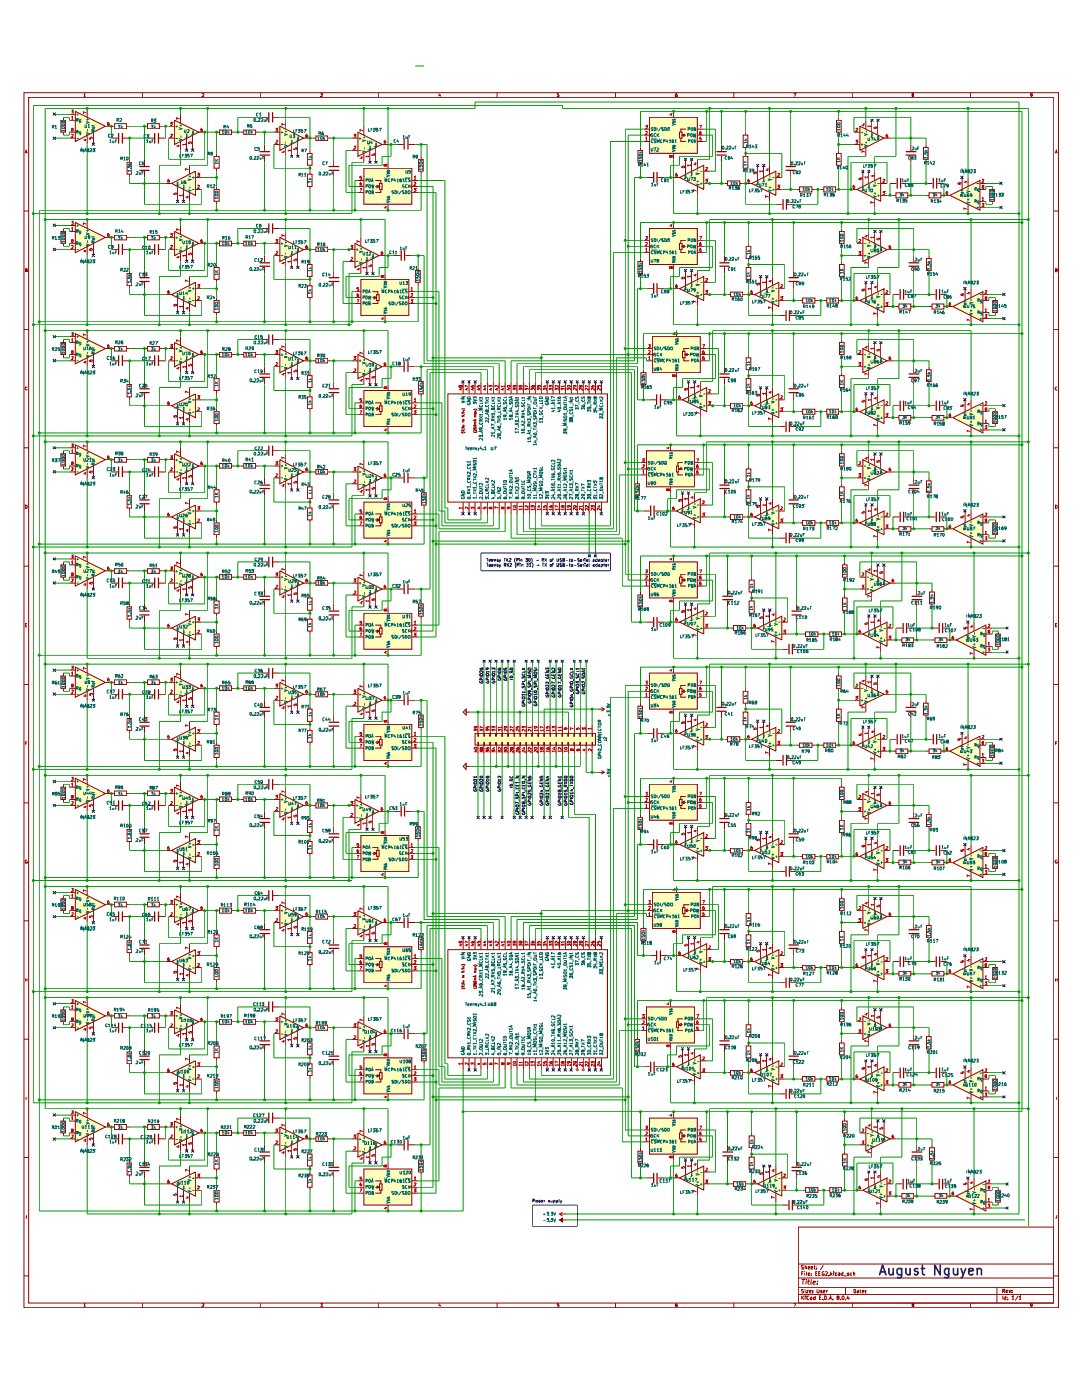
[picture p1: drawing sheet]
<svg xmlns="http://www.w3.org/2000/svg" width="216mm" height="279mm" viewBox="0 0 216 279" stroke-linecap="round" stroke-linejoin="round" font-family="sans-serif">
<g fill="none" stroke="#910000" stroke-width=".2">
<path d="M4.8 18.5h206.4v242.5h-206.4zM5.7 19.4h204.6v240.7h-204.6zM16.7 18.8l.2-.1v.6M16.7 19.3h.4M28.4 18.5v.9M40.3 18.8h.4l-.4 .5h.4M52 18.5v.9M64 18.7h.3l-.2 .2h.2v.3h-.3M75.6 18.5v.9M87.7 18.7l-.1 .4h.3M87.8 18.8v.5M99.2 18.5v.9"/>
<path d="M111.5 18.7h-.3v.2h.3v.3h-.3M122.8 18.5v.9M135.1 18.7h-.2l-.2 .2 .1 .4h.3v-.4l-.4 .1M146.4 18.5v.9M158.4 18.7h.4l-.3 .6M170.1 18.5v.9M182.2 18.9l-.2-.1 .3-.1v.2l-.3 .1 .1 .3h.2l-.1-.4M193.7 18.5v.9M206 18.9l-.4 .1v-.2l.4-.1v.4l-.3 .2M5 30.6l.2-.6 .3 .6M5.1 30.4h.3M210.5 30.6l.3-.6 .1 .6"/>
<path d="M210.6 30.4h.3M4.8 42.1h.9M5 53.9h.4v-.3h-.4v.6h.4l.1-.2-.2-.1M210.3 42.1h.9M210.6 53.9h.3v-.2l-.3-.1v.6h.3v-.2l-.1-.1M4.8 65.7h.9M5.5 77.3h-.5l.1 .5h.4M210.3 65.7h.9M210.9 77.3h-.2a.33 .33 0 0 0-.1 .3 .33 .33 0 0 0 .3 .3v-.1M4.8 89.4h.9M210.3 89.4h.9M4.8 113h.9"/>
<path d="M5 100.8a.35 .35 0 0 1 .5 .3 .35 .35 0 0 1-.5 .4zM210.3 113h.9M210.6 100.8l.3 .2v.3l-.2 .2zM4.8 136.6h.9M5.1 124.8h.2M5.4 124.4h-.3v.7h.3M210.3 136.6h.9M210.6 124.8h.3M210.9 124.4h-.3v.7h.3M5.1 148.4h.2M5.4 148h-.3v.6M210.6 148.4h.3"/>
<path d="M210.9 148h-.3v.6M4.8 160.2h.9M5.4 171.7h-.3l-.1 .5 .5 .1v-.3h-.2M210.3 160.2h.9M210.9 171.7h-.2l-.2 .2 .2 .4h.2v-.3M4.8 183.8h.9M5 195.3v.6M5 195.5h.4M5.4 195.3v.6M210.3 183.8h.9M210.6 195.5h.3M210.6 195.3v.6"/>
<path d="M210.9 195.3v.6M4.8 207.4h.9M5.2 218.9v.6M210.3 207.4h.9M210.8 218.9v.6M4.8 231h.9M210.3 231h.9M4.8 254.6h.9M5.3 242.5v.5l-.2 .1M159.3 244.9h51v15.2h-51zM159.3 258.4h51M159.3 256.9h51"/>
<path d="M159.3 255.1h51M159.3 252.3h51M160 258.6v.8M160 254.1h.2M160 255.4h.6M160.1 259l.3 .4M160.3 255.4l-.1 .9M160.3 257.3l-.4 .1 .4 .4v.1l-.4 .1M160.3 253.8h-.3v.8M160.3 252.6l-.2-.1-.2 .2 .4 .3v.2h-.4M160.4 258.6l-.4 .4M160.6 253.8v.1"/>
<path d="M160.6 254v.6M160.7 258.6v.1M160.7 257.3h.1M160.7 252.9h.2v.4M160.7 252.5v.8M160.7 257.5v.5M160.7 258.9v.5M160.9 255.4h.1M160.9 255.7l-.1 .6M160.9 257.5h.3l-.3 .5h.3M160.9 253.8l.1 .8M161.1 255.7h.4"/>
<path d="M161.2 254.3l.4-.1-.1-.2-.3 .1v.4h.4M161.2 253l.4-.1-.1-.1-.3 .1v.3h.4M161.4 255.4l-.2 .7 .3 .2M161.4 258.7l-.2-.1-.2 .2v.4l.2 .2 .2-.1M161.5 257.8l.3-.1v-.2h-.2l-.1 .4 .3 .1M161.8 259h.2v.4M161.8 253l.4-.1-.1-.1-.3 .1v.3h.4M161.9 255.4v.9M161.9 254.5v.1M161.9 254.1h.1M162 259h-.2l-.1 .2 .1 .2 .2-.1M162.2 257.9v.1"/>
<path d="M162.2 257.6v.1M162.2 255.9h.5l-.1-.2h-.3l-.1 .4v.2h.4M162.4 252.8h.3M162.5 252.5v.7l.2 .1M162.7 259h-.4l.1 .4 .3-.1M162.7 258.6v.8M162.8 254.1h.2M162.9 253.2v.1M162.9 252.9h.1M163 257.3l.1 .7h.3v-.7M163.1 256.2v.1M163.1 253.8h-.3v.8h.3"/>
<path d="M163.2 255.7v.1M163.4 254.1h.2M163.5 259h.3M163.7 253.8h-.3v.8h.3M163.9 258.6h-.4v.8h.4M164 257.6l-.1-.1-.2 .2 .3 .2v.1h-.3M164.2 259.3v.1M164.3 257.8l.3-.1-.1-.2h-.1l-.1 .4 .3 .1M164.3 252.5l-.6 .9M164.4 253.9l-.2-.1-.2 .2v.5h.5v-.3h-.2M164.5 258.6l.4 .2v.4l-.2 .2h-.2zM164.7 253.9l.3-.1 .1 .2-.4 .6h.4"/>
<path d="M165 257.5v.5M165.1 257.5l-.1 .2M165.2 259.3v.1M165.4 254.5v.1M165.5 259.4l.2-.8 .2 .8M165.6 259.1h.3M165.7 253.8v.8M165.8 254.3l.3 .3M166.1 254l-.4 .3M166.2 259.3v.1M166.3 253.8v.1M166.3 254v.6"/>
<path d="M167 254.1h-.3v.4h.3M167.2 259l-.2-.3 .3-.1 .1 .2-.1 .2h-.3v.3l.2 .1 .2-.2-.1-.2M167.3 254.1h.3v.5M167.6 254.2l-.3 .1v.3l.3-.1M167.7 259.3v.1M168.2 258.6a.41 .41 0 0 1 .2 .4 .41 .41 0 0 1-.2 .4l-.2-.2v-.4zM168.2 254.1l-.2-.1-.1 .2 .1 .4 .2-.1M168.2 253.8v.8M168.4 254.6h.6M168.7 259.3v.1M168.7 256.9v1.5M169.2 258.6l-.2 .5h.5"/>
<path d="M169.4 254.1h-.4l.1 .2h.3l-.1 .3-.3-.1M169.4 258.9v.5M170 254.1l-.2-.1-.2 .2 .2 .4 .2-.1M170.3 254.1h.3v.5M170.3 253.8v.8M170.4 257.3l.3 .1-.1 .6h-.2zM171.1 257.6h.2v.4h-.2l-.1-.1 .3-.2M171.6 257.5h.2M171.7 257.3v.6l.1 .1M172.1 257.8l.3-.1-.1-.2-.2 .1v.4h.2M172.7 257.9v.1M172.7 257.6v.1"/>
<path d="M198.9 256.9v3.2M200.1 257.6h.3l.1-.3h-.4v.7M200.1 258.6v.8M200.2 257.6l.3 .4M200.7 259l-.2-.1-.1 .1 .1 .4 .2-.1M200.7 258.6v.8M200.7 257.7l.4-.1-.1-.1-.3 .1v.3l.4 .1M201 259.3v.1M201 259h.1M201.3 257.5l.2 .5 .2-.5M201.9 258.9l.2-.3v.8M201.9 259.4h.4"/>
<path d="M201.9 257.9v.1M201.9 257.6h.1M203.2 258.6l-.6 .9M203.3 258.9l.3-.3v.8M203.3 259.4h.5M210.3 254.6h.9M210.9 242.5v.5l-.3 .1M16.7 260.3l.2-.2v.6M16.7 260.7h.4M28.4 260.1v.9M40.3 260.2h.4l-.4 .5h.4M52 260.1v.9"/>
<path d="M64 260.1h.3l-.2 .3 .2 .1v.2h-.3M75.6 260.1v.9M87.7 260.1l-.1 .5h.3M87.8 260.4v.3M99.2 260.1v.9M111.5 260.1h-.3v.4l.3-.1v.2l-.3 .1M122.8 260.1v.9M135.1 260.1l-.4 .3v.2l.4 .1v-.3l-.4 .1M146.4 260.1v.9M158.4 260.1h.4l-.3 .6M170.1 260.1v.9M182.2 260.4l-.2-.1 .2-.2 .1 .3-.3 .2 .1 .1h.2l-.1-.3"/>
<path d="M193.7 260.1v.9M206 260.4l-.3 .2-.1-.4h.4v.4l-.3 .1"/>
</g>
<g fill="#ffb">
<path d="M71.4 26.4l4.8 2.4-4.8 2.4z"/>
<path d="M72.6 122.4h9.6v7.2h-9.6z"/>
<path d="M71.4 115.2l4.8 2.4-4.8 2.3z"/>
<path d="M72.6 100.2h9.6v7.2h-9.6z"/>
<path d="M71.4 93l4.8 2.4-4.8 2.3z"/>
<path d="M72.6 77.9h9.6v7.2h-9.6z"/>
<path d="M72 55.8h9.6v7.1h-9.6z"/>
<path d="M70.8 48.6l4.8 2.4-4.8 2.4z"/>
<path d="M71.4 70.7l4.8 2.5-4.8 2.4z"/>
<path d="M72.6 33.6h9.6v7.2h-9.6z"/>
<path d="M15 111l6 2.9-6 3.1z"/>
<path d="M34.8 112.7l4.9 2.5-4.9 2.4z"/>
<path d="M15 88.8l6 2.9-6 3.1z"/>
<path d="M34.8 90.6l4.9 2.4-4.9 2.4z"/>
<path d="M34.2 103.2l4.8-2.4v4.7z"/>
<path d="M34.2 125.3l4.8-2.3v4.7z"/>
<path d="M55.8 113.9l4.8 2.5-4.8 2.3z"/>
<path d="M55.8 91.7l4.8 2.5-4.8 2.4z"/>
<path d="M15 66.6l6 3-6 3z"/>
<path d="M34.8 68.4l4.9 2.3-4.9 2.5z"/>
<path d="M34.2 81l4.8-2.4v4.8z"/>
<path d="M55.8 69.6l4.8 2.4-4.8 2.4z"/>
<path d="M15 44.4l6 3-6 3z"/>
<path d="M34.8 46.2l4.9 2.4-4.9 2.4z"/>
<path d="M34.2 58.8l4.8-2.5v4.9z"/>
<path d="M55.8 47.4l4.8 2.4-4.8 2.4z"/>
<path d="M15 22.2l6 3-6 3z"/>
<path d="M34.8 24l4.9 2.4-4.9 2.4z"/>
<path d="M34.2 36.6l4.8-2.4v4.8z"/>
<path d="M55.8 25.2l4.8 2.4-4.8 2.4z"/>
<path d="M150.6 103.2l4.8-2.4v4.7z"/>
<path d="M172.2 91.7l4.8 2.5-4.8 2.4z"/>
<path d="M171.6 104.4l4.8-2.4v4.7z"/>
<path d="M190.1 105.5l6-2.9v6z"/>
<path d="M172.2 69.6l4.8 2.4-4.8 2.4z"/>
<path d="M171.6 82.2l4.8-2.4v4.7z"/>
<path d="M190.1 83.4l6-3v6z"/>
<path d="M150 36.6l4.8-2.4v4.8z"/>
<path d="M171.6 25.2l4.8 2.4-4.8 2.4z"/>
<path d="M171 37.8l4.7-2.4v4.8z"/>
<path d="M189.5 39l6-3v6z"/>
<path d="M150.6 81l4.8-2.4v4.8z"/>
<path d="M150.6 58.8l4.8-2.5v4.9z"/>
<path d="M172.2 47.4l4.8 2.4-4.8 2.4z"/>
<path d="M171.6 60l4.8-2.4v4.8z"/>
<path d="M190.1 61.2l6-3v6z"/>
<path d="M151.2 125.3l4.8-2.3v4.7z"/>
<path d="M172.8 113.9l4.8 2.5-4.8 2.3z"/>
<path d="M172.2 126.5l4.8-2.3v4.8z"/>
<path d="M190.8 127.7l5.9-2.9v6z"/>
<path d="M130.2 67.2h9.5v7.2h-9.5z"/>
<path d="M135.6 35.4l4.8-2.4v4.8z"/>
<path d="M129.6 23.4h9.5v7.2h-9.5z"/>
<path d="M129.6 45.6h9.5v7.2h-9.5z"/>
<path d="M135.6 57.6l4.8-2.4v4.8z"/>
<path d="M136.2 79.8l4.8-2.5v4.9z"/>
<path d="M135 102l4.7-2.5v4.9z"/>
<path d="M129 90h9.6v7.2h-9.6z"/>
<path d="M135.6 124.2l4.8-2.4v4.7z"/>
<path d="M129.6 112.1h9.5v7.2h-9.5z"/>
<path d="M34.8 134.9l4.9 2.5-4.9 2.3z"/>
<path d="M55.8 136.2l4.8 2.4-4.8 2.3z"/>
<path d="M15 133.1l6 3.1-6 2.9z"/>
<path d="M15 155.3l6 3.1-6 2.9z"/>
<path d="M71.4 137.4l4.8 2.3-4.8 2.4z"/>
<path d="M34.2 147.5l4.8-2.3v4.7z"/>
<path d="M34.8 179.4l4.9 2.3-4.9 2.4z"/>
<path d="M34.2 169.7l4.8-2.4v4.9z"/>
<path d="M34.8 157.1l4.9 2.5-4.9 2.3z"/>
<path d="M34.2 191.9l4.8-2.4v4.9z"/>
<path d="M15 221.9l6 3-6 3z"/>
<path d="M34.8 223.7l4.9 2.4-4.9 2.4z"/>
<path d="M34.2 214.1l4.8-2.4v4.8z"/>
<path d="M34.8 201.5l4.9 2.4-4.9 2.4z"/>
<path d="M15 177.5l6 3.1-6 2.9z"/>
<path d="M34.2 236.3l4.8-2.4v4.8z"/>
<path d="M15 199.7l6 3-6 3z"/>
<path d="M72.6 211.1h9.6v7.2h-9.6z"/>
<path d="M55.8 224.9l4.8 2.4-4.8 2.4z"/>
<path d="M55.8 202.7l4.8 2.4-4.8 2.4z"/>
<path d="M71.4 203.9l4.8 2.4-4.8 2.4z"/>
<path d="M72.6 233.3h9.6v7.2h-9.6z"/>
<path d="M71.4 226.1l4.8 2.4-4.8 2.4z"/>
<path d="M72.6 188.9h9.6v7.2h-9.6z"/>
<path d="M72 166.8h9.6v7.1h-9.6z"/>
<path d="M55.8 180.6l4.8 2.3-4.8 2.4z"/>
<path d="M71.4 181.7l4.8 2.4-4.8 2.5z"/>
<path d="M72.6 144.6h9.6v7.2h-9.6z"/>
<path d="M70.8 159.6l4.8 2.3-4.8 2.4z"/>
<path d="M55.8 158.4l4.8 2.3-4.8 2.4z"/>
<path d="M171.6 215.3l4.8-2.4v4.8z"/>
<path d="M172.2 202.7l4.8 2.4-4.8 2.4z"/>
<path d="M190.1 194.4l6-3.1v6z"/>
<path d="M171.6 193.1l4.8-2.4v4.8z"/>
<path d="M190.8 238.7l5.9-3v6z"/>
<path d="M172.8 224.9l4.8 2.4-4.8 2.4z"/>
<path d="M172.2 237.5l4.8-2.4v4.8z"/>
<path d="M190.1 216.5l6-3v6z"/>
<path d="M171.6 170.9l4.8-2.4v4.9z"/>
<path d="M172.2 180.6l4.8 2.3-4.8 2.4z"/>
<path d="M172.2 158.4l4.8 2.3-4.8 2.4z"/>
<path d="M171 148.7l4.7-2.4v4.9z"/>
<path d="M150 147.5l4.8-2.3v4.7z"/>
<path d="M150.6 169.7l4.8-2.4v4.9z"/>
<path d="M171.6 136.2l4.8 2.4-4.8 2.3z"/>
<path d="M150.6 191.9l4.8-2.4v4.9z"/>
<path d="M150.6 214.1l4.8-2.4v4.8z"/>
<path d="M135.6 235.1l4.8-2.4v4.8z"/>
<path d="M151.2 236.3l4.8-2.4v4.8z"/>
<path d="M136.2 190.7l4.8-2.4v4.8z"/>
<path d="M129.6 223.1h9.5v7.2h-9.5z"/>
<path d="M129 201h9.6v7.2h-9.6z"/>
<path d="M135 212.9l4.7-2.4v4.8z"/>
<path d="M130.2 178.1h9.5v7.2h-9.5z"/>
<path d="M135.6 146.3l4.8-2.3v4.7z"/>
<path d="M129.6 134.3h9.5v7.2h-9.5z"/>
<path d="M129.6 156.5h9.5v7.2h-9.5z"/>
<path d="M135.6 168.5l4.8-2.3v4.7z"/>
<path d="M190.1 172.2l6-3.1v6z"/>
<path d="M189.5 149.9l6-3v6.1z"/>
<path d="M94.8 146.3h24v2.4h-24z"/>
</g>
<g fill="none" stroke="#910000" stroke-width=".2">
<path d="M12.1 24h1v2.4h-1zM12.7 23.4v.6M12.7 26.4v.6M13.8 27.6h1.2M13.8 24h1.2M13.8 22.8h1.2M13.8 26.4h1.2M15 22.2l6 3-6 3zM17.4 21.6v1.8M17.4 27v1.8M18.7 26.4v2.4M21 25.2h1.8"/>
<path d="M22.2 27.6h1.4M22.8 24.7h2.5v1h-2.5zM24.5 27.6h1.4M25.3 25.2h.6M25.4 32.4h.9v2.4h-.9zM25.9 31.8v.6M25.9 34.8v.6M28.8 31.8v1.3M28.8 34.1v1.3M28.8 25.2h.6M29.4 24.7h2.4v1h-2.4zM29.4 27.6h1.4"/>
<path d="M31.7 27.6h1.4M31.8 25.2h.7M33.1 36.6h1.1M33.7 27.6h1.1M33.7 25.2h1.1M34.2 36.6l4.8-2.4v4.8zM34.8 24l4.9 2.4-4.9 2.4zM35.4 37.2v3M36 22.8v1.8M36 28.2v1.8M36.6 37.8v2.4M37.2 27.6v2.4"/>
<path d="M37.8 33v1.8M37.8 38.4v1.8M38.4 27v3M39 37.8h1.3M39 35.4h1.3M39.7 26.4h1.2M42.7 37.8h1v2.4h-1zM42.7 31.2h1v2.4h-1zM43.2 30.6v.6M43.2 33.6v.6M43.2 37.2v.6M43.2 26.4h.6"/>
<path d="M43.8 26h2.4v.9h-2.4zM46.2 26.4h.7M48 26.4h.6M48.6 26h2.4v.9h-2.4zM51 26.4h.6M52.2 23.4h1.4M52.8 28.8v1.3M52.8 31.1v1.3M54.5 23.4h1.3M54.7 28.8h1.1M54.7 26.4h1.1M55.8 25.2l4.8 2.4-4.8 2.4z"/>
<path d="M57 24v1.8M57 29.4v1.8M58.2 28.8v2.4M59.4 28.2v3M60.6 27.6h1.2M61.3 34.8h1v2.4h-1zM61.3 30.6h1v2.4h-1zM61.8 30v.6M61.8 33v.6M61.8 34.2v.6M61.8 37.2v.6M62.4 27.6h.6"/>
<path d="M63 27.1h2.4v1h-2.4zM65.4 27.6h.6M66.6 31.8v1.3M66.6 34.1v1.3M70.2 30h1.2M70.2 27.6h1.2M71.4 26.4l4.8 2.4-4.8 2.4zM71.4 37.2h1.2M71.4 36h1.2M71.4 38.4h1.2M72.6 33.6h9.6v7.2h-9.6zM72.6 25.2v1.8"/>
<path d="M72.6 30.6v1.8M73.8 30v2.4M74.9 36h1.1v.6M74.9 37.2h.3M75 29.4v3M75.2 37l.5 .2-.5 .3zM75.7 36.6h.5v1.2h-.5zM76 37.8v.6h-1.1M76.2 28.8h1.2M77.4 32.4v1.2M79.2 28.8h1.4M81.5 28.8h1.3"/>
<path d="M82.2 37.2h1.2M82.2 36h1.2M82.2 36.9l-.3 .3 .3 .3M82.2 38.4h1.2M83.5 31.8h1v2.4h-1zM84 31.2v.6M84 34.2v.6M127.3 30h.9v2.4h-.9zM127.8 29.4v.6M127.8 32.4v.6M128.4 27h1.2M128.4 28.2h1.2"/>
<path d="M128.4 25.8h1.2M129 35.4h1.3M129.6 23.4h9.5v7.2h-9.5zM129.6 26.7l.3 .3-.3 .3M131.3 35.4h1.2M134.4 35.4h1.2M134.4 22.2v1.2M134.4 30.6v1.2M135.6 26.4h.5v1.2h-.5zM135.6 35.4l4.8-2.4v4.8zM135.8 27.6v.6h1.1M136.1 27l.4-.2v.4z"/>
<path d="M136.5 27h.4M136.8 31.8v3M136.9 25.8h-1.1v.6M138 31.8v2.4M139.1 31.8v1.8M139.1 37.2v1.8M139.1 27h1.3M139.1 28.2h1.3M139.1 25.8h1.3M140.4 36.6h1.2M140.4 34.2h1.2M144 28.8v1.3"/>
<path d="M144 31.1v1.3M144.6 36.6h.6M145.2 36.1h2.4v.9h-2.4zM147.6 36.6h.6M148.3 31.2h.9v2.4h-.9zM148.3 27h.9v2.4h-.9zM148.8 36.6h1.2M148.8 26.4v.6M148.8 29.4v.6M148.8 30.6v.6M148.8 33.6v.6M150 36.6l4.8-2.4v4.8z"/>
<path d="M151.2 33v3M152.4 33v2.4M153.5 33v1.8M153.5 38.4v1.8M154.8 37.8h1.2M154.8 35.4h1.2M157.8 31.8v1.3M157.8 34.1v1.3M159 37.8h.6M159.6 37.3h2.4v1h-2.4zM162 37.8h.6M163.8 37.8h.6"/>
<path d="M164.4 37.3h2.4v1h-2.4zM166.8 37.8h.5M166.9 30.6h1v2.4h-1zM166.9 24h1v2.4h-1zM167.3 23.4v.6M167.3 26.4v.6M167.3 30v.6M167.3 33v.6M169.8 37.8h1.2M170.4 28.8h1.2M170.4 26.4h1.2M171 37.8l4.7-2.4v4.8z"/>
<path d="M171.6 25.2l4.8 2.4-4.8 2.4zM172.2 34.2v3M172.8 24v1.8M172.8 29.4v1.8M173.4 34.2v2.4M173.9 24v2.4M174.5 34.2v1.8M174.5 39.6v1.8M175.1 24v3M175.7 36.6h1.3M175.7 39h1.3M176.4 27.6h1.2"/>
<path d="M177.6 36.6h1.3M178.2 39h.6M178.8 38.5h2.3v1h-2.3zM179.9 36.6h1.2M181.1 39h.6M181.7 28.8v1.3M181.7 31.1v1.3M184.3 29.4h.9v2.4h-.9zM184.8 36.6h1.3M184.8 39h.6M184.8 28.8v.6M184.8 31.8v.6"/>
<path d="M185.4 38.5h2.3v1h-2.3zM187.1 36.6h1.2M187.7 39h1.8M189.5 39l6-3v6zM192 35.4v2.4M193.2 35.4v1.8M195.5 37.8h1.2M195.5 36.6h1.2M197.5 37.8h.9v2.4h-.9zM198 37.2v.6M12.1 46.2h1v2.4h-1zM12.7 45.6v.6"/>
<path d="M12.7 48.6v.5M13.8 49.8h1.2M13.8 46.2h1.2M13.8 45h1.2M13.8 48.6h1.2M15 44.4l6 3-6 3zM17.4 43.8v1.8M17.4 49.1v1.9M18.7 48.6v2.4M21 47.4h1.8M22.2 49.8h1.4M22.8 46.9h2.5v1h-2.5z"/>
<path d="M24.5 49.8h1.4M25.3 47.4h.6M25.4 54.6h.9v2.4h-.9zM25.9 54v.6M25.9 57v.6M28.8 54v1.3M28.8 56.3v1.3M28.8 47.4h.6M29.4 46.9h2.4v1h-2.4zM29.4 49.8h1.4M31.7 49.8h1.4M31.8 47.4h.7"/>
<path d="M33.1 58.8h1.1M33.7 49.8h1.1M33.7 47.4h1.1M34.2 58.8l4.8-2.5v4.9zM34.8 46.2l4.9 2.4-4.9 2.4zM35.4 59.4v3M36 45v1.8M36 50.4v1.8M36.6 60v2.4M37.2 49.8v2.4M37.8 55.2v1.8M38.4 49.1v3.1"/>
<path d="M39 60h1.3M39 57.6h1.3M39.7 48.6h1.2M42.7 60h1v2.4h-1zM42.7 53.4h1v2.4h-1zM43.2 40.2v.6M43.2 52.8v.6M43.2 55.8v.5M43.2 59.4v.6M43.2 48.6h.6M43.8 48.1h2.4v1h-2.4zM46.2 48.6h.7"/>
<path d="M48 48.6h.6M48.6 48.1h2.4v1h-2.4zM51 48.6h.6M52.2 45.6h1.4M52.8 51v1.3M52.8 53.3v1.3M54.5 45.6h1.3M54.7 51h1.1M54.7 48.6h1.1M55.8 47.4l4.8 2.4-4.8 2.4zM57 46.2v1.8M57 51.6v1.8"/>
<path d="M58.2 51v2.4M59.4 50.4v3M60.6 49.8h1.2M61.3 57h1v2.4h-1zM61.3 52.8h1v2.4h-1zM61.8 52.2v.6M61.8 55.2v.6M61.8 56.3v.7M61.8 59.4v.6M62.4 49.8h.6M63 49.3h2.4v.9h-2.4zM65.4 49.8h.6"/>
<path d="M66.6 54v1.3M66.6 56.3v1.3M69.6 52.2h1.2M69.6 49.8h1.2M70.8 48.6l4.8 2.4-4.8 2.4zM70.8 59.4h1.2M70.8 58.2h1.2M72 55.8h9.6v7.1h-9.6zM72 47.4v1.7M72 52.8v1.8M73.2 52.2v2.4M74.3 58.2h1.1v.6"/>
<path d="M74.3 59.4h.3M74.4 51.6v3M74.6 59.1l.5 .3-.5 .2zM75.1 58.8h.5v1.2h-.5zM75.4 60v.6h-1.1M75.6 51h1.2M76.8 54.6v1.2M77.4 40.8v1.2M78.6 51h1.4M80.9 51h1.3M81.6 59.4h1.2M81.6 58.2h1.2"/>
<path d="M81.6 59.1l-.3 .3 .3 .2M82.9 54h1v2.3h-1zM83.4 53.4v.6M83.4 56.3v.7M127.3 52.2h.9v2.4h-.9zM127.8 51.6v.6M127.8 54.6v.6M128.4 49.1h1.2M128.4 50.4h1.2M128.4 48h1.2M129 57.6h1.3M129.6 45.6h9.5v7.2h-9.5z"/>
<path d="M129.6 48.9l.3 .2-.3 .4M131.3 57.6h1.2M134.4 57.6h1.2M134.4 44.4v1.2M134.4 52.8v1.2M135.6 48.6h.5v1.2h-.5zM135.6 57.6l4.8-2.4v4.8zM135.8 49.8v.6h1.1M136.1 49.1l.4-.1v.4zM136.5 49.1h.4M136.8 54v3M136.9 48h-1.1v.6"/>
<path d="M138 54v2.3M139.1 54v1.8M139.1 59.4v1.8M139.1 49.1h1.3M139.1 50.4h1.3M139.1 48h1.3M140.4 58.8h1.2M140.4 56.3h1.2M144.6 51v1.3M144.6 53.3v1.3M145.2 58.8h.6M145.8 58.3h2.4v.9h-2.4z"/>
<path d="M148.2 58.8h.6M148.9 53.4h.9v2.4h-.9zM148.9 49.1h.9v2.5h-.9zM149.4 58.8h1.2M149.4 48.6v.5M149.4 51.6v.6M149.4 52.8v.6M149.4 55.8v.5M150.6 58.8l4.8-2.5v4.9zM151.8 55.2v3M153 55.2v2.4M154.1 55.2v1.8"/>
<path d="M154.8 40.8h1.3M155.4 60h1.2M155.4 57.6h1.2M157 40.8h1.4M158.4 54v1.3M158.4 56.3v1.3M159.6 60h.5M160.1 59.5h2.5v1h-2.5zM162.6 60h.6M164.4 60h.6M165 59.5h2.3v1h-2.3zM167.3 60h.6"/>
<path d="M167.5 52.8h.9v2.4h-.9zM167.5 46.2h.9v2.4h-.9zM167.9 45.6v.6M167.9 48.6v.5M167.9 52.2v.6M167.9 55.2v.6M170.4 60h1.2M171 51h1.2M171 48.6h1.2M171.6 60l4.8-2.4v4.8zM172.2 47.4l4.8 2.4-4.8 2.4zM172.8 56.3v3.1"/>
<path d="M173.4 46.2v1.8M173.4 51.6v1.8M173.9 56.3v2.5M174.5 46.2v2.4M175.1 56.3v1.9M175.7 46.2v2.9M176.4 58.8h1.2M177 49.8h1.2M178.2 58.8h1.3M180.5 58.8h1.2M182.3 51v1.3M182.3 53.3v1.3"/>
<path d="M184.9 51.6h.9v2.4h-.9zM185.4 58.8h1.2M185.4 51v.6M185.4 54v.6M187.7 58.8h1.2M192.6 57.6v2.4M193.2 40.8v1.8M193.8 57.6v1.8M195.5 40.2h1.2M195.5 41.4h1.2M196.1 60h1.2M196.1 58.8h1.2"/>
<path d="M198 40.2v.6M198.1 60h.9v2.4h-.9zM198.6 59.4v.6M12.1 68.4h1v2.3h-1zM12.7 67.8v.6M12.7 70.7v.7M13.8 72h1.2M13.8 68.4h1.2M13.8 67.2h1.2M13.8 70.7h1.2M15 66.6l6 3-6 3zM17.4 66v1.8"/>
<path d="M17.4 71.4v1.8M18.7 70.7v2.5M21 69.6h1.8M22.2 72h1.4M22.8 69.1h2.5v1h-2.5zM24.5 72h1.4M25.3 69.6h.6M25.4 76.8h.9v2.4h-.9zM25.9 76.2v.6M25.9 79.2v.6M28.8 76.2v1.3M28.8 78.4v1.4"/>
<path d="M28.8 69.6h.6M29.4 69.1h2.4v1h-2.4zM29.4 72h1.4M31.7 72h1.4M31.8 69.6h.7M33.7 72h1.1M33.7 69.6h1.1M34.8 68.4l4.9 2.3-4.9 2.5zM36 67.2v1.8M36 72.6v1.8M37.2 72v2.4M37.8 60.6v1.8"/>
<path d="M37.8 77.3v1.9M38.4 71.4v3M39 79.8h1.3M39.7 70.7h1.2M42.7 75.6h1v2.3h-1zM43.2 62.4v.5M43.2 75v.6M43.2 77.9v.7M43.2 70.7h.6M43.8 70.3h2.4v.9h-2.4zM46.2 70.7h.7M48 70.7h.6"/>
<path d="M48.6 70.3h2.4v.9h-2.4zM51 70.7h.6M52.2 67.8h1.4M52.8 73.2v1.3M52.8 75.5v1.3M54.5 67.8h1.3M54.7 73.2h1.1M54.7 70.7h1.1M55.8 69.6l4.8 2.4-4.8 2.4zM57 68.4v1.7M57 73.8v1.8M58.2 73.2v2.4"/>
<path d="M59.4 72.6v3M60.6 72h1.2M61.3 79.2h1v2.4h-1zM61.3 75h1v2.3h-1zM61.8 74.4v.6M61.8 77.3v.6M61.8 78.6v.6M62.4 72h.6M63 71.5h2.4v.9h-2.4zM65.4 72h.6M66.6 76.2v1.3M66.6 78.4v1.4"/>
<path d="M70.2 74.4h1.2M70.2 72h1.2M70.8 60.6h1.2M71.4 70.7l4.8 2.5-4.8 2.4zM72.6 77.9h9.6v7.2h-9.6zM72.6 69.6v1.8M72.6 75v1.8M73.8 74.4v2.4M75 73.8v3M76.2 73.2h1.2M76.8 62.9v1.3M77.4 76.8v1.1"/>
<path d="M79.2 73.2h1.4M81.5 73.2h1.3M81.6 60.6h1.2M83.5 76.2h1v2.4h-1zM84 75.6v.6M84 78.6v.6M89.4 78.6h31.8v21.6h-31.8zM92.4 76.2v2.4M93.6 76.2v2.4M94.8 76.2v2.4M96 76.2v2.4M97.2 76.2v2.4"/>
<path d="M98.4 76.2v2.4M99.6 76.2v2.4M100.8 76.2v2.4M102 76.2v2.4M103.2 76.2v2.4M104.4 76.2v2.4M105.6 76.2v2.4M106.8 76.2v2.4M108 76.2v2.4M109.2 76.2v2.4M110.4 76.2v2.4M111.6 76.2v2.4"/>
<path d="M112.8 76.2v2.4M114 76.2v2.4M115.2 76.2v2.4M116.4 76.2v2.4M117.6 76.2v2.4M118.8 76.2v2.4M120 76.2v2.4M121.2 78.6v21.6M127.9 74.4h1v2.4h-1zM128.4 73.8v.6M128.4 76.8v.5M129 72h1.2"/>
<path d="M129 69.6h1.2M129 70.7h1.2M129.6 79.8h1.3M130.2 67.2h9.5v7.2h-9.5zM130.2 70.5l.3 .2-.3 .4M131.9 79.8h1.3M135 79.8h1.2M135 66v1.2M135 74.4v1.2M136.2 70.1h.5v1.3h-.5zM136.2 79.8l4.8-2.5v4.9zM136.4 71.4v.6h1.1"/>
<path d="M136.7 70.7l.4-.1v.4zM137.1 70.7h.4M137.4 76.2v3M137.5 69.6h-1.1v.5M138.6 76.2v2.4M139.7 72h1.3M139.7 69.6h1.3M139.7 70.7h1.3M139.7 76.2v1.7M141 78.6h1.2M144.6 73.2v1.3M144.6 75.5v1.3"/>
<path d="M148.9 75.6h.9v2.3h-.9zM148.9 71.4h.9v2.4h-.9zM149.4 70.7v.7M149.4 73.8v.6M149.4 75v.6M149.4 77.9v.7M151.8 77.3v3.1M153 77.3v2.5M154.1 60.6v1.8M154.1 77.3v1.9M155.4 79.8h1.2M155.4 62.9h1.3"/>
<path d="M157.7 62.9h1.3M158.4 76.2v1.3M158.4 78.4v1.4M167.5 75h.9v2.3h-.9zM167.5 68.4h.9v2.3h-.9zM167.9 67.8v.6M167.9 70.7v.7M167.9 74.4v.6M167.9 77.3v.6M171 73.2h1.2M171 70.7h1.2M172.2 69.6l4.8 2.4-4.8 2.4z"/>
<path d="M172.8 78.6v3M173.4 68.4v1.7M173.4 73.8v1.8M173.9 78.6v2.4M174.5 68.4v2.3M175.1 61.8v1.7M175.1 78.6v1.8M175.7 68.4v3M176.4 61.2h1.2M177 72h1.2M178.8 61.2h.6M179.4 60.7h2.3v1h-2.3z"/>
<path d="M181.7 61.2h.6M182.3 73.2v1.3M182.3 75.5v1.3M184.9 73.8h.9v2.4h-.9zM185.4 73.2v.6M185.4 76.2v.6M185.4 61.2h.6M186 60.7h2.3v1h-2.3zM188.3 61.2h1.8M190.1 61.2l6-3v6zM192.6 79.8v2.4M193.8 62.9v1.9"/>
<path d="M193.8 79.8v1.8M196.1 62.4h1.2M196.1 63.5h1.2M198.6 62.4v.5M12.1 90.6h1v2.4h-1zM12.7 90v.6M12.7 93v.6M13.8 94.2h1.2M13.8 90.6h1.2M13.8 89.4h1.2M13.8 93h1.2M15 88.8l6 2.9-6 3.1z"/>
<path d="M17.4 88.2v1.8M17.4 93.6v1.8M18.7 93v2.4M21 91.7h1.8M22.2 94.2h1.4M22.8 91.3h2.5v.9h-2.5zM24.5 94.2h1.4M25.3 91.7h.6M25.4 98.9h.9v2.5h-.9zM25.9 98.3v.6M28.8 91.7h.6M28.8 98.3v1.4"/>
<path d="M29.4 91.3h2.4v.9h-2.4zM29.4 94.2h1.4M31.7 94.2h1.4M31.8 91.7h.7M33.1 81h1.1M33.7 94.2h1.1M33.7 91.7h1.1M34.2 81l4.8-2.4v4.8zM34.8 90.6l4.9 2.4-4.9 2.4zM35.4 81.6v2.9M36 89.4v1.7M36 94.8v1.8"/>
<path d="M36.6 82.2v2.3M37.2 94.2v2.4M37.8 82.8v1.7M37.8 99.5v1.9M38.4 93.6v3M39 82.2h1.3M39.7 93h1.2M42.7 97.7h1v2.5h-1zM42.7 82.2h1v2.3h-1zM43.2 81.6v.6M43.2 84.5v.6M43.2 97.2v.5"/>
<path d="M43.2 93h.6M43.8 92.5h2.4v.9h-2.4zM46.2 93h.7M48 93h.6M48.6 92.5h2.4v.9h-2.4zM51 93h.6M52.2 90h1.4M52.8 95.4v1.2M52.8 97.7v1.2M54.5 90h1.3M54.7 95.4h1.1M54.7 93h1.1"/>
<path d="M55.8 91.7l4.8 2.5-4.8 2.4zM57 90.6v1.7M57 96v1.7M58.2 95.4v2.3M59.4 94.8v2.9M60.6 94.2h1.2M61.3 97.2h1v2.3h-1zM61.8 81.6v.6M61.8 96.6v.6M61.8 99.5v.7M62.4 94.2h.6M63 93.7h2.4v.9h-2.4z"/>
<path d="M65.4 94.2h.6M66.6 98.3v1.4M70.2 96.6h1.2M70.2 94.2h1.2M71.4 93l4.8 2.4-4.8 2.3zM71.4 81.6h1.2M71.4 80.4h1.2M71.4 82.8h1.2M72.6 91.7v1.9M72.6 97.2v1.7M73.8 96.6v2.3M74.9 80.4h1.1v.6"/>
<path d="M74.9 81.6h.3M75 96v2.9M75.2 81.3l.5 .3-.5 .2zM75.7 81h.5v1.2h-.5zM76 82.2v.6h-1.1M76.2 95.4h1.2M77.4 85.1v1.3M77.4 98.9v1.3M79.2 95.4h1.4M81.5 95.4h1.3M82.2 81.6h1.2M82.2 80.4h1.2"/>
<path d="M82.2 81.2l-.3 .4 .3 .2M82.2 82.8h1.2M84.1 98.3h.9v2.5h-.9zM84.6 97.7v.6M92.1 86.2l.1 .2 .6-.2M92.1 81.7h.7M92.2 86.1v-.3l.1 .2 .2-.2 .1 .3M92.2 85.2v.2h.4v-.3h-.3l.1 .3M92.2 82.9l.1 .3v-.3l.2-.1 .1 .4M92.2 82.3l.1 .2v-.2l.2-.1 .1 .3M92.3 84.8l.3 .1-.3 .1M92.3 83.7h.3v.2h-.3z"/>
<path d="M92.3 81.8l.3 .1-.3 .1M92.3 84.1v.2M92.6 85.6h.1M92.6 84.1l-.4 .1M92.6 82.7h.1M94.4 86.1a.48 .48 0 0 0 .8 0M94.4 81.7h.8M94.5 85.3v.3h.3v-.3l.2 .1v.2M94.5 84.9l.4-.1 .1 .2h-.5zM94.7 84.6h.3M94.7 83.2h.3M94.7 81.9l.3 .3"/>
<path d="M94.8 82.3l.1 .3 .1-.1v-.2M94.9 83.8v.2M95 85.7v.4l-.2-.4-.3 .1 .1 .2M95 84.4h-.2v.2M95 84.2h-.3l.1 .2M95 83.7l-.5 .2 .5 .1M95 83h-.3l.1 .2M95 82.8h-.3l.1 .2M95 82.3h-.3v.3M95 81.9l-.3 .3M126.7 96.6h.9v2.3h-.9zM127.2 96v.6"/>
<path d="M127.2 98.9v.6M127.8 93.6h1.2M127.8 94.8h1.2M127.8 92.3h1.2M129 90h9.6v7.2h-9.6zM129 93.3l.2 .3-.2 .3M133.8 88.8v1.2M133.8 97.2v1.1M135 93h.4v1.2h-.4zM135.3 94.2v.6h1M135.4 93.6l.5-.3v.5zM135.9 93.6h.4"/>
<path d="M136.2 98.3v3.1M136.3 92.3h-1v.7M137.4 98.3v2.5M138.6 98.3v1.9M138.6 93.6h1.1M138.6 94.8h1.1M138.6 92.3h1.1M139.7 81.6v1.8M141 81h1.2M144.6 95.4v1.2M144.6 97.7v1.2M145.2 81h.6"/>
<path d="M145.8 80.5h2.4v1h-2.4zM148.2 81h.6M148.9 97.7h.9v2.5h-.9zM148.9 93.6h.9v2.4h-.9zM149.4 81h1.2M149.4 93v.6M149.4 96v.6M149.4 97.2v.5M150.6 81l4.8-2.4v4.8zM151.8 99.5v3.1M153 99.5v2.5M154.1 82.8v1.7"/>
<path d="M154.1 99.5v1.9M155.4 82.2h1.2M155.4 85.1h1.3M157.7 85.1h1.3M158.4 98.3v1.4M159.6 82.2h.5M160.1 81.7h2.5v1h-2.5zM162.6 82.2h.6M164.4 82.2h.6M165 81.7h2.3v1h-2.3zM167.3 82.2h.6M167.5 97.2h.9v2.3h-.9z"/>
<path d="M167.5 90.6h.9v2.4h-.9zM167.9 90v.6M167.9 93v.6M167.9 96.6v.6M167.9 99.5v.7M170.4 82.2h1.2M171 95.4h1.2M171 93h1.2M171.6 82.2l4.8-2.4v4.7zM172.2 91.7l4.8 2.5-4.8 2.4zM173.4 90.6v1.7M173.4 96v1.7"/>
<path d="M174.5 90.6v2.4M175.1 83.9v1.9M175.7 90.6v3M176.4 81h1.2M176.4 83.4h1.2M177 94.2h1.2M178.2 81h1.3M178.8 83.4h.6M179.4 82.9h2.3v1h-2.3zM180.5 81h1.2M181.7 83.4h.6M182.3 95.4v1.2"/>
<path d="M182.3 97.7v1.2M184.9 96h.9v2.3h-.9zM185.4 81h1.2M185.4 95.4v.6M185.4 98.3v.6M185.4 83.4h.6M186 82.9h2.3v1h-2.3zM187.7 81h1.2M188.3 83.4h1.8M190.1 83.4l6-3v6zM193.8 85.1v1.9M196.1 82.2h1.2"/>
<path d="M196.1 81h1.2M196.1 84.5h1.2M196.1 85.8h1.2M198.1 82.2h.9v2.3h-.9zM198.6 81.6v.6M198.6 84.5v.6M12.1 112.7h1v2.5h-1zM12.7 112.1v.6M12.7 115.2v.6M13.8 116.4h1.2M13.8 112.7h1.2M13.8 111.5h1.2"/>
<path d="M13.8 115.2h1.2M15 111l6 2.9-6 3.1zM17.4 110.4v1.7M17.4 115.8v1.8M18.7 115.2v2.4M21 113.9h1.8M22.2 116.4h1.4M22.8 113.5h2.5v.9h-2.5zM24.5 116.4h1.4M25.3 113.9h.6M25.9 101.4v.6M28.8 113.9h.6"/>
<path d="M28.8 100.6v1.4M29.4 113.5h2.4v.9h-2.4zM29.4 116.4h1.4M31.7 116.4h1.4M31.8 113.9h.7M33.1 103.2h1.1M33.7 116.4h1.1M33.7 113.9h1.1M34.2 103.2l4.8-2.4v4.7zM34.8 112.7l4.9 2.5-4.9 2.4zM35.4 103.8v2.9M36 111.5v1.8"/>
<path d="M36 117v1.7M36.6 104.4v2.3M37.2 116.4v2.3M37.8 104.9v1.8M38.4 115.8v2.9M39 104.4h1.3M39 102h1.3M39.7 115.2h1.2M42.7 119.9h1v2.5h-1zM42.7 104.4h1v2.3h-1zM43.2 100.2v.6M43.2 103.8v.6"/>
<path d="M43.2 106.7v.7M43.2 119.3v.6M43.2 115.2h.6M43.8 114.7h2.4v.9h-2.4zM46.2 115.2h.7M48 115.2h.6M48.6 114.7h2.4v.9h-2.4zM51 115.2h.6M52.2 112.1h1.4M52.8 117.6v1.3M52.8 119.8v1.3M54.5 112.1h1.3"/>
<path d="M54.7 117.6h1.1M54.7 115.2h1.1M55.8 113.9l4.8 2.5-4.8 2.3zM57 112.7v1.9M57 118.2v1.7M58.2 117.6v2.3M59.4 117v2.9M60.6 116.4h1.2M61.3 119.3h1v2.5h-1zM61.3 101.4h1v2.4h-1zM61.8 100.8v.6M61.8 103.8v.6"/>
<path d="M61.8 118.7v.6M62.4 116.4h.6M63 115.9h2.4v.9h-2.4zM65.4 116.4h.6M66.6 100.6v1.4M70.2 118.7h1.2M70.2 116.4h1.2M71.4 115.2l4.8 2.4-4.8 2.3zM71.4 103.8h1.2M71.4 102.6h1.2M71.4 104.9h1.2M72.6 100.2h9.6v7.2h-9.6z"/>
<path d="M72.6 113.9v1.9M72.6 119.3v1.8M73.8 118.7v2.4M74.9 102.6h1.1v.6M74.9 103.8h.3M75 118.2v2.9M75.2 103.5l.5 .3-.5 .2zM75.7 103.2h.5v1.2h-.5zM76 104.4v.5h-1.1M76.2 117.6h1.2M77.4 107.4v1.2M79.2 117.6h1.4"/>
<path d="M81.5 117.6h1.3M82.2 103.8h1.2M82.2 102.6h1.2M82.2 103.4l-.3 .4 .3 .3M82.2 104.9h1.2M84 119.9v.6M84.6 100.8v.6M92.4 100.2v2.4M93.6 100.2v2.4M94.8 100.2v2.4M96 100.2v2.4M97.2 100.2v2.4"/>
<path d="M98.4 100.2v2.4M99.6 100.2v2.4M100.8 100.2v2.4M102 100.2v2.4M103.2 100.2v2.4M104.4 100.2v2.4M105.6 100.2v2.4M106.8 100.2v2.4M108 100.2v2.4M109.2 100.2v2.4M110.4 100.2v2.4M111.6 100.2v2.4"/>
<path d="M112.8 100.2v2.4M114 100.2v2.4M115.2 100.2v2.4M116.4 100.2v2.4M117.6 100.2v2.4M118.8 100.2v2.4M120 100.2v2.4M127.3 118.7h.9v2.4h-.9zM127.8 118.2v.5M128.4 102h1.3M128.4 115.8h1.2M128.4 117h1.2"/>
<path d="M128.4 114.6h1.2M129.6 112.1h9.5v7.2h-9.5zM129.6 115.4l.3 .4-.3 .2M130.7 102h1.3M133.8 102h1.2M134.4 111v1.1M134.4 119.3v1.2M135 102l4.7-2.5v4.9zM135.6 115.2h.5v1.2h-.5zM135.8 116.4v.6h1.1M136.1 115.8l.4-.3v.5zM136.5 115.8h.4"/>
<path d="M136.9 114.6h-1.1v.6M138.6 103.8v1.7M139.1 115.8h1.3M139.1 117h1.3M139.1 114.6h1.3M139.7 103.2h1.3M139.7 100.8h1.3M145.2 103.2h.6M145.2 117.6v1.3M145.2 119.8v1.3M145.8 102.7h2.4v1h-2.4zM148.2 103.2h.6"/>
<path d="M149.4 103.2h1.2M149.4 100.2v.6M149.5 119.9h1v2.5h-1zM149.5 115.8h1v2.4h-1zM150 115.2v.6M150 118.2v.5M150 119.3v.6M150.6 103.2l4.8-2.4v4.7zM154.1 104.9v1.8M155.4 104.4h1.2M155.4 102h1.2M155.4 107.4h1.3"/>
<path d="M157.7 107.4h1.3M158.4 100.6v1.4M159.6 104.4h.5M160.1 103.8h2.5v1.1h-2.5zM162.6 104.4h.6M164.4 104.4h.6M165 103.8h2.3v1.1h-2.3zM167.3 104.4h.6M168.1 119.3h.9v2.5h-.9zM168.1 112.7h.9v2.5h-.9zM168.5 112.1v.6M168.5 115.2v.6"/>
<path d="M168.5 118.7v.6M170.4 104.4h1.2M171.6 104.4l4.8-2.4v4.7zM171.6 117.6h1.2M171.6 115.2h1.2M172.8 113.9l4.8 2.5-4.8 2.3zM172.8 100.8v3M173.9 100.8v2.4M173.9 112.7v1.9M173.9 118.2v1.7M175.1 100.8v1.8M175.1 106.1v1.9"/>
<path d="M175.1 112.7v2.5M176.4 103.2h1.2M176.4 105.5h1.2M176.4 112.7v3.1M177.6 116.4h1.2M178.2 103.2h1.3M178.8 105.5h.6M179.4 105.1h2.3v.9h-2.3zM180.5 103.2h1.2M181.7 105.5h.6M182.9 117.6v1.3M182.9 119.8v1.3"/>
<path d="M185.4 103.2h1.2M185.4 105.5h.6M185.5 118.2h1v2.3h-1zM186 105.1h2.3v.9h-2.3zM186 117.6v.6M187.7 103.2h1.2M188.3 105.5h1.8M190.1 105.5l6-2.9v6zM192.6 102v2.4M193.8 102v1.8M193.8 107.4v1.8M196.1 104.4h1.2"/>
<path d="M196.1 103.2h1.2M196.1 106.7h1.2M196.1 108h1.2M198.1 104.4h.9v2.3h-.9zM198.6 103.8v.6M198.6 106.7v.7M12.1 134.9h1v2.5h-1zM12.7 134.3v.6M12.7 137.4v.6M13.8 138.6h1.2M13.8 137.4h1.2M13.8 134.9h1.2"/>
<path d="M13.8 133.7h1.2M15 133.1l6 3.1-6 2.9zM17.4 132.5v1.8M17.4 138v1.7M18.7 137.4v2.3M21 136.2h1.8M22.2 138.6h1.4M22.8 135.7h2.5v.9h-2.5zM24.5 138.6h1.4M25.3 136.2h.6M25.4 121.1h.9v2.5h-.9zM25.9 120.5v.6"/>
<path d="M25.9 123.6v.6M28.8 120.5v1.4M28.8 122.8v1.4M28.8 136.2h.6M29.4 135.7h2.4v.9h-2.4zM29.4 138.6h1.4M31.7 138.6h1.4M31.8 136.2h.7M33.1 125.3h1.1M33.7 138.6h1.1M33.7 136.2h1.1M34.2 125.3l4.8-2.3v4.7z"/>
<path d="M34.8 134.9l4.9 2.5-4.9 2.3zM35.4 125.9v3.1M36 133.7v1.8M36 139.1v1.8M36.6 126.5v2.5M37.2 138.6v2.3M37.8 121.8v1.8M37.8 127.1v1.9M38.4 138v2.9M39 126.5h1.3M39 124.2h1.3M39.7 137.4h1.2"/>
<path d="M42.7 126.5h1v2.5h-1zM43.2 122.4v.6M43.2 125.9v.6M43.2 129v.6M43.2 137.4h.6M43.8 136.9h2.4v.9h-2.4zM46.2 137.4h.7M48 137.4h.6M48.6 136.9h2.4v.9h-2.4zM51 137.4h.6M52.2 134.3h1.4M52.8 139.7v1.4"/>
<path d="M54.5 134.3h1.3M54.7 137.4h1.1M54.7 139.7h1.1M55.8 136.2l4.8 2.4-4.8 2.3zM57 134.9v1.9M58.2 139.7v2.4M59.4 139.1v3M60.6 138.6h1.2M61.3 123.6h1v2.3h-1zM61.8 121.8v.6M61.8 123v.6M61.8 125.9v.6"/>
<path d="M62.4 138.6h.6M63 138h2.4v1.1h-2.4zM65.4 138.6h.6M66.6 120.5v1.4M66.6 122.8v1.4M70.2 138.6h1.2M71.4 137.4l4.8 2.3-4.8 2.4zM71.4 125.9h1.2M71.4 124.8h1.2M71.4 127.1h1.2M72.6 122.4h9.6v7.2h-9.6zM72.6 136.2v1.8"/>
<path d="M74.9 124.8h1.1v.5M74.9 125.9h.3M75.2 125.7l.5 .2-.5 .3zM75.7 125.3h.5v1.2h-.5zM76 126.5v.6h-1.1M76.2 139.7h1.2M77.4 121.1v1.3M77.4 129.6v1.2M79.2 139.7h1.4M81.5 139.7h1.3M82.2 125.9h1.2M82.2 124.8h1.2"/>
<path d="M82.2 125.7l-.3 .2 .3 .4M82.2 127.1h1.2M83.5 120.5h1v2.5h-1zM84 123v.6M127.8 121.1v.7M128.4 138h1.2M128.4 139.1h1.2M128.4 136.8h1.2M129 124.2h1.3M129.6 134.3h9.5v7.2h-9.5zM129.6 137.6l.3 .4-.3 .2M131.3 124.2h1.2"/>
<path d="M134.4 124.2h1.2M134.4 133.1v1.2M135.6 137.4h.5v1.2h-.5zM135.6 124.2l4.8-2.4v4.7zM135.8 138.6v.5h1.1M136.1 138l.4-.3v.5zM136.5 138h.4M136.8 120.5v3.1M136.9 136.8h-1.1v.6M138 120.5v2.5M139.1 120.5v1.9M139.1 125.9v1.8"/>
<path d="M139.1 138h1.3M139.1 139.1h1.3M139.1 136.8h1.3M140.4 125.3h1.2M140.4 123h1.2M144 139.7v1.4M145.8 125.3h.5M146.3 124.8h2.5v1.1h-2.5zM148.3 138h.9v2.3h-.9zM148.8 125.3h.6M148.8 137.4v.6M150 125.3h1.2"/>
<path d="M150 122.4v.6M151.2 125.3l4.8-2.3v4.7zM152.4 121.8v3M153.5 121.8v2.4M154.8 121.8v1.8M154.8 127.1v1.9M156 126.5h1.2M156 124.2h1.2M156 129.6h1.3M158.3 129.6h1.3M159 120.5v1.4M159 122.8v1.4"/>
<path d="M160.1 126.5h.6M160.7 126.1h2.5v.9h-2.5zM163.2 126.5h.6M165 126.5h.6M165.6 126.1h2.3v.9h-2.3zM166.9 134.9h1v2.5h-1zM167.3 134.3v.6M167.3 137.4v.6M167.9 126.5h.6M168.5 121.8v.6M170.4 137.4h1.2M170.4 139.7h1.2"/>
<path d="M171 126.5h1.2M171.6 136.2l4.8 2.4-4.8 2.3zM172.2 126.5l4.8-2.3v4.8zM172.8 134.9v1.9M173.4 123v2.9M173.9 134.9v2.5M174.5 123v2.3M175.1 134.9v3.1M175.7 123v1.8M175.7 128.3v1.9M176.4 138.6h1.2M177 125.3h1.2"/>
<path d="M177 127.7h1.2M178.8 125.3h1.2M179.4 127.7h.6M180 127.3h2.3v.9h-2.3zM181.1 125.3h1.2M181.7 139.7v1.4M182.3 127.7h.6M184.8 139.7v.6M186 125.3h1.2M186 127.7h.6M186 120.5v.6M186.6 127.3h2.3v.9h-2.3z"/>
<path d="M188.3 125.3h1.2M188.9 127.7h1.9M190.8 127.7l5.9-2.9v6zM193.2 124.2v2.3M194.4 124.2v1.7M194.4 129.6v1.8M196.7 126.5h1.3M196.7 125.3h1.3M196.7 129h1.3M196.7 130.2h1.3M198.7 126.5h.9v2.5h-.9zM199.2 125.9v.6"/>
<path d="M199.2 129v.6M12.1 157.1h1v2.5h-1zM12.7 156.5v.6M12.7 159.6v.5M13.8 157.1h1.2M13.8 155.9h1.2M13.8 159.6h1.2M15 155.3l6 3.1-6 2.9zM17.4 154.7v1.8M18.7 159.6v2.3M21 158.4h1.8M22.8 157.9h2.5v.9h-2.5z"/>
<path d="M25.3 158.4h.6M25.4 143.4h.9v2.4h-.9zM25.9 142.7v.7M25.9 145.8v.5M28.8 142.7v1.4M28.8 145v1.3M28.8 158.4h.6M29.4 157.9h2.4v.9h-2.4zM31.8 158.4h.7M33.1 147.5h1.1M33.7 158.4h1.1M34.2 147.5l4.8-2.3v4.7z"/>
<path d="M34.8 157.1l4.9 2.5-4.9 2.3zM35.4 148.1v3.1M36 155.9v1.9M36.6 148.7v2.5M37.8 144v1.8M37.8 149.3v1.9M39 148.7h1.3M39 146.3h1.3M39.7 159.6h1.2M42.7 142.1h1v2.5h-1zM42.7 148.7h1v2.5h-1zM43.2 141.5v.6"/>
<path d="M43.2 144.6v.6M43.2 148.1v.6M43.2 151.2v.6M43.2 159.6h.6M43.8 159h2.4v1h-2.4zM46.2 159.6h.7M48 159.6h.6M48.6 159h2.4v1h-2.4zM51 159.6h.6M52.2 156.5h1.4M52.8 142v1.4M54.5 156.5h1.3"/>
<path d="M54.7 159.6h1.1M55.8 158.4l4.8 2.3-4.8 2.4zM57 140.3v1.8M57 157.1v1.9M61.3 141.5h1v2.5h-1zM61.3 145.8h1v2.3h-1zM61.8 140.9v.6M61.8 144v.6M61.8 145.2v.6M61.8 148.1v.6M66.6 142.7v1.4M66.6 145v1.3"/>
<path d="M70.2 140.9h1.2M70.8 159.6l4.8 2.3-4.8 2.4zM71.4 148.1h1.2M71.4 146.9h1.2M71.4 149.3h1.2M72 158.4v1.7M72.6 144.6h9.6v7.2h-9.6zM72.6 141.5v1.9M73.8 140.9v2.5M74.9 146.9h1.1v.6M74.9 148.1h.3M75 140.3v3.1"/>
<path d="M75.2 147.9l.5 .2-.5 .3zM75.7 147.5h.5v1.2h-.5zM76 148.7v.6h-1.1M77.4 143.4v1.2M77.4 151.8v1.2M82.2 148.1h1.2M82.2 146.9h1.2M82.2 147.9l-.3 .2 .3 .4M82.2 149.3h1.2M83.5 142.7h1v2.5h-1zM84 142.1v.6M84 145.2v.6"/>
<path d="M93 153v-.6l-.6 .6 .6 .5v-.5h.6M93 142.1v-.6l-.6 .6 .6 .6v-.6h.6M93.6 153h.1M93.6 142.1h.1M94.8 146.3h24v2.4h-24zM95.4 146.3l.1 .6zM95.4 148.1l.1 .6zM95.4 144.6v1.7M95.4 148.7v1.9M96.6 146.3v.6zM96.6 148.1v.6zM96.6 144.6v1.7"/>
<path d="M96.6 148.7v1.9M97.7 146.3l.1 .6zM97.7 148.1l.1 .6zM97.8 144.6v1.7M97.8 148.7v1.9M98.9 146.3l.1 .6zM98.9 148.1l.1 .6zM99 144.6v1.7M99 148.7v1.9M100.1 146.3h.2v.6h-.2zM100.1 148.1h.2v.6h-.2zM100.2 144.6v1.7"/>
<path d="M100.2 148.7v1.9M101.3 146.3h.2v.6h-.2zM101.3 148.1h.2v.6h-.2zM101.4 144.6v1.7M101.4 148.7v1.9M102.6 146.3l.1 .6zM102.6 148.1l.1 .6zM102.6 144.6v1.7M102.6 148.7v1.9M103.8 146.3v.6zM103.8 148.1v.6zM103.8 144.6v1.7"/>
<path d="M103.8 148.7v1.9M104.9 146.3l.1 .6zM104.9 148.1l.1 .6zM105 144.6v1.7M105 148.7v1.9M106.1 146.3l.1 .6zM106.1 148.1l.1 .6zM106.2 144.6v1.7M106.2 148.7v1.9M107.3 146.3h.2v.6h-.2zM107.3 148.1h.2v.6h-.2zM107.4 144.6v1.7"/>
<path d="M107.4 148.7v1.9M108.5 146.3h.2v.6h-.2zM108.5 148.1h.2v.6h-.2zM108.6 144.6v1.7M108.6 148.7v1.9M109.8 146.3l.1 .6zM109.8 148.1l.1 .6zM109.8 144.6v1.7M109.8 148.7v1.9M111 146.3v.6zM111 148.1v.6zM111 144.6v1.7"/>
<path d="M111 148.7v1.9M112.1 146.3l.1 .6zM112.1 148.1l.1 .6zM112.2 144.6v1.7M112.2 148.7v1.9M113.3 146.3l.1 .6zM113.3 148.1l.1 .6zM113.4 144.6v1.7M113.4 148.7v1.9M114.5 146.3h.2v.6h-.2zM114.5 148.1h.2v.6h-.2zM114.6 144.6v1.7"/>
<path d="M114.6 148.7v1.9M115.7 146.3h.2v.6h-.2zM115.7 148.1h.2v.6h-.2zM115.8 144.6v1.7M115.8 148.7v1.9M117 146.3l.1 .6zM117 148.1l.1 .6zM117 144.6v1.7M117 148.7v1.9M118.2 146.3v.6zM118.2 148.1v.6zM118.2 144.6v1.7"/>
<path d="M118.2 148.7v1.9M119.4 154.1h.1M119.4 141.5h.1M119.4 154.1h1.2M119.4 141.5h1.2M120 153.8l.6 .3M120 141.2l.6 .3M120.6 154.1l-.6 .4M120.6 141.5l-.6 .4M127.3 140.9h.9v2.5h-.9zM127.8 140.3v.6M127.8 143.4v.6"/>
<path d="M128.4 159h1.2M129 146.3h1.3M129.6 156.5h9.5v7.2h-9.5zM129.6 159.8l.3 .3-.3 .3M131.3 146.3h1.2M134.4 141.5v1.2M134.4 155.3v1.2M134.4 146.3h1.2M135.6 159.6h.5v1.1h-.5zM135.6 146.3l4.8-2.3v4.7zM136.8 142.7v3.1M136.9 159h-1.1v.6"/>
<path d="M138 142.7v2.5M139.1 142.7v1.9M139.1 148.1v1.8M139.1 159h1.3M140.4 147.5h1.2M140.4 145.2h1.2M144 142v1.4M144.6 147.5h.6M145.2 147h2.4v1h-2.4zM147.6 147.5h.6M148.3 142.1h.9v2.5h-.9zM148.8 140.3v.6"/>
<path d="M148.8 141.5v.6M148.8 144.6v.6M148.8 147.5h1.2M149.4 159.6v.5M150 147.5l4.8-2.3v4.7zM151.2 144v2.9M152.4 144v2.3M153.5 144v1.8M153.5 149.3v1.9M154.8 148.7h1.2M154.8 146.3h1.2M154.8 151.8h1.3"/>
<path d="M157 151.8h1.4M157.8 142.7v1.4M157.8 145v1.3M159 148.7h.6M159.6 148.3h2.4v.9h-2.4zM162 148.7h.6M163.8 148.7h.6M164.4 148.3h2.4v.9h-2.4zM166.8 148.7h.5M166.9 141.5h1v2.5h-1zM167.3 140.9v.6M167.3 144v.6"/>
<path d="M167.5 157.1h.9v2.5h-.9zM167.9 156.5v.6M167.9 159.6v.5M169.8 148.7h1.2M171 148.7l4.7-2.4v4.9zM171 159.6h1.2M172.2 158.4l4.8 2.3-4.8 2.4zM172.2 145.2v2.9M172.8 140.3v1.8M173.4 145.2v2.3M173.4 157.1v1.9M174.5 145.2v1.7"/>
<path d="M174.5 150.6v1.8M174.5 157.1v2.5M175.7 157.1v3M175.7 147.5h1.3M175.7 149.9h1.3M177.6 147.5h1.3M178.2 149.9h.6M178.8 149.5h2.3v.9h-2.3zM179.9 147.5h1.2M181.1 149.9h.6M181.7 142v1.4M184.3 140.3h.9v2.4h-.9z"/>
<path d="M184.8 142.7v.7M184.8 147.5h1.3M184.8 149.9h.6M185.4 149.5h2.3v.9h-2.3zM187.1 147.5h1.2M187.7 149.9h1.8M189.5 149.9l6-3v6.1zM192 146.3v2.4M193.2 146.3v1.8M193.2 151.8v1.7M195.5 148.7h1.2M195.5 147.5h1.2"/>
<path d="M195.5 151.2h1.2M195.5 152.4h1.2M197.5 148.7h.9v2.5h-.9zM198 148.1v.6M198 151.2v.6M12.1 179.4h1v2.3h-1zM12.7 178.7v.7M13.8 160.7h1.2M13.8 179.4h1.2M13.8 178.1h1.2M15 177.5l6 3.1-6 2.9zM17.4 160.1v1.8"/>
<path d="M17.4 176.9v1.8M22.2 160.7h1.4M24.5 160.7h1.4M25.4 165.6h.9v2.3h-.9zM25.9 165v.6M25.9 167.9v.6M28.8 165v1.2M28.8 167.2v1.3M29.4 160.7h1.4M31.7 160.7h1.4M33.1 169.7h1.1M33.7 160.7h1.1"/>
<path d="M34.2 169.7l4.8-2.4v4.9zM34.8 179.4l4.9 2.3-4.9 2.4zM35.4 170.3v3.1M36 161.3v1.8M36 178.1v1.9M36.6 170.9v2.5M37.2 160.7v2.4M37.8 166.2v1.7M37.8 171.5v1.9M38.4 160.1v3M39 170.9h1.3M39 168.5h1.3"/>
<path d="M42.7 170.9h1v2.5h-1zM42.7 164.3h1v2.5h-1zM43.2 163.7v.6M43.2 166.8v.5M43.2 170.3v.6M43.2 173.4v.5M52.2 178.7h1.4M52.8 161.9v1.4M52.8 164.2v1.4M54.5 178.7h1.3M54.7 161.9h1.1M57 162.5v1.8"/>
<path d="M57 179.4v1.7M58.2 161.9v2.4M59.4 161.3v3M60.6 160.7h1.2M61.3 167.9h1v2.4h-1zM61.3 163.7h1v2.5h-1zM61.8 163.1v.6M61.8 166.2v.6M61.8 167.3v.6M61.8 170.3v.6M62.4 160.7h.6M63 160.2h2.4v1h-2.4z"/>
<path d="M65.4 160.7h.6M66.6 165v1.2M66.6 167.2v1.3M69.6 160.7h1.2M69.6 163.1h1.2M70.8 170.3h1.2M70.8 169.1h1.2M70.8 171.5h1.2M72 166.8h9.6v7.1h-9.6zM72 163.7v1.9M73.2 163.1v2.5M74.3 169.1h1.1v.6"/>
<path d="M74.3 170.3h.3M74.4 162.5v3.1M74.6 170.1l.5 .2-.5 .3zM75.1 169.7h.5v1.2h-.5zM75.4 170.9v.6h-1.1M75.6 161.9h1.2M76.8 165.6v1.2M76.8 173.9v1.2M78.6 161.9h1.4M80.9 161.9h1.3M81.6 170.3h1.2M81.6 169.1h1.2"/>
<path d="M81.6 170.1l-.3 .2 .3 .3M81.6 171.5h1.2M82.9 165h1v2.3h-1zM83.4 164.3v.7M83.4 167.3v.6M127.3 163.1h.9v2.5h-.9zM127.8 162.5v.6M127.8 165.6v.6M128.4 160.1h1.2M128.4 161.3h1.2M129 168.5h1.3M130.2 178.1h9.5v7.2h-9.5z"/>
<path d="M131.3 168.5h1.2M134.4 163.7v1.3M134.4 168.5h1.2M135 176.9v1.2M135.6 168.5l4.8-2.3v4.7zM135.8 160.7v.6h1.1M136.1 160.1l.4-.2v.5zM136.5 160.1h.4M136.8 165v2.9M138 165v2.3M139.1 165v1.8M139.1 170.3v1.9"/>
<path d="M139.1 160.1h1.3M139.1 161.3h1.3M140.4 169.7h1.2M140.4 167.3h1.2M144.6 161.9v1.4M144.6 164.2v1.4M145.2 169.7h.6M145.8 169.3h2.4v.9h-2.4zM148.2 169.7h.6M148.9 160.1h.9v2.4h-.9zM148.9 164.3h.9v2.5h-.9zM149.4 162.5v.6"/>
<path d="M149.4 163.7v.6M149.4 166.8v.5M149.4 169.7h1.2M150.6 169.7l4.8-2.4v4.9zM151.8 166.2v2.9M153 166.2v2.3M154.1 166.2v1.7M154.1 171.5v1.9M155.4 170.9h1.2M155.4 168.5h1.2M155.4 173.9h1.3M157.7 173.9h1.3"/>
<path d="M158.4 165v1.2M158.4 167.2v1.3M159.6 170.9h.5M160.1 170.5h2.5v.9h-2.5zM162.6 170.9h.6M164.4 170.9h.6M165 170.5h2.3v.9h-2.3zM167.3 170.9h.6M167.5 179.4h.9v2.3h-.9zM167.5 163.7h.9v2.5h-.9zM167.9 163.1v.6M167.9 166.2v.6"/>
<path d="M167.9 178.7v.7M170.4 170.9h1.2M171 161.9h1.2M171.6 170.9l4.8-2.4v4.9zM172.8 167.3v3M173.4 162.5v1.8M173.4 179.4v1.7M173.9 167.3v2.4M174.5 179.4v2.3M175.1 167.3v1.8M175.1 172.8v1.7M175.7 179.4v2.9"/>
<path d="M176.4 169.7h1.2M176.4 172.2h1.2M177 160.7h1.2M178.2 169.7h1.3M178.8 172.2h.6M179.4 171.7h2.3v.9h-2.3zM180.5 169.7h1.2M181.7 172.2h.6M182.3 161.9v1.4M182.3 164.2v1.4M184.9 162.5h.9v2.5h-.9zM185.4 161.9v.6"/>
<path d="M185.4 165v.6M185.4 169.7h1.2M185.4 172.2h.6M186 171.7h2.3v.9h-2.3zM187.7 169.7h1.2M188.3 172.2h1.8M190.1 172.2l6-3.1v6zM192.6 168.5v2.4M193.8 168.5v1.8M193.8 173.9v1.8M196.1 170.9h1.2M196.1 169.7h1.2"/>
<path d="M196.1 173.4h1.2M196.1 174.5h1.2M198.1 170.9h.9v2.5h-.9zM198.6 170.3v.6M198.6 173.4v.5M12.7 181.7v.6M13.8 181.7h1.2M13.8 182.9h1.2M15 199.7l6 3-6 3zM17.4 182.3v1.8M17.4 199.1v1.9M18.7 181.7v2.4"/>
<path d="M21 180.6h1.8M22.2 182.9h1.4M22.8 180h2.5v1h-2.5zM24.5 182.9h1.4M25.3 180.6h.6M25.4 187.7h.9v2.4h-.9zM25.9 187.2v.5M25.9 190.1v.6M28.8 187.2v1.2M28.8 189.4v1.3M28.8 180.6h.6M29.4 180h2.4v1h-2.4z"/>
<path d="M29.4 182.9h1.4M31.7 182.9h1.4M31.8 180.6h.7M33.1 191.9h1.1M33.7 182.9h1.1M33.7 180.6h1.1M34.2 191.9l4.8-2.4v4.9zM35.4 192.5v3M36 183.5v1.8M36.6 193.1v2.4M37.2 182.9v2.4M37.8 188.3v1.8"/>
<path d="M37.8 193.8v1.7M38.4 182.3v3M39 193.1h1.3M39 190.7h1.3M39.7 181.7h1.2M42.7 193.1h1v2.4h-1zM42.7 186.6h1v2.3h-1zM43.2 185.9v.7M43.2 188.9v.6M43.2 192.5v.6M43.2 195.5v.6M43.2 181.7h.6"/>
<path d="M43.8 181.2h2.4v1h-2.4zM46.2 181.7h.7M48 181.7h.6M48.6 181.2h2.4v1h-2.4zM51 181.7h.6M52.8 184.1v1.4M52.8 186.4v1.3M54.7 181.7h1.1M54.7 184.1h1.1M55.8 180.6l4.8 2.3-4.8 2.4zM57 184.7v1.9M58.2 184.1v2.5"/>
<path d="M59.4 183.5v3.1M60.6 182.9h1.2M61.3 185.9h1v2.4h-1zM61.3 190.1h1v2.4h-1zM61.8 185.3v.6M61.8 188.3v.6M61.8 189.5v.6M61.8 192.5v.6M62.4 182.9h.6M63 182.4h2.4v1h-2.4zM65.4 182.9h.6M66.6 187.2v1.2"/>
<path d="M66.6 189.4v1.3M70.2 182.9h1.2M70.2 185.3h1.2M71.4 181.7l4.8 2.4-4.8 2.5zM71.4 192.5h1.2M71.4 191.3h1.2M71.4 193.8h1.2M72.6 188.9h9.6v7.2h-9.6zM72.6 180.6v1.7M72.6 185.9v1.8M73.8 185.3v2.4M74.9 191.3h1.1v.6"/>
<path d="M74.9 192.5h.3M75 184.7v3M75.2 192.3l.5 .2-.5 .2zM75.7 191.9h.5v1.2h-.5zM76 193.1v.7h-1.1M76.2 184.1h1.2M77.4 187.7v1.2M77.4 196.1v1.2M79.2 184.1h1.4M81.5 184.1h1.3M82.2 192.5h1.2M82.2 191.3h1.2"/>
<path d="M82.2 192.2l-.3 .3 .3 .3M82.2 193.8h1.2M83.5 187.2h1v2.3h-1zM84 186.6v.6M84 189.5v.6M89.4 189.5h31.8v21.6h-31.8zM92.1 197.2h.7M92.1 192.7l.1-.2h.5l.1 .2M92.2 197.1v-.3l.1 .2v-.2h.3v.3M92.2 196.1v.3h.4v-.3h-.3l.1 .3M92.2 193.8v.3h.1v-.3h.3v.3M92.2 193.2v.2h.1v-.2h.3v.2"/>
<path d="M92.3 195.7l.3 .1-.3 .2M92.3 194.7h.3l-.1 .2zM92.3 192.7l.3 .2-.3 .1M92.3 195v.2M92.4 187.2v2.3M92.6 196.6h.1M92.6 195l-.4 .1M92.6 193.6h.1M93.6 187.2v2.3M94.4 197.1h.8M94.4 192.7l.3-.1 .5 .1M94.5 196.2v.3h.3v-.3l.2 .1v.2"/>
<path d="M94.5 195.8h.5v.2h-.4zM94.7 195.5h.3M94.7 194.1h.3M94.7 192.8l.3 .3M94.8 193.3l.1 .2 .1-.1v-.1M94.8 187.2v2.3M94.9 194.7v.2M95 196.6v.4l-.4-.4v.4M95 195.4h-.3l.1 .1M95 195.1l-.3 .1 .1 .2M95 194.7l-.5 .2h.5M95 193.9h-.3l.1 .2"/>
<path d="M95 193.8h-.3l.1 .1M95 193.3h-.3v.2M95 192.8l-.3 .3M96 187.2v2.3M97.2 187.2v2.3M98.4 187.2v2.3M99.6 187.2v2.3M100.8 187.2v2.3M102 187.2v2.3M103.2 187.2v2.3M104.4 187.2v2.3M105.6 187.2v2.3"/>
<path d="M106.8 187.2v2.3M108 187.2v2.3M109.2 187.2v2.3M110.4 187.2v2.3M111.6 187.2v2.3M112.8 187.2v2.3M114 187.2v2.3M115.2 187.2v2.3M116.4 187.2v2.3M117.6 187.2v2.3M118.8 187.2v2.3M120 187.2v2.3"/>
<path d="M121.2 189.5v21.6M127.9 185.3h1v2.4h-1zM128.4 184.7v.6M128.4 187.7v.6M129 181.7h1.2M129 182.9h1.2M129 180.6h1.2M129.6 190.7h1.3M130.2 181.4l.3 .3-.3 .3M131.9 190.7h1.3M133.8 199.7v1.3M135 185.3v1.3"/>
<path d="M135 190.7h1.2M136.2 181.1h.5v1.2h-.5zM136.2 190.7l4.8-2.4v4.8zM136.4 182.3v.6h1.1M136.7 181.7l.4-.2v.5zM137.1 181.7h.4M137.4 187.2v2.9M137.5 180.6h-1.1v.5M138.6 187.2v2.3M139.7 187.2v1.7M139.7 192.5v1.9M139.7 181.7h1.3"/>
<path d="M139.7 182.9h1.3M139.7 180.6h1.3M141 191.9h1.2M141 189.5h1.2M144.6 184.1v1.4M144.6 186.4v1.3M145.2 191.9h.6M145.8 191.5h2.4v.9h-2.4zM148.2 191.9h.6M148.9 182.3h.9v2.4h-.9zM148.9 186.6h.9v2.3h-.9zM149.4 181.7v.6"/>
<path d="M149.4 184.7v.6M149.4 185.9v.7M149.4 188.9v.6M149.4 191.9h1.2M150.6 191.9l4.8-2.4v4.9zM151.8 188.3v3M153 188.3v2.4M154.1 188.3v1.8M154.1 193.8v1.7M155.4 193.1h1.2M155.4 190.7h1.2M155.4 196.1h1.3"/>
<path d="M157.7 196.1h1.3M158.4 187.2v1.2M158.4 189.4v1.3M159.6 193.1h.5M160.1 192.7h2.5v.9h-2.5zM162.6 193.1h.6M164.4 193.1h.6M165 192.7h2.3v.9h-2.3zM167.3 193.1h.6M167.5 185.9h.9v2.4h-.9zM167.9 181.7v.6M167.9 185.3v.6"/>
<path d="M167.9 188.3v.6M170.4 193.1h1.2M171 181.7h1.2M171 184.1h1.2M171.6 193.1l4.8-2.4v4.8zM172.2 180.6l4.8 2.3-4.8 2.4zM172.8 189.5v3M173.4 184.7v1.9M173.9 189.5v2.4M175.1 189.5v1.8M175.1 194.9v1.8M176.4 191.9h1.2"/>
<path d="M176.4 194.4h1.2M177 182.9h1.2M178.2 191.9h1.3M178.8 194.4h.6M179.4 193.8h2.3v1h-2.3zM180.5 191.9h1.2M181.7 194.4h.6M182.3 184.1v1.4M182.3 186.4v1.3M184.9 184.7h.9v2.5h-.9zM185.4 184.1v.6M185.4 187.2v.5"/>
<path d="M185.4 191.9h1.2M185.4 194.4h.6M186 193.8h2.3v1h-2.3zM187.7 191.9h1.2M188.3 194.4h1.8M190.1 194.4l6-3.1v6zM192.6 190.7v2.4M193.8 190.7v1.8M193.8 196.1v1.8M196.1 195.5h1.2M196.1 193.1h1.2M196.1 191.9h1.2"/>
<path d="M196.1 196.7h1.2M198.1 193.1h.9v2.4h-.9zM198.6 192.5v.6M198.6 195.5v.6M12.1 201.5h1v2.4h-1zM12.7 201v.5M12.7 203.9v.6M13.8 205.1h1.2M13.8 203.9h1.2M13.8 201.5h1.2M13.8 200.3h1.2M17.4 204.5v1.8"/>
<path d="M18.7 203.9v2.4M21 202.7h1.8M22.2 205.1h1.4M22.8 202.2h2.5v1h-2.5zM24.5 205.1h1.4M25.3 202.7h.6M25.4 209.9h.9v2.4h-.9zM25.9 209.3v.6M25.9 212.3v.6M28.8 209.3v1.3M28.8 211.6v1.3M28.8 202.7h.6"/>
<path d="M29.4 202.2h2.4v1h-2.4zM29.4 205.1h1.4M31.7 205.1h1.4M31.8 202.7h.7M33.1 214.1h1.1M33.7 205.1h1.1M33.7 202.7h1.1M34.2 214.1l4.8-2.4v4.8zM34.8 201.5l4.9 2.4-4.9 2.4zM35.4 214.7v3M36 200.3v1.8M36 205.7v1.8"/>
<path d="M36.6 215.3v2.4M37.2 205.1v2.4M37.8 210.5v1.8M37.8 215.9v1.8M38.4 204.5v3M39 215.3h1.3M39 212.9h1.3M39.7 203.9h1.2M42.7 215.3h1v2.4h-1zM42.7 208.7h1v2.4h-1zM43.2 208.2v.5M43.2 211.1v.6"/>
<path d="M43.2 214.7v.6M43.2 217.7v.6M43.2 203.9h.6M43.8 203.4h2.4v1h-2.4zM46.2 203.9h.7M48 203.9h.6M48.6 203.4h2.4v1h-2.4zM51 203.9h.6M52.2 201h1.4M52.8 206.3v1.3M52.8 208.6v1.3M54.5 201h1.3"/>
<path d="M54.7 203.9h1.1M54.7 206.3h1.1M55.8 202.7l4.8 2.4-4.8 2.4zM57 201.5v1.8M57 206.9v1.8M58.2 206.3v2.4M59.4 205.7v3M60.6 205.1h1.2M61.3 208.2h1v2.3h-1zM61.3 212.3h1v2.4h-1zM61.8 207.5v.7M61.8 210.5v.6"/>
<path d="M61.8 211.7v.6M61.8 214.7v.6M62.4 205.1h.6M63 204.6h2.4v1h-2.4zM65.4 205.1h.6M66.6 209.3v1.3M66.6 211.6v1.3M70.2 205.1h1.2M70.2 207.5h1.2M71.4 203.9l4.8 2.4-4.8 2.4zM71.4 214.7h1.2M71.4 213.5h1.2"/>
<path d="M71.4 215.9h1.2M72.6 211.1h9.6v7.2h-9.6zM72.6 202.7v1.8M72.6 208.2v1.7M73.8 207.5v2.4M74.9 213.5h1.1v.6M74.9 214.7h.3M75 206.9v3M75.2 214.5l.5 .2-.5 .2zM75.7 214.1h.5v1.2h-.5zM76 215.3v.6h-1.1M76.2 206.3h1.2"/>
<path d="M77.4 209.9v1.2M77.4 218.3v1.2M79.2 206.3h1.4M81.5 206.3h1.3M82.2 214.7h1.2M82.2 213.5h1.2M82.2 214.4l-.3 .3 .3 .3M82.2 215.9h1.2M84.1 209.3h.9v2.4h-.9zM84.6 208.7v.6M84.6 211.7v.6M92.4 211.1v2.4"/>
<path d="M93.6 211.1v2.4M94.8 211.1v2.4M96 211.1v2.4M97.2 211.1v2.4M98.4 211.1v2.4M99.6 211.1v2.4M100.8 211.1v2.4M102 211.1v2.4M103.2 211.1v2.4M104.4 211.1v2.4M105.6 211.1v2.4M106.8 211.1v2.4"/>
<path d="M108 211.1v2.4M109.2 211.1v2.4M110.4 211.1v2.4M111.6 211.1v2.4M112.8 211.1v2.4M114 211.1v2.4M115.2 211.1v2.4M116.4 211.1v2.4M117.6 211.1v2.4M118.8 211.1v2.4M120 211.1v2.4M126.7 207.5h.9v2.4h-.9z"/>
<path d="M127.2 206.9v.6M127.2 209.9v.6M127.8 204.5h1.2M127.8 205.7h1.2M127.8 203.3h1.2M128.4 212.9h1.3M129 201h9.6v7.2h-9.6zM129 204.2l.2 .3-.2 .4M130.7 212.9h1.3M133.8 208.2v1.1M133.8 212.9h1.2M135 203.9h.4v1.2h-.4z"/>
<path d="M135 212.9l4.7-2.4v4.8zM135.3 205.1v.6h1M135.4 204.5l.5-.2v.5zM135.9 204.5h.4M136.2 209.3v3M136.3 203.3h-1v.6M137.4 209.3v2.4M138.6 209.3v1.8M138.6 214.7v1.8M138.6 204.5h1.1M138.6 205.7h1.1M138.6 203.3h1.1"/>
<path d="M139.7 214.1h1.3M139.7 211.7h1.3M144.6 206.3v1.3M144.6 208.6v1.3M145.2 214.1h.6M145.8 213.7h2.4v.9h-2.4zM148.2 214.1h.6M148.9 208.7h.9v2.4h-.9zM148.9 204.5h.9v2.4h-.9zM149.4 203.9v.6M149.4 206.9v.6M149.4 208.2v.5"/>
<path d="M149.4 211.1v.6M149.4 214.1h1.2M150.6 214.1l4.8-2.4v4.8zM151.8 210.5v3M153 210.5v2.4M154.1 210.5v1.8M154.1 215.9v1.8M155.4 215.3h1.2M155.4 212.9h1.2M155.4 218.3h1.3M157.7 218.3h1.3M158.4 209.3v1.3"/>
<path d="M158.4 211.6v1.3M159.6 215.3h.5M160.1 214.8h2.5v1h-2.5zM162.6 215.3h.6M164.4 215.3h.6M165 214.8h2.3v1h-2.3zM167.3 215.3h.6M167.5 208.2h.9v2.3h-.9zM167.5 201.5h.9v2.4h-.9zM167.9 201v.5M167.9 203.9v.6M167.9 207.5v.7"/>
<path d="M167.9 210.5v.6M170.4 215.3h1.2M171 203.9h1.2M171 206.3h1.2M171.6 215.3l4.8-2.4v4.8zM172.2 202.7l4.8 2.4-4.8 2.4zM172.8 211.7v3M173.4 201.5v1.8M173.4 206.9v1.8M173.9 211.7v2.4M174.5 201.5v2.4M175.1 211.7v1.8"/>
<path d="M175.1 217.1v1.8M175.7 201.5v3M176.4 214.1h1.2M176.4 216.5h1.2M177 205.1h1.2M178.2 214.1h1.3M178.8 216.5h.6M179.4 216h2.3v1h-2.3zM180.5 214.1h1.2M181.7 216.5h.6M182.3 206.3v1.3M182.3 208.6v1.3"/>
<path d="M184.9 206.9h.9v2.4h-.9zM185.4 206.3v.6M185.4 209.3v.6M185.4 214.1h1.2M185.4 216.5h.6M186 216h2.3v1h-2.3zM187.7 214.1h1.2M188.3 216.5h1.8M190.1 216.5l6-3v6zM192.6 212.9v2.4M193.8 212.9v1.8M193.8 218.3v1.8"/>
<path d="M196.1 215.3h1.2M196.1 214.1h1.2M196.1 217.7h1.2M196.1 218.9h1.2M198.1 215.3h.9v2.4h-.9zM198.6 214.7v.6M198.6 217.7v.6M12.1 223.7h1v2.4h-1zM12.7 223.1v.6M12.7 226.1v.6M13.8 223.7h1.2M13.8 227.3h1.2"/>
<path d="M13.8 222.5h1.2M13.8 226.1h1.2M15 221.9l6 3-6 3zM17.4 221.3v1.8M17.4 226.7v1.8M18.7 226.1v2.4M21 224.9h1.8M22.2 227.3h1.4M22.8 224.4h2.5v1h-2.5zM24.5 227.3h1.4M25.3 224.9h.6M25.4 232.1h.9v2.4h-.9z"/>
<path d="M25.9 231.5v.6M25.9 234.5v.6M28.8 231.5v1.3M28.8 233.8v1.3M28.8 224.9h.6M29.4 224.4h2.4v1h-2.4zM29.4 227.3h1.4M31.7 227.3h1.4M31.8 224.9h.7M33.1 236.3h1.1M33.7 227.3h1.1M33.7 224.9h1.1"/>
<path d="M34.2 236.3l4.8-2.4v4.8zM34.8 223.7l4.9 2.4-4.9 2.4zM35.4 236.9v3M36 222.5v1.8M36 227.9v1.8M36.6 237.5v2.4M37.2 227.3v2.4M37.8 232.7v1.8M37.8 238.1v1.8M38.4 226.7v3M39 237.5h1.3M39 235.1h1.3"/>
<path d="M39.7 226.1h1.2M42.7 230.9h1v2.4h-1zM42.7 237.5h1v2.4h-1zM43.2 230.3v.6M43.2 233.3v.6M43.2 236.9v.6M43.2 239.9v.6M43.2 226.1h.6M43.8 225.6h2.4v1h-2.4zM46.2 226.1h.7M48 226.1h.6M48.6 225.6h2.4v1h-2.4z"/>
<path d="M51 226.1h.6M52.2 223.1h1.4M52.8 228.5v1.3M52.8 230.8v1.3M54.5 223.1h1.3M54.7 226.1h1.1M54.7 228.5h1.1M55.8 224.9l4.8 2.4-4.8 2.4zM57 223.7v1.8M57 229.1v1.8M58.2 228.5v2.4M59.4 227.9v3"/>
<path d="M60.6 227.3h1.2M61.3 230.3h1v2.4h-1zM61.3 234.5h1v2.4h-1zM61.8 229.7v.6M61.8 232.7v.6M61.8 233.9v.6M61.8 236.9v.6M62.4 227.3h.6M63 226.9h2.4v.9h-2.4zM65.4 227.3h.6M66.6 231.5v1.3M66.6 233.8v1.3"/>
<path d="M70.2 227.3h1.2M70.2 229.7h1.2M71.4 226.1l4.8 2.4-4.8 2.4zM71.4 236.9h1.2M71.4 235.7h1.2M71.4 238.1h1.2M72.6 233.3h9.6v7.2h-9.6zM72.6 224.9v1.8M72.6 230.3v1.8M73.8 229.7v2.4M74.9 235.7h1.1v.6M74.9 236.9h.3"/>
<path d="M75 229.1v3M75.2 236.7l.5 .2-.5 .2zM75.7 236.3h.5v1.2h-.5zM76 237.5v.6h-1.1M76.2 228.5h1.2M77.4 232.1v1.2M79.2 228.5h1.4M81.5 228.5h1.3M82.2 236.9h1.2M82.2 235.7h1.2M82.2 236.6l-.3 .3 .3 .3M82.2 238.1h1.2"/>
<path d="M83.5 231.5h1v2.4h-1zM84 230.9v.6M84 233.9v.6M127.3 229.7h.9v2.4h-.9zM127.8 229.1v.6M127.8 232.1v.6M128.4 226.7h1.2M128.4 227.9h1.2M128.4 225.5h1.2M129 235.1h1.3M129.6 223.1h9.5v7.2h-9.5zM129.6 226.4l.3 .3-.3 .3"/>
<path d="M131.3 235.1h1.2M134.4 221.9v1.2M134.4 230.3v1.2M134.4 235.1h1.2M135.6 226.1h.5v1.2h-.5zM135.6 235.1l4.8-2.4v4.8zM135.8 227.3v.6h1.1M136.1 226.7l.4-.3v.5zM136.5 226.7h.4M136.8 231.5v3M136.9 225.5h-1.1v.6M138 231.5v2.4"/>
<path d="M139.1 231.5v1.8M139.1 236.9v1.8M139.1 226.7h1.3M139.1 227.9h1.3M139.1 225.5h1.3M140.4 236.3h1.2M140.4 233.9h1.2M145.2 228.5v1.3M145.2 230.8v1.3M145.8 236.3h.5M146.3 235.8h2.5v1h-2.5zM148.8 236.3h.6"/>
<path d="M149.5 230.9h1v2.4h-1zM149.5 226.7h1v2.4h-1zM150 226.1v.6M150 229.1v.6M150 230.3v.6M150 233.3v.6M150 236.3h1.2M151.2 236.3l4.8-2.4v4.8zM152.4 232.7v3M153.5 232.7v2.4M154.8 232.7v1.8M154.8 238.1v1.8"/>
<path d="M156 237.5h1.2M156 235.1h1.2M159 231.5v1.3M159 233.8v1.3M160.1 237.5h.6M160.7 237h2.5v1h-2.5zM163.2 237.5h.6M165 237.5h.6M165.6 237h2.3v1h-2.3zM167.9 237.5h.6M168.1 230.3h.9v2.4h-.9zM168.1 223.7h.9v2.4h-.9z"/>
<path d="M168.5 223.1v.6M168.5 226.1v.6M168.5 229.7v.6M168.5 232.7v.6M171 237.5h1.2M171.6 226.1h1.2M171.6 228.5h1.2M172.2 237.5l4.8-2.4v4.8zM172.8 224.9l4.8 2.4-4.8 2.4zM173.4 233.9v3M173.9 223.7v1.8M173.9 229.1v1.8"/>
<path d="M174.5 233.9v2.4M175.1 223.7v2.4M175.7 233.9v1.8M175.7 239.3v1.8M176.4 223.7v3M177 236.3h1.2M177 238.7h1.2M177.6 227.3h1.2M178.8 236.3h1.2M179.4 238.7h.6M180 238.2h2.3v.9h-2.3zM181.1 236.3h1.2"/>
<path d="M182.3 238.7h.6M182.9 228.5v1.3M182.9 230.8v1.3M185.5 229.1h1v2.4h-1zM186 228.5v.6M186 231.5v.6M186 236.3h1.2M186 238.7h.6M186.6 238.2h2.3v.9h-2.3zM188.3 236.3h1.2M188.9 238.7h1.9M190.8 238.7l5.9-3v6z"/>
<path d="M193.2 235.1v2.4M194.4 235.1v1.8M196.7 237.5h1.3M196.7 236.3h1.3M196.7 239.9h1.3M198.7 237.5h.9v2.4h-.9zM199.2 236.9v.6M199.2 239.9v.6M77.4 240.5v1.2M111.6 242.3l.6 .4M111.6 242.3h1.2M112.2 243.5v.4l-.6-.4 .6-.4v.4h.6"/>
<path d="M112.2 241.9l-.6 .4M112.8 242.3h.1M156 240.5h1.3M158.3 240.5h1.3M194.4 240.5v1.8M196.7 241.1h1.3"/>
</g>
<g fill="none" stroke="#006665" stroke-width=".2">
<path d="M15.3 24l.3-.2-.1-.1h-.2v.6M15.3 26.4h.2l.1-.2-.3-.2v.6M15.3 27.6h.4M15.3 22.8h.4M15.4 24l.2 .3M15.4 26.4l.2 .2M15.5 22.6v.5M16.1 23.8v.5l-.1 .2-.1-.1M16.1 23.9l-.1-.1-.2 .2 .1 .3h.2M16.1 26.6l-.3-.1 .1-.2h.2v.4l-.2 .2M17.1 26.5l.6 .1-.6 .3M17.1 24.3l.6 .1-.6 .3"/>
<path d="M17.2 23.8h.5M17.5 23.6v.5M17.5 25.8v.5M18.3 24.9l.1 .2h.5M18.5 24.9v.3M18.6 26.2v-.3h-.3v.3h.6M18.8 25.4v.2h-.3v-.2h.2v.2M18.9 25.9l-.3 .1M35 27.6h.5M35 25.3h.5M35.3 37h.2M35.3 36.7h.2l-.2 .1"/>
<path d="M35.3 25v.4M35.5 36.4l-.2 .1M35.5 36.3l-.2 .1M35.7 27.6l.6 .3-.6 .2M35.7 25.4l.6 .3-.6 .2M35.9 25h.4M36.1 24.8v.5M36.1 27.1v.4M36.5 37.5l.2 .1M36.5 37.3h.2l-.2 .1M36.7 37l-.2 .1M36.7 36.9l-.2 .1"/>
<path d="M37.1 27.3h.2l-.2 .2h.2M37.1 27.1h.2v.1h-.2M37.3 26.9l-.2 .1M37.3 26.6v.2h-.2M37.5 37.9l.6 .2-.6 .1M37.5 35.7l.6 .2-.6 .1M37.6 35.3h.5M37.9 35v.4M37.9 37.2v.4M38.3 26.7h.3l-.3 .2h.3M38.3 26.5h.3l-.3 .1M38.3 37.8h.5"/>
<path d="M38.3 35.4h.5M38.6 26.3l-.3 .1M38.6 26v.2h-.3M38.6 35.2v.5M56 28.8h.5M56 26.5h.5M56.3 26.2v.4M56.7 28.8l.6 .3-.6 .2M56.7 26.6l.6 .3-.6 .2M56.9 26.2h.4M57 26v.5M57 28.2v.5"/>
<path d="M58.1 28.6l.2 .1M58.1 28.3h.2l-.2 .1M58.3 28.1l-.2 .1M58.3 27.9l-.2 .1M59.3 27.9h.3l-.3 .2h.3M59.3 27.6l.3 .1-.3 .1M59.6 27.5l-.3 .1M59.6 27.2v.2h-.3M71.6 30h.5M71.6 27.6h.5M71.8 27.4v.5M72.3 30.1l.6 .2-.6 .1"/>
<path d="M72.3 27.9l.6 .2-.6 .1M72.4 27.5h.5M72.7 27.2v.4M72.7 29.4v.4M73 35.9h.3l.1-.1-.4-.1v.6M73 37.2h.2l.2-.2-.4-.1v.6M73 38.4h.2l.2-.3h-.4v.6M73.6 35.7a.3 .3 0 0 1 .4 .2 .3 .3 0 0 1-.3 .4l-.2-.3zM73.6 36.9h.3v.6h-.3zM73.6 38.1h.3v.6h-.3zM73.7 29.8h.3M73.7 29.5h.3l-.3 .1"/>
<path d="M74 29.3h-.3M74 29.1l-.3 .1M74.1 36.3l.2-.6 .2 .6M74.1 36.9l.2 .6 .1-.5 .1 .5 .1-.6M74.1 36.1h.4M74.2 38.3h.3v-.2h-.3v.6h.3v-.2l-.1-.2M74.9 29.2l.2 .1M74.9 28.9h.2l-.2 .1M75.1 28.7h-.2M75.1 28.5l-.2 .1M77.1 34.8l.6 .3-.6 .2M77.3 39.7v.2h.2v-.2l.3 .1-.1 .1"/>
<path d="M77.3 39.2v.3l.4-.3v.3M77.3 34.5l.3-.1 .2 .3h-.5zM77.3 34h.4l.1 .2h-.5zM78.5 38.1h-.3v.2l.3 .1-.1 .3h-.2M78.8 38.1h.2l.1 .1-.1 .5h-.2zM79.4 38.1v.6M80.1 38.1l-.6 .7M80.6 36.9l-.3 .1v.1l.3 .1v.2l-.3 .1M80.6 38.1h-.3v.2l.3 .2v.2h-.3M80.8 35.5h1.1M80.9 38.1a.3 .3 0 0 1 .3 .3 .3 .3 0 0 1-.3 .3zM81.2 35.7l-.3 .1v.3l.2 .2 .1-.1"/>
<path d="M81.2 37h-.3v.4h.3M81.5 38.1h.3l-.1 .6h-.2l-.1-.2zM81.5 36.9v.6M81.6 37.1l.2 .4M81.8 35.7h-.3l.1 .2 .2 .1-.1 .3-.2-.1M81.8 36.9l-.3 .3M129.9 27.7h1M130.3 26.7l-.2-.1-.2 .2 .4 .3v.1h-.4M130.3 25.5l-.2-.1-.2 .2 .4 .2v.2h-.4M130.3 27.9h-.2l-.2 .3 .1 .2h.3M130.5 25.4l.4 .1-.1 .5h-.3zM130.9 27.9l-.4 .1 .4 .2v.2h-.4"/>
<path d="M130.9 26.7l-.2-.1-.2 .2v.3l.2 .2 .2-.1M131.1 25.4v.6M131.1 26.6v.7M131.2 27l.3 .3M131.5 26.6l-.4 .5M131.9 25.4l-.5 .8M132.4 25.5h-.4l.1 .3 .3 .1v.1h-.4M132.6 25.4l.4 .2-.1 .4h-.3zM133.3 25.4l.3 .1-.1 .5h-.3zM134.1 24.6l.6 .2-.6 .2M134.1 29.8l.6 .3-.6 .2M134.2 24.2l.1 .3 .4-.3v.3"/>
<path d="M134.2 23.7v.3l.3-.1v-.2l.2 .1v.2M134.2 29.5l.4-.1 .1 .3h-.5zM134.2 29.1l.5-.1v.3h-.5zM136.6 35.5h.3l-.3 .2h.3M136.6 35.3h.3v.1h-.3M136.9 35.1l-.3 .1M136.9 34.8v.2h-.3M137.2 27h.3v-.4h-.3v.7M137.3 25.8h.3v-.3l-.3-.1v.6M137.4 28.2h.3v-.3h-.3v.6M137.9 34.9h.1l-.1 .2h.1M137.9 34.7h.1v.1h-.1"/>
<path d="M138 28h.3v.3l-.2 .2-.1-.2zM138 26.6l.1 .2v.3l-.1 .2-.2-.2v-.3zM138 34.5l-.1 .1M138 34.2v.2h-.1M138 25.4l.2 .2-.1 .4h-.2v-.4zM138.3 26.6l.2 .7 .1-.4 .1 .4 .1-.7M138.5 28.5l.1-.6 .3 .6M138.5 25.8l.3-.2-.2-.2h-.1v.6h.3v-.2h-.2M138.6 28.3h.2M138.8 34.5l.7 .2-.7 .1M138.8 36.7l.7 .2-.7 .1M139 36.2h.5"/>
<path d="M139.2 33.8v.4M139.2 36v.4M139.7 36.6h.5M139.7 34.2h.5M139.9 36.4v.5M151 36.8l.3 .1M151 36.5h.3l-.3 .1M151.3 36.3l-.3 .1M151.3 36.1l-.3 .1M152.3 36.2l.1 .1M152.3 35.9h.1l-.1 .1M152.4 35.7l-.1 .1"/>
<path d="M152.4 35.5l-.1 .1M153.2 35.7l.7 .2-.7 .1M153.2 37.9l.7 .2-.7 .1M153.4 37.5h.5M153.6 35v.4M153.6 37.2v.4M154.1 37.8h.5M154.1 35.4h.5M154.3 37.6v.5M171.7 28.8h.6M171.7 26.5h.6M172 38l.3 .1"/>
<path d="M172 37.7h.3l-.3 .1M172 28.6v.5M172.3 37.5h-.3M172.3 37.3l-.3 .1M172.4 26.6l.6 .3-.6 .2M172.4 28.8l.6 .3-.6 .2M172.6 28.4h.4M172.8 26v.5M172.8 28.2v.5M173.3 37.4l.1 .1M173.3 37.1h.1l-.1 .1M173.4 36.9l-.1 .1"/>
<path d="M173.4 36.7l-.1 .1M173.9 27.1h.1l-.1 .2h.1M173.9 26.9h.1v.2h-.1M174 26.7l-.1 .1M174 26.5v.1h-.1M174.2 36.9l.6 .1-.6 .3M174.2 39.1l.6 .1-.6 .3M174.4 38.7h.4M174.6 36.2v.5M174.6 38.4v.4M175 27.7h.3l-.3 .2h.3M175 27.5l.3 .1h-.3"/>
<path d="M175 36.6h.6M175 39.1h.6M175.3 27.3l-.3 .1M175.3 27.1v.1h-.3M175.3 38.8v.4M191.6 37.9v.2h.6M191.8 37.9v.2M192 39.2l-.1-.4h-.3v.4h.6M192.2 38.3v.3h-.3l-.1-.2 .2-.1 .1 .3M192.2 38.8l-.2 .3M192.8 38.1l.6 .1-.6 .3M193 39.8h.4"/>
<path d="M193.2 37.4v.5M193.2 39.6v.5M194.5 37.8l.4-.2-.1-.1h-.3v.6M194.6 37.8l.3 .3M194.9 36.6h.5M195.4 37.6v.5l-.3 .1M195.4 37.7l-.2-.1-.2 .2 .1 .3h.3M15.3 46.2h.2l.1-.3-.3-.1v.6M15.3 48.6h.2l.1-.2-.3-.2v.7M15.3 49.8h.4M15.3 45h.4M15.4 46.2l.2 .2"/>
<path d="M15.4 48.6l.2 .3M15.5 44.8v.5M16.1 46.4h-.3l.1-.3h.2v.4l-.1 .2-.1-.1M16.1 48.8l-.1 .1-.2-.2 .1-.2h.2v.5l-.2 .1M17.1 48.6l.6 .3-.6 .2M17.1 46.4l.6 .3-.6 .2M17.2 46h.5M17.5 45.8v.5M17.5 48v.5M18.3 47.1l.1 .2h.5M18.5 47.1v.3M18.6 48.4v-.4h-.3v.4h.6"/>
<path d="M18.8 47.5v.3h-.3v-.3h.2v.3M18.9 48l-.3 .2M35 49.8h.5M35 47.5h.5M35.3 59.1l.2 .1M35.3 58.9h.2l-.2 .1M35.3 47.2v.4M35.5 58.6l-.2 .1M35.5 58.5h-.2M35.7 49.8l.6 .3-.6 .1M35.7 47.6l.6 .3-.6 .1M35.9 47.2h.4"/>
<path d="M36.1 47v.5M36.1 49.2v.5M36.5 59.7l.2 .1M36.5 59.5h.2l-.2 .1M36.7 59.2v.2h-.2M36.7 59.1h-.2M37.1 49.5h.2l-.2 .2h.2M37.1 49.2h.2v.2h-.2M37.3 49.1h-.2M37.3 48.8v.2h-.2M37.5 57.9l.6 .1-.6 .3M37.6 57.4h.5"/>
<path d="M37.9 57.2v.4M37.9 59.4v.4M38.3 48.9h.3l-.3 .2h.3M38.3 48.6l.3 .1-.3 .1M38.3 60h.5M38.3 57.6h.5M38.6 48.5l-.3 .1M38.6 48.2v.2h-.3M38.6 57.4v.5M56 51h.5M56 48.6h.5M56.3 48.4v.5"/>
<path d="M56.7 51.1l.6 .2-.6 .1M56.7 48.9l.6 .2-.6 .1M56.9 48.4h.4M57 48.2v.4M57 50.4v.4M58.1 50.8h.2M58.1 50.5h.2l-.2 .1M58.3 50.2l-.2 .1M58.3 50.1l-.2 .1M59.3 50.2h.3M59.3 49.9h.3l-.3 .1M59.6 49.7h-.3"/>
<path d="M59.6 49.5l-.3 .1M71 52.2h.5M71 49.8h.5M71.2 49.6v.5M71.7 52.3l.6 .2-.6 .1M71.7 50.1l.6 .1-.6 .2M71.8 49.7h.5M72.1 49.4v.4M72.1 51.6v.4M72.4 58.2h.2l.2-.2-.4-.1v.6M72.4 59.4h.2l.2-.3h-.4v.5M73 57.9h.3l-.1 .6h-.2l-.1-.3z"/>
<path d="M73 59.1h.3l-.1 .5h-.2l-.1-.2zM73.1 51.9l.2 .1M73.1 51.7h.2l-.2 .1M73.3 51.4l-.2 .1M73.3 51.3l-.2 .1M73.4 58.5l.3-.6 .2 .6M73.5 59.1l.1 .5 .2-.4 .1 .4 .1-.5M73.5 58.3h.4M74.3 51.4h.2M74.3 51.1h.2l-.2 .1M74.5 50.8l-.2 .1M74.5 50.7l-.2 .1"/>
<path d="M76.5 57l.6 .3-.6 .1M76.7 56.7l.3-.1 .2 .3h-.5zM76.7 56.2h.4l.1 .2h-.5zM77.1 40.1l.6 .2-.6 .2M80.1 59.1h-.4v.2l.4 .1-.1 .2h-.3M80.2 57.7h1.1M80.6 57.9h-.2l-.1 .1 .1 .5 .2-.1M80.6 59.1h-.3v.5h.3M80.9 59.1v.5M81 59.3l.2 .3M81.2 57.9h-.3v.2l.3 .1v.3h-.3M81.2 59.1l-.3 .3"/>
<path d="M129.9 49.9h1M130.3 48.9l-.4 .1 .4 .2v.2h-.4M130.3 47.7l-.2-.1-.2 .2 .4 .2v.2h-.4M130.3 50.1h-.2l-.2 .2 .1 .3h.3M130.5 47.6l.4 .1-.1 .5h-.3zM130.9 50.1l-.4 .1 .4 .2v.2h-.4M130.9 48.9l-.4 .1v.3l.2 .2 .2-.1M131.1 47.6v.6M131.1 48.9v.6M131.2 49.1l.3 .4M131.5 48.9l-.4 .3M131.9 47.6l-.5 .8"/>
<path d="M132.4 47.7h-.4l.1 .3h.3v.2h-.4M132.6 47.6l.4 .2-.1 .4h-.3zM133.3 47.6l.3 .1-.1 .5-.3-.1zM134.1 46.8l.6 .2-.6 .2M134.1 52.1l.6 .2-.6 .2M134.2 46.4l.1 .3 .4-.3v.3M134.2 45.9v.3h.2l.2-.3 .1 .1v.2M134.2 51.7l.3-.1 .2 .2v.1h-.5zM134.2 51.3l.5-.1v.2h-.5zM136.6 57.8l.3 .1M136.6 57.5h.3l-.3 .1M136.9 57.3l-.3 .1"/>
<path d="M136.9 57.1l-.3 .1M137.2 49.1h.3v-.2h-.3v.6M137.3 48h.3v-.3l-.3-.1v.6M137.4 50.3h.3v-.2h-.3v.6M137.8 49h.3v.3l-.1 .2-.2-.2zM137.9 57.1h.1l-.1 .2h.1M137.9 56.9h.1v.1h-.1M138 50.1l.3 .1v.3l-.2 .2-.1-.2zM138 47.6l.2 .2-.1 .4-.2-.1v-.3zM138 56.7l-.1 .1M138 56.4v.2h-.1M138.3 48.9l.2 .6 .1-.4 .1 .4 .1-.6"/>
<path d="M138.5 50.7l.1-.6 .3 .6M138.5 48l.3-.2-.2-.2h-.1v.6h.3v-.2h-.2M138.6 50.5h.2M138.8 56.7l.7 .2-.7 .1M138.8 58.9l.7 .2-.7 .1M139 58.5h.5M139.2 56v.4M139.2 58.2v.4M139.7 58.8h.5M139.7 56.4h.5M139.9 58.6v.5M151.7 59l.1 .1"/>
<path d="M151.7 58.7h.1l-.1 .1M151.8 58.5h-.1M151.8 58.3l-.1 .1M152.9 58.4l.2 .1M152.9 58.1h.2l-.2 .1M153.1 57.9l-.2 .1M153.1 57.7l-.2 .1M153.9 57.9l.6 .1-.6 .3M154 59.6h.5M154.2 57.2v.4M154.2 59.4v.4M154.7 60h.5"/>
<path d="M154.7 57.6h.5M154.9 59.8v.4M172.3 51h.5M172.3 48.6h.5M172.6 59.9h.2v.2h-.2M172.6 50.8v.5M172.8 59.6v.2h-.2M172.8 59.5l-.2 .1M173 48.9l.6 .2-.6 .1M173 51.1l.6 .2-.6 .1M173.2 50.6h.4M173.4 48.2v.4"/>
<path d="M173.4 50.4v.4M173.9 59.6h.1M173.9 59.3h.1l-.1 .1M174 59.1h-.1M174 58.9l-.1 .1M174.5 49.3h.2l-.2 .2h.2M174.5 49.1h.2l-.2 .1M174.7 48.9l-.2 .1M174.7 48.6v.2h-.2M174.8 59.1l.7 .1-.7 .3M175.2 58.4v.5M175.6 49.9h.3l-.3 .2h.3"/>
<path d="M175.6 49.7h.3l-.3 .1M175.7 58.8h.4M175.9 49.5l-.3 .1M175.9 49.2v.2h-.3M192.8 40.3l.6 .1-.6 .3M193.8 59.6v.5M194.5 40.2l.4-.1-.2-.3h-.2v.6M194.6 40.2l.3 .2M194.9 41.4h.5M195.1 60h.2l.2-.3-.4-.1v.6M195.1 41.2v.5M195.2 60l.3 .2"/>
<path d="M195.4 40.4l-.4-.1 .1-.2h.3v.4l-.2 .2-.1-.1M195.5 58.8h.5M196 59.8v.5l-.2 .2-.1-.1M196 59.9l-.2-.1-.2 .2 .1 .2h.3M15.3 68.4h.2l.1-.2-.3-.2v.6M15.3 70.7h.2l.1-.1-.3-.1v.6M15.3 72h.4M15.3 67.2h.4M15.4 68.4l.2 .2M15.4 70.7l.2 .4M15.5 67v.4M16.1 68.6l-.3-.1 .1-.2h.2v.4l-.1 .2-.1-.1"/>
<path d="M16.1 71l-.1 .1-.2-.2 .1-.2h.2v.5h-.2M17.1 70.8l.6 .3-.6 .1M17.1 68.6l.6 .3-.6 .1M17.2 68.2h.5M17.5 68v.5M17.5 70.2v.5M18.3 69.3l.1 .2h.5M18.5 69.3v.3M18.6 70.6v-.4h-.3v.4h.6M18.8 69.7v.3h-.3v-.3h.2v.3M18.9 70.2l-.3 .2M35 72h.5"/>
<path d="M35 69.6h.5M35.3 69.4v.4M35.7 72l.6 .3-.6 .1M35.7 69.8l.6 .3-.6 .1M35.9 69.4h.4M36.1 69.2v.4M36.1 71.4v.4M37.1 71.8h.2M37.1 71.5h.2l-.2 .1M37.3 71.2l-.2 .1M37.3 71.1l-.2 .1M37.5 60.1l.6 .1-.6 .2"/>
<path d="M37.6 79.6h.5M37.9 79.4v.5M38.3 71.1h.3l-.3 .1h.3M38.3 70.8l.3 .1-.3 .1M38.3 79.8h.5M38.6 70.7h-.3M38.6 70.4v.2h-.3M38.6 79.6v.5M56 73.2h.5M56 70.8h.5M56.3 70.6v.5M56.7 73.3l.6 .1-.6 .2"/>
<path d="M56.7 71.1l.6 .1-.6 .2M56.9 70.7h.4M57 70.4v.4M57 72.6v.4M58.1 72.9l.2 .1M58.1 72.7h.2l-.2 .1M58.3 72.4l-.2 .1M58.3 72.3h-.2M59.3 72.3l.3 .1M59.3 72.1h.3l-.3 .1M59.6 71.8l-.3 .1M59.6 71.7l-.3 .1"/>
<path d="M71.6 74.4h.5M71.6 72h.5M71.8 71.8v.5M72.3 74.5l.6 .1-.6 .2M72.3 72.3l.6 .1-.6 .3M72.4 60.6l.4-.1-.1-.3h-.3v.6M72.4 71.8h.5M72.7 71.6v.4M72.7 73.8v.4M73 60.2l.3 .1v.5h-.3l-.1-.1zM73.5 60.6l.4-.1v-.3h-.4v.6l.5-.1-.2-.1M73.7 74.1l.3 .1"/>
<path d="M73.7 73.9h.3l-.3 .1M74 73.6v.2h-.3M74 73.4l-.3 .1M74.9 73.5l.2 .1M74.9 73.3h.2l-.2 .1M75.1 73l-.2 .1M75.1 72.9h-.2M76.5 62.3l.6 .1-.6 .3M76.7 61.8v.3h.1l.2-.3 .2 .1-.1 .2M76.7 61.4l.1 .3 .1-.3h.2v.3M77.1 79.2l.6 .3-.6 .1M77.3 78.9l.3-.1 .2 .2h-.5z"/>
<path d="M77.3 78.4l.2-.1 .3 .1v.2h-.5zM77.9 60.2l-.3 .1 .3 .5h-.3M78.2 60.2h.2l.1 .2-.1 .4h-.2zM78.8 60.2v.6M79.5 60.2l-.5 .8M80.1 60.2l-.5 .1 .5 .4-.5 .1M80.3 60.2h.2l.1 .3-.1 .3h-.2zM80.8 79.9h1.1M80.9 60.2l.3 .1v.5h-.3l-.1-.1zM92.1 79.2h.6l-.6 .3h.6M92.1 79.8h.6M93.3 79.8h.6l-.6 .3h.6"/>
<path d="M93.3 79.3l.5-.1 .1 .3h-.6zM94.4 79.7l.6 .2-.6 .2M94.4 79.5v-.3l.3 .2v-.2h.3v.3M95.6 79.7l.5 .4M96.3 79.4h-.7l.3 .1M96.3 79.2v.3M96.3 79.7l-.3 .3M96.9 79.7l.6 .4M97.5 79.4h-.6l.2 .1M97.5 79.2v.3M97.5 79.7l-.6 .4M98.1 79.7l.3 .4"/>
<path d="M98.7 79.4h-.6l.2 .1M98.7 79.2v.3M98.7 79.7l-.4 .3M99.3 79.7l.3 .4M99.9 79.4h-.6l.1 .1M99.9 79.7l-.4 .3M99.9 79.2v.3M100.5 79.6v.3l.2 .2 .3-.2v-.3M101 79.1v.3h-.5M101.7 79.7h.5v.4h-.6zM102.1 79.2v.3M102.2 79.1l-.6 .2 .6 .2"/>
<path d="M103.3 79.7v.4M103.5 79.7l-.7 .2 .7 .2M103.5 79.4h-.7l.3 .1M103.5 79.2v.3M104.7 79.7v.3h-.6M104.7 79.4h-.6l.2 .1M104.7 79.2v.3M105.3 79.2h.6l-.6 .3h.6M105.3 79.8h.6M106 80v.4M106.5 79.6l.6 .1v.3h-.6M106.5 79.1v.4"/>
<path d="M106.5 79.3h.6M107.7 79.8v.3h.5v-.3M107.7 79.3l.5-.1v.3h-.5zM108 79.9v.2M108.8 79.8h.6l-.6 .3h.6M108.9 79.2h.4l.1 .3h-.6zM110.7 79.9h-.7l.3 .2M110.7 79.4l-.7-.3v.4M110.7 79.7v.4M111.3 79.2v.3h.2h.2l.2-.2-.4-.1v.2l.1 .1M111.9 79.9h-.6l.2 .2M111.9 79.7v.4"/>
<path d="M112.9 79.2v.3M113.1 79.9h-.6l.1 .2M113.1 79.1l-.6 .2 .6 .2M113.1 79.7v.4M113.7 79.8h.6l-.6 .3h.6M114.3 79.4h-.6l.1 .1M114.3 79.2v.3M114.9 79.2v.3l.3-.1v-.2h.2v.3M114.9 79.7v.3l.2 .1 .3-.1v-.3M116.1 79.7l-.1 .2 .3 .2 .3-.1v-.3M116.1 79.2l-.1 .2 .2 .1 .2-.3h.2v.3M117.2 79.7l.7 .4"/>
<path d="M117.6 79.3l.2-.1 .1 .2-.3 .1-.1-.3-.3 .1 .2 .2 .2-.1M117.9 79.7l-.7 .4M118.5 79.7l.6 .4M118.7 79.3h.4l-.3 .2-.1-.3h-.2l.1 .3 .1-.1M119.1 79.7l-.6 .4M119.7 79.7l.3 .4M120.3 79.2v.3l-.4-.3h-.2v.3M120.3 79.7l-.4 .3M130.5 71.5h1M130.9 70.5l-.4 .1 .4 .2v.2h-.4M130.9 69.3l-.2-.1-.2 .2 .4 .2v.2h-.4M130.9 71.7h-.2l-.2 .2 .1 .3h.3"/>
<path d="M131.1 69.2a.33 .33 0 0 1 .4 .2 .33 .33 0 0 1-.1 .4h-.3zM131.5 71.7l-.4 .1 .4 .3-.1 .2-.3-.1M131.5 70.5l-.4 .1 .1 .4h.3M131.8 69.2v.6M131.8 70.5v.6M131.9 70.7l.2 .4M132.1 70.5l-.3 .3M132.5 69.2l-.5 .8M133 69.3h-.4v.2l.4 .1v.2h-.4M133.2 69.2l.4 .2-.1 .4h-.3zM133.8 69.3h.4v.5l-.4-.1zM134.7 68.4l.6 .2-.6 .2"/>
<path d="M134.7 73.7l.6 .2-.6 .1M134.8 67.9l.1 .4 .4-.4v.4M134.8 67.5v.3h.3l.1-.3 .1 .1v.2M134.8 73.3h.5v.2h-.5zM134.8 72.9l.5-.1v.2h-.5zM137.3 80l.2 .1M137.3 79.7h.2l-.2 .1M137.5 79.5h-.2M137.5 79.3l-.2 .1M137.8 70.7h.3v-.2h-.3v.6M137.9 69.6h.3l-.1-.4h-.2v.6M138 71.9h.3v-.2h-.3v.6"/>
<path d="M138.4 70.6h.3v.3l-.1 .2-.2-.2zM138.5 79.4l.2 .1M138.5 79.1h.2l-.2 .1M138.6 71.7l.3 .1v.3l-.2 .2-.1-.2zM138.6 69.2l.2 .2-.1 .4-.2-.1v-.3zM138.7 78.9l-.2 .1M138.7 78.7l-.2 .1M138.9 70.5l.2 .6v-.4l.2 .4 .1-.6M139.1 72.3l.1-.6 .3 .6M139.1 69.6l.3-.2-.2-.2h-.1v.6h.3v-.2h-.2M139.1 72.1h.3M139.5 78.9l.6 .1-.6 .2"/>
<path d="M139.8 78.2v.4M140.3 78.6h.5M153.1 79.9l-.2 .1M153.9 60.1l.6 .1-.6 .2M154.2 79.4v.5M154.7 79.8h.5M172.3 73.2h.5M172.3 70.8h.5M172.6 60.2h.2M172.6 73v.4M173 71.1l.6 .1-.6 .2M173 73.3l.6 .1-.6 .2"/>
<path d="M173.2 72.9h.4M173.4 70.4v.4M173.4 72.6v.4M174.5 71.5h.2l-.2 .2h.2M174.5 71.2l.2 .1-.2 .1M174.7 71.1l-.2 .1M174.7 70.8v.2h-.2M174.8 61.3l.7 .1-.7 .3M175 60.8h.5M175.2 60.6v.5M175.6 72.2l.3 .1M175.6 71.9h.3l-.3 .1"/>
<path d="M175.7 61.3h.4M175.9 71.7l-.3 .1M175.9 71.5l-.3 .1M175.9 61v.4M192.2 60.1v.1h.6M192.4 60.1v.2M192.6 61.3v-.1l-.3-.2-.1 .3h.6M192.8 60.5l-.1 .3h-.2l-.1-.2 .2-.1 .1 .3M192.8 61l-.2 .3M193.4 60.2l.6 .2-.6 .3M193.4 62.4l.6 .2-.6 .3M193.6 62h.4"/>
<path d="M193.8 61.8v.5M195.1 62.4l.4-.1-.2-.3h-.2v.6M195.2 62.4l.3 .2M195.5 63.6h.5M195.7 63.4v.5M196 62.6l-.4-.1 .1-.2h.3v.4l-.3 .2M15.3 90.6l.3-.1-.1-.3h-.2v.6M15.3 92.9h.2l.1-.1-.3-.1v.6M15.3 94.2h.4M15.3 89.5h.4M15.4 90.6l.2 .2M15.4 92.9l.2 .4"/>
<path d="M15.5 89.2v.4M16.1 90.8l-.3-.1 .1-.2h.2v.4l-.1 .2-.1-.1M16.1 93.2l-.1 .1-.2-.2 .1-.3h.2v.5l-.2 .1M17.1 93l.6 .3-.6 .1M17.1 90.8l.6 .3-.6 .1M17.2 90.4h.5M17.5 90.2v.4M17.5 92.4v.4M18.3 91.5l.1 .2h.5M18.5 91.5v.2M18.6 92.8v-.4h-.3v.4h.6M18.8 91.9v.3h-.3v-.3h.2v.3"/>
<path d="M18.9 92.4l-.3 .2M35 94.2h.5M35 91.8h.5M35.3 81.3l.2 .1M35.3 81.1h.2l-.2 .1M35.3 91.6v.5M35.5 80.8v.2h-.2M35.5 80.6l-.2 .1M35.7 94.3l.6 .1-.6 .2M35.7 92.1l.6 .1-.6 .2M35.9 91.6h.4M36.1 91.4v.4"/>
<path d="M36.1 93.6v.4M36.5 81.9h.2l-.2 .2h.2M36.5 81.7h.2v.1h-.2M36.7 81.4v.2h-.2M36.7 81.2l-.2 .1M37.1 93.9l.2 .1M37.1 93.7h.2l-.2 .1M37.3 93.4l-.2 .1M37.3 93.3h-.2M37.5 82.3l.6 .1-.6 .3M37.5 80.1l.6 .1-.6 .3M37.9 81.6v.4"/>
<path d="M38.3 93.3l.3 .1M38.3 93.1h.3l-.3 .1M38.3 82.3h.5M38.6 92.8l-.3 .1M38.6 92.7l-.3 .1M56 95.4h.5M56 93h.5M56.3 92.8v.5M56.7 95.5l.6 .1-.6 .2M56.7 93.3l.6 .1-.6 .2M56.9 92.8h.4M57 92.6v.4"/>
<path d="M57 94.8v.4M58.1 95.1l.2 .1M58.1 94.9h.2l-.2 .1M58.3 94.6l-.2 .1M58.3 94.4l-.2 .1M59.3 94.5l.3 .1M59.3 94.3h.3l-.3 .1M59.6 94l-.3 .1M59.6 93.9h-.3M71.6 96.6h.5M71.6 94.2h.5M71.8 94v.4"/>
<path d="M72.3 96.6l.6 .2-.6 .3M72.3 94.4l.6 .2-.6 .3M72.4 94h.5M72.7 93.8v.5M72.7 96v.4M73 80.4l.4-.2-.1-.1h-.3v.5M73 81.6h.2l.2-.3-.4-.1v.6M73 82.8h.3l.1-.2-.4-.2v.6M73.6 80.1h.3v.5h-.3zM73.6 81.2h.3v.6h-.3zM73.7 96.3h.3l-.3 .2h.3M73.7 96.1h.3l-.3 .1"/>
<path d="M73.7 82.4l.3 .3-.1 .3h-.3l-.1-.2zM74 95.8v.2h-.3M74 95.6l-.3 .1M74.1 80.6l.2-.5 .2 .5M74.1 81.2l.2 .6 .1-.4 .1 .4 .1-.6M74.1 80.5h.4M74.2 82.8l.3-.1-.1-.3h-.2v.6l.3-.1-.1-.1M74.9 95.7l.2 .1M74.9 95.5h.2h-.2M75.1 95.2v.2h-.2M75.1 95l-.2 .1M77.1 84.5l.6 .1-.6 .3"/>
<path d="M77.3 84v.3h.2l.1-.3 .2 .1-.1 .2M77.3 83.6v.3l.2-.3h.2v.3M78.5 82.5h-.3v.2l.3 .1v.2h-.3M78.8 82.4l.3 .2-.1 .4h-.2zM79.4 82.4v.6M80.1 82.4l-.6 .8M80.6 81.2l-.3 .1v.2l.3 .1v.1l-.3 .1M80.6 82.5h-.3v.2l.3 .1v.2h-.3M80.9 82.4a.3 .3 0 0 1 .3 .3 .3 .3 0 0 1-.3 .3zM81.2 80.1h-.2l-.1 .1 .1 .4h.2M81.2 81.3h-.3v.4h.3M81.5 81.2v.6"/>
<path d="M81.6 82.4l.2 .1-.1 .5h-.2l-.1-.2zM81.6 81.5l.2 .3M81.8 80.1h-.3v.2l.3 .1v.2h-.3M81.8 81.2l-.3 .4M92.1 80.1l.6 .1-.6 .2M92.1 99.2l.1 .3 .5-.1v-.2l-.3 .1M92.1 98.6h.6l-.6 .3h.6M92.1 98.1l.3-.2 .3 .2v.2h-.6zM93.3 80.4v.2l.2 .2 .4-.2v-.2h-.3v.2M93.3 99.3l.4-.1 .2 .1v.2h-.6zM93.3 92.6v.3l.6-.3v.3M93.3 97.6l.6 .3"/>
<path d="M93.3 94.8l.6 .3M93.3 96v.3h.5l.1-.3M93.3 93.2v.3h.5l.1-.3M93.6 98.5v-.3h-.3v.3h.6M93.6 95.7v-.3h-.3v.3h.6M93.9 97.2h-.6l.1 .1M93.9 94.2v.4l-.5-.4-.1 .1v.2M93.9 92.2h-.6l.1 .1M93.9 98.2l-.3 .1M93.9 97.6l-.6 .3M93.9 92v.3M93.9 97v.3"/>
<path d="M93.9 95.4l-.3 .1M93.9 94.8l-.6 .3M93.9 93.7v.4M93.9 96.5v.4M93.9 98.7v.4M94.4 80.6v-.4l.3 .3v-.2l.3-.1v.4M94.4 92l.6-.1v.3h-.5zM94.4 98.4h.6M94.4 95.7h.6M94.4 95.5v.5M94.4 98.3v.3M94.4 97.7l.6 .4"/>
<path d="M94.4 95l.6 .5M94.4 93.1h.6M94.5 96.1l-.1 .2 .2 .2h.4v-.4M94.5 92.5v.3h.2l.2-.3h.1v.3M95 99.4h-.6l.2 .1M95 97.3h-.6l.2 .2M95 94.5v.4l-.3-.4-.3 .1 .1 .3M95 93.3h-.6l.5 .3-.5 .2h.6M95 91.5h-.6l.2 .2M95 91.3v.4M95 97.2v.3M95 99.2v.3"/>
<path d="M95 97.7l-.6 .4M95 95l-.6 .5M95.1 93.9v.5M95.1 96.6v.5M95.1 98.7v.4M95.6 87.2v-.3l.3 .2 .1-.2h.2v.3M95.6 97.5h.5l.2 .2-.1 .1h-.6M95.6 97.2h.7M95.6 80.1h.7M95.6 83.1l.7 .4M95.6 97v.3M95.7 84.3v.3l.3 .1 .2-.1v-.3"/>
<path d="M95.7 80.8v.4h.3h.2v-.4M95.7 98.2l.4-.1 .2 .2v.1l-.6 .1zM96 85.4l.1 .2-.4 .1v-.3h.4l.2 .2M96 84v-.2l-.2-.1-.2 .3h.7M96.1 86v.2M96.3 87.5v.3l-.3-.3-.4 .1 .1 .2M96.3 85.9l-.7 .2 .7 .2v.5M96.3 82.8h-.7l.3 .1M96.3 81.5h-.7l.5 .2-.5 .1h.7M96.3 80.3v.3h-.7M96.3 99.2v.4l-.4-.4-.3 .2 .1 .1M96.3 96.5v.3l-.3-.3-.4 .1 .1 .2"/>
<path d="M96.3 82v.4M96.3 82.6v.3M96.3 84.8v.4M96.3 98.7v.4M96.3 83.7l-.3 .2M96.3 83.1l-.7 .4M96.9 80.8l.1 .4h.3l.2-.2-.1-.2M96.9 99.6v-.4l.2 .2 .2-.2 .2 .2-.1 .2M96.9 97.1l.1 .3h.4v-.3M96.9 80.4h.6M96.9 80.2v.4M96.9 96.3h.6"/>
<path d="M96.9 96l.3 .3M97.2 81.9h.3l-.1 .3h-.2v-.3l-.3-.1v.4l.3-.1M97.2 98v-.3h-.3v.3h.6M97.3 82.4v.3M97.5 83.9v.4l-.3-.4h-.3v.4M97.5 83.4v.4l-.4-.4h-.2v.3M97.5 82.3l-.6 .2 .6 .3v.5M97.5 98.2v.3h-.6M97.5 96.6v.2h-.6M97.5 95.4v.4l-.4-.4-.2 .1v.2M97.5 81.2v.5M97.5 98.7v.4"/>
<path d="M97.5 97.7l-.3 .1M97.5 96l-.3 .2M98.1 82.5v.3h.2v-.3h.4l-.1 .3M98.1 80.8v.3a.28 .28 0 0 0 .4 .1 .28 .28 0 0 0 .1-.4M98.1 97.6v.2l.2 .1 .4-.1-.1-.2M98.1 80.1h.6M98.1 83l.6 .4M98.1 96.8h.6M98.1 96.5l.3 .3M98.3 99.3h.4M98.3 81.6l.2-.2 .2 .1v.2h-.6v-.2h.2v.2M98.3 98.3l.1-.1h.3v.3h-.6v-.3h.2v.3"/>
<path d="M98.4 83.9l-.1-.3-.2 .1v.2h.6M98.5 99.2v.3l-.5-.1M98.5 85.2v.4M98.7 86.8v.4l-.4-.4h-.2v.4M98.7 86.4h-.6l.2 .2M98.7 85.2l-.6 .2 .6 .2M98.7 84.9l-.6-.3v.4M98.7 80.3v.3h-.6M98.7 97v.3h-.6M98.7 95.9v.4l-.4-.4-.2 .1v.2M98.7 86.2v.4M98.7 83.6l-.3 .3"/>
<path d="M98.7 83l-.6 .4M98.7 96.5l-.4 .2M98.8 81.9v.4M98.8 84.1v.4M98.8 85.6v.5M98.8 98.7v.4M99.3 86.7l.5-.1 .1 .2-.5 .1zM99.3 85l.1 .4h.4l.1-.4h-.4l.1 .4M99.3 83v.3l.2 .1v-.4h.4l-.1 .4M99.3 99.3v.2h.2v-.2l.3-.1v.3M99.3 97.8h.6l-.6 .4h.6M99.3 80.1h.6"/>
<path d="M99.3 84.2h.6M99.3 84v.4M99.3 83.5l.6 .4M99.3 98.5h.6M99.4 80.8a.28 .28 0 0 0 .1 .4 .28 .28 0 0 0 .4-.1l-.1-.3M99.6 81.7v-.1l-.2-.2-.1 .3h.6M99.7 85.6v.3M99.9 87.2v.3l-.4-.3h-.2l.1 .3M99.9 85.6l-.6 .1 .6 .3M99.9 82v.3h-.6M99.9 80.3v.3h-.6M99.9 97.2v.5l-.5-.5-.1 .1 .1 .3"/>
<path d="M99.9 83.5l-.6 .4M99.9 81.4l-.3 .3M99.9 82.4v.4M99.9 84.5v.4M99.9 86v.5M99.9 98.7v.4M100.5 81.3v.3l.3 .1-.1-.4h.3v.4M100.5 80.2v.4l.5-.4v.4M100.5 99.3l.1 .2h.4v-.3l-.3 .1 .1 .2M100.5 98.2l.4-.1 .1 .1v.2l-.5 .1zM100.5 97.5l.5 .1v.2h-.5M100.5 96l.5-.1v.3h-.5z"/>
<path d="M100.5 97.2h.5M100.5 97v.3M100.7 82.8l.2 .3-.4 .1v-.4h.5v.3M100.9 81.8v.4M101 83.6h-.5l.1 .2M101 81.8l-.5 .2 .5 .2M101 96.6h-.5l.1 .2M101 83.4v.4M101 96.5v.3M101.1 80.7v.5M101.1 82.3v.4M101.1 98.7v.4"/>
<path d="M101.6 96.1l.6-.1v.2l-.5 .1zM101.6 95.3l.6 .1v.2h-.6M101.6 97.6l.6 .3M101.6 94.8v.3M101.6 95h.6M101.7 80.3v.3h.3v-.3h.2v.3M101.9 83l.1-.2h.2v.4h-.2l-.1-.4h-.2l-.1 .3h.3M101.9 81.4h.3M102 98.5v-.3h-.3l-.1 .3h.6M102.1 81.3v.4l-.5-.2M102.1 81.9v.3M102.1 93.8v.2"/>
<path d="M102.2 83.6h-.6l.2 .2M102.2 81.8l-.6 .2 .6 .3M102.2 99.4l-.6-.2v.4M102.2 97v.4l-.4-.4-.2 .2 .1 .1M102.2 94.4h-.6l.2 .2M102.2 93.7l-.6 .2 .6 .2M102.2 83.4v.4M102.2 94.3v.3M102.2 98.2l-.2 .1M102.2 97.6l-.6 .3M102.3 80.7v.5M102.3 82.3v.5"/>
<path d="M102.3 96.5v.4M102.3 98.7v.4M102.8 95.8h.7l-.7 .3h.7M102.8 84.3v-.4l.3 .2 .1-.2h.2v.4M102.8 83v.4M102.8 98.3v.3M102.8 98.4h.7M102.8 97.7l.7 .4M102.8 96.5h.7M102.8 83.2h.7M102.8 82.4l.7 .4M102.9 80.9l-.1 .2 .2 .1 .3-.3h.1v.3"/>
<path d="M102.9 80.3a.38 .38 0 0 1 .4 0 .38 .38 0 0 1 .2 .3h-.7zM103.1 81.9h.4M103.2 99.4l.1-.2 .2 .2-.1 .1h-.2l-.2-.3-.2 .2 .1 .1 .3-.1M103.3 81.8v.5l-.5-.2M103.3 84.5v.3M103.5 97.2v.3l-.3-.3h-.4l.1 .3M103.5 95.4h-.7l.3 .1M103.5 86.2h-.7l.3 .2M103.5 85.7l-.7-.2v.4M103.5 84.5l-.7 .1 .7 .3v.5M103.5 81.3v.4M103.5 83.4v.5"/>
<path d="M103.5 86.1v.3M103.5 95.2v.3M103.5 96.6v.5M103.5 98.7v.4M103.5 97.7l-.7 .4M103.5 82.4l-.7 .4M104.1 98.2l.3-.1 .3 .2v.1l-.5 .1zM104.1 97.5h.4l.2 .2-.1 .1h-.5M104.1 95.9l.1 .3h.4v-.3M104.1 85.6v.3l.3 .1 .3-.2-.1-.2-.3 .1 .1 .3M104.1 80.8v.4h.3l.1-.4 .2 .2-.1 .2M104.1 80.2v.3a.33 .33 0 0 0 .4 .1 .33 .33 0 0 0 .2-.3l-.1-.1"/>
<path d="M104.1 97v.3M104.1 97.2h.6M104.1 82.4l.6 .4M104.3 81.9h.4M104.4 99.2v.3h-.3l.1-.3 .4 .1 .1 .2M104.4 83.4v-.4h-.3v.4h.6M104.4 81.8v.4l-.4-.1M104.5 84.6v.3M104.7 96.6h-.6l.2 .2M104.7 86.3h-.6l.2 .2M104.7 84.5l-.6 .3 .6 .2M104.7 84v.5l-.4-.5-.2 .1v.3"/>
<path d="M104.7 81.3v.4M104.7 83.5v.4M104.7 85v.5M104.7 86.1v.4M104.7 96.5v.3M104.7 98.7v.4M104.7 83l-.3 .2M104.7 82.4l-.6 .4M105.3 98.7h.5l.1 .2h-.6zM105.3 97.6l.1 .3h.4v-.3M105.3 97v.3h.2l.2-.3 .2 .1v.2M105.3 95.3l.4-.1 .2 .1v.2l-.5 .1z"/>
<path d="M105.3 94.7l.1 .3 .2-.3h.3v.3M105.3 87.3v.3l.2 .1v-.4h.4l-.1 .4M105.3 83.9v-.3l.2 .2v-.2h.4l-.1 .3M105.3 82.5v.3h.2l.2-.3 .2 .1v.2M105.3 81.5a.31 .31 0 0 1 .3-.2 .31 .31 0 0 1 .3 .4h-.6zM105.3 80.6v.2h.6M105.3 84.1l.6 .4M105.3 81.1h.6M105.5 80.6v.2M105.6 94.4v-.2l-.3-.1v.3h.6M105.6 85v-.2l-.3-.1v.3h.6M105.6 82.3v-.2l-.2-.2-.1 .4h.6"/>
<path d="M105.7 86.3v.4M105.9 99.4h-.6l.2 .1M105.9 95.9h-.6l.4 .2-.4 .2h.6M105.9 88.1h-.6l.2 .2M105.9 86.3l-.6 .2 .6 .2M105.9 86h-.6l.2 .1M105.9 85.8v.3M105.9 87.9v.4M105.9 99.2v.3M105.9 94.1l-.3 .2M105.9 84.7l-.3 .2M105.9 84.1l-.6 .4"/>
<path d="M106 95.2l-.3 .3M106 83v.4M106 85.2v.4M106 86.7v.5M106 96.5v.4M106 98.1v.4M106.5 97l.5-.1 .1 .3h-.5zM106.5 96.3l.1 .3h.1l.1-.3 .3 .1v.2M106.5 86.5l.3-.1 .3 .1v.2h-.5zM106.5 84.7v-.3l.2 .1v-.1h.3v.3M106.5 83.4l.1 .3h.1l.1-.3h.3v.3M106.5 82.3l.5-.1 .1 .3h-.6z"/>
<path d="M106.5 81.3v.3h.6M106.5 80.3l.4-.1 .2 .1v.3h-.5zM106.5 96.1h.6M106.5 85.5v.3M106.5 94.4v.4M106.5 94.6h.6M106.5 93.9l.6 .4M106.5 81.9h.6M106.5 85.6h.6M106.5 84.9l.6 .4M106.6 95v.3h.4v-.3M106.6 88h.5"/>
<path d="M106.7 81.4v.2M106.8 83.1v-.3h-.3v.3h.6M106.9 87.9v.4l-.4-.1M106.9 87v.2M107.1 99.4h-.6l.1 .1M107.1 98.8h-.6l.1 .2M107.1 97.5h-.6l.4 .2-.4 .2h.6M107.1 93.5h-.6l.1 .2M107.1 88.7h-.6l.1 .2M107.1 86.9l-.6 .3 .6 .1M107.1 88.5v.4M107.1 93.3v.4"/>
<path d="M107.1 98.7v.3M107.1 99.2v.3M107.1 93.9l-.6 .4M107.1 84.9l-.6 .4M107.1 80.8v.4M107.1 83.8v.5M107.1 85.9v.4M107.1 87.4v.4M107.1 95.5v.4M107.1 98.1v.4M107.7 96.6v.4l.5-.4v.4M107.7 96.1h.5v.2l-.5 .1z"/>
<path d="M107.7 94.4l.5-.1v.2l-.5 .1zM107.7 93.7v.3l.5-.3v.3M107.7 83.9v-.4l.2 .2v-.2h.3v.4M107.7 82.4v.4h.2l.2-.4 .1 .1v.3M107.7 97.2h.5M107.7 81.6h.5M107.7 81.2l.3 .4M107.7 81.8v.3l.2 .2 .3-.2v-.3M108.2 99.4h-.5l.1 .1M108.2 98.7v.3l-.3-.3h-.2v.3M108.2 97.5h-.5l.4 .2-.4 .2h.5M108.2 94.9h-.5l.4 .2-.4 .2h.5"/>
<path d="M108.2 93.1v.3h-.5M108.2 84.2h-.5l.1 .2M108.2 80.2v.4h-.5M108.2 84v.4M108.2 99.2v.3M108.2 81.2l-.3 .3M108.3 94.2l-.1 .3M108.3 80.7v.5M108.3 82.9v.5M108.3 95.5v.4M108.3 98.1v.4M108.8 99.6v-.4l.3 .2v-.1l.2-.1 .1 .4"/>
<path d="M108.8 98.7l.6 .1-.6 .2M108.8 98.5v-.4l.3 .2v-.1l.2-.1 .1 .4M108.9 80.4l-.1 .1a.33 .33 0 0 0 .3 .3 .33 .33 0 0 0 .3-.2v-.2h-.2v.2M110 96.6h.7a.35 .35 0 0 1-.3 .3 .35 .35 0 0 1-.4-.3zM110 94.5l.2 .3h.4l.1-.2-.2-.2-.2 .2 .1 .2M110 95.5v.4M110 95.7h.7M110 95l.7 .4M110.1 93.4v.4h.3l.1-.4 .2 .2-.1 .2M110.1 92.8v.4h.5v-.4M110.3 98.7h.4M110.3 81.9h.4"/>
<path d="M110.4 98.6v.4l-.4-.2M110.4 81.8v.4l-.4-.1M110.5 80.3v.3M110.5 97.7v.2M110.7 99.2v.4l-.4-.4-.3 .2 .1 .1M110.7 97.6l-.7 .2 .7 .2M110.7 97.2h-.7l.3 .2M110.7 92.3v.3h-.7M110.7 91.8v.4l-.3-.4-.4 .1 .1 .3M110.7 81.5h-.7l.3 .2M110.7 80.2l-.7 .3 .7 .1M110.7 80.7v.5"/>
<path d="M110.7 81.3v.4M110.7 93.9v.5M110.7 96v.4M110.7 97.1v.3M110.7 98.1v.4M110.7 95l-.7 .4M111.3 98.7v.2l.2 .1v-.2l.3-.1v.3M111.3 94.4v.2l.2 .1h.2l.2-.3h-.4v.1l.1 .2M111.3 93.3l.1 .4 .3-.4 .2 .1-.1 .3M111.3 92.8a.33 .33 0 0 1 .3-.1 .33 .33 0 0 1 .3 .3h-.6zM111.3 81.3l.6 .1a.3 .3 0 0 1-.4 .3 .3 .3 0 0 1-.2-.4zM111.3 94.9l.6 .4"/>
<path d="M111.5 81.9h.4M111.5 95.8v-.3h-.2v.3h.6M111.6 81.8v.4l-.4-.1M111.7 80.3v.3M111.7 92.2v.3M111.7 97.7v.2M111.9 99.2v.4l-.4-.4-.2 .1v.2M111.9 97.6l-.6 .2 .6 .2M111.9 97.2h-.6l.2 .2M111.9 96.7h-.6l.2 .2M111.9 92.2l-.6 .1 .6 .2M111.9 91.7v.3l-.4-.3h-.2v.3"/>
<path d="M111.9 80.2l-.6 .3 .6 .1M111.9 80.7v.5M111.9 93.8v.4M111.9 96v.4M111.9 96.6v.3M111.9 97.1v.3M111.9 98.1v.4M111.9 95.5l-.4 .1M111.9 94.9l-.6 .4M112.5 98.7v.2l.2 .1h.3l.1-.3h-.4l.1 .3M112.5 94.9l.5-.1 .1 .2-.5 .1zM112.5 94.2v.3h.2l.1-.3 .3 .1v.2"/>
<path d="M112.5 86.6v-.4l.2 .2v-.2h.4l-.1 .4M112.5 83.6v.3h.2l.2-.3 .2 .1v.2M112.5 83.1l.5-.1 .1 .4h-.5h-.1zM112.5 81.4l.4-.1 .2 .1v.3h-.5zM112.5 80.7l.6 .1v.3h-.6M112.5 93.9h.6M112.5 80.4h.6M112.5 84.2h.6M112.5 80.2v.4M112.7 85.6l.1 .4h-.3v-.4h.4l.2 .3M112.9 97.7v.2M113.1 99.2v.4l-.5-.4-.1 .1v.2"/>
<path d="M113.1 97.6l-.6 .2 .6 .2M113.1 97.2h-.6l.1 .2M113.1 96.6v.3l-.4-.3h-.2v.3M113.1 95.4h-.6l.4 .2-.4 .2h.6M113.1 93.5h-.6l.1 .2M113.1 84.5h-.6l.4 .2-.4 .2h.6M113.1 82.6h-.6l.1 .2M113.1 82.4v.4M113.1 93.3v.4M113.1 97.1v.3M113.2 81.8v.5M113.2 85v.6"/>
<path d="M113.2 96v.4M113.2 98.1v.4M113.7 96.9v-.3l.2 .1v-.1h.4l-.1 .3M113.7 95.5v.3a.3 .3 0 0 0 .3 0 .3 .3 0 0 0 .1-.3h.2v.4M113.7 84.3v-.4l.2 .2v-.2h.3v.4M113.7 81.7v.3h.2l.2-.3h.2v.3M113.7 94.6h.6M113.7 94.3l.3 .3M113.7 80.4h.6M113.7 94.9a.28 .28 0 0 0 .2 .3 .28 .28 0 0 0 .4-.1l-.1-.2M113.7 82.3v.3h.5v-.3M113.9 83.4h.4l-.1 .3-.3-.1v-.2h-.2v.3l.2-.2"/>
<path d="M114.1 97.7v.2M114.3 99.2v.4l-.5-.4-.1 .1v.2M114.3 98.8l-.6-.2v.4M114.3 97.6l-.6 .2 .6 .2M114.3 97.2h-.6l.1 .2M114.3 93.9h-.6l.1 .2M114.3 81.3h-.6l.1 .2M114.3 81.2v.3M114.3 93.8v.3M114.3 97.1v.3M114.3 94.3l-.4 .2M114.3 80.6v.4"/>
<path d="M114.3 82.8v.4M114.3 96v.4M114.3 98.1v.4M114.9 81.7v-.3l.2 .2v-.2h.3v.3M114.9 97l.5 .4M115.1 98.8l.3-.1v.3l-.3-.2v-.1h-.2v.3l.2-.2M115.2 97.9v-.2l-.3-.1v.3h.5M115.4 99.2v.4l-.4-.4-.1 .1v.2M115.4 96.6l-.5-.2v.4M115.4 81.1l-.5-.3v.4M115.4 97.6l-.2 .1M115.4 97l-.5 .4"/>
<path d="M115.5 80.2v.5M115.5 98.1v.4M116 81.7v-.3l.3 .2v-.2h.3v.3M116 80.9l.2 .3h.4v-.4l-.3 .1 .1 .3M116 97.7v.3M116 97.8h.6M116 97.2l.6 .3M116.3 98.7l.2 .1-.3 .2-.2-.2 .1-.1h.4l.1 .2M116.6 99.2v.4l-.4-.4-.2 .2 .1 .1M116.6 96.8l-.6-.2v.4M116.6 97.2l-.6 .3M116.7 80.2v.5"/>
<path d="M116.7 98.1v.4M117.2 99.6v-.4l.3 .2 .2-.2 .2 .2-.1 .2M117.2 98.8h.7a.35 .35 0 0 1-.3 .2 .35 .35 0 0 1-.4-.2zM117.2 96.2v-.3l.3 .2 .1-.2h.2v.3M117.2 82.2v-.4l.3 .2 .1-.2h.2v.4M117.2 81.2v.4h.4v-.4l.3 .1-.1 .3M117.2 96.4l.7 .4M117.2 80.2v.4M117.2 80.4h.7M117.3 97.6v.3h.5v-.3M117.6 97.3v-.3l-.4 .1v.2h.7M117.9 80.6v.6"/>
<path d="M117.9 98.1v.4M117.9 97l-.3 .2M117.9 96.4l-.7 .4M118.5 99.6v-.4l.2 .2 .2-.2 .2 .2-.1 .2M118.5 97.6l.1 .3h.4v-.3M118.5 96.4v-.4l.2 .2 .2-.2 .2 .1-.1 .3M118.5 82.3v-.4l.2 .3 .2-.3 .2 .2-.1 .2M118.5 97.2h.6M118.5 97.1v.3M118.5 96.6l.6 .3M118.7 81.4h.4M118.7 80.6v-.3h-.2v.3h.6"/>
<path d="M118.8 81.3v.4l-.4-.1M119.1 98.8h-.6l.2 .2M119.1 80.8v.4M119.1 98.1v.4M119.1 98.7v.3M119.1 96.6l-.6 .3M119.1 80.3l-.4 .3M119.7 99.6v-.4l.2 .2v-.1l.3-.1v.4M119.7 97.7l.5-.1 .1 .2-.5 .1zM119.7 97h.6l-.1 .3h-.5M119.7 83.5v-.3l.2 .2v-.2h.4l-.1 .3M119.7 82.9v-.3l.2 .2v-.2h.4l-.1 .3"/>
<path d="M119.7 80.8v.3a.28 .28 0 0 0 .4 .1 .28 .28 0 0 0 .1-.4M119.7 96.4v.3M119.7 96.6h.6M119.7 80.1h.6M119.9 95.5l.1-.2 .3 .1v.2h-.6l.1-.3 .1 .1v.2M120.3 98.7v.3l-.4-.3h-.2v.3M120.3 96.1h-.6l.1 .1M120.3 81.5h-.6l.4 .2-.4 .1h.6M120.3 80.3v.3h-.6M120.3 95.9v.3M120.4 82v.4M120.4 98.1v.4"/>
<path d="M129.3 94.3h1M129.7 93.3h-.4l.4 .3v.2h-.4M129.7 92.1l-.4 .1 .4 .2v.2h-.4M129.8 94.5a.28 .28 0 0 0-.4 .2 .28 .28 0 0 0 .1 .3h.3M129.9 92.1l.4 .1v.4l-.2 .1h-.2zM130.3 94.4l-.4 .1 .4 .3v.2h-.4M130.3 93.3h-.4v.4l.2 .2 .2-.1M130.5 92.1v.6M130.5 93.3v.6M130.6 93.5l.3 .4M130.9 93.3l-.4 .3M131.3 92l-.5 .8"/>
<path d="M131.8 92.1h-.4l.1 .2 .3 .1-.1 .3-.3-.1M132 92.1l.4 .1v.3l-.2 .2h-.2zM132.7 92.1l.3 .1-.1 .5-.3-.1zM133.5 91.2l.6 .2-.6 .2M133.5 96.5l.6 .1-.6 .2M133.6 90.8l.1 .3 .2-.3h.2v.3M133.6 90.3v.3h.2l.1-.3 .3 .1-.1 .2M133.6 96.1l.3-.1 .3 .1v.2h-.6zM133.6 95.6l.5-.1 .1 .3h-.6zM136.6 93.5h.3v-.2h-.3v.6M136.7 92.3h.3v-.2h-.3v.6M136.8 94.8h.2l.1-.3-.3-.1v.6"/>
<path d="M137.2 93.3h.3v.4l-.1 .2-.2-.1zM137.3 92.1l.3 .1v.3l-.1 .2-.2-.1zM137.4 94.5h.3l-.1 .5h-.2zM137.7 93.3l.2 .6 .1-.5 .1 .5 .1-.6M137.9 95l.1-.6 .3 .6M137.9 92.3h.2l.1-.1-.3-.1v.6h.2l.1-.3-.2-.1M138 94.9h.2M139.5 81.1l.6 .1-.6 .2M139.6 80.6h.5M139.8 80.4v.4M140.3 81h.5M140.5 80.8v.4"/>
<path d="M151.7 81.2h.1M151.7 80.9h.1l-.1 .1M151.8 80.6l-.1 .1M151.8 80.5l-.1 .1M152.9 80.6h.2M152.9 80.3h.2l-.2 .1M153.1 80.1h-.2M153.9 80.1l.6 .1-.6 .3M153.9 82.3l.6 .1-.6 .3M154 81.8h.5M154.2 81.6v.4M154.7 82.3h.5"/>
<path d="M154.9 82v.4M172.3 95.4h.5M172.3 93h.5M172.6 82.3h.2l-.2 .2h.2M172.6 82.1h.2v.2h-.2M172.6 95.2v.4M172.8 81.8v.2h-.2M172.8 81.7h-.2M173 93.3l.6 .1-.6 .2M173 95.5l.6 .1-.6 .2M173.2 95h.4M173.4 92.6v.4"/>
<path d="M173.4 94.8v.4M173.9 81.7l.1 .1M173.9 81.5h.1v.2h-.1M174 81.2v.2h-.1M174 81.1l-.1 .1M174.5 93.8l.2 .1M174.5 93.5h.2l-.2 .1M174.7 93.3h-.2M174.7 93.1l-.2 .1M174.8 81.2l.7 .2-.7 .3M174.8 83.4l.7 .2-.7 .3M175 83h.5"/>
<path d="M175.2 80.6v.5M175.2 82.8v.5M175.6 94.4h.3M175.6 94.1h.3l-.3 .1M175.7 81h.4M175.7 83.4h.4M175.9 93.9h-.3M175.9 93.7l-.3 .1M175.9 83.2v.4M192.2 82.3l.6 .1M192.4 82.3v.2M192.6 83.5v-.1l-.3-.2-.1 .3h.6"/>
<path d="M192.8 82.8l-.1 .2h-.2l-.1-.2 .2-.1 .1 .3M192.8 83.2l-.2 .2M193.4 82.4l.6 .3-.6 .1M193.4 84.6l.6 .3-.6 .1M193.6 84.2h.4M193.8 81.7v.6M193.8 83.9v.6M195.1 84.5h.3l.1-.1-.4-.2v.7M195.1 82.2h.3l.1-.3-.4-.1v.6M195.2 84.5l.3 .4M195.2 82.2l.3 .2M195.5 81h.5"/>
<path d="M195.5 85.8h.5M195.7 85.6v.5M196 84.8l-.2 .1-.2-.2 .1-.2h.3v.5h-.3M196 82.4l-.4-.1 .1-.2h.3v.4l-.2 .2-.1-.1M15.3 112.7h.2l.1-.1-.3-.2v.6M15.3 115.1h.2l.1-.2h-.3v.5M15.3 116.4h.4M15.3 111.6h.4M15.4 112.7l.2 .3M15.4 115.1l.2 .3M15.5 111.4v.4M16.1 113l-.3-.1 .1-.3h.2v.5l-.2 .1"/>
<path d="M16.1 115.4h-.1l-.2-.1 .1-.3h.2v.5l-.2 .1M17.1 115.2l.6 .2-.6 .2M17.1 113l.6 .2-.6 .2M17.2 112.6h.5M17.5 112.4v.4M17.5 114.6v.4M18.3 113.7v.1h.6M18.5 113.7v.2M18.6 114.9v-.3h-.3v.3h.6M18.8 114.1v.2h-.3v-.2h.2v.2M18.9 114.6l-.3 .2M35 116.4h.5"/>
<path d="M35 114h.5M35.3 103.5h.2l-.2 .2h.2M35.3 103.3h.2v.1h-.2M35.3 113.7v.6M35.5 103v.2h-.2M35.5 102.8l-.2 .1M35.7 116.5l.6 .1-.6 .2M35.7 114.3l.6 .1-.6 .2M35.9 113.8h.4M36.1 113.6v.4M36.1 115.8v.4M36.5 104.1h.2l-.2 .2h.2"/>
<path d="M36.5 103.8h.2v.2h-.2M36.7 103.6v.2h-.2M36.7 103.4l-.2 .1M37.1 116.1l.2 .1M37.1 115.9h.2l-.2 .1M37.3 115.6l-.2 .1M37.3 115.4l-.2 .1M37.5 104.4l.6 .2-.6 .3M37.5 102.2l.6 .2-.6 .3M37.6 101.8h.5M37.9 101.6v.5M37.9 103.8v.5"/>
<path d="M38.3 115.5l.3 .1M38.3 115.3h.3l-.3 .1M38.3 104.4h.5M38.3 102h.5M38.6 115l-.3 .1M38.6 114.9h-.3M38.6 101.8v.4M56 117.6h.5M56 115.2h.5M56.3 114.9v.5M56.7 117.6l.6 .2-.6 .2M56.7 115.4l.6 .2-.6 .3"/>
<path d="M56.9 115h.4M57 114.8v.4M57 117v.4M58.1 117.3l.2 .1M58.1 117.1h.2h-.2M58.3 116.8v.2h-.2M58.3 116.6l-.2 .1M59.3 116.7l.3 .1M59.3 116.5h.3h-.3M59.6 116.2l-.3 .1M59.6 116l-.3 .1M71.6 118.8h.5"/>
<path d="M71.6 116.4h.5M71.8 116.2v.4M72.3 118.8l.6 .2-.6 .3M72.3 116.6l.6 .2-.6 .3M72.4 116.2h.5M72.7 116v.5M72.7 118.2v.5M73 102.6h.2l.2-.3-.4-.1v.6M73 103.8h.3l.1-.3-.4-.1v.6M73 104.9h.3l.1-.1-.4-.2v.6M73.6 102.2h.3v.6h-.3zM73.6 103.4h.3v.6h-.3l-.1-.2z"/>
<path d="M73.7 118.5h.3l-.3 .2h.3M73.7 118.2l.3 .1-.3 .1M73.7 104.6l.3 .3-.1 .3h-.3l-.1-.2zM74 118v.2h-.3M74 117.8l-.3 .1M74.1 102.8l.2-.6 .2 .6M74.1 103.4l.2 .6 .1-.4 .1 .4 .1-.6M74.1 102.7h.4M74.2 104.9h.3l-.1-.3h-.2v.6l.3-.1-.1-.2M74.9 117.9h.2l-.2 .2h.2M74.9 117.6h.2l-.2 .2M75.1 117.4v.2h-.2"/>
<path d="M75.1 117.2l-.2 .1M77.1 106.6l.6 .2-.6 .3M77.1 101.4l.6 .2-.6 .2M77.3 106.2v.3h.2l.1-.3 .2 .1-.1 .2M77.3 105.8v.2l.2-.2h.2v.2M77.3 101h.3l.2 .2h-.5zM77.3 100.6l.4-.1 .1 .3h-.5zM78.5 104.7h-.3v.2l.3 .1v.2h-.3M78.8 104.6l.3 .2-.1 .4h-.2zM79.4 104.6v.6M80.1 104.6l-.6 .8M80.6 103.4l-.3 .1 .3 .5h-.3"/>
<path d="M80.6 104.7h-.3v.2l.3 .1v.2h-.3M80.8 102.1h1.1M80.9 104.6a.3 .3 0 0 1 .3 .3 .3 .3 0 0 1-.3 .3zM81.2 102.3l-.2-.1-.1 .2 .1 .4 .2-.1M81.2 103.5h-.3v.4l.3 .1M81.5 103.4v.6M81.6 104.6l.2 .1-.1 .5h-.2l-.1-.2zM81.6 103.7l.2 .3M81.8 102.2l-.3 .1v.2l.3 .1-.1 .2h-.2M81.8 103.4l-.3 .4M129.9 116.5h1M130.3 115.4l-.4 .1 .4 .3v.2h-.4"/>
<path d="M130.3 114.3h-.4l.4 .3v.2h-.4M130.3 116.7a.28 .28 0 0 0-.3 .1 .28 .28 0 0 0 .1 .4l.2-.1M130.5 114.3h.4v.5l-.2 .1h-.2zM130.9 116.6l-.4 .1 .4 .3v.2h-.4M130.9 115.4h-.3l-.1 .2 .1 .4h.3M131.1 114.3v.6M131.1 115.4v.6M131.2 115.7l.3 .3M131.5 115.4l-.4 .4M131.9 114.2l-.5 .7M132.4 114.3h-.4l.1 .2 .3 .1-.1 .3-.3-.1M132.6 114.3h.4v.4l-.2 .2h-.2z"/>
<path d="M133.2 114.3h.4l-.1 .6-.3-.1zM134.1 113.4l.6 .2-.6 .1M134.1 118.7l.6 .1-.6 .3M134.2 113l.1 .2 .2-.2h.2v.2M134.2 112.5v.2h.2l.2-.2 .1 .1v.1M134.2 118.3l.5-.1v.3h-.5zM134.2 117.8l.5-.1v.3h-.5zM136 102.2h.3M136 101.9h.3l-.3 .1M136.3 101.6l-.3 .1M136.3 101.5l-.3 .1M137.2 115.8h.3v-.4h-.3v.6"/>
<path d="M137.3 101.6h.2M137.3 101.3h.2l-.2 .1M137.3 114.5h.3v-.2h-.3v.6M137.4 117h.2l.1-.4h-.3v.6M137.5 101l-.2 .1M137.5 100.9l-.2 .1M137.9 115.4l.2 .1-.1 .5h-.2zM137.9 114.3h.3v.4l-.2 .2-.1-.2zM138 116.7h.3l-.1 .5-.2-.1zM138.2 101l.6 .2-.6 .3M138.2 103.3l.6 .1-.6 .2M138.3 115.4l.2 .6 .1-.4 .1 .4 .1-.6"/>
<path d="M138.4 102.8h.4M138.5 117.2l.1-.6 .3 .6M138.5 114.5h.2l.1-.2h-.3v.6h.2l.1-.3-.2-.1M138.6 117.1h.2M138.6 100.4v.4M138.6 102.6v.4M139.1 103.2h.5M139.1 100.8h.5M139.3 103v.4M151.7 103.3l.1 .1M151.7 103.1h.1v.2h-.1M151.8 102.8v.2h-.1"/>
<path d="M151.8 102.7h-.1M152.9 102.7l.2 .1M152.9 102.5h.2l-.2 .1M153.1 102.2l-.2 .1M153.1 102.1l-.2 .1M153.9 102.2l.6 .2-.6 .3M153.9 104.4l.6 .2-.6 .3M154 104h.5M154.2 101.6v.5M154.2 103.8v.5M154.7 104.4h.5M154.7 102h.5"/>
<path d="M154.9 104.2v.4M172.6 104.5h.2l-.2 .2h.2M172.6 104.3h.2v.1h-.2M172.8 104v.2h-.2M172.8 103.8l-.2 .1M173 117.6h.4M173 115.2h.4M173.2 117.4v.4M173.6 115.4l.6 .2-.6 .3M173.6 117.6l.6 .2-.6 .2M173.8 117.2h.4M173.9 103.9h.1l-.1 .2h.1"/>
<path d="M173.9 103.7h.1v.1h-.1M174 103.4v.2h-.1M174 103.3h-.1M174 114.8v.4M174 117v.4M174.8 103.4l.7 .2-.7 .2M174.8 105.6l.7 .2-.7 .2M175 105.2h.5M175 116h.3M175 115.7h.3l-.3 .1M175.2 102.7v.6M175.2 104.9v.6"/>
<path d="M175.3 115.4l-.3 .1M175.3 115.3l-.3 .1M175.7 103.2h.4M175.7 105.6h.4M175.9 105.4v.4M176.2 116.5l.3 .1M176.2 116.3h.3l-.3 .1M176.5 116l-.3 .1M176.5 115.9l-.3 .1M192.2 104.5l.6 .1M192.4 104.5v.2M192.6 105.7v-.2l-.3-.1-.1 .3h.6"/>
<path d="M192.8 104.9l-.1 .3h-.2l-.1-.3h.2l.1 .3M192.8 105.4l-.2 .2M193.4 104.6l.6 .3-.6 .1M193.4 106.8l.6 .3-.6 .1M193.6 106.4h.4M193.8 104v.4M193.8 106.2v.4M195.1 106.7h.3l.1-.1-.4-.1v.6M195.1 104.4h.3l.1-.2-.4-.2v.6M195.2 106.7l.3 .4M195.2 104.4l.3 .2M195.5 103.2h.5"/>
<path d="M195.5 108h.5M195.7 107.7v.5M196 107l-.2 .1-.2-.2 .1-.3h.3v.5l-.3 .1M196 104.6l-.4-.1 .1-.2h.3v.4l-.2 .2-.1-.1M15.3 134.9h.2l.1-.2-.3-.1v.7M15.3 137.4l.3-.2-.1-.2h-.2v.6M15.3 138.6h.4M15.3 133.8h.4M15.4 134.9l.2 .4M15.4 137.4l.2 .2M15.5 133.6v.4M16.1 135.2l-.1 .1-.2-.2 .1-.3h.2v.5l-.2 .1"/>
<path d="M16.1 137.2v.5l-.2 .1M16.1 137.3l-.1-.1-.2 .2 .1 .2h.2M17.1 137.5l.6 .1-.6 .2M17.1 135.3l.6 .1-.6 .2M17.2 134.7h.5M17.5 134.6v.4M17.5 136.8v.4M18.3 135.8v.2h.6M18.5 135.8v.3M18.6 137.1v-.3h-.3v.3h.6M18.8 136.3v.2h-.3v-.2h.2v.2M18.9 136.8l-.3 .1"/>
<path d="M35 138.6h.5M35 136.2h.5M35.3 125.7h.2l-.2 .2h.2M35.3 125.4h.2v.2h-.2M35.3 135.9v.5M35.5 125.2v.1h-.2M35.5 125l-.2 .1M35.7 138.6l.6 .2-.6 .2M35.7 136.4l.6 .2-.6 .2M35.9 136h.4M36.1 135.8v.4M36.1 138v.4"/>
<path d="M36.5 126.3h.2l-.2 .1h.2M36.5 126h.2v.2h-.2M36.7 125.8v.1h-.2M36.7 125.6l-.2 .1M37.1 138.3l.2 .1M37.1 138h.2l-.2 .1M37.3 137.8l-.2 .1M37.3 137.6l-.2 .1M37.5 126.6l.6 .2-.6 .2M37.5 124.4l.6 .2-.6 .2M37.6 124h.5M37.9 123.7v.5"/>
<path d="M37.9 125.9v.5M38.3 137.7l.3 .1M38.3 137.5h.3h-.3M38.3 126.6h.5M38.3 124.2h.5M38.6 137.2l-.3 .1M38.6 137l-.3 .1M38.6 124v.4M56 139.8h.5M56 137.4h.5M56.3 137.2v.4M56.7 139.8l.6 .2-.6 .3"/>
<path d="M56.7 137.6l.6 .2-.6 .2M56.9 137.2h.4M57 136.9v.6M57 139.1v.5M58.1 139.5h.2l-.2 .2h.2M58.1 139.2h.2v.2h-.2M58.3 139v.1h-.2M58.3 138.8l-.2 .1M59.3 138.9l.3 .1M59.3 138.6h.3l-.3 .1M59.6 138.4v.2h-.3M59.6 138.2l-.3 .1"/>
<path d="M71.6 138.6h.5M71.8 138.4v.4M72.3 138.8l.6 .2-.6 .2M72.4 138.4h.5M72.7 138.1v.5M73 124.8h.2l.2-.3-.4-.1v.6M73 125.9h.3l.1-.1-.4-.2v.6M73 127.1h.3l.1-.1-.4-.2v.6M73.6 124.4h.3v.6h-.3zM73.7 125.6l.3 .3-.1 .3h-.3l-.1-.2zM73.7 126.8l.3 .2-.1 .4h-.3l-.1-.2zM74 140l-.3 .1"/>
<path d="M74.1 125l.2-.6 .2 .6M74.1 125.6l.2 .6 .1-.4 .1 .4 .1-.6M74.1 124.8h.4M74.2 127.1l.3-.1-.1-.2h-.2v.6l.3-.1-.1-.2M74.9 139.8h.2l-.2 .2M75.1 139.6v.1h-.2M75.1 139.4l-.2 .1M77.1 128.8l.6 .3-.6 .1M77.1 123.7l.6 .1-.6 .2M77.3 128.4v.3h.2l.1-.3 .2 .1-.1 .2M77.3 128v.2h.2v-.2l.3 .1-.1 .1M77.3 123.2l.2-.1 .3 .2v.2h-.5z"/>
<path d="M77.3 122.8l.4-.1 .1 .3h-.5zM78.5 126.9h-.3v.1l.3 .2v.2h-.3M78.8 126.8l.3 .2-.1 .4h-.2zM79.4 126.8v.6M80.1 126.8l-.6 .8M80.6 125.7h-.3v.2l.3 .1v.2h-.3M80.6 126.9h-.3v.1l.3 .2v.2h-.3M80.8 124.2h1.1M80.9 126.8a.3 .3 0 0 1 .3 .3 .3 .3 0 0 1-.3 .3zM81.2 124.5l-.2-.1-.1 .2 .1 .4 .2-.1M81.2 125.7h-.3v.4l.3 .1M81.5 125.6v.6"/>
<path d="M81.6 126.8l.2 .1-.1 .5h-.2l-.1-.2zM81.6 125.9l.2 .3M81.8 124.4l-.3 .1v.2l.3 .1-.1 .2h-.2M81.8 125.6l-.3 .3M129.9 138.6h1M130.3 137.6l-.4 .1 .4 .3v.2h-.4M130.3 136.4l-.4 .1 .4 .3v.1h-.4M130.3 138.9a.28 .28 0 0 0-.3 .1 .28 .28 0 0 0 .1 .4l.2-.1M130.5 136.4l.4 .1v.4l-.2 .1h-.2zM130.9 138.8l-.4 .1 .4 .2v.3h-.4M130.9 137.7l-.3-.1-.1 .2 .1 .4 .3-.1M131.1 136.4v.6"/>
<path d="M131.1 137.6v.6M131.2 137.9l.3 .3M131.5 137.6l-.4 .4M131.9 136.4l-.5 .8M132.4 136.4h-.4l.1 .3 .3 .1-.1 .2-.3-.1M132.6 136.4l.4 .1v.4l-.2 .1h-.2zM133.3 136.4l.3 .1-.1 .5-.3-.1zM134.1 135.6l.6 .2-.6 .1M134.2 135.2l.1 .2 .2-.2h.2v.2M134.2 134.7l.1 .3 .4-.3v.3M134.2 140l.5-.1v.3h-.5zM136.6 124.3l.3 .1"/>
<path d="M136.6 124.1h.3l-.3 .1M136.9 123.8l-.3 .1M136.9 123.7h-.3M137.2 138h.3v-.4h-.3v.6M137.3 136.7h.3v-.3h-.3v.6M137.4 139.1h.2l.1-.3h-.3v.6M137.8 137.7h.3l-.1 .5-.2-.1zM137.9 123.7l.1 .1M137.9 123.5h.1l-.1 .1M137.9 136.5h.3v.4l-.2 .1-.1-.1zM138 138.9h.3l-.1 .5-.2-.1zM138 123.2l-.1 .1"/>
<path d="M138 123.1h-.1M138.3 137.6l.2 .6 .1-.4 .1 .4 .1-.6M138.5 139.4l.1-.6 .3 .6M138.5 136.7h.2l.1-.2-.3-.1v.6h.2l.1-.2-.2-.1M138.6 139.2h.2M138.8 123.2l.7 .2-.7 .3M138.8 125.4l.7 .2-.7 .3M139 125h.5M139.2 122.6v.5M139.2 124.8v.4M139.7 125.4h.5M139.7 123h.5"/>
<path d="M139.9 125.2v.4M152.3 125.5h.1l-.1 .2h.1M152.3 125.3h.1v.1h-.1M152.4 125v.2h-.1M152.4 124.8l-.1 .1M153.5 124.9l.2 .1M153.5 124.7h.2l-.2 .1M153.7 124.4v.2h-.2M153.7 124.2l-.2 .1M154.5 124.4l.6 .2-.6 .2M154.5 126.6l.6 .2-.6 .2M154.6 126.2h.5"/>
<path d="M154.8 123.7v.5M154.8 125.9v.5M155.3 126.6h.4M155.3 124.2h.4M155.5 126.4v.4M171.7 139.8h.6M171.7 137.4h.6M172 139.6v.4M172.4 137.6l.6 .2-.6 .2M172.4 139.8l.6 .2-.6 .3M172.6 139.4h.4M172.8 136.9v.6"/>
<path d="M172.8 139.1v.5M173.3 126.7h.1l-.1 .2h.1M173.3 126.4h.1v.2h-.1M173.4 126.2v.2h-.1M173.4 126l-.1 .1M173.9 138.1l.1 .1M173.9 137.9h.1l-.1 .1M174 137.6l-.1 .1M174 137.5h-.1M174.5 126.1h.2l-.2 .2h.2M174.5 125.9h.2l-.2 .1M174.7 125.6v.2h-.2"/>
<path d="M174.7 125.4l-.2 .1M175 138.7l.3 .1M175 138.5h.3l-.3 .1M175.3 138.2l-.3 .1M175.3 138l-.3 .1M175.5 125.6l.6 .3-.6 .1M175.5 127.8l.6 .3-.6 .1M175.6 127.4h.5M175.8 124.9v.5M175.8 127.1v.5M176.3 125.4h.4M176.3 127.8h.4"/>
<path d="M176.5 127.6v.5M192.8 126.7l.6 .1M193 126.7v.2M193.2 128v-.3l-.3-.1-.1 .4h.6M193.4 127.1l-.1 .3h-.2l-.1-.3 .2-.1 .1 .4M193.4 127.6l-.2 .2M194 126.8l.6 .2-.6 .2M194 129l.6 .2-.6 .2M194.2 128.6h.4M194.4 126.2v.4M194.4 128.4v.4M195.7 128.9h.3v-.2h-.3v.5"/>
<path d="M195.7 126.5l.3-.1-.1-.2h-.2v.6M195.8 128.9l.2 .3M195.8 126.5l.2 .3M196 125.4h.6M196 130.2h.6M196.3 130v.4M196.6 129.2h-.2l-.2-.1 .1-.3h.3v.5l-.3 .1M196.6 126.8l-.4-.1 .1-.3h.3v.5l-.2 .1h-.1M15.3 157.1h.2l.1-.2-.3-.1v.6M15.3 159.6h.2l.1-.3-.3-.1v.6M15.3 156h.4M15.4 157.1l.2 .3"/>
<path d="M15.4 159.6l.2 .2M15.5 155.7v.5M16.1 157.4h-.1l-.2-.1 .1-.3h.2v.5l-.2 .1M16.1 159.4v.5l-.2 .1M16.1 159.5l-.1-.1-.2 .2 .1 .2h.2M17.1 159.6l.6 .2-.6 .2M17.1 157.4l.6 .2-.6 .2M17.2 157h.5M17.5 156.8v.4M17.5 159v.4M18.3 158v.2h.6M18.5 158v.3"/>
<path d="M18.6 159.3v-.3h-.2l-.1 .3h.6M18.8 158.5v.2h-.3v-.2h.2v.2M18.9 159l-.3 .2M35 158.4h.5M35.3 147.9h.2l-.2 .1h.2M35.3 147.6h.2v.2h-.2M35.3 158.1v.5M35.5 147.4v.1h-.2M35.5 147.2l-.2 .1M35.7 158.6l.6 .2-.6 .2M35.9 158.2h.4M36.1 157.9v.5"/>
<path d="M36.5 148.5h.2l-.2 .1h.2M36.5 148.2h.2v.2h-.2M36.7 148l-.2 .1M36.7 147.8v.2h-.2M37.3 160v.1h-.2M37.3 159.8l-.2 .1M37.5 148.8l.6 .2-.6 .2M37.5 146.6l.6 .2-.6 .2M37.6 146.2h.5M37.9 145.9v.5M37.9 148.1v.5M38.3 159.9l.3 .1"/>
<path d="M38.3 159.6h.3l-.3 .1M38.3 148.8h.5M38.3 146.3h.5M38.6 159.4l-.3 .1M38.6 159.2l-.3 .1M38.6 146.2v.4M56 159.6h.5M56.3 159.4v.4M56.7 159.8l.6 .2-.6 .2M56.9 159.4h.4M57 159.1v.5M71.6 141h.5"/>
<path d="M72.3 141l.6 .2-.6 .2M72.7 140.3v.5M73 146.9h.4l-.1-.3h-.3v.6M73 148.1h.3l.1-.1-.4-.2v.6M73 149.3h.3l.1-.2-.4-.1v.6M73.6 146.6h.3v.6h-.3l-.1-.2zM73.6 147.9l.2-.1 .2 .2-.1 .4h-.3zM73.7 140.7h.3l-.3 .1h.3M73.7 140.4l.3 .1-.3 .1M73.7 149a.3 .3 0 0 1 .3 .3 .3 .3 0 0 1-.4 .3l-.1-.4zM74 140.2v.1h-.3M74.1 147.2l.2-.6 .2 .6"/>
<path d="M74.1 147.8l.2 .6 .1-.4 .1 .4 .1-.6M74.1 147h.4M74.2 149.3h.3l-.1-.3h-.2v.6l.3-.1-.1-.2M74.9 140.1h.2l-.2 .2h.2M77.1 151l.6 .3-.6 .1M77.1 145.8l.6 .2-.6 .2M77.3 150.6v.3l.4-.3v.3M77.3 150.2v.2h.2v-.2h.3l-.1 .2M77.3 145.4l.2-.1 .3 .2v.2h-.5zM77.3 145l.4-.1 .1 .3h-.5zM78.5 149.1h-.3v.1l.3 .2-.1 .2h-.2M78.8 149l.3 .1v.4l-.1 .1h-.2z"/>
<path d="M79.4 149v.6M80.1 149l-.6 .7M80.6 147.9h-.3l.1 .2 .2 .1v.2h-.3M80.6 149.1h-.3v.2l.3 .2-.1 .1h-.2M80.8 146.4h1.1M80.9 149a.34 .34 0 0 1 .3 .3 .34 .34 0 0 1-.3 .3zM81.2 146.7l-.2-.1-.1 .2v.3l.3 .1M81.2 147.9h-.3v.4l.3 .1M81.5 147.8v.6M81.6 149l.2 .1v.5h-.1l-.3-.2zM81.6 148l.2 .4M81.8 146.6l-.3 .1 .3 .5h-.3"/>
<path d="M81.8 147.8l-.3 .3M130.3 159.8l-.4 .1 .4 .2v.3h-.4M130.3 158.6l-.4 .1 .4 .3v.2h-.4M130.5 158.6l.4 .1-.1 .5h-.3zM130.9 159.9l-.3-.1-.1 .2 .1 .4 .3-.1M131.1 158.6v.6M131.1 159.8v.6M131.5 159.8l-.4 .3M131.9 158.5l-.5 .9M132.4 158.6h-.4v.3l.4 .1-.1 .2h-.3M132.6 158.6h.3l.1 .2-.1 .4h-.3zM133.2 158.7h.4l-.1 .5-.3-.1z"/>
<path d="M134.1 140.8l.6 .2-.6 .3M134.1 157.8l.6 .1-.6 .2M134.2 140.5l.5-.1v.3h-.5zM134.2 157.4l.1 .2 .2-.2h.2v.2M134.2 156.8l.1 .4 .4-.4v.4M136.6 146.5l.3 .1M136.6 146.3h.3v.1h-.3M136.9 146v.2h-.3M136.9 145.8l-.3 .1M137.3 159l.3-.1v-.3h-.3v.6M137.9 145.9l.1 .1M137.9 145.7h.1l-.1 .1"/>
<path d="M137.9 159.8l.2 .1-.1 .5-.2-.1zM137.9 158.7h.3l-.1 .5-.2-.1zM138 145.4l-.1 .1M138 145.2l-.1 .1M138.3 159.8l.2 .6 .1-.4 .1 .4 .1-.6M138.5 158.9h.2l.1-.2-.3-.1v.6h.2l.1-.2-.2-.1M138.8 145.4l.7 .2-.7 .2M138.8 147.6l.7 .2-.7 .2M139 147.2h.5M139.2 144.7v.5M139.2 146.9v.5M139.7 147.6h.5"/>
<path d="M139.7 145.2h.5M139.9 147.4v.4M151 147.7h.3l-.3 .2h.3M151 147.4h.3v.2h-.3M151.3 147.2v.2h-.3M151.3 147l-.3 .1M152.3 147.1h.1l-.1 .2h.1M152.3 146.9h.1v.1h-.1M152.4 146.6v.2h-.1M152.4 146.4l-.1 .1M153.2 146.6l.7 .2-.7 .2M153.2 148.8l.7 .2-.7 .2"/>
<path d="M153.4 148.4h.5M153.6 145.9v.5M153.6 148.1v.5M154.1 148.8h.5M154.1 146.3h.5M154.3 148.5v.5M172 148.9h.3l-.3 .2h.3M172 148.6h.3v.2h-.3M172.3 148.5h-.3M172.3 148.2v.2h-.3M172.3 159.6h.5M173 159.8l.6 .2-.6 .2"/>
<path d="M173.3 148.3h.1l-.1 .2h.1M173.3 148h.1v.2h-.1M173.4 147.8v.2h-.1M173.4 147.6l-.1 .1M173.4 159.1v.5M174.2 147.8l.6 .2-.6 .2M174.2 150l.6 .2-.6 .2M174.4 149.6h.4M174.6 147.2v.4M174.6 149.4v.4M174.7 159.8l-.2 .1M174.7 159.6l-.2 .1"/>
<path d="M175 147.6h.6M175 150h.6M175.3 149.7v.5M191.6 148.9l.6 .1M191.8 148.9v.2M192 150.2v-.3l-.4-.1v.4h.6M192.2 149.3v.3h-.3v-.4l.2 .4M192.2 149.8l-.2 .2M192.8 149l.6 .2-.6 .2M192.8 151.2l.6 .2-.6 .2M193 150.7h.4M193.2 148.4v.4"/>
<path d="M193.2 150.6v.4M194.5 151.1h.3l.1-.2-.4-.1v.6M194.5 148.7l.4-.1-.2-.2h-.2v.6M194.6 151.1l.3 .3M194.6 148.7l.3 .3M194.9 147.6h.5M194.9 152.4h.5M195.1 152.2v.4M195.4 151.3l-.2 .1-.2-.1 .1-.3h.3v.5l-.3 .1M195.4 149l-.4-.1 .1-.3h.3v.5l-.3 .1M15.3 179.3h.2l.1-.2-.3-.1v.6M15.3 160.7h.4"/>
<path d="M15.3 178.2h.4M15.4 179.3l.2 .3M15.5 177.9v.5M16.1 179.5l-.1 .1-.2-.1 .1-.3h.2v.5l-.2 .1M17.1 179.6l.6 .2-.6 .2M17.2 179.2h.5M17.5 178.9v.5M35 160.7h.5M35.3 170.1h.2l-.2 .1h.2M35.3 169.8h.2v.2h-.2M35.5 169.6l-.2 .1M35.5 169.4v.1h-.2"/>
<path d="M35.7 160.8l.6 .2-.6 .2M36.1 160.1v.5M36.5 170.6h.2l-.2 .2h.2M36.5 170.4h.2v.2h-.2M36.7 170.2l-.2 .1M36.7 170v.1h-.2M37.1 160.5l.2 .1M37.1 160.2h.2l-.2 .1M37.5 171l.6 .2-.6 .2M37.5 168.8l.6 .2-.6 .2M37.6 168.4h.5M37.9 168.1v.5"/>
<path d="M37.9 170.3v.5M38.3 171h.5M38.3 168.6h.5M38.6 168.4v.4M56 162h.5M56.7 162l.6 .2-.6 .2M57 161.3v.5M58.1 161.7h.2l-.2 .1h.2M58.1 161.4h.2v.2h-.2M58.3 161.2v.1h-.2M58.3 161l-.2 .1M59.3 161.1h.3l-.3 .1h.3"/>
<path d="M59.3 160.8h.3l-.3 .2M59.6 160.6v.1h-.3M59.6 160.4l-.3 .1M71 160.7h.5M71 163.2h.5M71.2 160.6v.4M71.7 163.2l.6 .2-.6 .2M71.7 161l.6 .2-.6 .2M71.8 160.6h.5M72.1 160.3v.5M72.1 162.5v.5M72.4 169.1h.3l.1-.1-.4-.2v.6"/>
<path d="M72.4 170.3h.3l.1-.2-.4-.1v.6M72.4 171.5h.3l.1-.2-.4-.1v.6M73 168.9h.3v.5h-.3l-.1-.2zM73 171.2h.3l-.1 .6-.3-.2zM73.1 170l.2 .1v.5h-.3l-.1-.2zM73.1 162.9h.2l-.2 .1h.2M73.1 162.6h.2v.2h-.2M73.3 162.4l-.2 .1M73.3 162.2v.1h-.2M73.4 169.4l.3-.6 .2 .6M73.5 170l.1 .6 .2-.5 .1 .5 .1-.6M73.5 171.5h.4v-.3h-.4v.6l.5-.1-.2-.2"/>
<path d="M73.5 169.2h.4M74.3 162.3h.2l-.2 .1h.2M74.3 162l.2 .1-.2 .1M74.5 161.8v.1h-.2M74.5 161.6l-.2 .1M76.5 173.2l.6 .2-.6 .2M76.5 168l.6 .2-.6 .2M76.7 172.8l.1 .3 .3-.3v.3M76.7 172.3v.3h.1l.2-.3 .2 .1-.1 .2M76.7 167.7l.2-.2 .3 .2v.2h-.5zM76.7 167.2l.4-.1 .1 .2h-.5zM77.9 171.2h-.3l.1 .3 .2 .1v.2l-.3-.1"/>
<path d="M78.2 171.2l.3 .1v.4l-.1 .1h-.2zM78.8 171.2v.6M79.5 171.2l-.5 .7M80.1 170.1h-.4l.1 .2 .3 .1v.2h-.4M80.1 171.2l-.5 .1 .5 .4-.2 .1-.3-.1M80.2 168.6h1.1M80.3 171.2h.2a.33 .33 0 0 1 .1 .4 .33 .33 0 0 1-.3 .2zM80.6 168.9l-.1-.1-.2 .2v.3l.3 .1M80.6 170.1h-.3v.4l.3 .1M80.9 171.2l.3 .1v.4l-.1 .1-.3-.2zM80.9 170v.6M81 170.2l.2 .4"/>
<path d="M81.2 168.9h-.3l.3 .5h-.3M81.2 170l-.3 .3M129.9 160.8h1M130.3 161.1l-.2-.1-.2 .2 .2 .4h.2M130.9 161l-.4 .1 .2 .2h.2v.3h-.4M131.2 160.1l.3 .3M134.1 163l.6 .2-.6 .2M134.2 162.7l.5-.1v.3h-.5zM134.2 162.2l.4-.1 .1 .2h-.5zM134.7 179.4l.6 .1-.6 .2M134.8 178.9l.1 .3 .2-.3h.2v.3M134.8 178.4l.1 .4 .4-.4v.4"/>
<path d="M136.6 168.7h.3l-.3 .2h.3M136.6 168.4h.3v.2h-.3M136.9 168.2v.2h-.3M136.9 168l-.3 .1M137.2 160.1h.3v-.3h-.3v.6M137.4 161.3h.3v-.3h-.3v.6M137.9 168.1l.1 .1M137.9 167.9h.1v.1h-.1M138 161.1h.3l-.1 .5-.2-.1zM138 167.6v.2h-.1M138 167.4l-.1 .1M138.5 161.6l.1-.6 .3 .6"/>
<path d="M138.6 161.4h.2M138.8 167.6l.7 .2-.7 .2M138.8 169.8l.7 .2-.7 .2M139 169.4h.5M139.2 166.9v.5M139.2 169.1v.5M139.7 169.8h.5M139.7 167.3h.5M139.9 169.5v.5M151.7 169.9h.1l-.1 .2h.1M151.7 169.6h.1v.2h-.1M151.8 169.4v.1h-.1"/>
<path d="M151.8 169.2l-.1 .1M152.9 169.3h.2l-.2 .2h.2M152.9 169l.2 .1-.2 .1M153.1 168.8v.2h-.2M153.1 168.6l-.2 .1M153.9 168.8l.6 .2-.6 .2M153.9 171l.6 .2-.6 .2M154 170.6h.5M154.2 168.1v.5M154.2 170.3v.5M154.7 171h.5M154.7 168.6h.5"/>
<path d="M154.9 170.7v.5M172.3 162h.5M172.6 171.1h.2l-.2 .1h.2M172.6 170.8h.2v.2h-.2M172.6 161.8v.4M172.8 170.6l-.2 .1M172.8 170.4v.2h-.2M173 162l.6 .2-.6 .2M173.2 161.6h.4M173.4 161.3v.5M173.9 170.5h.1l-.1 .1h.1M173.9 170.2h.1v.2h-.1"/>
<path d="M174 170.1h-.1M174 169.8v.2h-.1M174.5 160.3l.2 .1M174.5 160.1h.2h-.2M174.8 170l.7 .2-.7 .2M174.8 172.2l.7 .2-.7 .2M175 171.7h.5M175.2 169.4v.4M175.2 171.6v.4M175.6 160.9l.3 .1M175.6 160.7h.3l-.3 .1M175.7 169.8h.4"/>
<path d="M175.7 172.2h.4M175.9 160.4v.2h-.3M175.9 160.2l-.3 .1M175.9 171.9v.5M192.2 171.1l.1 .1h.5M192.4 171.1v.2M192.6 172.3v-.2l-.4-.1v.3h.6M192.8 171.5v.2h-.3l-.1-.1 .2-.1 .1 .2M192.8 172l-.2 .2M193.4 171.2l.6 .2-.6 .2M193.4 173.4l.6 .2-.6 .2M193.6 172.9h.4"/>
<path d="M193.8 170.6v.4M193.8 172.8v.4M195.1 173.4h.2l.2-.3-.4-.1v.6M195.1 170.9h.3l.1-.2-.4-.1v.6M195.2 173.4l.3 .2M195.2 170.9l.3 .3M195.5 169.8h.5M195.5 174.5h.5M195.7 174.4v.4M196 173.2v.5l-.3 .1M196 173.3l-.2-.1-.2 .2 .1 .2h.3M196 171.2h-.2l-.2-.1 .1-.3h.3v.5l-.3 .1"/>
<path d="M15.3 181.7l.3-.1-.1-.2h-.2v.6M15.3 183h.4M15.4 181.7l.2 .3M16.1 181.6v.5l-.2 .1M16.1 181.7l-.1-.1-.2 .1 .1 .3h.2M17.1 181.8l.6 .2-.6 .2M17.5 181.1v.5M18.3 180.2v.2h.6M18.5 180.2v.3M18.6 181.5v-.3l-.2-.1-.1 .4h.6M18.8 180.7v.3h-.2l-.1-.3 .2-.1v.4M18.9 181.1l-.3 .3"/>
<path d="M35 183h.5M35 180.6h.5M35.3 192.2h.2l-.2 .2h.2M35.3 192h.2v.2h-.2M35.3 180.4v.4M35.5 191.8l-.2 .1M35.5 191.6v.1h-.2M35.7 183l.6 .2-.6 .2M35.7 180.8l.6 .2-.6 .2M35.9 180.4h.4M36.1 180.1v.5M36.1 182.3v.5"/>
<path d="M36.5 192.8h.2l-.2 .2h.2M36.5 192.6h.2v.1h-.2M36.7 192.4l-.2 .1M36.7 192.2v.1h-.2M37.1 182.7h.2l-.2 .1h.2M37.1 182.4h.2v.2h-.2M37.3 182.2v.1h-.2M37.3 182l-.2 .1M37.5 193.2l.6 .2-.6 .2M37.5 191l.6 .2-.6 .2M37.6 190.5h.5M37.9 190.4v.4"/>
<path d="M37.9 192.6v.4M38.3 182.1l.3 .1M38.3 181.8h.3l-.3 .1M38.3 190.8h.5M38.3 193.2h.5M38.6 181.6v.1h-.3M38.6 181.4l-.3 .1M38.6 190.5v.5M56 184.2h.5M56 181.7h.5M56.3 181.6v.4M56.7 184.2l.6 .2-.6 .2"/>
<path d="M56.7 182l.6 .2-.6 .2M56.9 181.6h.4M57 181.3v.5M57 183.5v.5M58.1 183.9h.2l-.2 .1h.2M58.1 183.6h.2v.2h-.2M58.3 183.3v.2h-.2M58.3 183.2l-.2 .1M59.3 183.3h.3l-.3 .1h.3M59.3 183l.3 .1-.3 .1M59.6 182.8v.1h-.3M59.6 182.6l-.3 .1"/>
<path d="M71.6 183h.5M71.6 185.4h.5M71.8 182.8v.4M72.3 185.4l.6 .2-.6 .2M72.3 183.2l.6 .2-.6 .2M72.4 182.8h.5M72.7 182.5v.5M72.7 184.7v.5M73 191.3h.3l.1-.2-.4-.1v.6M73 192.5h.3l.1-.2-.4-.1v.6M73 193.7h.3l.1-.2-.4-.1v.6M73.6 191.1l.2-.1 .2 .2-.1 .4h-.3z"/>
<path d="M73.6 193.4a.3 .3 0 0 1 .4 .3 .3 .3 0 0 1-.3 .3l-.2-.2zM73.7 192.2a.3 .3 0 0 1 .3 .3 .3 .3 0 0 1-.4 .2l-.1-.3zM73.7 185h.3l-.3 .2h.3M73.7 184.8l.3 .1-.3 .1M74 184.6l-.3 .1M74 184.4v.1h-.3M74.1 191.6l.2-.6 .2 .6M74.1 192.2l.2 .6 .1-.4 .1 .4 .1-.6M74.1 191.4h.4M74.2 193.7h.3v-.3h-.3v.6l.3-.2-.1-.1M74.9 184.4h.2l-.2 .2h.2M74.9 184.2h.2v.2h-.2"/>
<path d="M75.1 184l-.2 .1M75.1 183.8v.1h-.2M77.1 195.4l.6 .2-.6 .2M77.1 190.2l.6 .2-.6 .2M77.3 194.9v.4l.4-.4v.4M77.3 194.5v.3h.2l.1-.3 .2 .1-.1 .2M77.3 189.9l.4-.1 .1 .2h-.5zM77.3 189.4l.4-.1 .1 .2h-.5zM78.5 193.4h-.3l.1 .3 .2 .1-.1 .2-.2-.1M78.8 193.4l.3 .1v.3l-.1 .2h-.2zM79.4 193.4v.6M80.1 193.3l-.6 .8"/>
<path d="M80.6 192.2h-.3v.2l.3 .2v.2l-.3-.1M80.6 193.4h-.3v.3l.3 .1-.1 .2-.2-.1M80.8 190.8h1.1M80.9 193.4h.2a.33 .33 0 0 1 .1 .4 .33 .33 0 0 1-.3 .2zM81.2 191.1l-.1-.1-.2 .1v.4l.3 .1M81.2 192.2h-.3v.5h.3M81.5 193.4l.3 .1v.4l-.1 .1-.3-.2zM81.5 192.2v.6M81.6 192.5l.2 .3M81.8 191.1h-.3l.1 .2 .2 .1v.2h-.3M81.8 192.2l-.3 .4M92.1 191l.6 .2-.6 .2"/>
<path d="M92.1 190.1h.6l-.6 .4h.6M92.1 190.8h.6M93.3 191.4v.2l.1 .1 .5-.1v-.2l-.3 .1M93.3 190.7h.6l-.6 .4h.6M93.3 190.2l.5-.1 .1 .4h-.6zM94.4 191.6v-.4l.3 .2 .1-.2h.2v.4M94.4 190.6l.6 .2-.6 .3M94.4 190.5v-.4l.3 .2 .1-.2h.2v.4M95.6 198.2v-.4l.3 .3 .2-.3 .2 .2-.1 .2M95.6 191.1h.7M95.6 194.1l.7 .3M95.6 190.7l.5 .4"/>
<path d="M95.7 195.3l-.1 .2 .2 .1h.3l.2-.1-.1-.2M95.7 191.8l-.1 .2 .2 .2h.3l.2-.2-.1-.2M96 196.3l.1 .3h-.5l.2-.3h.3l.2 .2v.1M96 195v-.3h-.3l-.1 .3h.7M96.1 196.9v.2M96.3 198.4v.4l-.4-.4-.3 .2 .1 .2M96.3 196.8l-.7 .3 .7 .1M96.3 193.7h-.7l.3 .1M96.3 192.4h-.7l.5 .2-.5 .2h.7M96.3 191.2v.4h-.7M96.3 190.3h-.7l.3 .2M96.3 190.1v.4"/>
<path d="M96.3 192.9v.5M96.3 193.5v.3M96.3 195.8v.4M96.3 197.3v.4M96.3 194.7l-.3 .2M96.3 194.1l-.7 .3M96.3 190.7l-.3 .3M96.9 191.7l.1 .4h.4v-.4M96.9 191.2v.4M96.9 191.4h.6M96.9 190.6l.6 .5M97.2 192.9v-.2l.3 .2-.1 .2h-.2v-.2l-.2-.2-.1 .1v.3l.3-.1"/>
<path d="M97.3 193.3v.4M97.5 194.9v.4l-.4-.4h-.2v.3M97.5 194.4v.3l-.3-.3h-.3v.3M97.5 193.3l-.6 .2 .6 .2M97.5 190.3h-.6l.2 .2M97.5 190.1v.4M97.5 192.2v.5M97.5 193.8v.4M97.5 190.6l-.6 .5M98.1 193.5v.3h.2v-.3l.3-.1v.4M98.1 191.8v.3l.2 .1 .4-.1-.1-.3M98.1 191.1h.6"/>
<path d="M98.1 194l.6 .4M98.1 190.7l.3 .4M98.3 192.5l.4-.1v.3h-.6v-.3h.2v.3M98.4 194.9v-.2l-.3-.1v.3h.6M98.5 196.2v.3M98.7 197.7v.5l-.4-.5h-.2v.4M98.7 197.3h-.6l.2 .2M98.7 196.1l-.6 .3 .6 .2M98.7 195.9l-.6-.3v.4M98.7 191.2v.4h-.6M98.7 190.3h-.6l.2 .2M98.7 190.1v.4"/>
<path d="M98.7 197.1v.4M98.7 194.6l-.3 .2M98.7 194l-.6 .4M98.7 190.7l-.4 .3M98.8 192.8v.5M98.8 195v.5M98.8 196.6v.5M99.3 197.6l.3-.1 .3 .1v.1l-.5 .1zM99.3 196l.1 .3h.5l-.1-.3h-.3l.1 .3M99.3 193.9v.4h.2v-.4l.4 .1-.1 .3M99.3 195v.4M99.3 191.1h.6"/>
<path d="M99.3 195.2h.6M99.3 194.4l.6 .5M99.3 190.7l.3 .4M99.4 191.8l-.1 .3 .1 .1 .5-.1-.1-.3M99.6 192.7v-.2l-.3-.1v.3h.6M99.7 196.6v.2M99.9 198.1v.4l-.5-.4-.1 .1 .1 .2M99.9 196.5l-.6 .2 .6 .2M99.9 192.9v.3h-.6M99.9 191.2v.4h-.6M99.9 190.3h-.6l.1 .2M99.9 190.1v.4"/>
<path d="M99.9 194.4l-.6 .5M99.9 192.4l-.3 .2M99.9 190.7l-.4 .3M99.9 193.3v.5M99.9 195.4v.5M99.9 197v.4M100.5 192.2v.4h.3v-.4h.2v.4M100.5 191.2v.4l.5-.4v.4M100.5 190.6v.4h.5v-.4M100.7 193.8l.2 .2-.4 .1v-.3h.5v.3M100.9 192.8v.3M101 194.5h-.5l.1 .2"/>
<path d="M101 192.7l-.5 .2 .5 .3M101 190v.4h-.5M101 194.4v.3M101.1 191.6v.6M101.1 193.2v.5M101.6 190.8l.2-.2h.4v.4h-.6zM101.7 191.2v.4l.3-.1 .1-.3 .1 .1v.3M101.9 193.9l.3-.1v.4l-.3-.2v-.2l-.3 .1 .2 .3 .1-.2M101.9 192.3h.3M102.1 192.2v.4l-.5-.1M102.1 190.1v.3M102.1 192.8v.3"/>
<path d="M102.2 194.5h-.6l.2 .2M102.2 192.7l-.6 .3 .6 .2M102.2 190l-.6 .3 .6 .2M102.2 194.4v.3M102.3 191.7v.5M102.3 193.3v.4M102.8 195.3v-.4l.3 .2 .2-.2 .2 .1-.1 .3M102.8 191.4l.2-.2h.3l.2 .4h-.7zM102.8 193.9v.4M102.8 194.1h.7M102.8 193.4l.7 .4M102.9 191.8v.4l.3-.1 .1-.3 .2 .1-.1 .3"/>
<path d="M103.1 192.9h.4M103.3 192.8v.4l-.5-.2M103.3 190.7v.3M103.3 195.5v.3M103.5 197.1h-.7l.3 .2M103.5 196.6l-.7-.2v.4M103.5 195.4l-.7 .2 .7 .2M103.5 190.6l-.7 .2 .7 .3M103.5 190.3h-.7l.3 .2M103.5 190.1v.4M103.5 192.2v.5M103.5 194.4v.4"/>
<path d="M103.5 195.9v.4M103.5 197v.3M103.5 193.4l-.7 .4M104.1 196.6l.1 .3h.4v-.3h-.3l.1 .3M104.1 191.8l.1 .4 .2-.4h.2v.4M104.1 191.2l.1 .4h.3l.2-.2-.1-.2M104.1 193.3l.6 .5M104.3 192.8h.4M104.4 194.3v-.3l-.2-.1-.1 .4h.6M104.4 192.7v.5l-.4-.2M104.5 195.5v.4M104.7 197.3h-.6l.2 .2"/>
<path d="M104.7 195.5l-.6 .2 .6 .3v.5M104.7 195v.4l-.3-.4h-.3v.4M104.7 190.6v.4h-.6M104.7 190.3h-.6l.2 .2M104.7 190.1v.4M104.7 192.2v.5M104.7 194.4v.5M104.7 197.1v.4M104.7 193.9l-.3 .3M104.7 193.3l-.6 .5M105.3 198.3v.3h.2v-.3l.3-.1v.4M105.3 194.9v-.4l.2 .2v-.2h.3v.4"/>
<path d="M105.3 193.5v.3h.2l.1-.3 .3 .1v.2M105.3 191.5v.2h.6M105.3 190.1h.6l-.6 .4h.6M105.3 195l.6 .5M105.3 192.1h.6M105.3 190.8h.6M105.4 192.3h.4l.1 .4h-.6zM105.5 191.6v.1M105.6 196l-.1-.3h-.2v.3h.6M105.6 193.3v-.3l-.3-.1v.4h.6M105.7 197.3v.3M105.9 199h-.6l.2 .2"/>
<path d="M105.9 197.2l-.6 .2 .6 .3M105.9 196.9h-.6l.2 .2M105.9 196.7v.4M105.9 198.8v.4M105.9 195.7l-.3 .2M105.9 195l-.6 .5M106 191v.4M106 193.9v.5M106 196.1v.5M106 197.7v.5M106.5 197.5l.5-.1 .1 .3h-.4h-.2zM106.5 195.7v-.4l.2 .2v-.1l.3-.1v.4"/>
<path d="M106.5 194.3v.3h.2l.2-.3 .2 .1v.2M106.5 193.2l.4-.1 .2 .1v.2h-.6zM106.5 192.2v.4h.6M106.5 191.3l.5-.1 .1 .4h-.5h-.1zM106.5 190.6h.6l-.1 .4h-.5M106.5 190v.4M106.5 196.4v.3M106.5 192.8h.6M106.5 196.6h.6M106.5 195.9l.6 .4M106.5 190.2h.6M106.6 199h.5"/>
<path d="M106.7 192.3v.3M106.8 194l-.2-.3-.1 .1v.2h.6M106.9 198.9v.4l-.4-.2M106.9 197.9v.3M107.1 199.7h-.6l.1 .2M107.1 197.9l-.6 .2 .6 .2M107.1 199.5v.4M107.1 195.9l-.6 .4M107.1 191.7v.5M107.1 194.8v.4M107.1 196.8v.4M107.1 198.3v.5"/>
<path d="M107.7 194.8v-.4l.2 .2 .1-.2h.2v.4M107.7 193.4v.4l.5-.4v.4M107.7 190.7v.4h.5v-.4M107.7 190.2l.5-.1v.4h-.5zM107.7 192.6h.5M107.7 192.2l.3 .4M107.7 192.8v.3l.1 .1h.4v-.4M108 190.8v.3M108.2 195.2h-.5l.1 .2M108.2 191.2v.3h-.5M108.2 195v.4M108.2 192.2l-.3 .3"/>
<path d="M108.3 191.6v.5M108.3 193.8v.6M108.8 190.7h.6l-.6 .4h.6M108.8 190.3l.2-.2h.3l.1 .4h-.6zM108.9 191.4l-.1 .2 .2 .1 .4-.1v-.2l-.2 .1M110.3 192.8h.4M110.4 192.7v.5l-.4-.2M110.5 191.3v.3M110.7 192.4h-.7l.3 .2M110.7 191.2l-.7 .2 .7 .2v.6M110.7 190.9h-.7l.3 .2M110.7 190.4l-.7-.3v.4"/>
<path d="M110.7 190.7v.4M110.7 192.2v.4M111.3 192.3l.4-.1 .2 .2-.2 .2h-.3zM111.3 190.2l.1 .3h.4v-.4l-.3 .1 .1 .3M111.5 192.8h.4M111.6 192.7v.5l-.4-.2M111.7 191.3v.3M111.9 191.2l-.6 .2 .6 .2v.6M111.9 190.9h-.6l.2 .2M111.9 190.7v.4M112.5 197.5v-.4l.2 .2v-.2h.3v.4M112.5 194.6l.1 .3 .2-.3h.3v.3"/>
<path d="M112.5 194l.4-.1 .2 .1v.3l-.5 .1zM112.5 192.4l.5-.1 .1 .3-.5 .1zM112.5 191.7h.6l-.1 .4h-.5M112.5 191.1v.4M112.5 195.2h.6M112.5 191.3h.6M112.7 196.6l.1 .3h-.3l.1-.3h.4l.1 .3M112.9 190.1v.3M113.1 195.5h-.6l.4 .2-.4 .2h.6M113.1 193.6h-.6l.1 .2M113.1 190.8h-.6l.1 .2M113.1 190l-.6 .3 .6 .2"/>
<path d="M113.1 190.6v.4M113.1 193.4v.4M113.2 192.8v.5M113.2 196v.5M113.7 195.2v-.3l.2 .1v-.1h.4l-.1 .3M113.7 192.7v.3l.3-.3h.3v.3M113.7 190.7h.6l-.6 .4h.6M113.7 191.4h.6M113.7 193.2v.3l.1 .1 .5-.1-.1-.3M113.9 194.4h.4l-.1 .2h-.2l-.3-.3v.2h.2M114.3 192.2h-.6l.1 .2M114.3 190.3h-.6l.1 .2"/>
<path d="M114.3 190.1v.4M114.3 192.1v.3M114.3 191.5v.5M114.3 193.7v.5M114.9 192.7v-.4l.2 .2 .1-.2h.2v.4M114.9 190.1v.4l.5-.4v.4M114.9 190.7v.4h.5v-.4M115.4 192l-.5-.3v.5M115.5 191.2v.4M116 192.7v-.4l.3 .2 .1-.2h.2v.4M116 191.8l.2 .3h.4l-.1-.4-.2 .1 .1 .3M116.1 190.7v.4h.4l.1-.4"/>
<path d="M116.1 190.1v.4l.3-.1 .1-.3h.1v.4M116.7 191.2v.4M117.2 193.1v-.4l.3 .2 .1-.2h.2v.4M117.2 192.2v.3h.4l-.1-.2 .2-.1 .2 .1-.1 .2M117.2 191.2v.4M117.2 191.4h.7M117.2 190.6l.7 .5M117.6 190.2l.2-.1 .1 .3-.3 .1-.1-.4-.3 .1 .1 .3 .3-.1M117.9 191.6v.5M117.9 190.6l-.7 .5M118.5 193.3v-.4l.2 .2v-.2h.3v.4M118.5 190.6l.6 .5"/>
<path d="M118.7 192.4h.4M118.7 191.6v-.3h-.2v.3h.6M118.7 190.2h.4l-.1 .3h-.3v-.3l-.2-.1v.4l.2-.1M118.8 192.3v.4l-.4-.2M119.1 191.7v.5M119.1 191.3l-.4 .2M119.1 190.6l-.6 .5M119.7 194.4v-.3l.2 .2v-.2h.3v.3M119.7 193.9v-.4l.2 .3v-.2l.3-.1v.4M119.7 191.8v.3l.1 .1 .5-.1-.1-.3M119.7 191.1h.6M119.7 190.7l.3 .4"/>
<path d="M120.3 192.4h-.6l.4 .2-.4 .2h.6M120.3 191.2v.4h-.6M120.3 190.1v.4l-.4-.4h-.2v.4M120.3 190.7l-.4 .3M120.4 192.9v.5M130.5 182.4h1M130.9 181.4l-.4 .1 .4 .2v.3h-.4M130.9 180.2l-.4 .1 .4 .3v.2h-.4M130.9 182.7l-.2-.1-.2 .2 .2 .4h.2M131.1 180.2h.3l.1 .3-.1 .3h-.3zM131.5 182.6l-.4 .1 .4 .3-.1 .2h-.3M131.5 181.5l-.3-.1-.1 .2 .1 .4 .3-.1"/>
<path d="M131.8 180.2v.6M131.8 181.4v.6M131.9 181.7l.2 .3M132.1 181.4l-.3 .3M132.5 180.1l-.5 .9M133 180.2h-.4v.3l.4 .1-.1 .2h-.3M133.2 180.2h.3l.1 .2-.1 .4h-.3zM133.8 180.3l.4-.1v.6l-.4-.1zM134.7 184.6l.6 .2-.6 .2M134.8 184.3l.5-.1v.2h-.5zM134.8 183.8l.4-.1 .1 .2h-.5zM137.3 190.9h.2l-.2 .2h.2"/>
<path d="M137.3 190.6h.2v.2h-.2M137.5 190.4v.1h-.2M137.5 190.2l-.2 .1M137.8 181.7h.3v-.3h-.3v.6M137.9 180.6h.2l.1-.4h-.3v.6M138 182.9h.3v-.3h-.3v.6M138.5 190.3h.2l-.2 .2h.2M138.5 190l.2 .1-.2 .1M138.5 181.4l.2 .1-.1 .5-.2-.1zM138.5 180.3h.3l-.1 .5-.2-.1zM138.6 182.7h.3l-.1 .5-.2-.1zM138.7 189.8v.1h-.2"/>
<path d="M138.7 189.6l-.2 .1M138.9 181.4l.2 .6v-.4l.2 .4 .1-.6M139.1 183.2l.1-.6 .3 .6M139.1 180.5h.2l.1-.2-.3-.1v.6h.2l.1-.2-.2-.1M139.1 183h.3M139.5 189.8l.6 .1-.6 .3M139.5 192l.6 .2-.6 .2M139.6 191.6h.5M139.8 189.1v.5M139.8 191.3v.5M140.3 192h.5M140.3 189.5h.5"/>
<path d="M140.5 191.7v.5M151.7 192.1h.1l-.1 .1h.1M151.7 191.8h.1v.2h-.1M151.8 191.6l-.1 .1M151.8 191.4v.2h-.1M152.9 191.5h.2l-.2 .1h.2M152.9 191.2l.2 .1-.2 .1M153.1 191v.1h-.2M153.1 190.8l-.2 .1M153.9 191l.6 .2-.6 .2M153.9 193.2l.6 .2-.6 .2M154 192.7h.5"/>
<path d="M154.2 190.4v.4M154.2 192.6v.4M154.7 190.8h.5M154.7 193.2h.5M154.9 192.9v.5M172.3 184.2h.5M172.3 181.7h.5M172.6 193.3h.2l-.2 .1h.2M172.6 193h.2v.2h-.2M172.6 183.9v.5M172.8 192.8l-.2 .1M172.8 192.6v.1h-.2"/>
<path d="M173 182l.6 .2-.6 .2M173 184.2l.6 .2-.6 .2M173.2 183.8h.4M173.4 181.3v.5M173.4 183.5v.5M173.9 192.7h.1l-.1 .1h.1M173.9 192.4h.1v.2h-.1M174 192.2l-.1 .1M174 192v.2h-.1M174.5 182.5l.2 .1M174.5 182.2h.2l-.2 .2M174.7 182v.2h-.2"/>
<path d="M174.7 181.8l-.2 .1M174.8 192.2l.7 .2-.7 .2M174.8 194.4l.7 .2-.7 .2M175 193.9h.5M175.2 191.6v.4M175.2 193.8v.4M175.6 183.1h.3l-.3 .2h.3M175.6 182.8h.3l-.3 .2M175.7 192h.4M175.7 194.4h.4M175.9 182.6v.2h-.3M175.9 182.4l-.3 .1"/>
<path d="M175.9 194.1v.5M192.2 193.3l.1 .1h.5M192.4 193.3v.2M192.6 194.5v-.2l-.4-.1v.3h.6M192.8 193.7v.2h-.3l-.1-.1 .2-.1 .1 .2M192.8 194.2l-.2 .2M193.4 193.4l.6 .2-.6 .2M193.4 195.6l.6 .2-.6 .2M193.6 195.2h.4M193.8 192.7v.5M193.8 194.9v.5M195.1 195.5h.2l.2-.2-.4-.1v.6"/>
<path d="M195.1 193.1h.3l.1-.2-.4-.1v.6M195.2 195.5l.3 .3M195.2 193.1l.3 .3M195.5 192h.5M195.5 196.7h.5M195.7 196.6v.4M196 195.4v.5l-.3 .1M196 195.5l-.2-.1-.2 .1 .1 .3h.3M196 193.3l-.2 .1-.2-.1 .1-.3h.3v.5l-.3 .1M15.3 201.5h.2l.1-.2-.3-.1v.6M15.3 203.9l.3-.1-.1-.2h-.2v.6M15.3 205.2h.4"/>
<path d="M15.3 200.4h.4M15.4 201.5l.2 .3M15.4 203.9l.2 .3M15.5 200.1v.5M16.1 201.7l-.1 .1-.2-.2 .1-.2h.2v.5l-.2 .1M16.1 203.8v.5l-.1 .1-.1-.1M16.1 203.8h-.1l-.2 .1 .1 .3h.2M17.1 204l.6 .2-.6 .1M17.1 201.8l.6 .2-.6 .2M17.2 201.4h.5M17.5 201.1v.4M17.5 203.3v.5"/>
<path d="M18.3 202.5l.6 .1M18.5 202.5v.1M18.6 203.7v-.3l-.2-.1-.1 .4h.6M18.8 202.9v.3h-.2l-.1-.3 .2-.1v.4M18.9 203.3l-.3 .3M35 205.2h.5M35 202.7h.5M35.3 214.4h.2l-.2 .2h.2M35.3 214.2h.2v.1h-.2M35.3 202.6v.4M35.5 214l-.2 .1M35.5 213.7v.2h-.2"/>
<path d="M35.7 205.2l.6 .2-.6 .2M35.7 203l.6 .2-.6 .2M35.9 202.6h.4M36.1 202.3v.5M36.1 204.5v.5M36.5 215h.2l-.2 .2h.2M36.5 214.8h.2v.1h-.2M36.7 214.6l-.2 .1M36.7 214.3v.2h-.2M37.1 204.9h.2l-.2 .1h.2M37.1 204.6h.2v.2h-.2M37.3 204.3v.2h-.2"/>
<path d="M37.3 204.2l-.2 .1M37.5 215.3l.6 .3-.6 .2M37.5 213.1l.6 .3-.6 .2M37.6 212.7h.5M37.9 212.6v.4M37.9 214.8v.4M38.3 204.3h.3l-.3 .1h.3M38.3 204h.3l-.3 .2M38.3 215.3h.5M38.3 213h.5M38.6 203.8v.1h-.3M38.6 203.6l-.3 .1"/>
<path d="M38.6 212.7v.4M56 206.4h.5M56 203.9h.5M56.3 203.8v.4M56.7 206.4l.6 .1-.6 .3M56.7 204.2l.6 .1-.6 .3M56.9 203.8h.4M57 203.5v.5M57 205.7v.5M58.1 206h.2l-.2 .2h.2M58.1 205.8h.2v.2h-.2M58.3 205.6l-.2 .1"/>
<path d="M58.3 205.4v.1h-.2M59.3 205.4h.3l-.3 .2h.3M59.3 205.2l.3 .1-.3 .1M59.6 204.9v.2h-.3M59.6 204.8l-.3 .1M71.6 207.6h.5M71.6 205.2h.5M71.8 204.9v.5M72.3 207.6l.6 .2-.6 .2M72.3 205.4l.6 .2-.6 .2M72.4 204.9h.5M72.7 204.8v.4"/>
<path d="M72.7 207v.4M73 213.5h.3l.1-.2-.4-.2v.6M73 214.7h.3l.1-.2-.4-.1v.6M73 215.9h.3l.1-.2-.4-.1v.6M73.6 214.4a.3 .3 0 0 1 .4 .3 .3 .3 0 0 1-.3 .3l-.2-.2zM73.6 215.6a.3 .3 0 0 1 .4 .3 .3 .3 0 0 1-.3 .3l-.2-.3zM73.7 213.1l.3 .3-.1 .3h-.3l-.1-.1zM73.7 207.2h.3l-.3 .2h.3M73.7 207l.3 .1h-.3M74 206.8l-.3 .1M74 206.5v.2h-.3M74.1 213.7l.2-.6 .2 .6"/>
<path d="M74.1 214.4l.2 .6 .1-.4 .1 .4 .1-.6M74.1 213.6h.4M74.2 215.9h.3v-.3h-.3v.6l.3-.2-.1-.1M74.9 206.6h.2l-.2 .2h.2M74.9 206.4l.2 .1h-.2M75.1 206.2l-.2 .1M75.1 206v.1h-.2M77.1 217.6l.6 .2-.6 .2M77.1 212.4l.6 .2-.6 .2M77.3 217.2v.3l.2-.3h.2v.3M77.3 216.7v.3h.2l.1-.3 .2 .1-.1 .2M77.3 212h.4l.1 .2h-.5z"/>
<path d="M77.3 211.5h.3l.2 .2h-.5zM78.5 215.6h-.3v.2l.3 .1-.1 .3-.2-.1M78.8 215.6l.3 .1v.3l-.1 .2h-.2zM79.4 215.6v.6M80.1 215.5l-.6 .9M80.6 214.4h-.3l.1 .3 .2 .1v.2l-.3-.1M80.6 215.6h-.3v.3l.3 .1-.1 .2-.2-.1M80.8 213h1.1M80.9 215.6h.2a.33 .33 0 0 1 .1 .4 .33 .33 0 0 1-.3 .2zM81.2 213.2l-.1-.1-.2 .2v.4h.3M81.2 214.4l-.3 .1v.4h.3M81.5 215.6l.3 .1v.4l-.1 .1-.3-.3z"/>
<path d="M81.5 214.4v.6M81.6 214.7l.2 .3M81.8 213.2h-.3v.2l.3 .2v.1h-.3M81.8 214.4l-.3 .4M92.1 210.2a.3 .3 0 0 0 .3 .3 .3 .3 0 0 0 .3-.3l-.3-.1v.2M92.1 209.5h.6l-.6 .3h.6M92.1 209l.4-.1 .2 .1v.3h-.6zM93.3 210.3l.6-.1v.2l-.4 .1-.2-.1zM93.3 203.5v.4l.4-.4 .2 .1v.3M93.3 208.5l.6 .4M93.3 205.7l.6 .4M93.3 206.9v.2l.2 .2 .4-.2v-.2"/>
<path d="M93.3 204.1v.2l.2 .2 .4-.2v-.2M93.6 209.4l-.1-.3-.2 .1v.2h.6M93.6 206.6v-.2l-.3-.1v.3h.6M93.9 208.2h-.6l.1 .1M93.9 205.2v.3l-.4-.3h-.2v.3M93.9 203.2h-.6l.1 .1M93.9 203v.3M93.9 208v.3M93.9 209.1l-.3 .2M93.9 208.5l-.6 .4M93.9 206.3l-.3 .2M93.9 205.7l-.6 .4"/>
<path d="M93.9 204.6v.4M93.9 207.4v.4M93.9 209.6v.4M94.4 206.5v.4M94.4 209.2v.3M94.4 209.3h.6M94.4 206.7h.6M94.4 208.7l.6 .4M94.4 206l.6 .4M94.4 204.1h.6M94.5 207.1v.3h.5v-.3M94.5 203.4l-.1 .3 .2 .1 .4-.4v.4"/>
<path d="M94.5 202.8h.5v.4h-.5zM95 210.4h-.6l.2 .1M95 208.2h-.6l.2 .2M95 205.4v.4l-.3-.4-.3 .1 .1 .3M95 204.3h-.6l.5 .2-.5 .3h.6M95 202.4h-.6l.2 .2M95 202.2v.4M95 208.1v.3M95 210.2v.3M95 208.7l-.6 .4M95 206l-.6 .4M95.1 204.9v.5"/>
<path d="M95.1 207.6v.4M95.1 209.6v.4M95.6 208.5l.7 .1-.1 .2h-.6M95.6 207.9v.3M95.6 208.1h.7M95.7 209.1h.5l.1 .2-.4 .2-.3-.2zM96.3 210.2v.3l-.3-.3-.4 .1 .1 .2M96.3 207.4v.4l-.4-.4-.3 .2 .1 .1M96.3 209.6v.4M96.9 210.5v-.3l.2 .2 .1-.2h.2v.3M96.9 208v.2l.3 .2 .2-.1v-.3M96.9 207.3h.6"/>
<path d="M96.9 207l.3 .3M97.2 209v-.3h-.3v.3h.6M97.5 209.2v.2h-.6M97.5 207.5v.2h-.6M97.5 206.4v.3l-.3-.3h-.3v.3M97.5 209.6v.4M97.5 208.7l-.3 .1M97.5 207l-.3 .2M98.1 208.5v.2l.2 .2 .4-.2-.1-.2M98.1 207.7h.6M98.1 207.4l.3 .3M98.3 210.2h.4"/>
<path d="M98.3 209.3l.2-.2 .2 .1v.2h-.6v-.2h.2v.2M98.5 210.1v.4l-.5-.1M98.7 208v.2h-.6M98.7 206.9v.3l-.4-.3h-.2v.3M98.7 207.4l-.4 .2M98.8 209.6v.4M99.3 210.2v.2l.2 .1v-.3h.4l-.1 .3M99.3 208.8h.6l-.6 .4h.6M99.3 209.4h.6M99.9 208.2v.4l-.4-.4h-.2l.1 .4M99.9 209.6v.4M100.5 210.2v.2l.2 .1h.3v-.3h-.3l.1 .3"/>
<path d="M100.5 209.2l.5-.1v.3h-.5zM100.5 208.5h.5v.3h-.5M100.5 207l.3-.2 .2 .2v.1h-.5zM100.5 207.9v.3M100.5 208.1h.5M101 207.6h-.5l.1 .1M101 207.4v.3M101.1 209.6v.4M101.6 206.3h.6v.3h-.6M101.6 205.7v.3M101.6 208.5l.6 .4M101.6 205.9h.6"/>
<path d="M101.7 206.9h.5v.3h-.5zM102 209.4v-.2l-.2-.1-.2 .3h.6M102.1 204.7v.3M102.2 210.4l-.6-.3v.4M102.2 208v.3l-.3-.3-.3 .1 .1 .2M102.2 205.4h-.6l.2 .1M102.2 204.7l-.6 .2 .6 .1M102.2 205.2v.3M102.2 209.1l-.2 .2M102.2 208.5l-.6 .4M102.3 207.4v.4M102.3 209.6v.4"/>
<path d="M102.8 206.8h.7l-.7 .3h.7M102.8 209.2v.3M102.8 209.3h.7M102.8 208.7l.7 .4M102.8 207.4h.7M103.2 210.3h.3l-.2 .2-.2-.3-.3 .1 .2 .2 .2-.1M103.5 208.1v.4l-.4-.4-.3 .1 .1 .2M103.5 206.4h-.7l.3 .1M103.5 206.1v.4M103.5 207.6v.4M103.5 209.6v.4M103.5 208.7l-.7 .4"/>
<path d="M104.1 209.2l.5-.1 .1 .2-.4 .2-.2-.1zM104.1 208.5l.6 .1-.1 .2h-.5M104.1 206.8v.3l.3 .1 .2-.1v-.3M104.1 207.9v.3M104.1 208.1h.6M104.4 210.2v.2l-.2 .1-.1-.3h.4l.2 .2M104.7 207.6h-.6l.2 .1M104.7 207.4v.3M104.7 209.6v.4M105.3 209.7l.5-.1 .1 .2-.5 .1zM105.3 208.5v.3l.2 .1 .4-.1-.1-.3M105.3 208l.1 .3 .2-.3h.3v.3"/>
<path d="M105.3 206.3l.5-.1 .1 .3-.4 .1-.2-.1zM105.3 205.6v.4h.2l.1-.4 .3 .1v.3M105.6 205.4l-.1-.4h-.2v.4h.6M105.9 210.4h-.6l.2 .1M105.9 206.9h-.6l.4 .2-.4 .1h.6M105.9 210.2v.3M105.9 205l-.3 .2M106 206.1l-.3 .4M106 207.4v.4M106 209v.5M106.5 207.9l.5-.1 .1 .4h-.5h-.1zM106.5 207.2v.4h.2l.2-.4 .2 .1v.3"/>
<path d="M106.5 205.4v.3M106.5 207h.6M106.5 205.5h.6M106.5 204.9l.6 .4M106.6 205.9l-.1 .2 .1 .2 .5-.2-.1-.2M107.1 210.4h-.6l.1 .1M107.1 209.8h-.6l.1 .1M107.1 208.5h-.6l.4 .2-.4 .2h.6M107.1 204.5h-.6l.1 .2M107.1 204.3v.4M107.1 209.6v.3M107.1 210.2v.3"/>
<path d="M107.1 204.9l-.6 .4M107.1 206.4v.5M107.1 209v.5M107.7 207.6v.3h.2l.2-.3h.1v.3M107.7 207.1l.5-.1v.3h-.5zM107.7 204.6v.3h.2l.2-.3 .1 .1v.2M107.7 208.2h.5M107.7 205.2h.5v.3h-.5zM108.2 210.4h-.5l.1 .1M108.2 209.6v.3l-.3-.3-.2 .1v.2M108.2 208.5h-.5l.4 .2-.4 .2h.5M108.2 205.9h-.5l.4 .1-.4 .3h.5"/>
<path d="M108.2 204.1v.2h-.5M108.2 210.2v.3M108.3 205.2l-.1 .2M108.3 206.4v.5M108.3 209v.5M108.8 210.5v-.3l.3 .2v-.2h.3v.3M108.8 209.6l.6 .2-.6 .2M108.8 209.4v-.3l.3 .2 .1-.2h.2v.3M110 207.6l.2-.1h.3l.2 .1-.2 .2h-.3zM110 205.4a.35 .35 0 0 0 .3 .3 .35 .35 0 0 0 .4-.2h-.4l.1 .3M110 206.5v.4M110 206.7h.7"/>
<path d="M110 206l.7 .4M110.1 204.4l-.1 .2 .2 .2 .2-.4h.2v.4M110.1 203.8l-.1 .2 .2 .2h.3l.2-.2-.1-.2M110.3 209.7h.4M110.4 209.6v.3l-.4-.1M110.5 208.7v.2M110.7 210.2v.3l-.3-.3-.4 .1 .1 .2M110.7 208.6l-.7 .1 .7 .3v.5M110.7 208.2h-.7l.3 .2M110.7 203.2v.3h-.7M110.7 202.7v.4l-.3-.4-.4 .1 .1 .3M110.7 204.9v.4"/>
<path d="M110.7 206.9v.5M110.7 208.1v.3M110.7 206l-.7 .4M111.3 209.6v.3h.2v-.3l.4 .1-.1 .2M111.3 205.4l.1 .2h.4v-.3l-.3 .1 .1 .2M111.3 204.3v.3l.2-.1 .1-.2h.3l-.1 .3M111.3 203.8l.5-.1 .1 .3h-.6zM111.3 205.8l.6 .4M111.5 206.8v-.3h-.2v.3h.6M111.7 203.2v.2M111.7 208.7v.2M111.9 210.2v.3l-.4-.3h-.2v.3"/>
<path d="M111.9 208.6l-.6 .1 .6 .3v.5M111.9 208.2h-.6l.2 .2M111.9 207.6h-.6l.2 .2M111.9 203.1l-.6 .1 .6 .3M111.9 202.6v.3l-.4-.3h-.2v.3M111.9 204.7v.5M111.9 206.9v.5M111.9 207.5v.3M111.9 208.1v.3M111.9 206.5l-.4 .1M111.9 205.8l-.6 .4M112.5 209.7v.1l.5 .1v-.3h-.3l.1 .3"/>
<path d="M112.5 205.8l.5-.1 .1 .3-.5 .1-.1-.1zM112.5 205.1v.3h.2l.2-.3 .2 .1v.2M112.5 204.9h.6M112.9 208.7v.2M113.1 210.2v.3l-.4-.3h-.2v.3M113.1 208.6l-.6 .1 .6 .3M113.1 208.2h-.6l.1 .2M113.1 207.5v.3l-.4-.3h-.2v.3M113.1 206.4h-.6l.4 .1-.4 .3h.6M113.1 204.4h-.6l.1 .2M113.1 204.3v.3M113.1 208.1v.3"/>
<path d="M113.2 206.9v.5M113.2 209v.5M113.7 207.8v-.3l.2 .1v-.1h.3v.3M113.7 206.5v.3h.2l.1-.3h.3v.3M113.7 205.6h.6M113.7 205.3l.3 .3M113.7 205.9v.2l.1 .1 .5-.1-.1-.2M114.1 208.7v.2M114.3 210.2v.3l-.4-.3h-.2v.3M114.3 209.8l-.6-.2v.3M114.3 208.6l-.6 .1 .6 .3M114.3 208.2h-.6l.1 .2"/>
<path d="M114.3 204.9h-.6l.1 .1M114.3 204.7v.3M114.3 208.1v.3M114.3 205.3l-.4 .2M114.3 206.9v.5M114.3 209v.5M114.9 207.9l.5 .4M115.1 209.7l.3-.1v.3l-.3-.1v-.2l-.2 .1v.2l.2-.1M115.2 208.9v-.3l-.3-.1v.4h.5M115.4 210.2v.3l-.3-.3h-.2v.3M115.4 207.6l-.5-.2v.3M115.4 208.5l-.2 .2"/>
<path d="M115.4 207.9l-.5 .4M115.5 209v.5M116 208.7v.3M116 208.8h.6M116 208.1l.6 .4M116.3 209.6l.2 .2-.4 .1v-.3h.4l.1 .2M116.6 210.2v.3l-.3-.3-.3 .1 .1 .2M116.6 207.7l-.6-.2v.4M116.6 208.1l-.6 .4M116.7 209v.5M117.2 210.5v-.3l.3 .2 .1-.2h.2v.3M117.2 209.8l.2-.2h.3l.2 .2-.2 .1h-.3z"/>
<path d="M117.2 207.1v-.3l.3 .2 .1-.2h.2v.3M117.2 207.3l.7 .4M117.3 208.5l-.1 .2 .2 .2h.3l.2-.2-.1-.2M117.6 208.2l-.1-.3-.3 .2v.1h.7M117.9 209v.5M117.9 207.9l-.3 .3M117.9 207.3l-.7 .4M118.5 210.5v-.3l.2 .2v-.2h.3v.3M118.5 208.5l.1 .4h.3l.2-.2-.1-.2M118.5 207.3v-.3l.2 .1v-.1h.3v.3M118.5 208v.3M118.5 208.2h.6"/>
<path d="M118.5 207.5l.6 .4M119.1 209.8h-.6l.2 .1M119.1 209v.5M119.1 209.6v.3M119.1 207.5l-.6 .4M119.7 210.5v-.3l.2 .2v-.2h.4l-.1 .3M119.7 208.6l.5-.1 .1 .3-.5 .1zM119.7 207.9l.6 .1-.1 .2h-.5M119.7 207.4v.3M119.7 207.6h.6M119.9 206.4l.4-.1v.3h-.6v-.3h.2v.3M120.3 209.6v.3l-.4-.3h-.2v.3"/>
<path d="M120.3 207.1h-.6l.1 .1M120.3 206.9v.3M120.4 209v.5M129.3 205.2h1M129.7 204.2l-.4 .1 .2 .2h.2v.3h-.4M129.7 203l-.4 .1 .4 .2v.3h-.4M129.8 205.4h-.2l-.3 .2 .2 .4h.3M129.9 203l.4 .1-.1 .5h-.3zM130.3 205.4h-.2l-.2 .1 .4 .2v.3h-.4M130.3 204.3l-.3-.1-.1 .1v.4l.4 .1M130.5 203v.6M130.5 204.2v.6"/>
<path d="M130.6 204.4l.3 .4M130.9 204.2l-.4 .3M131.3 203l-.5 .8M131.8 203l-.4 .1v.1l.4 .1v.2l-.4 .1M132 203h.3l.1 .2-.1 .4h-.3zM132.7 203l.3 .1-.1 .5-.3-.1zM133.5 202.1l.6 .2-.6 .3M133.5 207.4l.6 .2-.6 .2M133.6 201.7v.3h.2l.1-.3 .3 .1-.1 .2M133.6 201.3v.2l.5-.2v.2M133.7 207h.4l.1 .2h-.6zM133.7 206.5h.3l.2 .2h-.6z"/>
<path d="M136 213.1h.3l-.3 .1h.3M136 212.8h.3v.2h-.3M136.3 212.6v.1h-.3M136.3 212.4l-.3 .1M136.6 204.5h.3v-.2l-.3-.1v.6M136.7 203.3h.2l.1-.2-.3-.1v.6M136.8 205.7h.2l.1-.3h-.3v.6M137.2 204.3h.3v.5h-.3zM137.3 212.5h.2l-.2 .1h.2M137.3 212.2h.2v.2h-.2M137.4 205.4h.1l.2 .1-.1 .5h-.2zM137.4 203l.2 .1-.1 .5-.2-.1z"/>
<path d="M137.5 212v.1h-.2M137.5 211.8l-.2 .1M137.7 204.2l.2 .6 .1-.5 .1 .5 .1-.6M137.9 206l.1-.6 .3 .6M137.9 203.2h.2l.1-.1-.3-.1v.6h.2l.1-.3-.2-.1M138 205.8h.2M138.2 212l.6 .2-.6 .2M138.2 214.2l.6 .2-.6 .2M138.4 213.7h.4M138.6 211.3v.5M138.6 213.5v.5M139.1 214.2h.5"/>
<path d="M139.1 211.8h.5M139.3 213.9v.5M151.7 214.2h.1l-.1 .2h.1M151.7 214h.1v.2h-.1M151.8 213.8l-.1 .1M151.8 213.6v.1h-.1M152.9 213.7h.2l-.2 .1h.2M152.9 213.4l.2 .1-.2 .1M153.1 213.2l-.2 .1M153.1 213v.1h-.2M153.9 213.1l.6 .3-.6 .2M153.9 215.3l.6 .3-.6 .2"/>
<path d="M154 214.9h.5M154.2 212.6v.4M154.2 214.8v.4M154.7 215.3h.5M154.7 213h.5M154.9 215.1v.5M172.3 206.4h.5M172.3 203.9h.5M172.6 215.4h.2l-.2 .2h.2M172.6 215.2h.2v.1h-.2M172.6 206.1v.4M172.8 215l-.2 .1"/>
<path d="M172.8 214.8v.1h-.2M173 204.2l.6 .1-.6 .3M173 206.4l.6 .1-.6 .3M173.2 206h.4M173.4 203.5v.5M173.4 205.7v.5M173.9 214.8h.1l-.1 .2h.1M173.9 214.6h.1v.2h-.1M174 214.4l-.1 .1M174 214.2v.1h-.1M174.5 204.7h.2l-.2 .2h.2M174.5 204.4l.2 .1-.2 .1"/>
<path d="M174.7 204.2v.1h-.2M174.7 204l-.2 .1M174.8 214.4l.7 .2-.7 .2M174.8 216.6l.7 .2-.7 .2M175 216.1h.5M175.2 213.7v.5M175.2 215.9v.5M175.6 205.3h.3l-.3 .1h.3M175.6 205h.3l-.3 .2M175.7 214.2h.4M175.7 216.5h.4M175.9 204.8v.1h-.3"/>
<path d="M175.9 204.6l-.3 .1M175.9 216.4v.4M192.2 215.4l.1 .2h.5M192.4 215.4v.3M192.6 216.7v-.2l-.4-.1v.3h.6M192.8 215.9v.2h-.3l-.1-.2h.2l.1 .2M192.8 216.4l-.2 .1M193.4 215.6l.6 .2-.6 .1M193.4 217.8l.6 .2-.6 .1M193.6 217.4h.4M193.8 214.9v.4M193.8 217.1v.5"/>
<path d="M195.1 217.7h.2l.2-.2-.4-.1v.6M195.1 215.3h.3l.1-.2-.4-.1v.6M195.2 217.7l.3 .3M195.2 215.3l.3 .3M195.5 214.2h.5M195.5 219h.5M195.7 218.7v.5M196 217.6v.5h-.3M196 217.6h-.2l-.2 .1 .1 .3h.3M196 215.5l-.2 .1-.2-.2 .1-.2h.3v.5l-.3 .1M15.3 223.7h.2l.1-.2-.3-.1v.6M15.3 226.1h.2l.1-.3h-.3v.6"/>
<path d="M15.3 227.4h.4M15.3 222.5h.4M15.4 223.7l.2 .3M15.4 226.1l.2 .3M15.5 222.3v.5M16.1 223.6v.5l-.2 .1M16.1 223.6h-.1l-.2 .1 .1 .3h.2M16.1 226.4l-.3-.1 .1-.3h.2v.4l-.1 .2-.1-.1M17.1 226.2l.6 .2-.6 .2M17.1 224l.6 .2-.6 .2M17.2 223.6h.5M17.5 223.3v.5"/>
<path d="M17.5 225.5v.4M18.3 224.7h.6M18.5 224.7v.1M18.6 225.8v-.2l-.2-.1-.1 .3h.6M18.8 225.1v.2h-.2l-.1-.2 .2-.1v.3M18.9 225.5l-.3 .3M35 227.4h.5M35 224.9h.5M35.3 236.6h.2l-.2 .2h.2M35.3 236.3h.2v.2h-.2M35.3 224.7v.5M35.5 236.2l-.2 .1"/>
<path d="M35.5 235.9v.2h-.2M35.7 227.4l.6 .1-.6 .3M35.7 225.2l.6 .1-.6 .3M35.9 224.7h.4M36.1 224.5v.5M36.1 226.7v.5M36.5 237.3l.2 .1M36.5 237h.2l-.2 .1M36.7 236.8l-.2 .1M36.7 236.6l-.2 .1M37.1 227h.2l-.2 .2h.2M37.1 226.8h.2v.1h-.2"/>
<path d="M37.3 226.5v.2h-.2M37.3 226.4h-.2M37.5 237.5l.6 .3-.6 .2M37.5 235.3l.6 .3-.6 .2M37.6 234.9h.5M37.9 234.7v.5M37.9 236.9v.5M38.3 226.4h.3l-.3 .2h.3M38.3 226.2l.3 .1-.3 .1M38.3 237.5h.5M38.3 235.2h.5M38.6 225.9v.2h-.3"/>
<path d="M38.6 225.8h-.3M38.6 234.9v.4M56 228.6h.5M56 226.2h.5M56.3 225.9v.5M56.7 228.6l.6 .2-.6 .2M56.7 226.4l.6 .2-.6 .2M56.9 225.9h.4M57 225.7v.5M57 227.9v.5M58.1 228.2h.2l-.2 .2h.2M58.1 228h.2v.1h-.2"/>
<path d="M58.3 227.8l-.2 .1M58.3 227.5v.2h-.2M59.3 227.6h.3l-.3 .2h.3M59.3 227.4l.3 .1h-.3M59.6 227.2l-.3 .1M59.6 226.9v.2h-.3M71.6 227.4h.5M71.6 229.7h.5M71.8 227.1v.4M72.3 229.7l.6 .3-.6 .2M72.3 227.5l.6 .3-.6 .2M72.4 227.1h.5"/>
<path d="M72.7 226.9v.5M72.7 229.2v.4M73 235.7h.3l.1-.2-.4-.2v.7M73 236.9h.3l.1-.2-.4-.1v.6M73 238.1h.2l.2-.2-.4-.1v.6M73.6 236.6a.3 .3 0 0 1 .4 .3 .3 .3 0 0 1-.3 .3l-.2-.3zM73.6 237.8h.3v.6h-.3zM73.7 235.3a.3 .3 0 0 1 .3 .4 .3 .3 0 0 1-.4 .2l-.1-.3zM73.7 229.4h.3l-.3 .2h.3M73.7 229.2h.3l-.3 .1M74 229l-.3 .1M74 228.7v.2h-.3"/>
<path d="M74.1 236l.2-.7 .2 .7M74.1 236.6l.2 .6 .1-.4 .1 .4 .1-.6M74.1 235.8h.4M74.2 238h.3v-.2h-.3v.6h.3v-.2l-.1-.2M74.9 228.8h.2l-.2 .2h.2M74.9 228.6h.2l-.2 .1M75.1 228.4l-.2 .1M75.1 228.1v.2h-.2M77.1 239.8l.6 .2-.6 .2M77.1 234.6l.6 .1-.6 .3M77.3 239.4v.2l.2-.2h.2v.2M77.3 238.9v.2h.2l.1-.2 .2 .1-.1 .1"/>
<path d="M77.3 234.2l.4-.1 .1 .3h-.5zM77.3 233.7l.3-.1 .2 .3h-.5zM78.5 237.8h-.3v.2l.3 .1-.1 .3h-.2M78.8 237.8h.2l.1 .2-.1 .4h-.2zM79.4 237.8v.6M80.1 237.7l-.6 .8M80.6 236.6h-.3l.1 .3h.2v.3l-.3-.1M80.6 237.8h-.3v.2l.3 .2v.2h-.3M80.8 235.2h1.1M80.9 237.8a.3 .3 0 0 1 .3 .3 .3 .3 0 0 1-.3 .3zM81.2 235.4l-.1-.1-.2 .2v.3l.2 .2 .1-.1M81.2 236.6l-.3 .1v.4h.3"/>
<path d="M81.5 237.8l.3 .1-.1 .5h-.2l-.1-.2zM81.5 236.6v.6M81.6 236.9l.2 .3M81.8 235.4h-.3v.2l.3 .2-.1 .2-.2-.1M81.8 236.6l-.3 .3M129.9 227.4h1M130.3 226.4h-.2l-.2 .1 .4 .2v.2h-.4M130.3 225.2l-.4 .1 .4 .2v.3h-.4M130.3 227.6l-.1-.1-.3 .3 .2 .3h.2M130.5 225.2l.4 .1-.1 .5h-.3zM130.9 227.6l-.2-.1-.2 .2 .4 .2v.2h-.4M130.9 226.4h-.2l-.2 .1v.4h.4"/>
<path d="M131.1 225.2v.6M131.1 226.4v.5M131.2 226.6l.3 .3M131.5 226.4l-.4 .3M131.9 225.2l-.5 .7M132.4 225.2l-.4 .1v.1l.4 .1v.2l-.4 .1M132.6 225.2h.3l.1 .1-.1 .5h-.3zM133.3 225.2l.3 .1-.1 .5-.3-.1zM134.1 224.3l.6 .2-.6 .2M134.1 229.6l.6 .2-.6 .2M134.2 223.9v.3h.2l.2-.3 .1 .1v.2M134.2 223.5l.1 .2 .2-.2h.2v.2"/>
<path d="M134.2 229.2h.5v.2h-.5zM134.2 228.7h.5v.3h-.5zM136.6 235.2h.3l-.3 .2h.3M136.6 235h.3v.2h-.3M136.9 234.8l-.3 .1M136.9 234.6v.1h-.3M137.2 226.7h.3v-.3h-.3v.5M137.3 225.5l.3-.1v-.2h-.3v.6M137.4 227.9h.3l-.1-.4h-.2v.6M137.9 234.7h.1l-.1 .1h.1M137.9 234.4h.1v.2h-.1M137.9 225.3h.3l-.1 .5-.2-.1z"/>
<path d="M138 226.4l.1 .1v.4h-.2l-.1-.4zM138 234.1v.2h-.1M138 234l-.1 .1M138.1 227.5l.2 .2v.3l-.3 .1v-.4zM138.3 226.4l.2 .5 .1-.4 .1 .4 .1-.5M138.5 228.1l.1-.6 .3 .6M138.5 225.4h.2l.1-.1-.3-.1v.6h.2l.1-.3-.2-.1M138.6 228h.2M138.8 234.1l.7 .3-.7 .2M138.8 236.3l.7 .3-.7 .2M139 235.9h.5M139.2 233.6v.4"/>
<path d="M139.2 235.8v.4M139.7 236.3h.5M139.7 234h.5M139.9 236.1v.5M152.3 236.4h.1l-.1 .2h.1M152.3 236.2h.1v.1h-.1M152.4 236l-.1 .1M152.4 235.8v.1h-.1M153.5 235.8h.2l-.2 .2h.2M153.5 235.6l.2 .1-.2 .1M153.7 235.4l-.2 .1M153.7 235.2v.1h-.2"/>
<path d="M154.5 235.3l.6 .3-.6 .2M154.5 237.5l.6 .3-.6 .2M154.6 237.1h.5M154.8 234.7v.5M154.8 236.9v.5M155.3 237.5h.4M155.3 235.2h.4M155.5 237.3v.5M173 228.6h.4M173 226.2h.4M173.2 228.3v.5M173.3 237.7l.1 .1"/>
<path d="M173.3 237.4h.1l-.1 .1M173.4 237.2l-.1 .1M173.4 237l-.1 .1M173.6 226.4l.6 .2-.6 .2M173.6 228.6l.6 .2-.6 .2M173.8 228.1h.4M174 225.7v.5M174 227.9v.5M174.5 237h.2l-.2 .2h.2M174.5 236.8l.2 .1h-.2M174.7 236.6l-.2 .1M174.7 236.3v.2h-.2"/>
<path d="M175 226.9h.3l-.3 .1h.3M175 226.6l.3 .1-.3 .1M175.3 226.4v.1h-.3M175.3 226.2l-.3 .1M175.5 236.6l.6 .2-.6 .1M175.5 238.8l.6 .2-.6 .1M175.6 238.4h.5M175.8 235.9v.4M175.8 238.1v.4M176.2 227.5h.3l-.3 .1h.3M176.2 227.2h.3v.2h-.3M176.3 236.3h.4"/>
<path d="M176.3 238.7h.4M176.5 226.9v.2h-.3M176.5 226.8l-.3 .1M176.5 238.5v.5M192.8 237.6l.1 .2h.5M193 237.6v.3M193.2 238.9l-.1-.4-.3 .1v.3h.6M193.4 238v.3h-.3l-.1-.2 .2-.1 .1 .3M193.4 238.5l-.2 .2M194 237.8l.6 .2-.6 .2M194 240l.6 .2-.6 .1M194.2 239.6h.4"/>
<path d="M194.4 237.1v.4M194.4 239.3v.4M195.7 239.9h.2l.1-.3h-.3v.6M195.7 237.4h.3v-.1l-.3-.1v.6M195.8 239.9l.2 .3M195.8 237.4l.2 .4M196 236.3h.6M196.6 239.7v.5l-.2 .2-.1-.1M196.6 239.8l-.2-.1-.2 .2 .1 .3h.3M196.6 237.7l-.2 .1-.2-.2 .1-.2h.3v.5l-.3 .1M196 241.2h.6M196.3 240.9v.4"/>
</g>
<g fill="none" stroke="#b90000" stroke-width=".2">
<path d="M14.3 23.4l.1-.2v.6M14.3 26.9h.3l-.3 .5h.3M14.3 22h.3l-.2 .2 .2 .1v.3h-.3M14.3 23.8h.3M14.4 25.9l-.1-.2 .2-.1 .1 .2-.3 .2 .1 .2 .2-.1-.1-.2M16.8 27.8h.4M17.1 27.7v.4l-.5-.2M17.2 22.6l-.6-.3v.4M17.8 27.5v.2h.4l-.1-.2 .2-.1 .1 .3M21.7 24.4l-.2 .1v.4h.3l-.1-.3-.2 .2M33.7 35.8l-.2 .1v.5l.3-.1-.1-.3-.2 .1M34 24.4h.4l-.2 .2 .2 .2-.2 .2-.2-.1"/>
<path d="M34.1 26.9l.2-.1 .1 .2-.4 .4h.4M34.7 38.6v.2h.2l-.1-.1 .3-.2 .2 .2-.1 .1M35.4 29h.5M35.6 28.9v.4l-.4-.2M35.9 23.7l-.6-.2v.4M36.4 39h-.5l.1 .2M36.4 38.8v.4M37 28.8h-.6l.2 .2M37 28.7v.3M37.2 39.2h.4M37.5 39.1v.4l-.5-.2M37.6 28.3v.4h.3v-.4h.2v.4"/>
<path d="M37.6 33.9l-.6-.2v.4M39.4 37h.3l.1 .1-.4 .5h.4M39.4 34.6h.4l-.2 .2h.2v.3h-.4M40.3 25.6l-.2 .2v.4l.3-.1-.1-.2-.2 .1M55 25.6h.4l-.2 .3 .2 .1v.1h-.4M55.1 28.1l.1-.1 .2 .2-.4 .4h.4M56.4 30.2h.5M56.6 30.1v.3h-.4M56.9 24.9l-.6-.2v.4M58 30h-.6l.2 .2M58 29.8v.4M58.6 29.6v.2h.3v-.2l.2-.1v.3"/>
<path d="M61.3 26.8l-.2 .1-.1 .4h.4l-.1-.2h-.3M70.6 26.8h.4l-.3 .3h.3v.2h-.4M70.7 29.3l.2-.1 .1 .2-.4 .4h.4M71.8 37.6h.4l-.3 .6M72 31.4h.4M72.1 36.4l-.3 .1v.5h.4l-.1-.4-.3 .1M72.2 31.3v.3l-.4-.1M72.2 35.2h-.4v.3h.4v.3h-.4M72.4 26.1l-.6-.2v.4M73.6 31.2h-.6l.2 .2M73.6 31v.4M74.2 30.8v.2h.3v-.2l.2-.1v.3"/>
<path d="M76.8 32.9l.4-.1v.3h-.4v-.3l-.2 .1 .1 .2h.1M76.9 28l-.2 .2v.4l.3-.1-.1-.3-.2 .1M82.6 35.3l.2-.1v.6M82.6 36.4h.2l.2 .1-.4 .5h.4M82.6 37.6h.4l-.2 .2 .2 .3-.2 .1-.2-.1M82.6 35.8h.4M128.8 27.6l.2-.2v.6M128.8 26.3h.4l-.4 .5h.4M128.8 25h.4l-.2 .2 .2 .1v.2h-.4M128.8 28h.4M133.8 31.1l.4-.1v.4h-.3l-.1-.4-.2 .1v.3l.2-.1M133.8 22.6h.4"/>
<path d="M134 22.6v.4l-.4-.2M135.1 34.6l-.3 .2v.4l.4-.1-.1-.3-.3 .1M136 33.1v.3l.3 .1-.1-.3 .3-.1v.4M137.8 33h-.6l.2 .1M137.8 32.8v.3M138.6 32.6h.4M138.8 32.5v.4l-.4-.2M139 38.1l-.6-.2v.4M139.6 25h.4l-.3 .6M139.9 27.4h-.2l-.1 .2h.3v.4l-.3-.1M139.9 26.2h-.2l-.1 .3v.2l.3 .1v-.3h-.3M140.8 35.8h.4l-.3 .2h.2l.1 .3-.4 .1"/>
<path d="M140.8 33.5l.3-.1 .1 .2-.4 .4h.4M149.5 35.8l-.3 .1v.5l.4-.1-.1-.3-.3 .1M150.4 34.3v.4h.3v-.4l.3 .1-.1 .3M152.2 34.2h-.6l.2 .1M152.2 34v.3M153 33.7h.4M153.2 33.7v.4l-.4-.2M153.4 39.3l-.6-.2v.4M155.2 37h.4l-.3 .2 .3 .1v.2l-.2 .1-.2-.1M155.2 34.7l.3-.1 .1 .2-.4 .4h.4M170.5 37l-.3 .1v.4l.2 .1 .2-.3h-.4M170.7 28h.5l-.3 .2 .3 .1v.2l-.5 .1"/>
<path d="M170.8 25.7l.3-.1 .1 .2-.5 .4h.5M171.4 35.5v.4h.3l-.1-.3 .3-.1v.4M172.2 24.8h.4M172.3 24.7v.4l-.4-.2M172.6 30.4l-.6-.3v.4M173.2 35.3h-.6l.2 .3M173.2 35.2v.4M173.8 25.2h-.6l.2 .2M173.8 25v.4M173.9 35h.5M174.2 34.9v.4l-.4-.2M174.4 25.4v.2l.2 .1v-.3h.4l-.1 .3"/>
<path d="M176.1 35.9l.3-.1 .2 .1-.5 .5h.5M176.1 38.2h.5l-.3 .2 .3 .3-.2 .1-.3-.1M177.1 26.8l-.3 .2v.4l.4-.1-.1-.2h-.3M189.1 38.2h-.3v.3l.1 .3 .2-.1-.1-.3-.2 .2M191.1 36.4v.3l.4 .1-.1-.4h.3v.4M192.6 36.2h.4M192.7 36.1v.3l-.4-.1M196 39.6l.1-.2v.6M196 35.9h.3l-.3 .5h.3M196.1 37.2l-.1-.1 .2-.1 .1 .2-.3 .2 .1 .2 .2-.1-.1-.3M14.3 45.6l.1-.2v.6M14.3 49.1h.3l-.3 .5h.3"/>
<path d="M14.3 44.2h.3l-.2 .2 .2 .1v.2h-.3M14.3 46h.3M14.4 48v-.2l.2 .1-.3 .2 .1 .3 .2-.1-.1-.3M16.8 50h.4M17.1 49.9v.3l-.5-.1M17.2 44.7l-.6-.2v.4M17.8 49.7v.2l.4 .1-.1-.3 .2-.1 .1 .4M21.7 46.6l-.2 .1v.4h.3l-.1-.3-.2 .1M33.7 58l-.2 .1v.4h.3l-.1-.3-.2 .1M34 46.6h.4l-.2 .2 .2 .1-.1 .3-.3-.1M34.1 49.1l.2-.1 .1 .1-.4 .5h.4M35.4 51.2h.5"/>
<path d="M35.6 51.1v.3h-.4M35.9 45.9l-.6-.2v.4M37 51h-.6l.2 .2M37 50.8v.4M37.6 50.5v.3h.3v-.3h.2v.3M37.6 56.2l-.6-.3v.4M39.4 59.2l.4 .1-.4 .5h.4M39.4 56.8h.4l-.2 .2h.2v.3l-.4 .1M40.3 47.8l-.2 .2v.4l.3-.1-.1-.3-.2 .1M55 47.8h.4l-.2 .2h.1l.1 .3h-.4M55.1 50.2h.1l.2 .1-.4 .5h.4M56.4 52.4h.5"/>
<path d="M56.6 52.3v.3l-.4-.1M56.9 47.1l-.6-.2v.4M58 52.2h-.6l.2 .2M58 52v.4M58.6 51.8v.2h.3v-.2l.2-.1v.3M61.3 49h-.1l-.2 .2v.3l.3 .1v-.4l-.3 .1M70 49h.4l-.3 .2 .3 .1v.2h-.4M70.1 51.4h.1l.2 .1-.4 .5h.4M71.2 59.8h.4l-.3 .6M71.4 53.6h.4M71.5 58.5l-.3 .2v.4h.4l-.1-.3-.3 .1M71.6 57.4h-.4v.3h.4v.3h-.4"/>
<path d="M71.6 53.5v.4l-.4-.2M71.8 48.3l-.6-.3v.5M73 53.4h-.6l.2 .2M73 53.2v.4M73.6 53v.2h.3v-.2l.2-.1v.3M76.2 55.2l.2-.2 .2 .1v.2h-.3l-.1-.3-.2 .2 .1 .1 .1-.1M76.3 50.2l-.2 .1v.5l.3-.1-.1-.3-.2 .1M76.8 41.3h.4M77 41.2v.3l-.4-.1M82 57.5l.2-.1v.6M82 58.6h.3l-.3 .6h.3M82 59.8h.3l-.1 .2 .1 .1v.2h-.3"/>
<path d="M82 58h.3M128.8 49.7l.2-.1v.6M128.8 48.5h.4l-.4 .5h.4M128.8 47.2h.4l-.2 .3h.2v.2h-.4M128.8 50.2h.4M133.8 53.3l.4-.1v.4h-.3l-.1-.4-.2 .1v.3l.2-.1M133.8 44.8h.4M134 44.7v.5l-.4-.2M135.1 56.8l-.3 .1v.5l.4-.1-.1-.3-.3 .1M136 55.3v.3l.3 .1-.1-.3 .3-.1v.4M137.8 55.2h-.6l.2 .1M137.8 55v.3"/>
<path d="M138.6 54.7h.4M138.8 54.7v.4l-.4-.2M139.6 47.2h.4l-.3 .6M139.9 49.6h-.2l-.1 .3 .3-.1v.4h-.3M139.9 48.4h-.2l-.1 .2v.3l.3 .1v-.4l-.3 .1M140.8 58h.4l-.3 .2h.2l.1 .3h-.4M140.8 55.7l.3-.1 .1 .2-.4 .4h.4M150.1 58l-.3 .1v.4h.4l-.1-.3-.3 .1M151 56.5v.4h.3v-.4l.3 .1-.1 .3M152.8 56.3h-.6l.2 .2M152.8 56.2v.3M153.5 56h.5"/>
<path d="M153.8 55.9v.4l-.4-.2M155.7 59.2h.5l-.3 .2 .3 .2-.2 .2-.3-.1M155.8 56.9l.2-.1 .2 .1-.5 .5h.5M171.1 59.2l-.3 .1v.4l.2 .1 .2-.2-.2-.2-.2 .2M171.3 50.2h.4l-.2 .2 .2 .1v.3h-.4M171.4 47.9l.3-.1v.2l-.4 .4h.4M172 57.7v.3h.3v-.3l.3 .1-.1 .2M172.8 46.9h.4M172.9 46.9v.4l-.4-.2M173.2 52.5l-.6-.2v.4M173.8 57.6h-.6l.2 .2M173.8 57.4v.4"/>
<path d="M174.4 40.5l-.6-.2v.4M174.4 47.4h-.6l.1 .1M174.4 47.2v.3M174.5 57.2h.5M174.8 57.1v.3l-.4-.1M175 47.5v.3l.2 .1v-.4h.4l-.1 .4M176.8 58h.2l.2 .1-.5 .4h.5M177.7 49l-.3 .1v.5l.4-.1-.1-.3-.3 .1M191.7 58.6v.3l.4 .1-.1-.4h.3v.4M193 41.8l-.7-.3v.4M193.2 58.4h.4M193.3 58.3v.3l-.4-.1"/>
<path d="M196 40.6h.3l-.2 .3h.2v.3l-.3-.1M196 40h.3M196.6 58h.3l-.3 .5h.3M196.7 59.5l-.1-.2 .3-.1v.2l-.3 .2 .1 .2 .2-.1-.1-.2M14.3 67.8l.1-.2v.6M14.3 71.2h.3l-.3 .6h.3M14.3 66.4h.3l-.2 .2 .2 .1v.2h-.3M14.3 68.2h.3M14.4 70.2l-.1-.1 .2-.1 .1 .1-.3 .2 .1 .3 .2-.1-.1-.3M16.8 72.2h.4M17.1 72.1v.3l-.5-.1M17.2 66.9l-.6-.2v.4"/>
<path d="M17.8 71.8v.3l.4 .1-.1-.4h.3v.4M21.7 68.8h-.2v.5h.3v-.3l-.3 .1M34 68.8h.4l-.2 .2h.1l.1 .3h-.4M34.1 71.2h.1l.2 .1-.4 .5h.4M34.7 60.7v.3l.2 .1-.1-.3 .4-.1v.4M35.4 73.4h.5M35.6 73.3v.3l-.4-.1M35.9 68.1l-.6-.2v.4M36.4 61.2h-.5l.1 .1M36.4 61v.3M37 73.2h-.6l.2 .2M37 73v.4"/>
<path d="M37.2 61.3h.4M37.5 61.3v.4l-.5-.2M37.6 72.8v.2h.3v-.2l.2-.1v.3M37.6 78.4l-.6-.3v.3M39.4 79h.4l-.2 .2h.2v.3h-.4M40.3 70l-.2 .1v.5l.3-.1-.1-.3-.2 .1M55 70h.4l-.2 .2h.1l.1 .3h-.4M55.1 72.4l.1-.1 .2 .2-.4 .4h.4M56.4 74.5h.5M56.6 74.5v.3l-.4-.1M56.9 69.3l-.6-.3v.5M58 74.4h-.6l.2 .1"/>
<path d="M58 74.2v.3M58.6 74v.2h.3v-.2l.2-.1v.3M61.3 71.2h-.2l-.1 .5h.4l-.1-.3-.3 .1M70.6 71.2h.4l-.3 .2 .3 .1v.3h-.4M70.7 73.6h.3v.3l-.4 .3h.4M72 75.7h.4M72.2 79.5h-.4v.4h.4v.2h-.4M72.2 75.6v.5l-.4-.2M72.4 70.6l-.6-.3v.4M73.6 75.6h-.6l.2 .1M73.6 75.4v.3M74.2 75.1v.3l.3 .1v-.4h.3l-.1 .4"/>
<path d="M76.2 63.5h.4M76.4 63.4v.3l-.4-.1M76.8 77.3l.2-.1 .2 .1v.2h-.3l-.1-.3-.2 .1 .1 .2 .1-.1M76.9 72.3l-.2 .2v.4h.3l-.1-.3-.2 .1M82.6 79.7l.2-.2v.6M91.8 77h.4v.3h-.3l-.1-.4-.2 .1 .1 .3 .1-.1M91.8 77.5h.4M92 77.4v.5l-.4-.2M93 77.5h.4M93.2 77.4v.5l-.4-.2M93.4 77.2l-.6-.3v.4M94 77l.1 .3h.4v-.4l-.3 .1 .2 .3"/>
<path d="M94.2 77.5h.4M94.4 77.4v.5l-.5-.2M95.2 76.9v.4h.3v-.4l.3 .1-.1 .3M95.4 77.5h.4M95.6 77.4v.5l-.4-.2M96.6 77.5h.4M96.6 77h.4M96.8 77.4v.5l-.4-.2M96.8 76.9v.4l-.4-.2M97.6 77.3v-.4l.2 .2 .1-.2h.3v.4M97.8 77.5h.4M98 77.4v.5l-.4-.2"/>
<path d="M99 77.5h.4M99.2 77.4v.5l-.4-.2M99.4 76.9v.4l-.4-.4-.2 .1v.3M100.2 77.5h.4M100.4 77.4v.5l-.5-.2M100.6 77.1h-.6l.2 .2M100.6 76.9v.4M101.2 77l.4-.1 .2 .3-.5 .1zM101.4 77.5h.4M101.6 77.4v.5l-.5-.2M102.4 77.9v-.4l.3 .2v-.2h.3l-.1 .4M102.7 76.9v.4h-.2v-.4h.3l.2 .3"/>
<path d="M103.6 77.9v-.4l.2 .2v-.2h.4l-.1 .4M103.8 77h.4v.2l-.3 .1-.2-.4-.1 .3h.2M104.8 77.9v-.4l.2 .2v-.2h.4v.4M105.4 77.2l-.6-.3v.4M106 77.9v-.4l.2 .2v-.2h.4v.4M106 77l.1 .3h.5v-.3l-.3-.1v.4M107.2 77.9v-.4l.2 .2 .1-.2h.2v.4M107.2 76.9v.4h.3v-.4l.3 .1-.1 .3M108.4 77.9v-.4l.2 .2 .1-.2h.3l-.1 .4M108.6 77h.4M108.8 76.9v.4l-.5-.2M109.6 77.9v-.4l.3 .2v-.2h.3l-.1 .4"/>
<path d="M109.6 77.3v-.4l.3 .2v-.2h.2v.4M110.8 77.9v-.4l.2 .2v-.2h.4l-.1 .4M111.4 76.9v.4l-.4-.4-.2 .1 .1 .3M112 77.9v-.4l.2 .2v-.2h.4v.4M112.6 77.1h-.6l.1 .2M112.6 76.9v.4M113.2 77.9v-.4l.2 .2v-.2h.3v.4M113.2 77.1l.1-.2h.4l.1 .2-.1 .2h-.4zM114.7 76.9l.1 .3-.4 .1v-.4h.5l.1 .3M115 77.5v.4l-.3-.4h-.3v.4M115.9 77h.3l-.1 .3h-.2v-.3l-.3-.1v.4l.3-.1M116.2 77.5v.4l-.3-.4h-.3v.4"/>
<path d="M117.4 77.5v.4l-.3-.4h-.3l.1 .4M117.4 77.2l-.6-.3v.4M118 77v.2l.5 .1v-.4h-.3l.1 .4M118.6 77.5v.4l-.4-.4h-.2l.1 .4M119.2 76.9v.4h.3v-.4h.3v.4M119.8 77.5v.4l-.4-.4-.2 .1 .1 .3M129.4 71.3l.2-.1v.6M129.4 70.1h.4l-.4 .5h.4M129.4 68.8h.4l-.2 .2h.2v.3h-.4M129.4 71.8h.4M134.4 74.9l.3-.1v.3h-.3v-.3l-.2 .1v.2h.2M134.4 66.4h.3"/>
<path d="M134.6 66.3v.5l-.4-.2M135.7 79l-.3 .1v.4h.4l-.1-.3-.3 .1M136.6 77.5v.4h.3v-.4l.3 .1-.1 .3M138.4 77.3h-.6l.2 .2M138.4 77.2v.3M139 60.3l-.6-.2v.4M139.1 76.9h.5M139.4 76.8v.5l-.4-.2M140.2 68.8h.4l-.3 .6M140.5 71.2h-.2l-.1 .3 .3-.1 .1 .3-.4 .1M140.5 70h-.2l-.1 .2 .1 .4h.2v-.4l-.3 .1M141.4 77.9l.3-.1 .1 .1-.4 .5h.4"/>
<path d="M151 78.7v.3h.3v-.3l.3 .1-.1 .2M152.8 78.5h-.6l.2 .3M152.8 78.4v.4M153.5 78.2h.5M153.8 78.1v.3l-.4-.1M154 61.5l-.6-.2v.4M155.8 79h.2l.2 .1-.5 .4h.5M171.3 72.3h.4l-.2 .3 .2 .1v.2h-.4M171.4 70.1l.3-.1v.2l-.4 .4h.4M172 80v.2h.3l-.1-.1 .2-.2 .2 .2-.1 .1M172.8 69.1h.4M172.9 69v.5l-.4-.2"/>
<path d="M173.2 74.7l-.6-.2v.4M173.8 79.8h-.6l.2 .2M173.8 79.6v.4M174.4 69.6h-.6l.1 .1M174.4 69.4v.3M174.5 79.4h.5M174.8 79.3v.3l-.4-.1M175 69.7v.3l.2 .1v-.4h.4l-.1 .4M175 62.7l-.6-.3v.5M176.7 60.4h.5l-.3 .2 .3 .2-.2 .2-.3-.1M177.7 71.2l-.3 .1v.5l.4-.1-.1-.3-.3 .1M189.7 60.4h-.3v.3l.1 .3 .2-.1-.1-.3-.2 .1"/>
<path d="M193.6 64l-.6-.3v.4M196.6 61.8l.1-.2v.6M196.6 62.8h.3l-.2 .2h.2v.4l-.3-.1M196.6 62.2h.3M14.3 90l.1-.2v.6M14.3 93.4h.3l-.3 .5h.3M14.3 88.6h.3l-.2 .2 .2 .1v.2h-.3M14.3 90.4h.3M14.4 92.4v-.2h.2l-.3 .3 .1 .3 .2-.1-.1-.3M16.8 94.4h.4M17.1 94.3v.3l-.5-.1M17.2 89.1l-.6-.2v.4"/>
<path d="M17.8 94v.3l.4 .1-.1-.4h.3v.4M21.7 91l-.2 .1v.4h.3v-.3l-.3 .1M33.7 80.1l-.2 .2v.4l.2 .1 .1-.3h-.3M34 91h.4l-.2 .2h.1l.1 .3h-.4M34.1 93.4l.1-.1 .2 .2-.4 .4h.4M34.7 82.9v.3l.2 .1-.1-.3 .4-.1v.4M35.4 95.5h.5M35.6 95.5v.3l-.4-.1M35.9 90.3l-.6-.3v.5M36.4 83.4h-.5l.1 .1M36.4 83.2v.3M37 95.4h-.6l.2 .1"/>
<path d="M37 95.2v.3M37.2 83.5h.4M37.5 83.4v.5l-.5-.2M37.6 95v.2h.3v-.2l.2-.1v.3M39.4 81.4l.4 .1-.4 .5h.4M40.3 92.2l-.2 .1v.5l.3-.1-.1-.3-.2 .1M55 92.2h.4l-.2 .2h.1l.1 .3h-.4M55.1 94.6l.1-.1 .2 .2-.4 .5h.4M56.4 96.7h.5M56.6 96.6v.5l-.4-.2M56.9 91.5l-.6-.3v.5M58 96.6h-.6l.2 .1"/>
<path d="M58 96.4v.3M58.6 96.1v.3h.3v-.3h.2v.3M61.3 93.3l-.3 .3v.3h.3v-.3l-.3 .1M70.6 93.3h.4l-.3 .3 .3 .1v.2h-.4M70.7 95.8h.3v.3l-.4 .3h.4M71.8 82h.4l-.3 .6M72 97.9h.4M72.1 80.8l-.3 .1v.4h.4l-.1-.3-.3 .2M72.2 97.8v.5l-.4-.2M72.4 92.8l-.6-.3v.3M73.6 97.7h-.6l.2 .2M73.6 97.6v.3"/>
<path d="M74.2 97.3v.3l.3 .1v-.4h.3l-.1 .4M76.8 99.5l.2-.1h.2v.3h-.3l-.1-.3-.2 .1 .1 .2 .1-.1M76.8 85.6h.4M76.9 94.5l-.2 .2v.4l.1 .1 .2-.3h-.3M77 85.6v.4l-.4-.2M82.6 80.8l.4 .1-.4 .5h.4M82.6 82h.4l-.2 .2 .2 .2-.2 .2-.2-.1M82.6 80.1h.4M128.1 91.6h.5l-.3 .2h.3v.3h-.5M128.2 94.1l.2-.2v.6M128.2 92.8h.3l.1 .2-.5 .3h.5M128.2 94.5h.4"/>
<path d="M133.2 97.7l.4-.1v.3l-.4-.1v-.2l-.2 .1 .1 .2 .1-.1M133.2 89.3h.4M133.4 89.2v.3l-.4-.1M135.4 99.7v.3h.3v-.3l.3 .1-.1 .2M137.2 99.5h-.6l.2 .2M137.2 99.4v.3M138 99.2h.4M138.2 99.1v.3l-.4-.1M139 91.6h.4l-.3 .6M139.3 93.9h-.2l-.1 .4 .3-.1v.3h-.3M139.3 92.8h-.2l-.1 .2v.3h.3v-.3l-.3 .1M139.6 82.5l-.6-.2v.4"/>
<path d="M141.4 80.1h.4l-.3 .3 .3 .1v.1l-.2 .2-.2-.1M150.1 80.1l-.3 .2v.4h.4l-.1-.3-.3 .1M154 83.7l-.6-.3v.5M155.7 81.4h.5l-.3 .2 .3 .2-.2 .2-.3-.1M171.1 81.4l-.3 .1v.4l.2 .1 .2-.2-.2-.2-.2 .1M171.3 94.5h.4l-.2 .3 .2 .1v.2h-.4M171.4 92.2h.3v.2l-.4 .4h.4M172.8 91.3h.4M172.9 91.2v.5l-.4-.2M173.2 96.9l-.6-.3v.5M174.4 91.7h-.6l.1 .2M174.4 91.6v.3"/>
<path d="M175 91.9v.3h.2v-.3l.4 .1-.1 .2M175 85l-.6-.3v.3M176.7 82.6h.5l-.3 .2 .3 .1-.1 .3-.4-.1M176.8 80.2l.2-.1 .2 .2-.5 .5h.5M177.7 93.3l-.3 .2v.4h.4l-.1-.3-.3 .1M189.7 82.6h-.3v.2v.4h.3l-.1-.4-.2 .1M191.7 80.8v.4h.4l-.1-.4h.3v.4M193.2 80.6h.4M193.3 80.5v.3l-.4-.1M193.6 86.1l-.6-.2v.3M196.6 83.9l.1-.1v.6M196.6 80.2h.3l-.3 .6h.3"/>
<path d="M196.6 85h.3l-.2 .2h.2v.4l-.3-.1M196.6 84.4h.3M196.7 81.7l-.1-.2 .3-.1v.2l-.3 .1 .1 .3 .2-.1-.1-.2M14.3 112.1l.1-.1v.6M14.3 115.6h.3l-.3 .5h.3M14.3 110.8h.3l-.2 .2h.2v.3h-.3M14.3 112.6h.3M14.4 114.6l-.1-.2 .2-.1 .1 .3-.3 .1v.2h.3l-.1-.3M16.8 116.5h.4M17.1 116.5v.3l-.5-.1M17.2 111.3l-.6-.3v.5M17.8 116.2v.3h.4l-.1-.3h.3v.3"/>
<path d="M21.7 113.2l-.2 .1v.4h.3v-.3l-.3 .1M33.7 102.4l-.2 .1v.4l.2 .1 .1-.2-.1-.2-.2 .1M34 113.2h.4l-.2 .2h.1l.1 .3h-.4M34.1 115.6l.1-.1 .2 .2-.4 .4h.4M34.7 105.1v.3l.2 .1-.1-.3 .4-.1v.4M35.4 117.7h.5M35.6 117.6v.4l-.4-.1M35.9 112.5l-.6-.3v.4M36.4 105.5h-.5l.1 .2M36.4 105.4v.3M37 117.6h-.6l.2 .1M37 117.4v.3"/>
<path d="M37.2 105.7h.4M37.5 105.6v.4l-.5-.1M37.6 117.1v.3h.3v-.3h.2v.3M37.6 100.5l-.6-.2v.3M39.4 103.6l.4 .1-.4 .5h.4M39.4 101.1h.4l-.2 .3h.2v.2l-.4 .1M40.3 114.3l-.2 .2v.4h.3l-.1-.3-.2 .1M55 114.3h.4l-.2 .3 .2 .1v.2h-.4M55.1 116.8h.2l.1 .2-.4 .4h.4M56.4 118.9h.5M56.6 118.8v.5l-.4-.2M56.9 113.7l-.6-.2v.3"/>
<path d="M58 118.7h-.6l.2 .2M58 118.6v.3M58.6 118.3v.3l.3 .1v-.4h.3l-.1 .4M61.3 115.5l-.3 .3v.2l.3 .1v-.3l-.3 .1M70.6 115.5h.4l-.3 .3 .3 .1v.2h-.4M70.7 118h.3v.2l-.4 .4h.4M71.8 104.2h.4l-.3 .6M72.1 103l-.3 .1v.4h.4l-.1-.3-.3 .1M72.2 101.7h-.4v.4h.4l-.1 .3-.3-.1M72.4 114.9l-.6-.2v.3M73.6 119.9h-.6l.2 .2M73.6 119.8v.3"/>
<path d="M74.2 119.5v.3h.3v-.3h.3l-.1 .3M76.8 107.8h.4M76.9 116.8l-.2 .1v.4l.1 .1 .2-.2-.2-.2-.1 .1M77 107.7v.5l-.4-.2M82.6 101.9l.2-.2v.7M82.6 103l.4 .1-.4 .5h.4M82.6 104.2h.4l-.2 .2 .2 .1-.1 .3-.3-.1M82.6 102.4h.4M92.2 101.4h-.6l.1 .2M92.2 101.2v.4M93.4 101.2v.4l-.3-.4h-.3v.4M94 101.6v-.4l.2 .2 .1-.2h.3l-.1 .4"/>
<path d="M95.4 101.2h.4M95.6 101.1v.5l-.4-.2M96.4 101.2v.3l.2 .1v-.4h.4l-.1 .4M97.6 101.2v.2l.2 .2h.3l.1-.4h-.4l.1 .4M99.4 101.4l-.6-.3v.5M100.3 101.3h.3l-.2 .3-.1-.3-.3-.1 .1 .4 .2-.2M101.5 101.2l.1 .3-.3 .1-.1-.4h.4l.2 .3M102.4 101l.3-.1 .3 .1v.1l-.5 .1zM103 101.6h-.6l.2 .2M103 101.5v.3M104.2 101.6h-.6l.2 .2M104.2 101h-.6l.2 .2"/>
<path d="M104.2 100.9v.3M104.2 101.5v.3M105.4 101.6h-.6l.1 .2M105.4 100.9v.4l-.5-.4-.1 .1 .1 .2M105.4 101.5v.3M106 101.3v-.4l.2 .2v-.1l.3-.1 .1 .1v.3M106.6 101.6h-.6l.1 .2M106.6 101.5v.3M107.4 101h.4M107.6 100.9v.3l-.5-.1M107.8 101.6h-.6l.2 .2M107.8 101.5v.3"/>
<path d="M108.4 101v.2h.3l-.1-.2 .2-.1 .2 .1-.1 .2M109 101.6h-.6l.2 .2M109 101.5v.3M109.6 101l.2 .2h.4l-.1-.3-.2 .1v.2M110.2 101.6h-.6l.2 .2M110.2 101.5v.3M111.4 101.6h-.6l.2 .2M111.4 101.1l-.6-.2v.4M111.4 101.5v.3M112.2 101l.2-.1 .2 .1v.2h-.3l-.2-.3-.1 .1 .1 .2 .1-.1M112.6 101.6h-.6l.1 .2M112.6 101.5v.3"/>
<path d="M113.4 100.9l.2 .2h-.4a.35 .35 0 0 1 .3-.2 .35 .35 0 0 1 .3 .3M113.8 101.6h-.6l.1 .2M113.8 101.5v.3M114.4 101l.4-.1 .2 .2-.6 .1zM115 101.5v.3l-.3-.3h-.3v.3M116.2 101.5v.3l-.3-.3h-.3v.3M116.2 101h-.6l.2 .2M116.2 100.9v.3M117.4 101.5v.3l-.3-.3-.3 .1 .1 .2M117.4 100.9v.4l-.4-.4-.2 .1 .1 .2M118 101.3v-.4l.2 .2v-.1l.3-.1v.4M118.6 101.5v.3l-.4-.3-.2 .1 .1 .2"/>
<path d="M119.4 101h.4M119.6 100.9v.3l-.4-.1M119.8 101.5v.3l-.4-.3-.2 .1 .1 .2M128.8 116.3l.2-.2v.7M128.8 115h.4l-.4 .5h.4M128.8 113.7h.4l-.2 .3h.2v.3h-.4M128.8 116.8h.4M133.8 119.9l.2-.1h.2v.3h-.3l-.2-.3-.1 .1v.2l.2-.1M133.8 111.5h.4M134 111.4v.3l-.4-.2M134.5 101.1l-.3 .2v.4l.4-.1-.1-.2-.3 .1M138.4 104.7l-.6-.3v.5"/>
<path d="M139.6 113.7h.4l-.3 .6M139.9 116.1h-.2l-.1 .4 .3-.1v.3h-.3M139.9 114.9h-.2l-.1 .3v.2l.3 .1v-.3l-.3 .1M140.2 100l.2-.1 .2 .2-.4 .4h.4M140.2 102.4h.4l-.3 .2 .3 .2-.2 .2-.2-.1M150.1 102.4l-.3 .1v.4h.4l-.1-.3-.3 .1M151 100.9v.3h.3v-.3l.3 .1-.1 .2M152.8 100.8h-.6l.2 .2M152.8 100.6v.4M153.5 100.4h.5M153.8 100.3v.3l-.4-.1M154 105.9l-.6-.3v.4"/>
<path d="M155.7 103.6h.5l-.3 .2 .3 .2-.2 .2-.3-.1M155.8 101.2l.2-.1 .2 .2-.5 .4h.5M171.1 103.6l-.3 .1v.4l.2 .1 .2-.2-.2-.2-.2 .1M172 102.2v.2h.3l-.1-.2 .2-.1 .2 .1-.1 .2M172 114.4h.3l-.3 .5h.3M172 116.8h.3l-.1 .2 .1 .1v.2h-.3M173.4 113.6h.4M173.5 113.5v.3l-.4-.1M173.8 102h-.6l.2 .2M173.8 119.1l-.6-.3v.5M173.8 101.8v.4M174.5 101.6h.5"/>
<path d="M174.8 101.5v.3l-.4-.1M175 107.1l-.6-.2v.3M175 113.9h-.6l.1 .2M175 113.7v.4M175.6 114.1v.3h.2v-.3l.3 .1v.2M176.7 104.8h.5l-.3 .2 .3 .1v.2h-.5M176.8 102.4h.3l.1 .2-.5 .4h.5M178.3 115.5l-.3 .2v.4l.4-.1-.1-.2-.3 .1M189.7 104.8h-.2l-.1 .2v.4h.3v-.4l-.3 .1M191.7 103v.3h.4v-.3h.2v.3M193.2 102.7h.4M193.3 102.7v.3l-.4-.1"/>
<path d="M193.6 108.3l-.6-.2v.3M196.6 106.1l.1-.1v.6M196.6 102.4h.3v.3l-.3 .3h.3M196.6 107.1h.3l-.2 .3h.2v.3h-.3M196.6 106.6h.3M196.7 103.8l-.1-.1 .3-.1v.2l-.3 .1 .1 .3 .2-.1-.1-.3M14.3 134.3l.1-.1v.5M14.3 137.8h.3l-.3 .6h.3M14.3 133h.3l-.2 .1 .2 .1v.3h-.3M14.3 134.7h.3M14.4 136.8l-.1-.2 .2-.1 .1 .3h-.2l-.1 .3h.3l-.1-.3M16.8 138.7h.4"/>
<path d="M17.1 138.6v.4l-.5-.1M17.2 133.5l-.6-.3v.4M17.8 138.4v.3h.4l-.1-.3h.3v.3M21.7 135.3l-.2 .2v.3h.3v-.2l-.3 .1M33.7 124.6l-.2 .1v.4l.2 .1 .1-.2-.1-.2-.2 .1M34 135.3h.4l-.2 .3 .2 .1v.1h-.4M34.1 137.8l.1-.1 .2 .2-.4 .5h.4M34.7 127.3v.3h.2l-.1-.2 .4-.1v.3M35.4 139.9h.5M35.6 139.8v.5l-.4-.2M35.9 134.7l-.6-.3v.4M36.4 127.7h-.5l.1 .2"/>
<path d="M36.4 127.6v.3M37 139.7h-.6l.2 .2M37 139.6v.3M37.2 128h.4M37.5 127.9v.3l-.5-.1M37.6 122.7l-.6-.2v.3M37.6 139.3v.3h.3v-.3l.2-.1v.4M39.4 125.8l.4 .1-.4 .5h.4M39.4 123.3h.4l-.2 .3 .2 .1v.1l-.1 .2-.3-.1M40.3 136.5l-.2 .2v.4l.3-.1-.1-.2-.2 .1M55 136.5h.4l-.2 .3h.1l.1 .2-.4 .1M55.1 139h.2l.1 .1-.4 .5h.4"/>
<path d="M56.9 135.9l-.6-.2v.3M61.3 137.7l-.3 .3v.2l.3 .2 .1-.4h-.4M70.6 137.7h.4l-.3 .3h.3v.3h-.4M71.8 126.4h.4l-.3 .6M72 120.1h.4M72.1 125.2l-.3 .1v.4h.4l-.1-.4-.3 .2M72.2 124h-.4v.2h.4l-.1 .4-.3-.1M72.2 120v.4l-.4-.1M72.4 137.1l-.6-.2v.3M76.8 121.7l.2-.2 .2 .1-.1 .4-.3-.5-.2 .2 .2 .3v-.2M76.8 130h.4M76.9 139l-.2 .1v.4l.1 .1 .2-.2-.2-.3-.1 .2"/>
<path d="M77 129.9v.4l-.4-.1M82.6 124.2l.2-.2v.6M82.6 125.2l.4 .1-.4 .5h.4M82.6 126.4h.4l-.2 .2h.1l.1 .3h-.4M82.6 124.6h.4M128.8 138.6l.2-.2v.6M128.8 137.2h.4l-.4 .5h.4M128.8 135.9h.4l-.2 .3 .2 .1v.2h-.4M128.8 139h.4M133.8 133.6h.4M134 133.6v.3l-.4-.1M135.1 123.3l-.3 .2v.4l.2 .1 .2-.3h-.4"/>
<path d="M136 121.9v.3h.3v-.3l.3 .1-.1 .2M137.8 121.7h-.6l.2 .3M137.8 121.5v.5M138.6 121.4h.4M138.8 121.3v.3l-.4-.1M139 126.9l-.6-.3v.4M139.6 135.9h.4l-.3 .6M139.9 138.4h-.2l-.1 .2h.2l.1 .3h-.3M139.9 137.1h-.2l-.1 .3v.2l.3 .1v-.3l-.3 .1M140.8 124.6h.4l-.3 .2 .3 .2-.2 .2-.2-.1M140.8 122.2l.2-.1 .2 .2-.4 .4h.4M150.7 124.6l-.3 .1v.4h.3v-.3l-.3 .1"/>
<path d="M151.6 123.1v.3h.2v-.2l.1-.1h.3l-.1 .3M153.4 123h-.6l.2 .1M153.4 122.8v.3M154.1 122.6h.5M154.4 122.5v.3l-.4-.2M154.6 128.1l-.6-.2v.3M156.3 125.8h.5l-.3 .1 .3 .2-.1 .3-.4-.1M156.4 123.4l.2-.1 .2 .2-.5 .5h.5M170.7 139h.5l-.3 .1 .3 .3-.2 .2-.3-.1M170.8 136.6l.2-.1 .2 .2-.5 .4h.5M171.7 125.8l-.3 .1v.5l.3-.1v-.4l-.3 .2M172.2 135.8h.4"/>
<path d="M172.3 135.7v.3l-.4-.2M172.6 124.3v.3h.2v-.2l.2-.2 .2 .2-.1 .2M173.8 136.1h-.6l.2 .3M173.8 135.9v.5M174.4 124.2h-.6l.1 .1M174.4 136.3v.3h.2v-.3l.4 .1-.1 .2M174.4 124v.3M175.1 123.7h.5M175.4 123.7v.3l-.4-.1M175.6 129.3l-.6-.2v.3M177.1 137.7l-.3 .2v.4l.2 .1 .2-.4h-.4M177.3 127h.5l-.3 .2h.2l.1 .3h-.5"/>
<path d="M177.4 124.6h.3l.1 .2-.5 .4h.5M190.3 127h-.2l-.2 .2v.3l.4 .1v-.4l-.4 .1M192.3 125.2v.3h.4v-.3l.3 .1-.1 .2M193.8 124.9h.4M193.9 124.8v.4l-.4-.1M194.2 130.5l-.6-.2v.4M197.1 128.3l.2-.2v.6M197.1 124.6h.4v.2l-.4 .4h.4M197.1 129.3h.4l-.2 .3h.2v.3h-.4M197.1 128.7h.4M197.3 126l-.2-.1 .4-.1v.1l-.4 .2 .1 .3h.3l-.1-.4M14.3 156.5l.1-.2v.6"/>
<path d="M14.3 160h.3v.2l-.3 .4h.3M14.3 155.2h.3l-.2 .2h.2v.3h-.3M14.3 156.9h.3M14.4 159l-.1-.2 .2-.1 .1 .3h-.2l-.1 .3h.3l-.1-.3M17.2 155.7l-.6-.3v.4M21.7 157.5l-.2 .2v.4h.3l-.1-.3-.2 .1M33.7 146.8l-.2 .1v.4l.2 .1 .1-.2-.1-.3-.2 .2M34 157.5h.4l-.2 .3 .2 .1v.1l-.4 .1M34.1 160h.2l.1 .1-.4 .5h.4M34.7 149.5v.3h.2v-.3l.4 .1-.1 .2M35.9 156.9l-.6-.2v.3M36.4 149.9h-.5l.1 .2"/>
<path d="M36.4 149.7v.4M37.2 150.2h.4M37.5 150.1v.3l-.5-.2M37.6 144.9l-.6-.2v.4M39.4 148h.4l-.4 .5h.4M39.4 145.6h.4l-.2 .2 .2 .2-.1 .2-.3-.1M40.3 158.7l-.2 .2v.4l.3-.1-.1-.2h-.2M55 158.7h.4l-.2 .3h.1l.1 .2-.4 .1M56.4 141.1h.5M56.6 141v.4l-.4-.1M56.9 158.1l-.6-.2v.3M58 140.9h-.6l.2 .2"/>
<path d="M58 140.8v.3M58.6 140.5v.3h.3v-.3h.3l-.1 .3M61.3 160h-.2l-.1 .4 .2 .2 .2-.2-.1-.3-.3 .2M70 160h.4l-.3 .1 .3 .3-.2 .2-.2-.1M70.7 140.2h.3v.2l-.4 .4h.4M71.8 148.5h.4l-.3 .6M71.8 159.3l-.6-.3v.5M72 142.4h.4M72.1 147.4h-.3v.5h.4l-.1-.4-.3 .2M72.2 142.3v.3l-.4-.1M72.2 146.2h-.4v.2h.4l-.1 .4-.3-.1M73.6 142.1h-.6l.2 .2"/>
<path d="M73.6 141.9v.4M74.2 141.7v.2l.3 .1v-.3h.3l-.1 .3M76.8 143.9l.4-.1-.1 .3-.3-.1v-.2l-.2 .1 .2 .2v-.1M76.8 152.2h.4M77 152.1v.4l-.4-.1M82.6 146.3l.2-.1v.6M82.6 147.4h.4l-.4 .6h.4M82.6 148.5h.4l-.2 .3h.1l.1 .3h-.4M82.6 146.8h.4M94.6 145.9v-.3l.3 .2v-.2h.3l-.1 .3M94.6 149.2h.6v.3h-.6zM94.8 149.8h.4"/>
<path d="M94.9 145l.1 .3h-.3v-.3h.3l.2 .2M95 149.7v.4l-.4-.1M95.8 145.9v-.3l.3 .2v-.2h.3l-.1 .3M95.8 150.2v-.5l.3 .3v-.3h.2v.5M96.1 149.3v-.2l.3 .1v.3l-.3 .1v-.4l-.2-.1-.1 .4 .2 .1 .1-.2M96.4 145.2l-.6-.2v.3M97 145.9v-.3l.2 .2v-.2h.4v.3M97 145v.3h.3v-.3h.3v.3M97 150.2v-.5l.2 .3 .1-.3h.2l.1 .5M97 149.2l.1 .3 .4 .1v-.5l-.3 .1 .1 .4M98.2 145.9v-.3l.2 .2v-.2h.4v.3M98.2 145.3v-.3l.2 .2 .1-.2h.3v.3"/>
<path d="M98.2 150.2v-.5l.2 .3 .1-.3h.2l.1 .5M98.4 149.2h.4M98.6 149.1v.5l-.4-.2M99.4 145.9v-.3l.2 .2 .1-.2h.2v.3M99.4 150.2v-.5l.2 .3 .3-.3 .1 .2-.1 .3M100 145.2h-.6l.2 .1M100 149.1v.5l-.4-.5-.2 .1v.4M100 145v.3M100.6 150.2v-.5l.2 .3 .2-.3 .2 .2-.1 .3M100.6 149.2l.4-.1 .2 .2a.3 .3 0 0 1-.3 .3 .3 .3 0 0 1-.3-.4zM100.9 145l.1 .2-.4 .1v-.3h.4l.2 .2M101.2 145.6v.3l-.3-.3h-.3v.3"/>
<path d="M102.1 149.3l.1-.2 .2 .1v.3l-.2 .1-.1-.4-.2-.1-.1 .4 .2 .1 .1-.2M102.4 145.6v.3l-.3-.3h-.3l.1 .3M102.4 145.2l-.6-.2v.3M102.4 149.7v.5l-.4-.5-.2 .1 .1 .3M103 145v.3h.3v-.3l.3 .1-.1 .2M103 149.2l.1 .3 .4 .1v-.5l-.2 .1v.4M103.6 145.6v.3l-.3-.3h-.3l.1 .3M103.6 149.7v.5l-.4-.5-.2 .1 .1 .3M104.2 145.3v-.3l.2 .2 .1-.2h.3v.3M104.4 149.2h.4M104.6 149.1v.5l-.4-.2M104.8 145.6v.3l-.4-.3-.2 .1 .1 .2"/>
<path d="M104.8 149.7v.5l-.4-.5-.2 .2 .1 .2M106 145.6v.3l-.4-.3-.2 .1 .1 .2M106 145.2h-.6l.1 .1M106 149.7v.5l-.5-.5-.1 .2 .1 .2M106 149.1v.5l-.5-.5-.1 .2 .1 .3M106 145v.3M106.6 149.2l.4-.1 .2 .2a.3 .3 0 0 1-.3 .3 .3 .3 0 0 1-.3-.4zM106.9 145l.1 .2-.4 .1v-.3h.5l.1 .2M107.2 145.8h-.6l.2 .1M107.2 149.7v.5l-.4-.5-.2 .1v.3M107.2 145.6v.3M108.1 149.3l.1-.2 .2 .2-.2 .3-.3-.5-.1 .4 .1 .1 .2-.2"/>
<path d="M108.4 145.8h-.6l.2 .1M108.4 145.2l-.6-.2v.3M108.4 149.9h-.6l.2 .2M108.4 145.6v.3M108.4 149.7v.4M109 145v.3h.3v-.3l.3 .1-.1 .2M109 149.2l.1 .3 .4 .1v-.5l-.2 .1v.4M109.6 145.8h-.6l.2 .1M109.6 149.9h-.6l.2 .2M109.6 145.6v.3M109.6 149.7v.4M110.2 145.3v-.3l.2 .2v-.2h.3v.3"/>
<path d="M110.4 149.2h.4M110.6 149.1v.5l-.4-.2M110.8 145.8h-.6l.2 .1M110.8 149.9h-.6l.2 .2M110.8 145.6v.3M110.8 149.7v.4M112 145.8h-.6l.1 .1M112 145.2h-.6l.1 .1M112 149.9h-.6l.1 .2M112 149.1v.5l-.5-.5-.1 .2 .1 .3M112 145v.3M112 145.6v.3"/>
<path d="M112 149.7v.4M112.6 149.3l.4-.2 .2 .1v.3l-.4 .1zM112.8 145.2l.2 .3-.4 .1v-.2l.1-.2 .5 .1v.3M113.2 149.9h-.6l.1 .2M113.2 149.7v.4M114.1 149.6h.3l-.1 .2h-.2v-.2l-.3-.1v.3l.3-.1M114.4 145.5l-.6-.3v.5M115 145.3v.3h.3l-.1-.2 .2-.2 .2 .2-.1 .2M115 149.6l.1 .2h.4v-.3l-.3 .1 .2 .2M116.2 145.7v-.5l.3 .3v-.2l.2-.1v.5M116.4 149.6h.4M116.6 149.5v.3l-.4-.2"/>
<path d="M118 145.4h-.6l.2 .2M118 149.5v.3l-.4-.3-.2 .1 .1 .2M118 145.2v.4M128.8 159.4h.4l-.4 .6h.4M128.8 158.1h.4l-.2 .3 .2 .1v.2h-.4M133.8 142.1l.2-.2 .2 .1v.3h-.3l-.2-.4-.1 .2v.2l.2-.1M133.8 155.8h.4M134 155.7v.4l-.4-.1M135.1 145.6l-.3 .1v.4l.2 .1 .2-.2-.2-.2-.2 .1M136 144.1v.3h.3v-.3h.3l-.1 .3M137.8 144h-.6l.2 .1M137.8 143.8v.3"/>
<path d="M138.6 143.6h.4M138.8 143.5v.3l-.4-.2M139 149.1l-.6-.3v.4M139.6 158.1h.4l-.3 .6M139.9 159.3h-.2l-.1 .3v.2l.2 .2 .1-.4h-.3M140.8 146.8h.4l-.3 .1 .3 .3-.2 .2-.2-.1M140.8 144.4l.2-.1 .2 .2-.4 .4h.4M149.5 146.8l-.3 .1v.4l.2 .1 .2-.2-.2-.3-.2 .2M150.4 145.3v.3h.3l-.1-.2 .2-.2 .2 .2-.1 .2M152.2 145.2h-.6l.2 .1M152.2 145v.3M153 144.7h.4"/>
<path d="M153.2 144.7v.3l-.4-.1M153.4 150.3l-.6-.2v.3M155.2 148h.4l-.3 .2h.2l.1 .3h-.4M155.2 145.6h.3l.1 .2-.4 .4h.4M170.5 148l-.3 .1v.4h.4l-.1-.3-.3 .1M171.4 158.8l.3-.1v.3l-.4 .3h.4M171.4 146.5v.3h.3l-.1-.2 .2-.2 .2 .2-.1 .2M172.6 141.3l-.6-.3v.4M172.8 157.9h.4M172.9 157.9v.3l-.4-.2M173.2 146.3h-.6l.2 .2M173.2 146.2v.3"/>
<path d="M173.9 145.9h.5M174.2 145.8v.4l-.4-.1M174.4 158.4h-.6l.1 .1M174.4 151.5l-.6-.2v.3M174.4 158.2v.3M175 158.5v.3h.2v-.3h.4l-.1 .3M176.1 146.8l.5 .1-.5 .5h.5M176.1 149.1h.5l-.3 .3 .3 .1v.1h-.5M177.7 160l-.3 .1v.4l.2 .1 .2-.2-.2-.3-.2 .2M189.1 149.1h-.2l-.1 .3v.3h.3v-.3l-.3 .1M191.1 147.4v.3h.4v-.3h.2v.3M192.6 147.1h.4"/>
<path d="M192.7 147v.4l-.4-.1M193 152.7l-.7-.3v.5M196 150.5l.1-.2v.6M196 146.8h.3v.2l-.3 .4h.3M196 151.5h.3l-.2 .3h.2v.3h-.3M196 150.9h.3M196.1 148.2l-.1-.2h.3v.2l-.3 .1v.2h.3l-.1-.3M14.3 178.7l.1-.2v.6M14.3 177.3h.3l-.2 .3h.2v.2h-.3M14.3 179.1h.3M16.8 160.9h.4M17.1 160.8v.4l-.5-.1"/>
<path d="M17.2 177.8l-.6-.2v.4M17.8 160.6v.3h.4v-.3h.2v.3M21.7 179.7l-.2 .2v.4h.3l-.1-.3h-.2M33.7 169h-.2v.5h.2l.1-.2-.1-.2-.2 .2M34 179.7h.4l-.2 .3h.1l.1 .2-.4 .1M34.7 171.7v.3h.2v-.3h.4l-.1 .3M35.4 162.1h.5M35.6 162v.4l-.4-.1M35.9 179.1l-.6-.2v.3M36.4 172.1h-.5l.1 .2M36.4 171.9v.4M37 161.9h-.6l.2 .2"/>
<path d="M37 161.8v.3M37.2 172.3h.4M37.5 172.3v.3l-.5-.2M37.6 167.1l-.6-.3v.5M37.6 161.5v.3h.3v-.3h.3l-.1 .3M39.4 170.2h.4l-.4 .5h.4M39.4 167.8h.4l-.2 .1 .2 .3-.1 .2-.3-.1M55.1 161.2h.2l.1 .1-.4 .5h.4M56.4 163.3h.5M56.6 163.2v.4l-.4-.2M58 163.1h-.6l.2 .2M58 162.9v.4"/>
<path d="M58.6 162.7v.2l.3 .1v-.3h.3l-.1 .3M70.1 162.4l.2-.1 .1 .2-.4 .4h.4M71.2 170.7h.4l-.3 .6M71.4 164.5h.4M71.5 169.5h-.2l-.1 .6h.4v-.3l-.4 .1M71.6 168.4h-.4v.2h.4l-.1 .4-.3-.1M71.6 164.5v.3l-.4-.2M73 164.3h-.6l.2 .2M73 164.1v.4M73.6 163.9v.3h.3v-.3l.3 .1-.1 .2M76.2 166.1l.4-.1-.1 .3-.3-.1v-.2l-.2 .1 .2 .2v-.1M76.2 174.4h.4"/>
<path d="M76.3 161.2h-.2v.5l.1 .1 .2-.2-.2-.3-.1 .2M76.4 174.3v.4l-.4-.2M82 168.5l.2-.1v.6M82 169.6l.3-.1v.3l-.3 .3h.3M82 170.7h.3l-.1 .3h.1v.3l-.3-.1M82 169h.3M128.8 160.7l.2-.1v.6M128.8 161.2h.4M129.4 179.7h.4l-.2 .3h.2v.3h-.4M133.8 164.3l.2-.2 .2 .1v.3h-.3l-.2-.4-.1 .2v.2l.2-.1M134.4 177.4h.3M134.6 177.3v.4l-.4-.1"/>
<path d="M135.1 167.8l-.3 .1v.4l.2 .1 .2-.2-.2-.3-.2 .2M136 166.3v.3h.3l-.1-.2 .2-.2 .2 .2-.1 .2M137.8 166.2h-.6l.2 .1M137.8 166v.3M138.6 165.7h.4M138.8 165.7v.3l-.4-.2M139 171.3l-.6-.2v.3M139.9 160.6h-.2l-.1 .2 .2-.1 .1 .4h-.3M140.2 179.7h.4l-.3 .6M140.8 169h.4l-.3 .1 .3 .2-.1 .2h-.3M140.8 166.6l.2-.1 .2 .2-.4 .5h.4M150.1 169h-.3v.5h.4l-.1-.4-.3 .2"/>
<path d="M151 167.5v.3h.3l-.1-.2 .2-.2 .2 .2-.1 .2M152.8 167.3h-.6l.2 .2M152.8 167.2v.3M153.5 166.9h.5M153.8 166.8v.4l-.4-.1M154 172.5l-.6-.2v.3M155.7 170.1h.5l-.3 .3h.2l.1 .2h-.5M155.8 167.8h.3l.1 .1-.5 .5h.5M171.1 170.1l-.3 .2v.4l.4-.1-.1-.2-.3 .1M171.3 161.2h.4l-.2 .1 .2 .1v.3h-.4M172 168.7v.3h.3l-.1-.2 .3-.1v.3M173.2 163.4l-.6-.2v.4"/>
<path d="M173.8 168.5h-.6l.2 .2M173.8 168.4v.3M174.5 168.1h.5M174.8 168v.4l-.4-.1M175 173.7l-.6-.3v.5M176.7 171.3h.5l-.3 .3 .3 .1v.1h-.5M176.8 169h.3l.1 .1-.5 .4h.5M189.7 171.3h-.2l-.1 .3v.3h.3v-.3l-.3 .1M191.7 169.5v.4h.4v-.4h.2v.4M193.2 169.3h.4M193.3 169.2v.4l-.4-.1M193.6 174.9l-.6-.3v.4"/>
<path d="M196.6 172.7l.1-.2v.6M196.6 169h.3v.2l-.3 .3h.3M196.6 173.7h.3l-.2 .2h.2v.4h-.3M196.6 173.1h.3M196.7 170.4l-.1-.2 .3-.1v.3l-.3 .1v.2h.3l-.1-.3M14.3 182.2h.3v.2l-.3 .4h.3M14.3 199.5h.3l-.2 .3h.2v.2h-.3M14.4 181.1l-.1-.1 .2-.1 .1 .2-.3 .1 .1 .4 .2-.1-.1-.4M16.8 183.1h.4M17.1 183v.4l-.5-.1M17.8 182.8v.3h.4v-.3h.2v.3M33.7 191.1l-.2 .2v.4l.3-.1-.1-.2-.2 .1"/>
<path d="M34.1 182.2h.2l.1 .1-.4 .5h.4M34.7 193.8v.4h.2v-.4l.4 .1-.1 .3M35.4 184.3h.5M35.6 184.2v.4l-.4-.2M36.4 194.4h-.5l.1 .1M36.4 194.2v.3M37 184.1h-.6l.2 .2M37 183.9v.4M37.2 194.5h.4M37.5 194.4v.4l-.5-.2M37.6 183.7v.2l.3 .1v-.3h.3l-.1 .3M37.6 189.3l-.6-.3v.4"/>
<path d="M39.4 192.4h.4l-.4 .5h.4M39.4 189.9h.4l-.2 .2 .2 .3-.1 .1h-.3M40.3 180.9l-.2 .2v.4l.2 .1 .1-.4h-.3M55 180.9h.4l-.2 .2 .2 .1v.2l-.2 .2-.2-.1M55.1 183.3h.2l.1 .2-.4 .4h.4M56.4 185.5h.5M56.6 185.5v.3l-.4-.2M56.9 180.3l-.6-.3v.4M58 185.3h-.6l.2 .2M58 185.1v.4M58.6 184.9v.2l.3 .1v-.3h.3l-.1 .3M61.3 182.2h-.2l-.1 .4 .2 .2 .2-.2-.1-.3-.3 .2"/>
<path d="M70.6 182.2h.4l-.3 .1 .3 .1v.3h-.4M70.7 184.6l.2-.1 .1 .3-.4 .3h.4M71.8 192.9h.4l-.3 .6M72 186.7h.4M72.1 191.7h-.2l-.1 .5h.4v-.2l-.4 .1M72.2 190.5h-.4v.3h.4l-.1 .3h-.3M72.2 186.6v.4l-.4-.2M72.4 181.5l-.6-.3v.5M73.6 186.5h-.6l.2 .2M73.6 186.3v.4M74.2 186.1v.3h.3v-.3h.3l-.1 .3M76.8 188.3l.4-.1-.1 .3-.3-.2v-.1l-.2 .1 .2 .2v-.2"/>
<path d="M76.8 196.6h.4M76.9 183.3l-.2 .1v.5h.2l.1-.2-.2-.2-.1 .2M77 196.6v.3l-.4-.2M82.6 190.7l.2-.2v.6M82.6 191.8h.4l-.4 .5h.4M82.6 192.9h.4l-.2 .3 .2 .1v.1h-.4M82.6 191.1h.4M91.8 188l.2-.2 .2 .2v.2h-.3l-.2-.4-.1 .3h.2M91.8 188.5h.4M92 188.4v.4l-.4-.2M93 188.5h.4M93.2 188.4v.4l-.4-.2"/>
<path d="M93.4 188.1l-.6-.3v.5M94 187.9l.1 .3h.5v-.3l-.2-.1-.2 .2 .2 .2M94.2 188.5h.4M94.4 188.4v.4l-.5-.2M95.2 187.9v.3h.3v-.3l.2-.1v.4M95.4 188.5h.4M95.6 188.4v.4l-.4-.2M96.6 188.5h.4M96.6 187.9h.4M96.8 188.4v.4l-.4-.2M96.8 187.8v.4l-.4-.1M97.6 188.3v-.5l.2 .3v-.2l.3-.1 .1 .5"/>
<path d="M97.8 188.5h.4M98 188.4v.4l-.4-.2M99 188.5h.4M99.2 188.4v.4l-.4-.2M99.4 187.8v.5l-.5-.5-.1 .2v.2M100.2 188.5h.4M100.4 188.4v.4l-.5-.2M100.6 188h-.6l.2 .2M100.6 187.8v.4M101.2 187.9l.4-.1 .2 .1v.2l-.6 .1zM101.4 188.5h.4M101.6 188.4v.4l-.5-.2"/>
<path d="M102.4 188.8v-.4l.3 .2v-.2h.2v.4M102.7 187.8v.4h-.3l.1-.4 .4 .1 .1 .3M103.6 188.8v-.4l.2 .2v-.2h.3v.4M103.8 188l.1-.2 .3 .1v.3h-.4v-.4l-.2 .1v.3l.2-.1M104.8 188.8v-.4l.2 .2 .1-.2h.3v.4M105.4 188.1l-.6-.3v.5M106 188.8v-.4l.2 .2 .1-.2h.3v.4M106 187.9l.1 .3h.5v-.2l-.3-.2v.4M107.2 188.8v-.4l.2 .2 .1-.2h.2v.4M107.2 187.9v.3h.3l-.1-.2 .3-.2 .1 .2-.1 .2M108.4 188.8v-.4l.2 .2 .1-.2h.2v.4M108.6 187.9h.4"/>
<path d="M108.8 187.8v.4l-.5-.1M109.6 188.8v-.4l.3 .2v-.2h.2v.4M109.6 188.3v-.5l.3 .3v-.2l.2-.1v.5M110.8 188.8v-.4l.2 .2v-.2h.3v.4M111.4 187.8v.5l-.4-.5-.2 .1 .1 .3M112 188.8v-.4l.2 .2 .1-.2h.3v.4M112.6 188h-.6l.1 .2M112.6 187.8v.4M113.2 188.8v-.4l.2 .2 .1-.2h.2v.4M113.2 188a.37 .37 0 0 1 .3-.2 .37 .37 0 0 1 .3 .3l-.6 .1zM114.7 187.8l.1 .4h-.4l.1-.4 .4 .1 .1 .3M115 188.4v.4l-.3-.4h-.3v.4"/>
<path d="M115.9 188l.1-.2 .2 .1v.3h-.3v-.2l-.2-.2-.1 .1v.3l.3-.1M116.2 188.4v.4l-.3-.4h-.3v.4M117.4 188.4v.4l-.3-.4-.3 .1 .1 .3M117.4 188.1l-.6-.3v.5M118 187.9l.2 .3h.4l-.1-.4-.3 .1 .1 .3M118.6 188.4v.4l-.4-.4-.2 .1 .1 .3M119.2 187.9v.3h.3l-.1-.3 .3-.1 .1 .4M119.8 188.4v.4l-.4-.4-.2 .1 .1 .3M129.4 182.3l.2-.1v.6M129.4 181h.4l-.4 .6h.4M129.4 182.8h.4M134.4 185.9l.2-.2 .1 .1v.3h-.2l-.2-.4-.1 .2v.2l.2-.1"/>
<path d="M135.7 189.9l-.3 .1v.5h.4l-.1-.4-.3 .2M136.6 188.5v.3h.3l-.1-.2 .2-.2 .2 .2-.1 .2M138.4 188.3h-.6l.2 .2M138.4 188.2v.3M139.1 187.9h.5M139.4 187.8v.4l-.4-.1M139.6 193.5l-.6-.2v.3M140.5 182.2h-.2l-.1 .2 .2-.1 .2 .3-.2 .2-.2-.1M140.5 180.9l-.3 .2v.3l.2 .2 .2-.4h-.4M141.4 191.1h.4l-.3 .3h.2l.1 .2h-.4M141.4 188.8h.3l.1 .1-.4 .5h.4M150.1 191.1l-.3 .2v.4l.4-.1v-.2l-.4 .1"/>
<path d="M151 189.7v.2h.3l-.1-.1 .2-.2 .2 .2-.1 .1M152.8 189.5h-.6l.2 .2M152.8 189.4v.3M153.5 189.1h.5M153.8 189v.4l-.4-.1M154 194.7l-.6-.3v.4M155.7 192.3h.5l-.3 .3h.2l.1 .2h-.5M155.8 189.9h.3l.1 .2-.5 .4h.5M171.1 192.3l-.3 .2v.4l.4-.1-.1-.2-.3 .1M171.3 183.3h.4l-.2 .2 .2 .1v.3h-.4M171.4 181l.3-.1v.2l-.4 .5h.4M172 190.9v.2l.3 .1-.1-.2 .3-.1v.3"/>
<path d="M172.8 180.1h.4M172.9 180v.4l-.4-.2M173.2 185.7l-.6-.2v.3M173.8 190.7h-.6l.2 .2M173.8 190.5v.4M174.4 180.6h-.6l.1 .1M174.4 180.4v.3M174.5 190.3h.5M174.8 190.2v.4l-.4-.1M175 195.9l-.6-.3v.4M175 180.7v.3h.2v-.3l.3-.1v.4M176.7 193.5h.5l-.3 .3h.2l.1 .2-.5 .1"/>
<path d="M176.8 191.2l.3-.1 .1 .2-.5 .4h.5M177.7 182.2h-.3v.5l.2 .1 .2-.2-.2-.3-.2 .2M189.7 193.5h-.2l-.1 .3v.2l.3 .1v-.3h-.3M191.7 191.8v.3h.4l-.1-.3 .2-.1 .1 .4M193.2 191.5h.4M193.3 191.4v.4l-.4-.2M193.6 197.1l-.6-.3v.4M196.6 194.9l.1-.2v.6M196.6 191.2l.3-.1v.3l-.3 .3h.3M196.6 196h.3l-.2 .1 .2 .1v.3h-.3M196.6 195.3h.3M196.7 192.6l-.1-.2 .3-.1v.3l-.3 .1v.2h.3l-.1-.3"/>
<path d="M14.3 200.9l.1-.2v.6M14.3 204.3h.3v.3l-.3 .3h.3M14.3 201.3h.3M14.4 203.4l-.1-.2h.3l-.1 .2h-.2l.1 .4 .2-.1-.1-.3M16.8 205.3h.4M17.1 205.2v.4l-.5-.2M17.2 200.1l-.6-.2v.3M17.8 204.9v.4h.4v-.4h.2v.4M21.7 201.9l-.2 .2v.4h.3l-.1-.4-.2 .1M33.7 213.3l-.2 .2v.4l.3-.1-.1-.2-.2 .1M34 201.9h.4l-.2 .2h.1l.1 .3-.4 .1M34.1 204.3h.2l.1 .2-.4 .4h.4"/>
<path d="M34.7 216v.4h.2v-.4l.4 .1-.1 .3M35.4 206.5h.5M35.6 206.4v.4l-.4-.2M35.9 201.3l-.6-.3v.4M36.4 216.5h-.5l.1 .2M36.4 216.4v.3M37 206.3h-.6l.2 .2M37 206.1v.4M37.2 216.7h.4M37.5 216.6v.4l-.5-.1M37.6 211.5l-.6-.3v.4M37.6 205.9v.2l.3 .1v-.3h.3l-.1 .3"/>
<path d="M39.4 214.6h.4l-.4 .5h.4M39.4 212.1h.4l-.2 .2 .2 .2v.2l-.4-.1M40.3 203.2h-.2v.5l.2 .1 .1-.2-.1-.3-.2 .2M55 203.2h.4l-.2 .1 .2 .3-.2 .2-.2-.1M55.1 205.6l.2-.1 .1 .2-.4 .4h.4M56.4 207.7h.5M56.6 207.6v.4l-.4-.2M56.9 202.5l-.6-.3v.4M58 207.5h-.6l.2 .1M58 207.3v.3M58.6 207.1v.3h.3v-.3h.3l-.1 .3M61.3 204.3h-.2l-.1 .5 .2 .1 .2-.1-.1-.3-.3 .2"/>
<path d="M70.6 204.3h.4l-.3 .2 .3 .1v.3h-.4M70.7 206.8l.2-.1 .1 .3-.4 .3h.4M71.8 215.1h.4l-.3 .6M72 208.9h.4M72.1 213.9h-.2l-.1 .5h.4v-.2h-.4M72.2 212.7h-.4v.3h.4l-.1 .3-.3-.1M72.2 208.8v.4l-.4-.2M72.4 203.7l-.6-.3v.4M73.6 208.7h-.6l.2 .2M73.6 208.6v.3M74.2 208.2v.4h.3v-.4l.3 .1-.1 .3M76.8 210.4h.4v.3h-.3l-.1-.3h-.2l.1 .3 .1-.1"/>
<path d="M76.8 218.8h.4M76.9 205.5l-.2 .2v.4l.3-.1-.1-.2-.2 .1M77 218.7v.4l-.4-.2M82.6 212.9l.2-.2v.6M82.6 214h.4l-.4 .5h.4M82.6 215.1h.4l-.2 .2h.1l.1 .3-.4 .1M82.6 213.3h.4M92.2 212.3h-.6l.1 .2M92.2 212.1v.4M93.4 212.1v.4l-.3-.4h-.3v.4M94 212.5v-.4l.2 .2 .1-.2h.2v.4M95.4 212.2h.4"/>
<path d="M95.6 212.1v.4l-.4-.2M96.4 212.1v.4h.2v-.4l.4 .1-.1 .3M97.6 212.2l.1 .3h.5v-.4l-.4 .1 .1 .3M99.4 212.4l-.6-.3v.4M100.3 212.2h.3l-.1 .3h-.2v-.3l-.3-.1v.4l.3-.1M101.5 212.1l.1 .3-.4 .1v-.4h.4l.2 .3M102.4 212l.5-.1 .1 .2-.3 .1-.3-.1zM103 212.6h-.6l.2 .1M103 212.4v.3M104.2 212.6h-.6l.2 .1M104.2 212h-.6l.2 .2M104.2 211.9v.3"/>
<path d="M104.2 212.4v.3M105.4 212.6h-.6l.1 .1M105.4 211.9v.3l-.4-.3-.2 .1 .1 .2M105.4 212.4v.3M106 212.2v-.3l.2 .1v-.1h.4v.3M106.6 212.6h-.6l.1 .1M106.6 212.4v.3M107.4 211.9h.4M107.6 211.8v.4l-.5-.2M107.8 212.6h-.6l.2 .1M107.8 212.4v.3M108.4 211.9v.2l.3 .1v-.3h.3l-.1 .3"/>
<path d="M109 212.6h-.6l.2 .1M109 212.4v.3M109.6 211.9v.1l.3 .2 .3-.1v-.2h-.3v.3M110.2 212.6h-.6l.2 .1M110.2 212.4v.3M111.4 212.6h-.6l.2 .1M111.4 212l-.6-.2v.4M111.4 212.4v.3M112.2 212l.4-.1-.1 .3-.3-.2v-.1l-.2 .1 .1 .2 .1-.2M112.6 212.6h-.6l.1 .1M112.6 212.4v.3M113.4 211.9l.2 .1-.3 .2-.1-.2v-.1h.5l.1 .2"/>
<path d="M113.8 212.6h-.6l.1 .1M113.8 212.4v.3M114.4 211.9l.6 .1a.3 .3 0 0 1-.3 .2 .3 .3 0 0 1-.3-.3zM115 212.4v.4l-.4-.4-.2 .1v.2M116.2 212.4v.4l-.4-.4-.2 .1v.2M116.2 212h-.6l.2 .2M116.2 211.9v.3M117.4 212.4v.4l-.4-.4-.2 .1 .1 .2M117.4 211.9v.3l-.3-.3h-.3l.1 .3M118 212.2v-.3l.2 .1v-.1h.4l-.1 .3M118.6 212.4v.4l-.4-.4-.2 .1 .1 .2M119.4 211.9h.4"/>
<path d="M119.6 211.8v.4l-.4-.2M119.8 212.4v.4l-.5-.4-.1 .2 .1 .1M128.1 202.5h.5l-.3 .2 .3 .1v.3h-.5M128.2 205.1l.2-.2v.6M128.2 203.8h.4v.2l-.5 .3h.5M128.2 205.5h.4M133.2 208.7l.4-.1-.1 .3-.3-.2v-.1l-.2 .1 .1 .2 .1-.2M133.2 200.2h.4M133.4 200.1v.3h-.4M134.5 212.1l-.3 .1v.5h.3l.1-.2-.2-.2-.2 .2M135.4 210.7v.2h.3l-.1-.1 .2-.2 .2 .2-.1 .1M137.2 210.5h-.6l.2 .2"/>
<path d="M137.2 210.4v.3M138 210.1h.4M138.2 210v.4l-.4-.1M138.4 215.7l-.6-.3v.4M139 202.5h.4l-.3 .7M139.3 204.9h-.2l-.1 .3 .2-.1 .1 .4-.3-.1M139.3 203.8h-.2l-.1 .2v.2l.2 .1v-.4l-.2 .2M140.2 210.9l.4 .1-.4 .5h.4M140.2 213.3h.4l-.3 .3h.2l.1 .2h-.4M150.1 213.3l-.3 .2v.4l.4-.1v-.2l-.4 .1M151 211.9v.2l.3 .1-.1-.2 .3-.1v.3M152.8 211.7h-.6l.2 .2"/>
<path d="M152.8 211.5v.4M153.5 211.3h.5M153.8 211.2v.3h-.4M154 216.9l-.6-.3v.4M155.7 214.5h.5l-.3 .3h.2l.1 .2h-.5M155.8 212.1h.3l.1 .2-.5 .4h.5M171.1 214.5l-.3 .2v.4l.4-.1-.1-.2h-.3M171.3 205.5h.4l-.2 .3h.2v.2h-.4M171.4 203.2h.3v.2l-.4 .4h.4M172 213.1v.2l.3 .1-.1-.3h.3v.3M172.8 202.3h.4M172.9 202.2v.4l-.4-.1"/>
<path d="M173.2 207.9l-.6-.3v.4M173.8 212.9h-.6l.2 .2M173.8 212.7v.4M174.4 202.7h-.6l.1 .2M174.4 202.6v.3M174.5 212.5h.5M174.8 212.4v.4l-.4-.2M175 218.1l-.6-.3v.4M175 202.9v.3h.2v-.3l.3-.1v.4M176.7 215.7h.5l-.3 .2 .3 .1v.2l-.5 .1M176.8 213.4l.3-.1 .1 .2-.5 .4h.5M177.7 204.3l-.3 .1v.5h.2l.2-.1-.2-.3-.2 .2"/>
<path d="M189.7 215.7h-.2l-.1 .2v.3l.3 .1v-.4l-.3 .1M191.7 214v.2h.4l-.1-.2 .2-.1 .1 .3M193.2 213.7h.4M193.3 213.6v.4l-.4-.2M193.6 219.2l-.6-.2v.4M196.6 217l.1-.1v.7M196.6 213.4l.3-.1v.3l-.3 .3h.3M196.6 218.1h.3l-.2 .2 .2 .1v.3h-.3M196.6 217.6h.3M196.7 214.8l-.1-.2 .3-.1v.3h-.3v.3h.3l-.1-.3M14.3 223.1l.1-.2v.6M14.3 226.5h.3v.3l-.3 .3h.3"/>
<path d="M14.3 221.7h.3l-.2 .3h.2v.2h-.3M14.3 223.5h.3M14.4 225.6l-.1-.3h.3l-.1 .3h-.2l.1 .3 .2-.1-.1-.2M16.8 227.5h.4M17.1 227.4v.4l-.5-.2M17.2 222.3l-.6-.3v.4M17.8 227.1v.4h.4v-.4h.2v.4M21.7 224.1l-.2 .1v.5h.3l-.1-.4-.2 .1M33.7 235.5l-.2 .2v.4l.3-.1-.1-.2h-.2M34 224.1h.4l-.2 .2 .2 .1v.2l-.2 .1h-.2M34.1 226.5h.2l.1 .2-.4 .4h.4M34.7 238.3v.2h.2l-.1-.1 .3-.2 .2 .2-.1 .1"/>
<path d="M35.4 228.7h.5M35.6 228.6v.4l-.4-.2M35.9 223.5l-.6-.3v.4M36.4 238.7h-.5l.1 .2M36.4 238.5v.4M37 228.5h-.6l.2 .1M37 228.3v.3M37.2 238.9h.4M37.5 238.8v.3h-.5M37.6 228v.3l.3 .1v-.4h.3l-.1 .4M37.6 233.6l-.6-.2v.4M39.4 236.8l.3-.1 .1 .2-.4 .4h.4"/>
<path d="M39.4 234.3h.4l-.2 .3h.2v.2h-.4M40.3 225.3l-.2 .1v.4l.2 .1 .1-.1-.1-.3-.2 .2M55 225.3h.4l-.2 .2 .2 .3-.2 .1-.2-.1M55.1 227.8l.2-.1 .1 .2-.4 .4h.4M56.4 229.9h.5M56.6 229.8v.4l-.4-.2M56.9 224.7l-.6-.3v.4M58 229.7h-.6l.2 .2M58 229.5v.4M58.6 229.2v.4h.3v-.4l.3 .1-.1 .3M61.3 226.5h-.2l-.1 .3 .1 .3h.2l.1-.2-.1-.2-.3 .2M70.6 226.5h.4l-.3 .2 .3 .1v.2h-.4"/>
<path d="M70.7 229l.2-.1 .1 .3-.4 .3h.4M71.8 237.3h.4l-.3 .6M72 231.1h.4M72.1 236.1h-.2l-.1 .5h.4v-.3l-.4 .1M72.2 234.9h-.4v.3h.4v.2h-.4M72.2 231v.4l-.4-.1M72.4 225.8l-.6-.2v.4M73.6 230.9h-.6l.2 .2M73.6 230.8v.3M74.2 230.4v.4h.3v-.4l.3 .1-.1 .3M76.8 232.6l.4-.1v.4h-.3l-.1-.4-.2 .1 .1 .3 .1-.1M76.9 227.7l-.2 .2v.4l.3-.1-.1-.2h-.2"/>
<path d="M82.6 235.1l.2-.2v.6M82.6 236.2h.4l-.4 .5h.4M82.6 237.3h.4l-.2 .2 .2 .1v.2l-.4 .1M82.6 235.5h.4M128.8 227.3l.2-.2v.6M128.8 225.9h.4v.3l-.4 .3h.4M128.8 224.7h.4l-.2 .2 .2 .1v.3h-.4M128.8 227.7h.4M133.8 230.8h.4l-.1 .3-.3-.2v-.1h-.2l.1 .3 .1-.2M133.8 222.4h.4M134 222.3v.4l-.4-.2M135.1 234.3l-.3 .2v.4l.4-.1-.1-.2-.3 .1"/>
<path d="M136 232.9v.2h.3l-.1-.1 .2-.2 .2 .2-.1 .1M137.8 232.7h-.6l.2 .2M137.8 232.5v.4M138.6 232.3h.4M138.8 232.2v.3h-.4M139 237.9l-.6-.3v.4M139.6 224.7h.4l-.3 .6M139.9 227.1h-.2l-.1 .3h.3v.3l-.3-.1M139.9 225.9h-.2l-.1 .3v.2l.2 .1 .1-.3-.2-.1-.1 .2M140.8 235.5h.4l-.3 .3h.2l.1 .2h-.4M140.8 233.1h.3l.1 .2-.4 .4h.4M150.7 235.5l-.3 .2v.3h.3v-.2h-.3"/>
<path d="M151.6 234.1v.2l.2 .1v-.3h.4l-.1 .3M153.4 233.9h-.6l.2 .2M153.4 233.7v.4M154.1 233.5h.5M154.4 233.4v.4l-.4-.2M154.6 239.1l-.6-.3v.4M156.3 236.7h.5l-.3 .2h.2l.1 .3-.5 .1M156.4 234.4l.3-.1 .1 .2-.5 .4h.5M171.7 236.7l-.3 .2v.4h.3v-.4l-.3 .1M172 225.3h.3v.3l-.3 .3h.3M172 227.7h.3l-.1 .3h.1v.2h-.3M172.6 235.2v.3l.2 .1v-.3l.3-.1v.4"/>
<path d="M173.4 224.5h.4M173.5 224.4v.3h-.4M173.8 230.1l-.6-.3v.4M174.4 235.1h-.6l.1 .1M174.4 234.9v.3M175 224.9h-.6l.1 .2M175 224.7v.4M175.1 234.7h.5M175.4 234.6v.4l-.4-.2M175.6 225.1v.2h.2v-.2l.3-.1v.3M177.3 237.9h.5l-.3 .2h.2l.1 .3-.5 .1M177.4 235.6l.3-.1 .1 .2-.5 .4h.5"/>
<path d="M178.3 226.5l-.3 .1v.5h.3l.1-.2-.2-.2-.2 .2M190.3 237.9h-.2l-.2 .2v.3l.4 .1v-.4l-.4 .1M192.3 236.2v.2h.4l-.1-.2 .2-.1 .2 .2-.1 .1M193.8 235.9h.4M193.9 235.8v.4l-.4-.2M197.1 239.3l.2-.2v.6M197.1 235.6l.4-.1v.3l-.4 .3h.4M197.1 239.7h.4M197.3 236.9h-.2l.3-.2 .1 .2-.4 .2 .1 .2h.3l-.1-.4M76.8 241h.4M77 240.9v.4l-.4-.2M175.6 240.2l-.6-.2v.4"/>
<path d="M194.2 241.4l-.6-.2v.4M197.1 240.3h.4l-.2 .2 .2 .1v.2h-.4"/>
</g>
<g fill="none" stroke="#910000" stroke-width=".25">
<path d="M23.7 26.6v2M24.4 26.6v2M27.9 34h1.9M27.9 33.2h1.9M30.9 26.6v2M31.6 26.6v2M51.9 30.9h1.9M51.9 30.3h1.9M53.6 22.5v1.8M54.4 22.5v1.8M65.7 34h1.9M65.7 33.2h1.9"/>
<path d="M80.6 27.8v2M81.4 27.8v2M130.4 34.4v2M131.1 34.4v2M143 30.9h1.9M143 30.3h1.9M156.3 39.8v2M156.8 34h1.9M156.8 33.2h1.9M156.9 39.8v2M179 35.6v1.9M179.7 35.6v1.9"/>
<path d="M180.8 30.9h2M180.8 30.3h2M186.2 35.6v1.9M186.9 35.6v1.9M23.7 48.8v2M24.4 48.8v2M27.9 56.2h1.9M27.9 55.4h1.9M30.9 48.8v2M31.6 48.8v2M51.9 53.1h1.9M51.9 52.5h1.9"/>
<path d="M53.6 44.7v1.8M54.4 44.7v1.8M65.7 56.2h1.9M65.7 55.4h1.9M80.1 50v1.9M80.7 50v1.9M130.4 56.6v1.9M131.1 56.6v1.9M143.6 53.1h1.9M143.6 52.5h1.9M157.4 56.2h1.9M157.4 55.4h1.9"/>
<path d="M179.6 57.8v1.9M180.3 57.8v1.9M181.4 53.1h1.9M181.4 52.5h1.9M186.8 57.8v1.9M187.5 57.8v1.9M23.7 71v1.9M24.4 71v1.9M27.9 78.4h1.9M27.9 77.6h1.9M30.9 71v1.9M31.6 71v1.9"/>
<path d="M51.9 75.3h1.9M51.9 74.6h1.9M53.6 66.8v1.9M54.4 66.8v1.9M65.7 78.4h1.9M65.7 77.6h1.9M80.6 72.2v1.9M81.4 72.2v1.9M131 78.8v1.9M131.8 78.8v1.9M143.6 75.3h1.9M143.6 74.6h1.9"/>
<path d="M156.8 62v2M157.4 78.4h1.9M157.4 77.6h1.9M157.5 62v2M181.4 75.3h1.9M181.4 74.6h1.9M23.7 93.2v1.9M24.4 93.2v1.9M27.9 99.8h1.9M30.9 93.2v1.9M31.6 93.2v1.9M51.9 97.5h1.9"/>
<path d="M51.9 96.8h1.9M53.6 89v1.9M54.4 89v1.9M65.7 99.8h1.9M80.6 94.4v1.9M81.4 94.4v1.9M143.6 97.5h1.9M143.6 96.8h1.9M156.8 84.2v1.9M157.4 99.8h1.9M157.5 84.2v1.9M179.6 80.1v1.8"/>
<path d="M180.3 80.1v1.8M181.4 97.5h1.9M181.4 96.8h1.9M186.8 80.1v1.8M187.5 80.1v1.8M23.7 115.4v1.9M24.4 115.4v1.9M27.9 100.5h1.9M30.9 115.4v1.9M31.6 115.4v1.9M51.9 119.7h1.9M51.9 119h1.9"/>
<path d="M53.6 111.2v2M54.4 111.2v2M65.7 100.5h1.9M80.6 116.6v1.9M81.4 116.6v1.9M129.8 101v1.9M130.5 101v1.9M144.2 119.7h2M144.2 119h2M156.8 106.4v1.9M157.4 100.5h1.9M157.5 106.4v1.9"/>
<path d="M179.6 102.2v1.9M180.3 102.2v1.9M182 119.7h1.9M182 119h1.9M186.8 102.2v1.9M187.5 102.2v1.9M23.7 137.6v1.9M24.4 137.6v1.9M27.9 122.7h1.9M27.9 122h1.9M30.9 137.6v1.9M31.6 137.6v1.9"/>
<path d="M53.6 133.4v1.9M54.4 133.4v1.9M65.7 122.7h1.9M65.7 122h1.9M80.6 138.8v1.9M81.4 138.8v1.9M130.4 123.2v1.9M131.1 123.2v1.9M157.4 128.6v1.9M158 122.7h1.9M158 122h1.9M158.1 128.6v1.9"/>
<path d="M180.2 124.4v1.9M180.9 124.4v1.9M187.4 124.4v1.9M188.1 124.4v1.9M23.7 159.8v1.9M24.4 159.8v1.9M27.9 144.9h1.9M27.9 144.1h1.9M30.9 159.8v1.9M31.6 159.8v1.9M51.9 141.9h1.9M51.9 141.2h1.9"/>
<path d="M53.6 155.6v1.9M54.4 155.6v1.9M65.7 144.9h1.9M65.7 144.1h1.9M130.4 145.4v1.9M131.1 145.4v1.9M143 141.9h1.9M143 141.2h1.9M156.3 150.7v2M156.8 144.9h1.9M156.8 144.1h1.9M156.9 150.7v2"/>
<path d="M179 146.6v1.9M179.7 146.6v1.9M180.8 141.9h2M180.8 141.2h2M186.2 146.6v1.9M186.9 146.6v1.9M27.9 167.1h1.9M27.9 166.4h1.9M51.9 164.1h1.9M51.9 163.4h1.9M53.6 177.8v1.9M54.4 177.8v1.9"/>
<path d="M65.7 167.1h1.9M65.7 166.4h1.9M80.1 161v1.9M80.7 161v1.9M130.4 167.6v1.9M131.1 167.6v1.9M143.6 164.1h1.9M143.6 163.4h1.9M156.8 172.9v2M157.4 167.1h1.9M157.4 166.4h1.9M157.5 172.9v2"/>
<path d="M179.6 168.8v1.9M180.3 168.8v1.9M181.4 164.1h1.9M181.4 163.4h1.9M186.8 168.8v1.9M187.5 168.8v1.9M23.7 182v1.9M24.4 182v1.9M27.9 189.3h1.9M27.9 188.6h1.9M30.9 182v1.9M31.6 182v1.9"/>
<path d="M51.9 186.3h1.9M51.9 185.5h1.9M53.6 199.9v2M54.4 199.9v2M65.7 189.3h1.9M65.7 188.6h1.9M80.6 183.2v1.9M81.4 183.2v1.9M131 189.8v1.8M131.8 189.8v1.8M143.6 186.3h1.9M143.6 185.5h1.9"/>
<path d="M156.8 195.2v1.9M157.4 189.3h1.9M157.4 188.6h1.9M157.5 195.2v1.9M179.6 191v1.9M180.3 191v1.9M181.4 186.3h1.9M181.4 185.5h1.9M186.8 191v1.9M187.5 191v1.9M23.7 204.2v1.8M24.4 204.2v1.8"/>
<path d="M27.9 211.5h1.9M27.9 210.8h1.9M30.9 204.2v1.8M31.6 204.2v1.8M51.9 208.5h1.9M51.9 207.7h1.9M65.7 211.5h1.9M65.7 210.8h1.9M80.6 205.4v1.9M81.4 205.4v1.9M129.8 212v1.9M130.5 212v1.9"/>
<path d="M143.6 208.5h1.9M143.6 207.7h1.9M156.8 217.4v1.8M157.4 211.5h1.9M157.4 210.8h1.9M157.5 217.4v1.8M179.6 213.1v2M180.3 213.1v2M181.4 208.5h1.9M181.4 207.7h1.9M186.8 213.1v2M187.5 213.1v2"/>
<path d="M23.7 226.4v1.9M24.4 226.4v1.9M27.9 233.6h1.9M27.9 233h1.9M30.9 226.4v1.9M31.6 226.4v1.9M51.9 230.7h1.9M51.9 229.9h1.9M53.6 222.1v2M54.4 222.1v2M65.7 233.6h1.9M65.7 233h1.9"/>
<path d="M80.6 227.5v2M81.4 227.5v2M130.4 234.1v2M131.1 234.1v2M144.2 230.7h2M144.2 229.9h2M157.4 239.6v1.8M158 233.6h1.9M158 233h1.9M158.1 239.6v1.8M180.2 235.3v2M180.9 235.3v2"/>
<path d="M182 230.7h1.9M182 229.9h1.9M187.4 235.3v2M188.1 235.3v2"/>
</g>
<g fill="none" stroke="#0f0f0f" stroke-width=".2">
<path d="M95.7 133.4l.2 .2h.4v-.3l-.3 .1 .1 .2M95.7 135.1h.7M95.8 136h-.1a.34 .34 0 0 0 .3 .4 .34 .34 0 0 0 .4-.3l-.1-.2h-.2v.2M95.8 134.5l.3-.1 .3 .2v.1l-.6 .1zM96.1 135.7v-.3l-.2-.1-.2 .4h.7M96.4 133.9v.3l-.3-.3-.4 .1 .1 .2M97 136v.2l.2 .2a.22 .22 0 0 0 .3-.2 .22 .22 0 0 0-.2-.3v.2M97 134.5l.3-.1 .3 .2v.1l-.5 .1zM97 135.1h.6M97.2 135.7v-.3l-.1-.1-.1 .4h.6M97.2 133.3l.1 .3h-.3v-.3h.4l.2 .3M97.6 134.1h-.6l.2 .1"/>
<path d="M97.6 133.9v.3M98.2 136v.2l.2 .2 .4-.2-.1-.3h-.2v.2M98.2 134.5l.4-.1 .2 .1v.2l-.5 .1zM98.2 133.6v-.3l.2 .2v-.2h.3v.3M98.2 135.1h.6M98.5 135.7l-.2-.4-.1 .1v.3h.6M98.8 134.1h-.6l.1 .1M98.8 133.9v.3M99.4 135.4v.3l.1 .1 .4-.1v-.3l-.2 .1M99.4 133.4l.1 .2h.4v-.3h-.3l.1 .3M99.4 134.5h.5M99.4 133.9h.5v.3h-.5z"/>
<path d="M99.7 135.2l-.1-.4h-.2v.4h.5M100.5 135.4v.3l.5 .1 .1-.4-.2 .1M100.5 133.3v.3h.4v-.3h.2v.3M100.5 134.5h.6M100.6 133.9h.4l.1 .3h-.5zM100.9 135.2v-.4h-.4v.4h.6M101.7 133.5l.2-.2h.3l.1 .3h-.6zM101.7 135.6h.6M101.8 135h.4l.1 .3h-.6zM101.8 133.9v.3h.3l.1-.3h.1v.3M102.4 134.3v.5M104.2 139.1h.5l.1 .2-.1 .2h-.4z"/>
<path d="M104.2 136.9l.1 .4 .3-.4 .2 .1-.1 .3M104.2 135v.3h.2l.1-.3 .3 .1-.1 .2M104.2 134.4l.1 .3h.4v-.3M104.2 139.7h.6M104.2 136h.6M104.2 133.6h.6M104.2 133.3l.3 .3M104.4 136.6v-.2l-.1-.1-.1 .3h.6M104.8 138.6h-.6l.2 .2M104.8 138.1h-.6l.2 .2M104.8 133.8v.4h-.6M104.8 135.4v.5"/>
<path d="M104.8 137.4v.4M104.8 138v.3M104.8 138.5v.3M104.8 133.3l-.4 .3M105.4 140v.2l.2 .1 .4-.1-.1-.3h-.2v.2M105.4 138.5l.4-.1 .2 .1v.2l-.5 .1zM105.4 136.8v.3l.1 .1a.3 .3 0 0 1 .1-.3 .3 .3 0 0 1 .4 0v.3M105.4 133.9v.3h.2l.2-.3 .2 .1v.2M105.4 133.4l.5-.1 .1 .3-.5 .1-.1-.1zM105.4 139.1h.6M105.4 135.9h.6M105.4 134.5h.6"/>
<path d="M105.6 137.9l.1 .2-.2 .1-.1-.3h.4l.2 .2M105.7 139.7l-.1-.4h-.2v.4h.6M105.7 136.5l-.2-.3-.1 .1v.2h.6M106 134.8h-.6l.4 .2-.4 .3h.6M106 135.3v.5M106 137.3v.4M106.6 138l.5-.1v.2l-.3 .1-.2-.1zM106.6 136.8v.3a.3 .3 0 0 0 .3 0 .3 .3 0 0 0 .1-.3l.1 .1v.3M106.6 134.2h.5v.3l-.4 .1-.1-.1zM106.6 133.6v.3h.2l.2-.3h.1v.3M106.6 135.9h.5M106.6 139.7h.5"/>
<path d="M106.6 133.3h.5M106.6 139h.5v.3h-.5zM106.9 136.5l-.2-.3-.1 .1v.2h.5M107.1 138.6h-.5l.1 .1M107.1 134.8h-.5l.4 .2-.4 .3h.5M107.1 138.4v.3M107.2 135.3v.5M107.2 137.3v.4M108.9 137.4l.5-.1 .1 .2-.5 .1zM108.9 134.5v.3h.6v-.3M108.9 133.9h.6l-.6 .3h.6M108.9 133.6v-.3l.3 .2 .1-.2h.2v.3"/>
<path d="M108.9 137.9h.6M109 138.8h-.1a.33 .33 0 0 0 .3 .3 .33 .33 0 0 0 .3-.1v-.3h-.2v.2M109 135.1l-.1 .2 .2 .1h.3l.1-.3-.2 .1M109.3 138.5v-.3l-.2-.1-.2 .4h.6M109.3 134.6v.2M109.5 136.7v.3l-.3-.3-.3 .1 .1 .2M109.5 136.1v.3l-.3-.3-.3 .1 .1 .2M109.6 135.5v.5M110.1 137.4l.6-.1 .1 .2-.6 .1zM110.1 134.5v.3h.7v-.3M110.1 133.9h.7l-.7 .3h.7M110.1 137.9h.7"/>
<path d="M110.2 138.8h-.1a.34 .34 0 0 0 .3 .3 .34 .34 0 0 0 .4-.2l-.1-.2h-.2v.2M110.2 135.1l-.1 .2 .2 .1h.3l.2-.1-.1-.2-.2 .1M110.4 138.5v-.3l-.1-.1-.2 .4h.7M110.4 134.6v.2M110.8 136.7v.3l-.4-.3-.3 .1 .1 .2M110.8 136.4l-.7-.3v.3M110.8 133.3v.3l-.4-.3-.3 .1 .1 .2M110.8 135.5v.5M111.4 138.8v.2l.2 .1a.22 .22 0 0 0 .3-.1 .22 .22 0 0 0-.2-.3v.2M111.4 137.4l.5-.1 .1 .2-.5 .1zM111.4 135.1l.1 .3h.3l.2-.1-.1-.2-.2 .1M111.4 134.5v.3h.6v-.3"/>
<path d="M111.4 133.9h.6l-.6 .3h.6M111.4 133.4l.4-.1 .2 .2-.2 .1h-.3zM111.4 137.9h.6M111.6 138.5v-.3l-.1-.1-.1 .4h.6M111.6 134.6v.2M112 136.9h-.6l.1 .1M112 136.4l-.6-.3v.3M112 135.5v.5M112 136.7v.3M113.7 139.2l.5-.1 .1 .1v.3l-.5 .1zM113.7 137.6a.3 .3 0 0 0 .3 .4 .3 .3 0 0 0 .3-.4l-.2-.1v.2M113.7 136.1l.5-.1 .1 .1v.3h-.5z"/>
<path d="M113.7 135l.1 .3h.5v-.3l-.2 .1M113.7 133.6h.6M113.7 139.8h.6M113.7 136.7h.6M113.7 133.3l.4 .3M113.8 134.4v.3h.5v-.3M113.9 138.6h.4M114.1 137.3v-.2l-.3-.2-.1 .4h.6M114.2 138.6v.4l-.5-.2M114.3 133.8v.4h-.6M114.3 133.3l-.3 .3M114.4 135.5v.4"/>
<path d="M114.4 138v.5M114.9 138.1l.1 .3 .3 .1 .2-.2v-.3h-.2v.2M114.9 136.6l.5-.1 .1 .1v.3h-.5zM114.9 136.4v-.4l.3 .2v-.2h.3v.4M114.9 135l.1 .3 .3-.1v-.2h.2v.3M114.9 137.2h.6M115 134.3l-.1 .4h.2h.3l.1-.4M115.3 137.8l-.1-.3h-.3v.3h.6M115.5 133.8v.3h-.6M115.5 133.5h-.6l.2 .1M115.5 133.3v.3M115.6 135.4v.4"/>
<path d="M116.1 136.7l.5-.1 .1 .3-.3 .1-.3-.1zM116.1 137.3h.6M116.2 138.1l-.1 .2 .2 .2 .4-.1v-.3l-.2 .1M116.2 135v.3h.3v-.3h.2v.3M116.2 134.4h.4l.1 .3h-.6zM116.5 137.9v-.4h-.3l-.1 .4h.6M116.5 133.9v.3M116.7 136v.4l-.3-.4-.3 .1 .1 .3M116.7 133.8l-.6 .2 .6 .2M116.7 133.5h-.6l.2 .1M116.7 133.3v.3M116.8 135.4v.5"/>
<path d="M94.5 156.2l.5-.2 .1 .1v.2l-.5 .1zM94.5 156.7h.6M94.6 157.6h-.1a.33 .33 0 0 0 .3 .3 .33 .33 0 0 0 .3-.1v-.3h-.2v.2M94.9 157.3v-.3l-.2-.1-.2 .4h.6M95.1 155.5v.3l-.3-.3-.3 .1 .1 .2M95.1 155.1h-.6l.2 .1M95.1 154.9v.3M95.7 156.2l.4-.2 .3 .2v.1l-.6 .1zM95.7 156.7h.7M95.8 157.6h-.1a.34 .34 0 0 0 .3 .3 .34 .34 0 0 0 .4-.2l-.1-.2h-.2v.2M95.9 154.9h.3l.2 .2-.2 .1h-.3l-.2-.1zM96.1 157.3v-.3l-.2-.1-.2 .4h.7"/>
<path d="M96.4 155.5v.3l-.3-.3-.4 .1 .1 .2M97 157.6v.2l.2 .1a.22 .22 0 0 0 .3-.1 .22 .22 0 0 0-.2-.3v.2M97 156.1l.3-.1 .3 .2v.1l-.5 .1zM97 155l.1 .2h.4v-.3l-.3 .1 .1 .2M97 156.7h.6M97.2 157.3v-.3l-.1-.1-.1 .4h.6M97.6 155.7h-.6l.2 .1M97.6 155.5v.3M99.4 157.6a.3 .3 0 0 0 .3 .3 .3 .3 0 0 0 .2-.3l-.2-.1v.2M99.4 156.1l.4-.1 .1 .1v.2l-.5 .1zM99.4 156.7h.5M99.7 157.3v-.2l-.3-.2v.4h.5"/>
<path d="M99.9 155.7h-.5l.1 .1M99.9 154.9v.3l-.5-.3v.3M99.9 155.5v.3M101.7 157.2h.6M101.8 156.6h.4l.1 .2h-.6zM101.8 155.5v.3l.3-.1 .1-.2h.1v.3M101.8 154.9v.3h.4l.1-.3M102.4 155.9v.5M102.9 156.6v.2h.7v-.2M102.9 154.9h.7l-.7 .3h.7M102.9 158.2h.7M103 159v.4h.2l.1-.4 .3 .1-.1 .3"/>
<path d="M103 157.1v.3h.5v-.3M103.3 158.8v-.3h-.4v.3h.7M103.3 156.7v.1M103.6 156.2h-.7l.2 .1M103.6 155.4v.4M103.6 156v.3M103.6 157.6v.4M103.6 159.5v.5M104.2 159v.4h.2l.1-.4 .3 .1-.1 .3M104.2 157.1l.1 .3h.4v-.3M104.2 156.6v.2h.6v-.2M104.2 156h.5l.1 .2-.2 .1h-.3z"/>
<path d="M104.2 154.9h.6l-.6 .3h.6M104.2 140.6l.1 .3h.4l.1-.2h-.3M104.2 158.2h.6M104.4 158.8v-.3h-.2v.3h.6M104.4 140.3v-.3h-.2v.3h.6M104.4 156.7v.1M104.8 155.4v.4M104.8 157.6v.4M104.8 159.5v.5M105.4 159l.5-.1 .1 .2-.5 .1zM105.4 157.7v.3h.2v-.3l.4 .1-.1 .2M105.4 156.7l.1 .3 .5-.1v-.2l-.3 .1"/>
<path d="M105.4 156.1v.3h.6v-.3M105.4 155.5h.6l-.6 .3h.6M105.4 155l.1 .2h.4v-.3h-.3l.1 .3M105.4 159.5h.6M105.6 156.2v.2M106 158.3v.3l-.4-.3h-.2v.3M106 157.1v.5M106.6 140.5v.3h.5v-.3l-.2 .1M106.9 140.3v-.3l-.3-.1v.4h.5M107.7 159l.5-.1 .1 .2-.5 .1zM107.7 156.7v.2l.5 .1 .1-.3-.2 .1M107.7 156.1v.3h.6v-.3"/>
<path d="M107.7 155.5h.6l-.6 .3h.6M107.7 154.9v.3h.4v-.3h.2v.3M107.7 159.5h.6M108 157.8h.3M108.1 156.2v.2M108.2 157.7v.3l-.5-.1M108.3 158.3v.3l-.3-.3h-.3l.1 .3M108.4 157.1v.5M108.9 159l.5-.1 .1 .2-.5 .1zM108.9 158v-.3l.3 .2 .1-.2h.2v.3M108.9 156.1v.3h.6v-.3M108.9 155.5h.6l-.6 .3h.6"/>
<path d="M108.9 159.5h.6M109 156.7l-.1 .1 .2 .2h.3l.1-.3-.2 .1M109.2 155h.3M109.3 156.2v.2M109.3 154.9v.3l-.4-.1M109.5 158.3v.3l-.3-.3-.3 .1 .1 .2M109.6 157.1v.5M111.4 159l.5-.1 .1 .2-.5 .1zM111.4 156.7l.1 .3h.3l.2-.2-.1-.1-.2 .1M111.4 156.1v.3h.6v-.3M111.4 155.5h.6l-.6 .3h.6M111.4 159.5h.6"/>
<path d="M111.6 157.8h.4l-.1 .2h-.3v-.2l-.2-.1v.3l.2-.1M111.6 156.2v.2M112 158.5h-.6l.1 .1M112 155.1h-.6l.1 .1M112 154.9v.3M112 157.1v.5M112 158.3v.3M112.6 159l.5-.1 .1 .2-.6 .1zM112.6 157.7v.3h.2v-.3l.4 .1-.1 .2M112.6 155.6l.5-.1 .1 .3h-.6zM112.6 155l.5-.1 .1 .3h-.6zM112.6 159.5h.6"/>
<path d="M112.6 156l.6 .4M112.9 157v-.2l-.3-.1v.3h.6M113.2 158.5h-.6l.1 .1M113.2 158.3v.3M113.2 156.7l-.3 .1M113.2 156l-.6 .4M113.2 157.1v.5M113.7 158.8l.6-.1v.3l-.4 .1-.2-.1zM113.7 155.6l.6-.1v.3h-.6zM113.7 155l.6-.1v.3h-.5zM113.7 140.8a.3 .3 0 0 0 .3 .3 .3 .3 0 0 0 .3-.3l-.2-.1v.1M113.7 159.4h.6"/>
<path d="M113.7 156.6v.3M113.7 156.8h.6M113.7 156l.6 .4M113.9 157.6h.4M114.1 160l-.1-.4h-.3v.4h.6M114.1 140.4v-.1l-.3-.2-.1 .3h.6M114.2 157.5v.4l-.5-.1M114.3 158.3h-.6l.2 .2M114.3 158.1v.4M114.3 156l-.6 .4M114.4 157v.4M102.9 160.7h.7a.34 .34 0 0 1-.3 .4 .34 .34 0 0 1-.4-.4z"/>
<path d="M102.9 161.3h.7M103 162.2l-.1 .1 .2 .2h.3l.2-.2-.1-.1-.2 .1M103.3 161.9v-.3l-.4 .1v.2h.7M103.6 160.3l-.7-.2v.3M104.2 162.2l.1 .3h.3l.2-.2-.1-.1-.2 .1M104.2 160.7h.5l.1 .2-.4 .2zM104.2 161.3h.6M104.4 161.9v-.3h-.2v.3h.6M104.4 160.1h.4l-.1 .3h-.3v-.3h-.2v.3l.2-.1M105.4 160.4v.2l.2 .1h.3l.1-.3-.3-.1v.2M105.7 160.1l-.2-.4-.1 .1v.3h.6M107.7 160.4l.1 .3h.3l.2-.1v-.3h-.2v.2"/>
<path d="M108.1 160.1l-.1-.4-.3 .1v.3h.6M109 160.4h-.1a.33 .33 0 0 0 .3 .3 .33 .33 0 0 0 .3-.1v-.3h-.2v.2M109.3 160.1v-.3l-.2-.1-.2 .4h.6M111.4 160.4v.2l.2 .1a.22 .22 0 0 0 .3-.1 .22 .22 0 0 0-.2-.3v.2M111.6 160.1v-.3l-.1-.1-.1 .4h.6M112.6 160.4v.2l.2 .1h.3l.1-.3-.3-.1v.2M112.9 160.1l-.2-.4-.1 .1v.3h.6M113.7 160.2v.3l.2 .1 .4-.1v-.3l-.2 .1"/>
</g>
<path d="M111.6 243.5l.6-.4v.4h.6h-.6v.4z" fill="#910000"/>
<path d="M112.8 243.5h.1" fill="none" stroke="#910000" stroke-width=".2"/>
<g fill="none" stroke="#090" stroke-width=".2">
<path d="M82.8 13.2h1.8M10.9 27.6h2.9M10.9 22.8h2.9M12.7 23.4h1.1v.6M13.8 26.4v.6h-1.1M17.4 28.8v13.8M22.2 25.2v2.4M25.9 25.2h2.9v6.6M25.9 35.4v1.2h7.2M28.8 35.4v5.4h11.5v-3M29.4 27.6h-3.5v4.2M32.5 25.2h1.2"/>
<path d="M33.1 25.2v2.4M33.7 27.6v4.2h7.2v-5.4h2.3v4.2M36 30v3h-4.2v9.6M36 21.6v1.2M40.3 35.4h2.9M41.4 21.6v11.4h-3.6M43.2 34.2v3M46.9 26.4h1.1M51.6 26.4h3.1M52.2 23.4h-4.7v3M52.8 26.4v2.4M52.8 32.4v9.6"/>
<path d="M54.7 28.8v4.8h7.1v.6M55.8 23.4h6v6.6M57 21.6v2.4M57 31.2v11.4M61.8 37.8v4.2M61.8 27.6h.6M66 27.6h4.2M66.6 27.6v4.2M66.6 35.4v6.6M70.2 30h-1.2v8.4h2.4M71.4 36h-.6v6M72.6 32.4h-2.4v10.2h-63.6"/>
<path d="M72.6 21.6v3.6M77.4 28.8h1.8M77.4 21.6v10.8M78 28.8v2.4h-1.8v1.8h-6.6v4.2h1.8M82.8 28.8h2.4v43.2h15.6v4.2M83.4 37.2h3v88.7h-3M83.4 38.4h3.6v88.7h-3.6M83.4 36h5.4v65.4h.6v2.4h6.6v-1.2M84 28.8v2.4M84 34.8v7.2h-76.2v199.7h84.6v-28.2M127.8 29.4v-7.2h76.1v199.7h-111.5M127.8 33v2.4"/>
<path d="M128.4 28.2h-6.6v76.7h-13.8v-2.3M128.4 27h-3.1v88.8h3.1M128.4 25.8h-3.6v88.8h3.6M129 35.4h-2.4v36.6h-24.6v4.2M132.5 35.4h1.9M134.4 31.8v10.8h68.9M139.1 39v3.6M140.4 27h1.8v4.2h-6.6v1.8h-1.8v2.4M140.4 36.6h4.2M140.4 25.8h2.4v8.4h-1.2M141 22.2v6h-.6M141.6 21.6v10.2h-2.5"/>
<path d="M144 22.2v6.6M144 32.4v4.2M148.2 36.6h.6M148.8 34.2v6.6h6M148.8 22.2v4.2M148.8 30v.6h7.2v4.8M153.5 21.6v11.4M156 37.8h3M157.8 22.2v9.6M157.8 35.4v2.4M162.6 37.8h1.2M163.2 37.8v3h-4.8"/>
<path d="M167.3 28.8h3.1M167.3 33.6v4.2h2.5v-5.4h7.2v4.2M167.3 22.2v1.2M167.3 27v3M170.4 26.4v-3h11.3v5.4M172.8 31.2h-3.6v11.4M172.8 21.6v2.4M177 39h1.2M177.6 27.6h7.2v1.2M177.6 36.6v2.4M178.8 21.6v9.6h-4.3v3M181.7 32.4v6.6h3.1"/>
<path d="M184.8 32.4v4.2h-3.7M188.3 36.6v2.4M193.2 21.6v13.8M196.7 36.6h3.1M198 37.2h-1.3v.6M9 43.8h67.8v10.8M10.9 49.8h2.9M10.9 45h2.9M12.7 45.6h1.1v.6M13.8 48.6v.5h-1.1M17.4 51v13.8M22.2 47.4v2.4"/>
<path d="M25.9 47.4h2.9v6.6M25.9 57.6v1.2h7.2M28.8 57.6v5.3h11.5v-2.9M29.4 49.8h-3.5v4.2M32.5 47.4h1.2M33.1 47.4v2.4M33.7 49.8v4.2h7.2v-5.4h2.3v4.2M36 52.2v3h-4.2v9.6M36 43.8v1.2M37.8 40.2v2.4M40.3 57.6h2.9M41.4 43.8v11.4h-3.6"/>
<path d="M43.2 40.8v1.2M43.2 56.3v3.1M46.9 48.6h1.1M51.6 48.6h3.1M52.2 45.6h-4.7v3M52.8 48.6v2.4M52.8 54.6v9.6M54.7 51v4.8h7.1v.5M55.8 45.6h6v6.6M57 43.8v2.4M57 53.4v11.4M61.8 49.8h.6"/>
<path d="M61.8 60v4.2M66 49.8h4.2M66.6 49.8v4.2M66.6 57.6v6.6M69.6 52.2h-1.1v8.4h2.3M70.8 58.2h-.6v6M72 54.6h-2.4v10.2M72 43.8v3.6M76.8 51h1.8M77.4 51v2.4h-1.8v1.8h-6.6v4.2h1.8M82.2 51h2.4v21.6h15v3.6M82.8 59.4h3.6"/>
<path d="M82.8 58.2h4.8v43.8h1.2v2.4h8.4v-1.8M83.4 57v7.2h-75.6M83.4 51v2.4M124.8 48h3.6M125.3 49.1h3.1M127.8 55.2v2.4M128.4 50.4h-6v55.1h-16.8v-2.9M129 57.6h-1.8v15h-24v3.6M132.5 57.6h1.9M134.4 54v10.8h68.9M140.4 49.1h1.8v4.3h-6.6v1.8h-1.8v2.4M140.4 48h2.4v8.3h-1.2"/>
<path d="M141 58.8h4.2M141 44.4v6h-.6M144.6 44.4v6.6M144.6 54.6v4.2M148.8 58.8h.6M149.4 56.3v6.6h6M149.4 44.4v4.2M149.4 52.2v.6h7.2v4.8M153.5 40.2v2.4M154.1 43.8v11.4M156.6 60h3M158.4 44.4v9.6"/>
<path d="M158.4 57.6v2.4M163.2 60h1.2M163.8 60v2.9h-4.8M167.9 51h3.1M167.9 55.8v4.2h2.5v-5.4h7.2v4.2M167.9 44.4v1.2M167.9 49.1v3.1M171 48.6v-3h11.3v5.4M173.4 53.4h-3.6v11.4M173.4 43.8v2.4M174.5 41.4v1.2M178.2 49.8h7.2v1.2"/>
<path d="M178.2 58.8v2.4M179.4 43.8v9.6h-4.3v2.9M182.3 54.6v6.6h3.1M185.4 54.6v4.2h-3.7M188.9 58.8v2.4M193.8 43.8v13.8M196.7 40.2v.6h1.3M196.7 41.4h3.1M197.3 58.8h3.1M198.6 59.4h-1.3v.6M203.9 44.4h-76.1v7.2M205.2 43.8h-63.6v10.2h-2.5"/>
<path d="M6.6 64.8h63.6M9 66h68.4v10.8M10.9 72h2.9M10.9 67.2h2.9M12.7 67.8h1.1v.6M13.8 70.7v.7h-1.1M17.4 73.2v13.8M22.2 69.6v2.4M25.9 69.6h2.9v6.6M25.9 79.8v1.2h7.2M28.8 79.8v5.3h11.5v-2.9M29.4 72h-3.5v4.2"/>
<path d="M32.5 69.6h1.2M33.1 69.6v2.4M33.7 72v4.2h7.2v-5.5h2.3v4.3M36 74.4v2.9h-4.2v9.7M36 66v1.2M37.8 62.4v2.4M40.3 79.8h2.9M41.4 66v11.3h-3.6M43.2 62.9v1.3M43.2 78.6v3M46.9 70.7h1.1M51.6 70.7h3.1"/>
<path d="M52.2 67.8h-4.7v2.9M52.8 70.7v2.5M52.8 76.8v9.6M54.7 73.2v4.7h7.1v.7M55.8 67.8h6v6.6M57 66v2.4M57 75.6v11.4M61.8 72h.6M66 72h4.2M66.6 72v4.2M66.6 79.8v6.6M70.2 74.4h-1.2v8.4h2.4"/>
<path d="M72.6 76.8h-2.4v10.2h-63.6M72.6 66v3.6M77.4 73.2h1.8M78 73.2v2.4h-1.8v1.7h-6.6v4.3h1.8M82.8 73.2h15.6v3M82.8 60.6h4.2M84 73.2v2.4M84 79.2v7.2h-76.2M86.4 71.4h21.6M96 76.2v-1.8h-10.2v43.2h-3M97.2 76.2v-2.4h-12v21.6h-2.4M104.4 76.2v-3h22.8v6.6h2.4"/>
<path d="M105.6 76.2v-2.4h21v28.2h1.8M106.8 76.2v-1.8h19.2v49.8h3M124.8 69.6h4.2M128.4 77.3v2.5M129 70.7h-21v5.5M129 72v-.6h-6v34.7h-18.6v-3.5M133.2 79.8h1.8M135 75.6v11.4h68.3M135 66v.6M139.1 61.2v3.6M139.7 76.2h2.5v-10.2h51.6v13.8M141 70.7h1.8v4.9h-6.6v1.7h-1.8v2.5"/>
<path d="M141 69.6h2.4v9h-1.2M141.6 66.6v5.4h-.6M144.6 66.6v6.6M144.6 76.8v4.2M149.4 78.6v6.5h6M149.4 66.6v4.1M149.4 74.4v.6h7.2v4.8M154.1 62.4v2.4M154.1 66v11.3M158.4 66.6v9.6M158.4 79.8v2.4M167.9 73.2h3.1"/>
<path d="M167.9 77.9v4.3h2.5v-5.4h7.2v4.2M167.9 66.6v1.2M167.9 71.4v3M171 70.7v-2.9h11.3v5.4M173.4 75.6h-3.6v11.4M173.4 66v2.4M175.1 63.5v1.3M177.6 61.2h1.2M178.2 72h7.2v1.2M179.4 66v9.6h-4.3v3M182.3 76.8v6.6h3.1M185.4 76.8v4.2h-3.7"/>
<path d="M197.3 62.4v.5h1.3M197.3 63.5h3.1M203.9 66.6h-75.5v7.2M9 88.2h68.4v10.7M10.9 94.2h2.9M10.9 89.4h2.9M12.7 90h1.1v.6M13.8 93v.6h-1.1M17.4 95.4v13.8M22.2 91.7v2.5M25.9 91.7h2.9v6.6M29.4 94.2h-3.5v4.1"/>
<path d="M32.5 91.7h1.2M33.1 91.7v2.5M33.7 94.2v4.1h7.2v-5.3h2.3v4.2M36 96.6v2.9h-4.2v9.7M36 88.2v1.2M37.8 84.5v2.5M41.4 88.2v11.3h-3.6M43.2 85.1v1.3M46.9 93h1.1M51.6 93h3.1M52.2 90h-4.7v3M52.8 93v2.4"/>
<path d="M52.8 98.9v9.7M54.7 95.4v4.8h7.1v.6M55.8 90h6v6.6M57 88.2v2.4M57 97.7v11.5M61.8 82.2v4.2M61.8 94.2h.6M66 94.2h4.2M66.6 94.2v4.1M70.2 96.6h-1.2v8.3h2.4M71.4 80.4h-.6v6M72.6 98.9h-2.4v10.3h-63.6"/>
<path d="M72.6 88.2v3.5M77.4 95.4h1.8M78 95.4v2.3h-1.8v1.8h-6.6v4.3h1.8M83.4 81.6h3M83.4 80.4h4.8v24.5h10.2v-2.3M83.4 82.8h3.6M84.6 95.4v2.3M124.8 92.3h3M125.3 93.6h2.5M127.2 99.5v2.5M127.8 94.8h-4.2v11.9h-20.4v-4.1M133.8 98.3v10.9h69.5"/>
<path d="M139.7 93.6h1.9v4.1h-6.6v1.8h-1.8v2.5M139.7 92.3h2.5v8.5h-1.2M139.7 83.4v3.6M140.4 88.8v6h-.7M141 81h4.2M144.6 88.8v6.6M144.6 98.9v4.3M148.8 81h.6M149.4 88.8v4.2M149.4 96.6v.6h7.2v4.8M154.1 84.5v2.5M154.1 88.2v11.3"/>
<path d="M156.6 82.2h3M158.4 88.8v9.5M163.2 82.2h1.2M163.8 82.2v2.9h-4.8M167.9 95.4h3.1M167.9 88.8v1.2M167.9 93.6v3M171 93v-3h11.3v5.4M173.4 97.7h-3.6v11.5M173.4 88.2v2.4M175.1 85.8v1.2M177.6 83.4h1.2"/>
<path d="M178.2 94.2h7.2v1.2M178.2 81v2.4M179.4 88.2v9.5h-4.3v3.1M182.3 98.9v6.6h3.1M185.4 98.9v4.3h-3.7M188.9 81v2.4M193.8 88.2v13.8M197.3 84.5v.6h1.3M197.3 81h3.1M197.3 85.8h3.1M198.6 81.6h-1.3v.6M203.9 88.8h-76.7v7.2"/>
<path d="M205.2 88.2h-64.2v10.1h-2.4M9 110.4h68.4v10.7M10.9 116.4h2.9M10.9 111.5h2.9M12.7 112.1h1.1v.6M13.8 115.2v.6h-1.1M17.4 117.6v13.8h52.8v-10.3h2.4M22.2 113.9v2.5M25.9 113.9h2.9v6.6M25.9 102v1.2h7.2M28.8 102v5.4h11.5v-3M29.4 116.4h-3.5v4.1"/>
<path d="M32.5 113.9h1.2M33.1 113.9v2.5M33.7 116.4v4.1h7.2v-5.3h2.3v4.1M36 118.7v3.1h-4.2v9.6M36 110.4v1.1M37.8 106.7v2.5M40.3 102h2.9M41.4 110.4v11.4h-3.6M43.2 100.8v3M43.2 107.4v1.2M46.9 115.2h1.1M51.6 115.2h3.1"/>
<path d="M52.2 112.1h-4.7v3.1M52.8 115.2v2.4M54.7 117.6v4.8h7.1v.6M55.8 112.1h6v6.6M57 110.4v2.3M57 119.9v11.5M61.8 104.4v4.2M61.8 116.4h.6M66 116.4h4.2M66.6 102v6.6M66.6 116.4v4.1M70.2 118.7h-1.2v8.4h2.4"/>
<path d="M71.4 102.6h-.6v6M72.6 110.4v3.5M77.4 117.6h1.8M78 117.6v2.3h-1.8v1.9h-6.6v4.1h1.8M83.4 103.8h3M83.4 104.9h3.6M83.4 102.6h4.2v2.9h12v-2.9M84 117.6v2.3M84.6 101.4v7.2h-76.8M86.4 108h38.9M87 108.6h37.8M100.8 102.6v3.5h-13.2v18.7h-4.2"/>
<path d="M102 102.6v4.8h22.2v9.6h4.2M106.8 102.6v6M117.6 102.6v8.4M118.8 102.6v8.4M132 102h1.8M138.6 105.5v3.7M140.4 115.8h1.8v4.1h-6.6v1.9h-1.8v2.4M140.4 114.6h2.4v8.4h-1.2M141 103.2h4.2M141 111v6h-.6M145.2 111v6.6M148.8 103.2h.6"/>
<path d="M149.4 100.8v6.6h6M150 111v4.2M150 118.7v.6h7.2v4.9M154.1 106.7v2.5M154.8 110.4v11.4M156.6 104.4h3M158.4 102v2.4M159 111v9.5M163.2 104.4h1.2M163.8 104.4v3h-4.8M167.9 100.2v4.2h2.5v-5.5h7.2v4.3M168.5 117.6h3.1"/>
<path d="M168.5 111v1.1M168.5 115.8v2.9M171.6 115.2v-3.1h11.3v5.5M173.9 119.9h-3.5v11.5M173.9 110.4v2.3M175.1 108v1.2M177.6 105.5h1.2M178.2 103.2v2.3M178.8 116.4h7.2v1.2M180 110.4v9.5h-4.3v3.1M188.9 103.2v2.3M194.4 110.4v13.8"/>
<path d="M197.3 106.7v.7h1.3M197.3 103.2h3.1M197.3 108h3.1M198.6 103.8h-1.3v.6M203.9 111h-76.1v7.2M205.2 110.4h-63.6v10.1h-2.5M9 132.5h68.4v10.9M10.9 138.6h2.9M10.9 133.7h2.9M12.7 134.3h1.1v.6M13.8 137.4v.6h-1.1M17.4 139.7v13.8"/>
<path d="M22.2 136.2v2.4M25.9 136.2h2.9v6.5M25.9 124.2v1.1h7.2M28.8 124.2v5.4h11.5v-3.1M29.4 138.6h-3.5v4.1M32.5 136.2h1.2M33.1 136.2v2.4M33.7 138.6v4.1h7.2v-5.3h2.3v4.1M36 132.5v1.2M37.8 129v2.4M40.3 124.2h2.9M41.4 132.5v11.5h-3.6"/>
<path d="M43.2 123v2.9M43.2 129.6v1.2M46.9 137.4h1.1M51.6 137.4h3.1M52.2 134.3h-4.7v3.1M52.8 121.1v9.7M52.8 137.4v2.3M54.7 139.7v4.9h7.1v.6M55.8 134.3h6v6.6M57 132.5v2.4M61.8 126.5v4.3M61.8 138.6h.6"/>
<path d="M66 138.6h4.2M66.6 124.2v6.6M66.6 138.6v4.1M71.4 124.8h-.6v6M72.6 132.5v3.7M77.4 139.7h1.8M78 139.7v2.4h-1.8v1.9h-6.6v4.1h1.8M82.8 139.7h2.4v43.2h15.6v4.3M84 123.6v7.2h-76.2M84 139.7v2.4M96.6 132v12.6M97.8 132v12.6"/>
<path d="M99 132v12.6M100.2 132v12.6M101.4 132v12.6M102.6 132v12.6M105 132v12.6M106.2 132v12.6M107.4 132v12.6M109.8 132v12.6M111 132v12.6M112.2 132v12.6M114.6 132v12.6M115.8 132v12.6"/>
<path d="M117 132v12.6M127.8 121.8v2.4M128.4 139.1h-6.6v75.6h-13.8v-1.2M128.4 136.8h-3.6v88.7h3.6M128.4 138h-3.1v88.7h3.1M132.5 124.2h1.9M134.4 120.5v10.9h68.9M139.1 127.7v3.7M140.4 138h1.8v4.1h-6.6v1.9h-1.8v2.3M140.4 136.8h2.4v8.4h-1.2M141 133.1v6h-.6M141.6 125.3h4.2"/>
<path d="M144 133.1v6.6M145.2 121.1v4.2M148.8 133.1v4.3M149.4 125.3h.6M150 123v6.6h6M153.5 132.5v11.5M154.8 129v2.4M157.2 126.5h2.9M157.8 133.1v9.6M159 124.2v2.3M163.8 126.5h1.2M164.4 126.5v3.1h-4.8"/>
<path d="M167.3 133.1v1.2M167.3 138v2.9M167.3 139.7h3.1M168.5 122.4v4.1h2.5v-5.4h7.2v4.2M170.4 137.4v-3.1h11.3v5.4M172.8 132.5v2.4M175.7 130.2v1.2M177.6 138.6h7.2v1.1M178.2 127.7h1.2M178.8 132.5v9.6h-4.3v3.1M178.8 125.3v2.4M182.9 121.1v6.6h3.1"/>
<path d="M186 121.1v4.2h-3.7M189.5 125.3v2.4M193.2 132.5v13.8M198 125.3h3M198 129v.6h1.2M198 130.2h3M199.2 125.9h-1.2v.6M203.9 133.1h-76.1v7.2M205.2 132.5h-63.6v10.2h-2.5M9 154.7h67.8v10.9M10.9 155.9h2.9M12.7 156.5h1.1v.6"/>
<path d="M13.8 159.6v.5h-1.1M22.2 158.4v2.3M25.9 158.4h2.9v6.6M25.9 146.3v1.2h7.2M28.8 146.3v5.5h11.5v-3.1M32.5 158.4h1.2M33.1 158.4v2.3M36 140.9v3.1h-4.2v9.5M36 154.7v1.2M37.8 151.2v2.3M40.3 146.3h2.9M41.4 154.7v11.5h-3.6"/>
<path d="M43.2 145.2v2.9M43.2 151.8v1.2M46.9 159.6h1.1M51.6 159.6h3.1M52.2 156.5h-4.7v3.1M52.8 143.4v9.6M52.8 159.6v2.3M55.8 156.5h6v6.6M57 142.1v11.4M57 154.7v2.4M61.8 148.7v4.3M66.6 146.3v6.7"/>
<path d="M70.2 140.9h-1.2v8.4h2.4M71.4 146.9h-.6v6.1M72 154.7v3.7M72.6 143.4h-2.4v10.1h-63.6M83.4 148.1h3v88.8h-3M83.4 146.9h5.4v65.4h.6v2.4h6.6v-1.2M83.4 149.3h3.6v88.8h-3.6M84 145.8v7.2h-76.2M93.6 142.1h19.8v2.5M95.4 142.1v2.5M95.4 150.6v12.5M96.6 150.6v12.5"/>
<path d="M97.8 150.6v12.5M99 150.6v2.4M100.2 150.6v12.5M101.4 150.6v2.4M102.6 150.6v12.5M103.8 142.1v2.5M103.8 150.6v12.5M105 150.6v12.5M106.2 150.6v12.5M107.4 150.6v2.4M108.6 150.6v12.5M109.8 150.6v12.5"/>
<path d="M111 150.6v2.4M112.2 150.6v12.5M113.4 150.6v12.5h4.2v24.1M114.6 150.6v11.9h4.2v24.7M115.8 150.6v2.4h-22.2M117 150.6v3.5h2.4M118.2 141.5v3.1M118.2 150.6v3.5M119.4 141.5h-10.8v3.1M124.8 159h3.6M127.8 144v2.3M129 146.3h-2.4v36.6h-24.6v4.3"/>
<path d="M132.5 146.3h1.9M134.4 142.7v10.8h68.9M139.1 149.9v3.6M140.4 159h2.4v8.3h-1.2M140.4 147.5h4.2M141 155.3v6h-.6M144 143.4v4.1M144.6 155.3v6.6M148.2 147.5h.6M148.8 140.9v.6h7.2v4.8M148.8 145.2v6.6h6M149.4 155.3v4.3"/>
<path d="M153.5 151.2v2.3M154.1 154.7v11.5M156 148.7h3M157.8 146.3v2.4M158.4 155.3v9.7M162.6 148.7h1.2M163.2 148.7v3.1h-4.8M167.3 144.6v4.1h2.5v-5.3h7.2v4.1M167.9 156.5v-1.2h-40.1v7.2M171 159.6v-3.1h11.3v5.4M172.8 142.1h-3.6v11.4M173.4 154.7v2.4"/>
<path d="M174.5 152.4v1.1M177 149.9h1.2M177.6 147.5v2.4M179.4 154.7v9.6h-4.3v3M181.7 143.4v6.5h3.1M184.8 143.4v4.1h-3.7M188.3 147.5v2.4M193.8 154.7v13.8M196.7 151.2v.6h1.3M196.7 147.5h3.1M196.7 152.4h3.1M198 148.1h-1.3v.6"/>
<path d="M205.2 154.7h-63.6v10.3h-2.5M6.6 175.7h63.6M9 176.9h68.4v10.8M10.9 160.7h2.9M10.9 178.1h2.9M12.7 178.7h1.1v.7M17.4 161.9v13.8M25.9 168.5v1.2h7.2M28.8 168.5v5.4h11.5v-3M29.4 160.7h-3.5v4.3M33.7 160.7v4.3h7.2v-5.4h2.3v4.1M36 163.1v3.1h-4.2v9.5"/>
<path d="M36 176.9v1.2M37.8 173.4v2.3M40.3 168.5h2.9M41.4 176.9v11.4h-3.6M43.2 167.3v3M43.2 173.9v1.2M52.2 178.7h-4.7v3M52.8 165.6v9.5M54.7 161.9v4.9h7.1v.5M55.8 178.7h6v6.6M57 164.3v11.4M57 176.9v2.5"/>
<path d="M61.8 170.9v4.2M61.8 160.7h.6M66 160.7h4.2M66.6 160.7v4.3M66.6 168.5v6.6M69.6 163.1h-1.1v8.4h2.3M70.8 169.1h-.6v6M72 165.6h-2.4v10.1M72.6 176.9v3.7M76.8 161.9h1.8M77.4 161.9v2.4h-1.8v1.9h-6.6v4.1h1.8M82.2 161.9h2.4v21.6h15v3.7"/>
<path d="M82.8 169.1h4.8v43.8h1.2v2.4h8.4v-1.8M82.8 170.3h3.6M82.8 171.5h4.2M83.4 161.9v2.4M83.4 167.9v7.2h-74.4M125.3 160.1h3.1M127.8 166.2v2.3M128.4 161.3h-6v54h-16.8v-1.8M129 168.5h-1.8v15h-24v3.7M132.5 168.5h1.9M134.4 165v10.7h68.9M135 176.9v.6"/>
<path d="M139.1 172.2v3.5M140.4 160.1h1.8v4.2h-6.6v1.9h-1.8v2.3M141 169.7h4.2M141.6 177.5v5.4h-.6M144.6 165.6v4.1M144.6 177.5v6.6M148.8 169.7h.6M149.4 163.1v.6h7.2v4.8M149.4 167.3v6.6h6M149.4 177.5v4.2M154.1 173.4v2.3M154.1 176.9v11.4"/>
<path d="M156.6 170.9h3M158.4 168.5v2.4M158.4 177.5v9.7M163.2 170.9h1.2M163.8 170.9v3h-4.8M167.9 166.8v4.1h2.5v-5.3h7.2v4.1M167.9 160.1v3M167.9 177.5v1.2M167.9 161.9h3.1M173.4 176.9v2.5M173.4 164.3h-3.6v11.4M175.1 174.5v1.2"/>
<path d="M177.6 172.2h1.2M178.2 160.7h7.2v1.2M178.2 169.7v2.5M179.4 176.9v9.7h-4.3v2.9M182.3 165.6v6.6h3.1M185.4 165.6v4.1h-3.7M188.9 169.7v2.5M197.3 173.4v.5h1.3M197.3 169.7h3.1M197.3 174.5h3.1M198.6 170.3h-1.3v.6M203.9 177.5h-75.5v7.2"/>
<path d="M9 199.1h68.4v10.8M10.9 182.9h2.9M13.8 181.7v.6h-1.1M17.4 184.1v13.8M22.2 180.6v2.3M25.9 180.6h2.9v6.6M25.9 190.7v1.2h7.2M28.8 190.7v5.4h11.5v-3M29.4 182.9h-3.5v4.3M32.5 180.6h1.2M33.1 180.6v2.3M33.7 182.9v4.3h7.2v-5.5h2.3v4.2"/>
<path d="M36 185.3v3h-4.2v9.6M36 199.1v1.2M37.8 195.5v2.4M40.3 190.7h2.9M41.4 199.1v11.4h-3.6M43.2 189.5v3M43.2 196.1v1.2M46.9 181.7h1.1M51.6 181.7h3.1M52.8 181.7v2.4M52.8 187.7v9.6M54.7 184.1v4.8h7.1v.6"/>
<path d="M57 186.6v11.3M57 199.1v2.4M61.8 193.1v4.2M61.8 182.9h.6M66 182.9h4.2M66.6 182.9v4.3M66.6 190.7v6.6M70.2 185.3h-1.2v8.5h2.4M71.4 191.3h-.6v6M72.6 187.7h-2.4v10.2h-63.6M72.6 199.1v3.6M77.4 184.1h1.8"/>
<path d="M78 184.1v2.5h-1.8v1.7h-6.6v4.2h1.8M82.8 184.1h15.6v3.1M83.4 191.3h4.8v24.6h10.2v-2.4M83.4 192.5h3M83.4 193.8h3.6M84 184.1v2.5M84 190.1v7.2h-75M86.4 182.3h21.6M96 187.2v-1.9h-10.2v43.2h-3M97.2 187.2v-2.5h-12v21.6h-2.4M104.4 187.2v-3.1h22.8v6.6h2.4M105.6 187.2v-2.5h21v28.2h1.8"/>
<path d="M106.8 187.2v-1.9h19.2v49.8h3M124.8 180.6h4.2M128.4 188.3v2.4M129 181.7h-21v5.5M129 182.9v-.6h-6v33.6h-18.6v-2.4M133.2 190.7h1.8M135 186.6v11.3h68.3M139.7 187.2h2.5v-10.3h51.6v13.8M139.7 194.4v3.5M140.4 199.7v6h-.7M141 181.7h1.8v4.9h-6.6v1.7h-1.8v2.4M141 180.6h2.4v8.9h-1.2"/>
<path d="M141 191.9h4.2M144.6 187.7v4.2M144.6 199.7v6.6M148.8 191.9h.6M149.4 185.3v.6h7.2v4.8M149.4 189.5v6.6h6M149.4 199.7v4.2M154.1 195.5v2.4M154.1 199.1v11.4M156.6 193.1h3M158.4 190.7v2.4M158.4 199.7v9.6"/>
<path d="M163.2 193.1h1.2M163.8 193.1v3h-4.8M167.9 188.9v4.2h2.5v-5.4h7.2v4.2M167.9 182.3v3M167.9 199.7v1.3M167.9 184.1h3.1M171 181.7v-3h11.3v5.4M173.4 199.1v2.4M173.4 186.6h-3.6v11.3M175.1 196.7v1.2M177.6 194.4h1.2M178.2 182.9h7.2v1.2"/>
<path d="M178.2 191.9v2.5M179.4 199.1v9.6h-4.3v3M182.3 187.7v6.7h3.1M185.4 187.7v4.2h-3.7M188.9 191.9v2.5M193.8 199.1v13.8M197.3 195.5v.6h1.3M197.3 191.9h3.1M197.3 196.7h3.1M198.6 192.5h-1.3v.6M203.9 199.7h-76.7v7.2M205.2 199.1h-64.2v10.2h-2.4"/>
<path d="M10.9 205.1h2.9M10.9 200.3h2.9M12.7 201h1.1v.5M13.8 203.9v.6h-1.1M17.4 206.3v13.8M22.2 202.7v2.4M25.9 202.7h2.9v6.6M25.9 212.9v1.2h7.2M28.8 212.9v5.4h11.5v-3M29.4 205.1h-3.5v4.2M32.5 202.7h1.2M33.1 202.7v2.4"/>
<path d="M33.7 205.1v4.2h7.2v-5.4h2.3v4.3M36 207.5v3h-4.2v9.6M37.8 217.7v2.4M40.3 212.9h2.9M43.2 211.7v3M43.2 218.3v1.2M46.9 203.9h1.1M51.6 203.9h3.1M52.2 201h-4.7v2.9M52.8 203.9v2.4M52.8 209.9v9.6M54.7 206.3v4.8h7.1v.6"/>
<path d="M55.8 201h6v6.5M57 208.7v11.4M61.8 215.3v4.2M61.8 205.1h.6M66 205.1h4.2M66.6 205.1v4.2M66.6 212.9v6.6M70.2 207.5h-1.2v8.4h2.4M71.4 213.5h-.6v6M72.6 209.9h-2.4v10.2h-63.6v-199.1h105.6v.6h93v223.1M77.4 206.3h1.8M78 206.3v2.4h-1.8v1.8h-6.6v4.2h1.8"/>
<path d="M83.4 213.5h4.2v3h12v-3M83.4 214.7h3M83.4 215.9h3.6M84.6 206.3v2.4M84.6 212.3v7.2h-76.8M86.4 218.9h38.9M87 219.5h37.8M100.8 213.5v3.6h-13.2v18.6h-4.2M102 213.5v3.6h22.2v10.8h4.2M106.8 213.5v6M124.8 203.3h3M125.3 204.5h2.5"/>
<path d="M127.2 210.5v2.4M127.8 205.7h-4.2v10.8h-20.4v-3M132 212.9h1.8M133.8 209.3v10.8h69.5M138.6 216.5v3.6M139.7 204.5h1.9v4.2h-6.6v1.8h-1.8v2.4M139.7 203.3h2.5v8.4h-1.2M141 214.1h4.2M144.6 209.9v4.2M148.8 214.1h.6M149.4 207.5v.7h7.2v4.7M149.4 211.7v6.6h6"/>
<path d="M154.1 217.7v2.4M156.6 215.3h3M158.4 212.9v2.4M163.2 215.3h1.2M163.8 215.3v3h-4.8M167.9 211.1v4.2h2.5v-5.4h7.2v4.2M167.9 204.5v3M167.9 206.3h3.1M171 203.9v-2.9h11.3v5.3M173.4 208.7h-3.6v11.4M175.1 218.9v1.2M177.6 216.5h1.2"/>
<path d="M178.2 205.1h7.2v1.2M178.2 214.1v2.4M182.3 209.9v6.6h3.1M185.4 209.9v4.2h-3.7M188.9 214.1v2.4M197.3 217.7v.6h1.3M197.3 218.9h3.1M197.3 214.1h3.1M198.6 214.7h-1.3v.6M10.9 227.3h2.9M10.9 222.5h2.9M12.7 223.1h1.1v.6"/>
<path d="M13.8 226.1v.6h-1.1M17.4 228.5v13.8h52.8v-10.2h2.4M22.2 224.9v2.4M25.9 224.9h2.9v6.6M25.9 235.1v1.2h7.2M28.8 235.1v5.4h11.5v-3M29.4 227.3h-3.5v4.2M32.5 224.9h1.2M33.1 224.9v2.4M33.7 227.3v4.2h7.2v-5.4h2.3v4.2M36 229.7v3h-4.2v9.6M36 221.3v1.2"/>
<path d="M37.8 239.9v2.4M40.3 235.1h2.9M41.4 221.3v11.4h-3.6M43.2 233.9v3M46.9 226.1h1.1M51.6 226.1h3.1M52.2 223.1h-4.7v3M52.8 226.1v2.4M52.8 232.1v9.6M54.7 228.5v4.8h7.1v.6M55.8 223.1h6v6.6M57 221.3v2.4"/>
<path d="M57 230.9v11.4M61.8 237.5v4.2M61.8 227.3h.6M66 227.3h4.2M66.6 227.3v4.2M66.6 235.1v6.6M70.2 229.7h-1.2v8.4h2.4M71.4 235.7h-.6v6M72.6 221.3v3.6M77.4 232.1v-10.8h-68.4v-199.7h85.8v-1.2h108.5v221.9h-90.5M77.4 228.5h1.8M78 228.5v2.4h-1.8v1.8h-6.6v4.2h1.8"/>
<path d="M84 228.5v2.4M84 234.5v7.2M127.8 221.9v7.2M127.8 232.7v2.4M132.5 235.1h1.9M134.4 231.5v10.8M139.1 238.7v3.6M140.4 226.7h1.8v4.2h-6.6v1.8h-1.8v2.4M140.4 225.5h2.4v8.4h-1.2M141 221.9v6h-.6M141.6 236.3h4.2M145.2 221.9v6.6"/>
<path d="M145.2 232.1v4.2M149.4 236.3h.6M150 221.9v4.2M150 229.7v.6h7.2v4.8M150 233.9v6.6h6M154.8 221.3v11.4M154.8 239.9v2.4M157.2 237.5h2.9M159 221.9v9.6M159 235.1v2.4M163.8 237.5h1.2M164.4 237.5v3h-4.8"/>
<path d="M168.5 233.3v4.2h2.5v-5.4h7.2v4.2M168.5 221.9v1.2M168.5 226.7v3M168.5 228.5h3.1M171.6 226.1v-3h11.3v5.4M173.9 230.9h-3.5v11.4M173.9 221.3v2.4M178.2 238.7h1.2M178.8 236.3v2.4M178.8 227.3h7.2v1.2M180 221.3v9.6h-4.3v3M182.9 232.1v6.6h3.1"/>
<path d="M186 232.1v4.2h-3.7M189.5 236.3v2.4M194.4 221.3v13.8M198 239.9v.6h1.2M198 236.3h3M199.2 236.9h-1.2v.6M205.2 221.3h-63.6v10.2h-2.5M43.2 240.5v1.2M112.8 243.5h91.7M175.7 241.1v1.2M198 241.1h3"/>
</g>
<g fill="none" stroke="#0000ca" stroke-width=".2">
<path d="M96 110.4h25.8v3.5h-25.8zM97.1 111.5h.3M97.1 112.4h.3M97.2 111.5v.6M97.2 112.4v.7M97.6 111.9l.3-.1-.1-.2-.2 .1v.3l.2 .1M97.6 112.8h.3l-.1-.2-.2 .1v.3h.2M98.1 111.9l.3-.1-.1-.2-.2 .1v.3l.2 .1M98.1 112.8h.3l-.1-.2-.2 .1 .1 .4 .1-.1M98.7 111.7h.2v.4M98.7 113.1v-.5l.2 .1v.4M98.7 111.6v.5"/>
<path d="M99.4 111.7h-.2l.2 .2v.2h-.2M99.4 112.6h-.2v.2l.2 .2h-.2M99.6 111.6l.2 .5M99.6 112.6l.2 .5M99.9 111.6l-.3 .6M99.9 112.6l-.3 .6M100.5 111.5h.4M100.6 112.7h.3l.1-.1-.4-.2v.7M100.7 111.5v.6M100.7 112.7l.3 .4M101 111.5l.4 .6M101.1 112.4l.5 .7"/>
<path d="M101.4 111.5l-.4 .6M101.6 112.4l-.5 .7M101.6 111.5h.3l.1 .1-.4 .5h.4M101.7 112.5h.4l-.4 .6h.4M102.8 111.4l-.1 .2v.5l.1 .2M103 112.3l-.2 .2v.6l.2 .1M103.1 111.8h.2l.1-.3h-.3v.6M103.2 112.7h.3v-.2l-.3-.1v.7M103.7 111.5h.1M103.7 111.6v.5M103.8 112.4v.1M103.8 112.6v.5"/>
<path d="M103.9 111.7h.3v.4M103.9 111.6v.5M104.1 113.1v-.5h.3v.5M104.9 111.5h.4l-.3 .2h.2l.1 .3h-.4M105 112.4h.4l-.2 .2h.2v.4h-.4M105.5 111.5h.3l-.1 .6h-.2v-.3zM105.6 112.6l.2-.2v.7M105.6 113.1h.4M106 111.4a.72 .72 0 0 1 0 .9M106.1 112.3l.1 .1a.52 .52 0 0 1-.1 .8M107 111.8h.4M107.1 112.8h.5"/>
<path d="M107.3 111.7v.3M107.4 112.6l.2 .2-.2 .1M108.2 111.8h.1l.2-.3h-.3v.6M108.2 112.4h.3M108.2 111.8l.3 .3M108.3 112.4v.7M108.7 111.5l.4 .6M108.7 112.4l.4 .7M109.1 111.5l-.4 .6M109.1 112.4l-.4 .7M109.8 111.7h.2v.4h-.2zM109.8 112.6h.2l-.1 .5-.1-.1z"/>
<path d="M110.2 111.6h.2M110.2 112.6h.2M110.4 111.5h-.1v.6M110.4 112.4l-.1 .1v.6M111.1 111.5l.1 .6 .3-.1v-.5M111.1 112.4l.1 .7 .3-.1v-.6M112.1 111.5h-.4v.2l.4 .1-.1 .3h-.3M112.1 112.5h-.4v.1l.4 .2-.1 .3-.3-.1M112.3 111.7h.3v-.2h-.3v.6h.3v-.3l-.1-.1M112.3 112.7l.3-.1-.1-.2h-.2v.7h.3v-.3l-.1-.1M112.9 111.8h.4M112.9 112.8h.4"/>
<path d="M113.6 111.6h.2M113.6 112.6h.2M113.7 111.5v.6h.1M113.7 112.4v.6l.1 .1M114 111.7h.3v.4h-.3zM114 112.6h.3l-.1 .5-.2-.1zM114.5 111.8h.5M114.5 112.8h.5M115.6 111.5h-.3v.2l.3 .2-.1 .2h-.2M115.6 112.5h-.3v.1l.3 .3-.2 .2-.1-.1M115.8 111.9l.3-.1-.1-.2-.2 .1v.3l.3 .1M115.8 112.8h.3v-.2l-.3 .1 .1 .4 .2-.1"/>
<path d="M116.4 111.6v.5M116.4 112.6v.5M116.5 111.6l-.1 .2M116.5 112.6l-.1 .1M116.7 111.5h.1M116.7 112.4v.1M116.7 111.6v.5M116.7 112.6v.5M117.1 111.7h.2v.4h-.2v-.3h.2M117.1 112.6l.2 .1v.4M117.3 112.8l-.3 .1 .1 .2 .2-.1M117.6 111.5v.6"/>
<path d="M117.6 112.4v.7M118.3 111.7h.3v.4h-.3l.1-.3h.2M118.3 112.6h.3v.5M118.6 112.8h-.3l.1 .3 .2-.1M119.2 111.5v.6h-.3l-.1-.3 .2-.2 .2 .1M119.2 112.6l-.4 .1 .2 .4 .2-.1M119.2 112.4v.7M119.4 111.7h.3v.4h-.3v-.2l.3-.1M119.4 112.6h.3v.5M119.7 112.8h-.3l.1 .3 .2-.1M119.9 111.7l.2-.1 .2 .2-.1 .3h-.3M119.9 113l.2 .1 .2-.4-.4-.1v.6"/>
<path d="M119.9 111.6v.6M120.4 111.6h.2M120.4 112.6h.2M120.5 111.5l.1 .6M120.5 112.4l.1 .7M120.9 111.9l.2-.1-.1-.2-.1 .1v.4h.2M120.9 112.8h.2v-.2h-.2v.4h.2M121.4 111.6v.5M121.4 112.6v.5M121.5 111.6l-.1 .2M121.5 112.6l-.1 .1M106.3 239.6h.3v-.3h-.3v.6"/>
<path d="M106.9 239.6h.3v.3h-.2zM107.4 239.6l.2 .3 .1-.3v.3l.2-.3M108.1 239.7l.2-.1h-.2v.3h.2M108.6 239.6v.3M108.8 239.6h-.2M109.7 239.6h-.3v.1h.3v.2h-.3M109.9 239.6v.3h.3v-.3M110.4 239.9h.3l.1-.3h-.4v.6M111 239.9h.3v-.3h-.3v.6M111.5 239.3l.1 .6M111.8 239.6l.2 .3M112.1 239.6l-.3 .6"/>
<path d="M106.2 240.5h9v4.2h-9z"/>
</g>
<g fill="none" stroke="#0000ca" stroke-width=".34">
<path d="M175.5 254.4l.6-1.9 .7 1.9M175.7 253.8h.9M177.4 253.2l.1 1.1 .4 .1 .3-.2M178.2 253.2v1.2M179.9 253.2v1.5l-.3 .3-.5-.1M179.9 253.2h-.6l-.3 .3v.5l.3 .4h.4l.2-.1M180.8 253.2v.9l.3 .3h.3l.2-.2M181.6 253.2v1.2M183.1 253.2h-.4l-.2 .2v.3l.6 .1v.5l-.1 .1h-.4l-.1-.1M183.8 253.2h.7M184.1 252.5v1.6l.2 .3h.2M187.6 252.5v1.9l-1.1-1.9v1.9"/>
<path d="M189.3 253.2v1.5l-.3 .3-.4-.1M189.3 253.2h-.5l-.3 .3v.5l.3 .4h.3l.2-.1M190.2 253.2l.1 1.1 .5 .1 .3-.2M191.1 253.2v1.2M191.8 253.2l.4 1.2M192.7 253.2l-.7 1.6-.2 .2M193.3 253.7l.9-.1-.1-.4h-.6l-.2 .2v.7l.2 .3h.5l.1-.1M195 253.3l.2-.1h.5l.1 1.2M195 253.2v1.2"/>
</g>
<g fill="none" stroke="#00008a" stroke-width=".2">
<path d="M10.5 22.5l.6 .6M10.5 27.3l.6 .6M11.1 22.5l-.6 .6M11.1 27.3l-.6 .6M18.3 28.5l.6 .6M18.9 28.5l-.6 .6M35.2 39.9l.5 .6M35.7 39.9l-.5 .6M36.4 39.9l.5 .6M36.9 39.9l-.5 .6M37 29.7l.5 .6M37.5 29.7l-.5 .6"/>
<path d="M38.1 29.7l.6 .6M38.7 29.7l-.6 .6M58 30.9l.5 .6M58.5 30.9l-.5 .6M59.1 30.9l.6 .6M59.7 30.9l-.6 .6M73.5 32.1l.6 .5M74.1 32.1l-.6 .5M74.7 32.1l.6 .5M75.3 32.1l-.6 .5M136.5 31.5l.5 .5M137 31.5l-.5 .5"/>
<path d="M137.7 31.5l.6 .5M138.3 31.5l-.6 .5M150.9 32.7l.5 .6M151.4 32.7l-.5 .6M152.1 32.7l.6 .6M152.7 32.7l-.6 .6M171.9 33.9l.5 .6M172.4 33.9l-.5 .6M173.1 33.9l.5 .6M173.6 33.9l-.5 .6M173.7 23.7l.6 .6M174.3 23.7l-.6 .6"/>
<path d="M174.9 23.7l.6 .6M175.5 23.7l-.6 .6M191.6 35.1l.6 .6M192.2 35.1l-.6 .6M199.4 36.3l.6 .6M200 36.3l-.6 .6M10.5 49.5l.6 .6M10.5 44.7l.6 .6M11.1 49.5l-.6 .6M11.1 44.7l-.6 .6M18.3 50.7l.6 .6M18.9 50.7l-.6 .6"/>
<path d="M37 51.9l.5 .6M37.5 51.9l-.5 .6M38.1 51.9l.6 .6M38.7 51.9l-.6 .6M58 53.1l.5 .5M58.5 53.1l-.5 .5M59.1 53.1l.6 .5M59.7 53.1l-.6 .5M72.9 54.3l.6 .6M73.5 54.3l-.6 .6M74.1 54.3l.6 .6M74.7 54.3l-.6 .6"/>
<path d="M136.5 53.7l.5 .5M137 53.7l-.5 .5M137.7 53.7l.6 .5M138.3 53.7l-.6 .5M151.5 54.9l.5 .6M152 54.9l-.5 .6M152.7 54.9l.6 .6M153.3 54.9l-.6 .6M172.5 56.1l.5 .6M173 56.1l-.5 .6M173.7 56.1l.6 .6M174.3 56.1l-.6 .6"/>
<path d="M174.3 45.9l.6 .5M174.9 45.9l-.6 .5M175.5 45.9l.6 .5M176.1 45.9l-.6 .5M192.2 57.3l.6 .6M192.8 57.3l-.6 .6M199.4 41.1l.6 .6M200 41.1l-.6 .6M200 58.5l.6 .6M200.6 58.5l-.6 .6M10.5 71.7l.6 .6M10.5 66.9l.6 .5"/>
<path d="M11.1 71.7l-.6 .6M11.1 66.9l-.6 .5M18.3 72.9l.6 .5M18.9 72.9l-.6 .5M35.2 62.1l.5 .6M35.7 62.1l-.5 .6M36.4 62.1l.5 .6M36.9 62.1l-.5 .6M37 74.1l.5 .5M37.5 74.1l-.5 .5M38.1 74.1l.6 .5M38.7 74.1l-.6 .5"/>
<path d="M58 75.3l.5 .5M58.5 75.3l-.5 .5M59.1 75.3l.6 .5M59.7 75.3l-.6 .5M73.5 76.5l.6 .6M74.1 76.5l-.6 .6M74.7 76.5l.6 .6M75.3 76.5l-.6 .6M92.1 75.9l.6 .6M92.7 75.9l-.6 .6M93.3 75.9l.6 .6M93.9 75.9l-.6 .6"/>
<path d="M94.5 75.9l.6 .6M95.1 75.9l-.6 .6M108.9 75.9l.6 .6M109.5 75.9l-.6 .6M110.1 75.9l.6 .6M110.7 75.9l-.6 .6M111.3 75.9l.6 .6M111.9 75.9l-.6 .6M112.5 75.9l.6 .6M113.1 75.9l-.6 .6M113.7 75.9l.6 .6M114.3 75.9l-.6 .6"/>
<path d="M114.9 75.9l.5 .6M115.4 75.9l-.5 .6M116.1 75.9l.6 .6M116.7 75.9l-.6 .6M117.3 75.9l.6 .6M117.9 75.9l-.6 .6M118.5 75.9l.6 .6M119.1 75.9l-.6 .6M119.7 75.9l.6 .6M120.3 75.9l-.6 .6M137.1 75.9l.5 .6M137.6 75.9l-.5 .6"/>
<path d="M138.3 75.9l.6 .6M138.9 75.9l-.6 .6M151.5 77.1l.5 .6M152 77.1l-.5 .6M152.7 77.1l.6 .6M153.3 77.1l-.6 .6M172.5 78.3l.5 .6M173 78.3l-.5 .6M173.7 78.3l.6 .6M174.3 78.3l-.6 .6M174.3 68.1l.6 .5M174.9 68.1l-.6 .5"/>
<path d="M175.5 68.1l.6 .5M176.1 68.1l-.6 .5M192.2 79.5l.6 .6M192.8 79.5l-.6 .6M200 63.3l.6 .6M200.6 63.3l-.6 .6M10.5 89.1l.6 .5M10.5 93.9l.6 .5M11.1 89.1l-.6 .5M11.1 93.9l-.6 .5M18.3 95l.6 .6M18.9 95l-.6 .6"/>
<path d="M35.2 84.3l.5 .6M35.7 84.3l-.5 .6M36.4 84.3l.5 .6M36.9 84.3l-.5 .6M37 96.3l.5 .5M37.5 96.3l-.5 .5M38.1 96.3l.6 .5M38.7 96.3l-.6 .5M58 97.5l.5 .6M58.5 97.5l-.5 .6M59.1 97.5l.6 .6M59.7 97.5l-.6 .6"/>
<path d="M73.5 98.7l.6 .6M74.1 98.7l-.6 .6M74.7 98.7l.6 .6M75.3 98.7l-.6 .6M135.9 98.1l.5 .6M136.4 98.1l-.5 .6M137.1 98.1l.5 .6M137.6 98.1l-.5 .6M151.5 99.3l.5 .6M152 99.3l-.5 .6M152.7 99.3l.6 .6M153.3 99.3l-.6 .6"/>
<path d="M174.3 90.3l.6 .6M174.9 90.3l-.6 .6M175.5 90.3l.6 .6M176.1 90.3l-.6 .6M200 80.6l.6 .6M200 85.5l.6 .6M200.6 80.6l-.6 .6M200.6 85.5l-.6 .6M10.5 116l.6 .6M10.5 111.3l.6 .5M11.1 116l-.6 .6M11.1 111.3l-.6 .5"/>
<path d="M18.3 117.3l.6 .5M18.9 117.3l-.6 .5M35.2 106.5l.5 .6M35.7 106.5l-.5 .6M36.4 106.5l.5 .6M36.9 106.5l-.5 .6M37 118.5l.5 .5M37.5 118.5l-.5 .5M38.1 118.5l.6 .5M38.7 118.5l-.6 .5M58 119.7l.5 .6M58.5 119.7l-.5 .6"/>
<path d="M59.1 119.7l.6 .6M59.7 119.7l-.6 .6M92.1 102.2l.6 .6M92.7 102.2l-.6 .6M93.3 102.2l.6 .6M93.9 102.2l-.6 .6M94.5 102.2l.6 .6M95.1 102.2l-.6 .6M108.9 102.2l.6 .6M109.5 102.2l-.6 .6M110.1 102.2l.6 .6M110.7 102.2l-.6 .6"/>
<path d="M111.3 102.2l.6 .6M111.9 102.2l-.6 .6M112.5 102.2l.6 .6M113.1 102.2l-.6 .6M113.7 102.2l.6 .6M114.3 102.2l-.6 .6M114.9 102.2l.5 .6M115.4 102.2l-.5 .6M116.1 102.2l.6 .6M116.7 102.2l-.6 .6M117.3 110.7l.6 .5M117.9 110.7l-.6 .5"/>
<path d="M118.5 110.7l.6 .5M119.1 110.7l-.6 .5M119.7 102.2l.6 .6M120.3 102.2l-.6 .6M172.5 100.5l.5 .5M173 100.5l-.5 .5M173.7 100.5l.6 .5M174.3 100.5l-.6 .5M174.9 112.5l.6 .6M175.5 112.5l-.6 .6M176.1 112.5l.6 .6M176.7 112.5l-.6 .6"/>
<path d="M192.2 101.6l.6 .6M192.8 101.6l-.6 .6M200 102.9l.6 .5M200 107.7l.6 .5M200.6 102.9l-.6 .5M200.6 107.7l-.6 .5M10.5 138.2l.6 .6M10.5 133.5l.6 .6M11.1 138.2l-.6 .6M11.1 133.5l-.6 .6M18.3 139.5l.6 .5M18.9 139.5l-.6 .5"/>
<path d="M35.2 128.7l.5 .5M35.7 128.7l-.5 .5M36.4 128.7l.5 .5M36.9 128.7l-.5 .5M73.5 120.9l.6 .6M74.1 120.9l-.6 .6M74.7 120.9l.6 .6M75.3 120.9l-.6 .6M96.3 131.7l.6 .5M96.9 131.7l-.6 .5M97.5 131.7l.6 .5M98.1 131.7l-.6 .5"/>
<path d="M98.7 131.7l.6 .5M99.3 131.7l-.6 .5M99.9 131.7l.6 .5M100.5 131.7l-.6 .5M101.1 131.7l.5 .5M101.6 131.7l-.5 .5M102.3 131.7l.6 .5M102.9 131.7l-.6 .5M104.7 131.7l.6 .5M105.3 131.7l-.6 .5M105.9 131.7l.6 .5M106.5 131.7l-.6 .5"/>
<path d="M107.1 131.7l.6 .5M107.7 131.7l-.6 .5M109.5 131.7l.6 .5M110.1 131.7l-.6 .5M110.7 131.7l.6 .5M111.3 131.7l-.6 .5M111.9 131.7l.6 .5M112.5 131.7l-.6 .5M114.3 131.7l.6 .5M114.9 131.7l-.6 .5M115.5 131.7l.5 .5M116 131.7l-.5 .5"/>
<path d="M116.7 131.7l.6 .5M117.3 131.7l-.6 .5M136.5 120.3l.5 .6M137 120.3l-.5 .6M137.7 120.3l.6 .6M138.3 120.3l-.6 .6M152.1 121.5l.6 .5M152.7 121.5l-.6 .5M153.3 121.5l.6 .5M153.9 121.5l-.6 .5M173.1 122.6l.5 .6M173.6 122.6l-.5 .6"/>
<path d="M173.7 134.7l.6 .6M174.3 122.6l.6 .6M174.3 134.7l-.6 .6M174.9 122.6l-.6 .6M174.9 134.7l.6 .6M175.5 134.7l-.6 .6M192.8 123.8l.6 .6M193.4 123.8l-.6 .6M200.7 129.8l.5 .6M200.7 125.1l.5 .5M201.2 129.8l-.5 .6M201.2 125.1l-.5 .5"/>
<path d="M10.5 155.7l.6 .6M11.1 155.7l-.6 .6M35.2 150.8l.5 .6M35.7 150.8l-.5 .6M36.4 150.8l.5 .6M36.9 150.8l-.5 .6M37 140.7l.5 .6M37.5 140.7l-.5 .6M38.1 140.7l.6 .6M38.7 140.7l-.6 .6M58 141.9l.5 .6M58.5 141.9l-.5 .6"/>
<path d="M59.1 141.9l.6 .6M59.7 141.9l-.6 .6M73.5 143l.6 .6M74.1 143l-.6 .6M74.7 143l.6 .6M75.3 143l-.6 .6M136.5 142.5l.5 .5M137 142.5l-.5 .5M137.7 142.5l.6 .5M138.3 142.5l-.6 .5M150.9 143.6l.5 .6M151.4 143.6l-.5 .6"/>
<path d="M152.1 143.6l.6 .6M152.7 143.6l-.6 .6M171.9 144.8l.5 .6M172.4 144.8l-.5 .6M173.1 144.8l.5 .6M173.6 144.8l-.5 .6M174.3 156.8l.6 .6M174.9 156.8l-.6 .6M175.5 156.8l.6 .6M176.1 156.8l-.6 .6M191.6 146.1l.6 .5M192.2 146.1l-.6 .5"/>
<path d="M199.4 147.3l.6 .5M199.4 152l.6 .6M200 147.3l-.6 .5M200 152l-.6 .6M10.5 160.5l.6 .5M10.5 177.8l.6 .6M11.1 160.5l-.6 .5M11.1 177.8l-.6 .6M18.3 161.7l.6 .5M18.9 161.7l-.6 .5M35.2 173l.5 .6M35.7 173l-.5 .6"/>
<path d="M36.4 173l.5 .6M36.9 173l-.5 .6M37 162.9l.5 .5M37.5 162.9l-.5 .5M38.1 162.9l.6 .5M38.7 162.9l-.6 .5M58 164l.5 .6M58.5 164l-.5 .6M59.1 164l.6 .6M59.7 164l-.6 .6M72.9 165.2l.6 .6M73.5 165.2l-.6 .6"/>
<path d="M74.1 165.2l.6 .6M74.7 165.2l-.6 .6M95.1 162.9l.6 .5M95.7 162.9l-.6 .5M96.3 162.9l.6 .5M96.9 162.9l-.6 .5M97.5 162.9l.6 .5M98.1 162.9l-.6 .5M99.9 162.9l.6 .5M100.5 162.9l-.6 .5M102.3 162.9l.6 .5M102.9 162.9l-.6 .5"/>
<path d="M103.5 162.9l.6 .5M104.1 162.9l-.6 .5M104.7 162.9l.6 .5M105.3 162.9l-.6 .5M105.9 162.9l.6 .5M106.5 162.9l-.6 .5M108.3 162.9l.5 .5M108.8 162.9l-.5 .5M109.5 162.9l.6 .5M110.1 162.9l-.6 .5M111.9 162.9l.6 .5M112.5 162.9l-.6 .5"/>
<path d="M136.5 164.6l.5 .6M137 164.6l-.5 .6M137.7 164.6l.6 .6M138.3 164.6l-.6 .6M151.5 165.8l.5 .6M152 165.8l-.5 .6M152.7 165.8l.6 .6M153.3 165.8l-.6 .6M172.5 167l.5 .6M173 167l-.5 .6M173.7 167l.6 .6M174.3 179l.6 .6"/>
<path d="M174.3 167l-.6 .6M174.9 179l-.6 .6M175.5 179l.6 .6M176.1 179l-.6 .6M192.2 168.3l.6 .5M192.8 168.3l-.6 .5M200 174.2l.6 .6M200 169.5l.6 .6M200.6 174.2l-.6 .6M200.6 169.5l-.6 .6M10.5 182.7l.6 .5M11.1 182.7l-.6 .5"/>
<path d="M18.3 183.9l.6 .5M18.9 183.9l-.6 .5M35.2 195.2l.5 .6M35.7 195.2l-.5 .6M36.4 195.2l.5 .6M36.9 195.2l-.5 .6M37 185l.5 .6M37.5 185l-.5 .6M38.1 185l.6 .6M38.7 185l-.6 .6M58 186.2l.5 .6M58.5 186.2l-.5 .6"/>
<path d="M59.1 186.2l.6 .6M59.7 186.2l-.6 .6M73.5 187.4l.6 .6M74.1 187.4l-.6 .6M74.7 187.4l.6 .6M75.3 187.4l-.6 .6M92.1 186.8l.6 .6M92.7 186.8l-.6 .6M93.3 186.8l.6 .6M93.9 186.8l-.6 .6M94.5 186.8l.6 .6M95.1 186.8l-.6 .6"/>
<path d="M108.9 186.8l.6 .6M109.5 186.8l-.6 .6M110.1 186.8l.6 .6M110.7 186.8l-.6 .6M111.3 186.8l.6 .6M111.9 186.8l-.6 .6M112.5 186.8l.6 .6M113.1 186.8l-.6 .6M113.7 186.8l.6 .6M114.3 186.8l-.6 .6M114.9 186.8l.5 .6M115.4 186.8l-.5 .6"/>
<path d="M116.1 186.8l.6 .6M116.7 186.8l-.6 .6M119.7 186.8l.6 .6M120.3 186.8l-.6 .6M137.1 186.8l.5 .6M137.6 186.8l-.5 .6M138.3 186.8l.6 .6M138.9 186.8l-.6 .6M151.5 188l.5 .6M152 188l-.5 .6M152.7 188l.6 .6M153.3 188l-.6 .6"/>
<path d="M172.5 189.3l.5 .5M173 189.3l-.5 .5M173.7 189.3l.6 .5M174.3 189.3l-.6 .5M192.2 190.5l.6 .5M192.8 190.5l-.6 .5M200 191.6l.6 .6M200 196.5l.6 .5M200.6 191.6l-.6 .6M200.6 196.5l-.6 .5M10.5 200l.6 .6M10.5 204.9l.6 .5"/>
<path d="M11.1 200l-.6 .6M11.1 204.9l-.6 .5M18.3 206l.6 .6M18.9 206l-.6 .6M35.2 217.4l.5 .6M35.7 217.4l-.5 .6M36.4 217.4l.5 .6M36.9 217.4l-.5 .6M37 207.2l.5 .6M37.5 207.2l-.5 .6M38.1 207.2l.6 .6M38.7 207.2l-.6 .6"/>
<path d="M58 208.4l.5 .6M58.5 208.4l-.5 .6M59.1 208.4l.6 .6M59.7 208.4l-.6 .6M73.5 209.6l.6 .6M74.1 209.6l-.6 .6M74.7 209.6l.6 .6M75.3 209.6l-.6 .6M93.3 213.2l.6 .6M93.9 213.2l-.6 .6M94.5 213.2l.6 .6M95.1 213.2l-.6 .6"/>
<path d="M108.9 213.2l.6 .6M109.5 213.2l-.6 .6M110.1 213.2l.6 .6M110.7 213.2l-.6 .6M111.3 213.2l.6 .6M111.9 213.2l-.6 .6M112.5 213.2l.6 .6M113.1 213.2l-.6 .6M113.7 213.2l.6 .6M114.3 213.2l-.6 .6M117.3 213.2l.6 .6M117.9 213.2l-.6 .6"/>
<path d="M118.5 213.2l.6 .6M119.1 213.2l-.6 .6M119.7 213.2l.6 .6M120.3 213.2l-.6 .6M135.9 209l.5 .6M136.4 209l-.5 .6M137.1 209l.5 .6M137.6 209l-.5 .6M151.5 210.2l.5 .6M152 210.2l-.5 .6M152.7 210.2l.6 .6M153.3 210.2l-.6 .6"/>
<path d="M172.5 211.5l.5 .5M173 211.5l-.5 .5M173.7 211.5l.6 .5M174.3 201.2l.6 .6M174.3 211.5l-.6 .5M174.9 201.2l-.6 .6M175.5 201.2l.6 .6M176.1 201.2l-.6 .6M192.2 212.6l.6 .6M192.8 212.6l-.6 .6M200 213.8l.6 .6M200 218.7l.6 .5"/>
<path d="M200.6 213.8l-.6 .6M200.6 218.7l-.6 .5M10.5 227l.6 .6M10.5 222.2l.6 .6M11.1 227l-.6 .6M11.1 222.2l-.6 .6M18.3 228.2l.6 .6M18.9 228.2l-.6 .6M35.2 239.6l.5 .6M35.7 239.6l-.5 .6M36.4 239.6l.5 .6M36.9 239.6l-.5 .6"/>
<path d="M37 229.4l.5 .6M37.5 229.4l-.5 .6M38.1 229.4l.6 .6M38.7 229.4l-.6 .6M58 230.6l.5 .6M58.5 230.6l-.5 .6M59.1 230.6l.6 .6M59.7 230.6l-.6 .6M73.5 231.8l.6 .6M74.1 231.8l-.6 .6M74.7 231.8l.6 .6M75.3 231.8l-.6 .6"/>
<path d="M136.5 231.2l.5 .6M137 231.2l-.5 .6M137.7 231.2l.6 .6M138.3 231.2l-.6 .6M152.1 232.5l.6 .5M152.7 232.5l-.6 .5M153.3 232.5l.6 .5M153.9 232.5l-.6 .5M173.1 233.6l.5 .5M173.6 233.6l-.5 .5M174.3 233.6l.6 .5M174.9 223.4l.6 .6"/>
<path d="M174.9 233.6l-.6 .5M175.5 223.4l-.6 .6M176.1 223.4l.6 .6M176.7 223.4l-.6 .6M192.8 234.8l.6 .6M193.4 234.8l-.6 .6M200.7 236l.5 .6M201.2 236l-.5 .6M200.7 240.8l.5 .5M201.2 240.8l-.5 .5"/>
</g>
<g fill="#090">
<path d="M77.2 41.7h.4v.5h-.4z"/>
<path d="M71.8 43.6h.4v.4h-.4z"/>
<path d="M83.8 73h.4v.4h-.4z"/>
<path d="M86.2 81.4h.4v.4h-.4z"/>
<path d="M70.6 41.7h.4v.5h-.4z"/>
<path d="M17.2 109h.4v.4h-.4z"/>
<path d="M56.8 64.6h.4v.4h-.4z"/>
<path d="M56.8 43.6h.4v.4h-.4z"/>
<path d="M28.6 58.6h.4v.4h-.4z"/>
<path d="M40.6 48.3h.5v.5h-.5z"/>
<path d="M32.9 47.1h.4v.5h-.4z"/>
<path d="M41.2 43.6h.4v.4h-.4z"/>
<path d="M61.6 64h.5v.4h-.5z"/>
<path d="M28.6 47.1h.4v.5h-.4z"/>
<path d="M25.7 49.6h.4v.4h-.4z"/>
<path d="M52.6 64h.4v.4h-.4z"/>
<path d="M31.6 64.6h.4v.4h-.4z"/>
<path d="M37.6 64.6h.4v.4h-.4z"/>
<path d="M17.2 43.6h.4v.4h-.4z"/>
<path d="M8.8 65.8h.4v.4h-.4z"/>
<path d="M6.4 64.6h.5v.4h-.5z"/>
<path d="M77.8 28.6h.4v.5h-.4z"/>
<path d="M43 48.3h.4v.5h-.4z"/>
<path d="M70.6 130.5h.4v.5h-.4z"/>
<path d="M83.8 117.3h.4v.5h-.4z"/>
<path d="M86.2 59.2h.4v.4h-.4z"/>
<path d="M69.4 64.6h.4v.4h-.4z"/>
<path d="M69.4 49.6h.4v.4h-.4z"/>
<path d="M70.6 108.4h.4v.4h-.4z"/>
<path d="M72.4 88h.4v.4h-.4z"/>
<path d="M72.4 65.8h.4v.4h-.4z"/>
<path d="M83.8 28.6h.4v.5h-.4z"/>
<path d="M17.2 88h.4v.4h-.4z"/>
<path d="M84.4 95.2h.4v.4h-.4z"/>
<path d="M8.8 110.1h.4v.5h-.4z"/>
<path d="M72.4 110.1h.4v.5h-.4z"/>
<path d="M66.4 86.2h.4v.4h-.4z"/>
<path d="M28.6 80.8h.4v.4h-.4z"/>
<path d="M56.8 65.8h.4v.4h-.4z"/>
<path d="M31.6 86.8h.4v.4h-.4z"/>
<path d="M22 69.3h.4v.5h-.4z"/>
<path d="M66.4 71.8h.4v.4h-.4z"/>
<path d="M47.3 70.5h.4v.5h-.4z"/>
<path d="M37.6 86.8h.4v.4h-.4z"/>
<path d="M40.6 70.5h.5v.5h-.5z"/>
<path d="M25.7 71.8h.4v.4h-.4z"/>
<path d="M52.6 70.5h.4v.5h-.4z"/>
<path d="M43 79.6h.4v.4h-.4z"/>
<path d="M52.6 86.2h.4v.4h-.4z"/>
<path d="M35.8 65.8h.4v.4h-.4z"/>
<path d="M28.6 69.3h.4v.5h-.4z"/>
<path d="M43 70.5h.4v.5h-.4z"/>
<path d="M56.8 86.8h.4v.4h-.4z"/>
<path d="M61.6 77.7h.5v.5h-.5z"/>
<path d="M61.6 86.2h.5v.4h-.5z"/>
<path d="M61.6 71.8h.5v.4h-.5z"/>
<path d="M52.6 108.4h.4v.4h-.4z"/>
<path d="M37.6 109h.4v.4h-.4z"/>
<path d="M31.6 109h.4v.4h-.4z"/>
<path d="M52.6 92.8h.4v.4h-.4z"/>
<path d="M61.6 108.4h.5v.4h-.5z"/>
<path d="M43 101.8h.4v.4h-.4z"/>
<path d="M35.8 88h.4v.4h-.4z"/>
<path d="M66.4 94h.4v.4h-.4z"/>
<path d="M61.6 94h.5v.4h-.5z"/>
<path d="M56.8 131.1h.4v.5h-.4z"/>
<path d="M40.6 92.8h.5v.4h-.5z"/>
<path d="M61.6 100h.5v.4h-.5z"/>
<path d="M56.8 88h.4v.4h-.4z"/>
<path d="M47.3 92.8h.4v.4h-.4z"/>
<path d="M66.4 108.4h.4v.4h-.4z"/>
<path d="M56.8 109h.4v.4h-.4z"/>
<path d="M28.6 91.5h.4v.5h-.4z"/>
<path d="M66.4 130.5h.4v.5h-.4z"/>
<path d="M28.6 102.9h.4v.5h-.4z"/>
<path d="M22 91.5h.4v.5h-.4z"/>
<path d="M32.9 91.5h.4v.5h-.4z"/>
<path d="M41.2 88h.4v.4h-.4z"/>
<path d="M43 92.8h.4v.4h-.4z"/>
<path d="M25.7 94h.4v.4h-.4z"/>
<path d="M72.4 21.4h.4v.5h-.4z"/>
<path d="M52.6 130.5h.4v.5h-.4z"/>
<path d="M37.6 131.1h.4v.5h-.4z"/>
<path d="M77.8 95.2h.4v.4h-.4z"/>
<path d="M28.6 113.7h.4v.4h-.4z"/>
<path d="M70 64h.4v.4h-.4z"/>
<path d="M77.8 117.3h.4v.5h-.4z"/>
<path d="M77.2 130.5h.4v.5h-.4z"/>
<path d="M40.6 115h.5v.4h-.5z"/>
<path d="M56.8 110.1h.4v.5h-.4z"/>
<path d="M61.6 122.2h.5v.4h-.5z"/>
<path d="M31.6 131.1h.4v.5h-.4z"/>
<path d="M52.6 115h.4v.4h-.4z"/>
<path d="M28.6 125.1h.4v.5h-.4z"/>
<path d="M61.6 130.5h.5v.5h-.5z"/>
<path d="M41.2 110.1h.4v.5h-.4z"/>
<path d="M32.9 113.7h.4v.4h-.4z"/>
<path d="M66.4 64h.4v.4h-.4z"/>
<path d="M66.4 49.6h.4v.4h-.4z"/>
<path d="M8.8 43.6h.4v.4h-.4z"/>
<path d="M17.2 21.4h.4v.5h-.4z"/>
<path d="M52.6 48.3h.4v.5h-.4z"/>
<path d="M61.6 55.5h.5v.5h-.5z"/>
<path d="M77.2 108.4h.4v.4h-.4z"/>
<path d="M22 113.7h.4v.4h-.4z"/>
<path d="M61.6 116.2h.5v.4h-.5z"/>
<path d="M35.8 110.1h.4v.5h-.4z"/>
<path d="M43 123.9h.4v.5h-.4z"/>
<path d="M43 115h.4v.4h-.4z"/>
<path d="M47.3 115h.4v.4h-.4z"/>
<path d="M25.7 116.2h.4v.4h-.4z"/>
<path d="M66.4 116.2h.4v.4h-.4z"/>
<path d="M32.9 69.3h.4v.5h-.4z"/>
<path d="M41.2 65.8h.4v.4h-.4z"/>
<path d="M35.8 43.6h.4v.4h-.4z"/>
<path d="M61.6 49.6h.5v.4h-.5z"/>
<path d="M47.3 48.3h.4v.5h-.4z"/>
<path d="M22 47.1h.4v.5h-.4z"/>
<path d="M43 57.4h.4v.4h-.4z"/>
<path d="M6.4 86.8h.5v.4h-.5z"/>
<path d="M76.6 64h.4v.4h-.4z"/>
<path d="M17.2 86.8h.4v.4h-.4z"/>
<path d="M17.2 64.6h.4v.4h-.4z"/>
<path d="M17.2 42.4h.4v.5h-.4z"/>
<path d="M8.8 88h.4v.4h-.4z"/>
<path d="M77.2 86.2h.4v.4h-.4z"/>
<path d="M83.2 50.8h.4v.4h-.4z"/>
<path d="M77.8 73h.4v.4h-.4z"/>
<path d="M70.6 86.2h.4v.4h-.4z"/>
<path d="M17.2 110.1h.4v.5h-.4z"/>
<path d="M17.2 65.8h.4v.4h-.4z"/>
<path d="M41.2 21.4h.4v.5h-.4z"/>
<path d="M32.9 25h.4v.4h-.4z"/>
<path d="M56.8 21.4h.4v.5h-.4z"/>
<path d="M28.6 36.4h.4v.4h-.4z"/>
<path d="M40.6 26.2h.5v.4h-.5z"/>
<path d="M61.6 41.7h.5v.5h-.5z"/>
<path d="M52.6 26.2h.4v.4h-.4z"/>
<path d="M61.6 33.3h.5v.5h-.5z"/>
<path d="M31.6 42.4h.4v.5h-.4z"/>
<path d="M37.6 42.4h.4v.5h-.4z"/>
<path d="M52.6 41.7h.4v.5h-.4z"/>
<path d="M28.6 25h.4v.4h-.4z"/>
<path d="M25.7 27.3h.4v.5h-.4z"/>
<path d="M43 26.2h.4v.4h-.4z"/>
<path d="M43 35.2h.4v.5h-.4z"/>
<path d="M22 25h.4v.4h-.4z"/>
<path d="M35.8 21.4h.4v.5h-.4z"/>
<path d="M47.3 26.2h.4v.4h-.4z"/>
<path d="M61.6 27.3h.5v.5h-.5z"/>
<path d="M66.4 27.3h.4v.5h-.4z"/>
<path d="M66.4 41.7h.4v.5h-.4z"/>
<path d="M56.8 42.4h.4v.5h-.4z"/>
<path d="M86.8 60.4h.4v.4h-.4z"/>
<path d="M86.8 82.5h.4v.5h-.4z"/>
<path d="M86.2 71.2h.4v.4h-.4z"/>
<path d="M86.2 103.5h.4v.5h-.4z"/>
<path d="M107.8 71.2h.4v.4h-.4z"/>
<path d="M86.8 104.7h.4v.5h-.4z"/>
<path d="M86.8 108.4h.4v.4h-.4z"/>
<path d="M106.6 108.4h.4v.4h-.4z"/>
<path d="M86.2 107.8h.4v.4h-.4z"/>
<path d="M125.1 93.4h.5v.4h-.5z"/>
<path d="M149.2 96.9h.4v.5h-.4z"/>
<path d="M158.2 104.1h.4v.5h-.4z"/>
<path d="M149.2 88.6h.4v.4h-.4z"/>
<path d="M170.2 104.1h.4v.5h-.4z"/>
<path d="M182.1 94h.4v.4h-.4z"/>
<path d="M153.9 109h.4v.4h-.4z"/>
<path d="M178 105.3h.4v.5h-.4z"/>
<path d="M169.6 109h.4v.4h-.4z"/>
<path d="M179.2 88h.4v.4h-.4z"/>
<path d="M140.8 22h.4v.4h-.4z"/>
<path d="M141.4 36.4h.4v.4h-.4z"/>
<path d="M138.9 42.4h.5v.5h-.5z"/>
<path d="M128.2 79.6h.4v.4h-.4z"/>
<path d="M127 101.8h.4v.4h-.4z"/>
<path d="M193.6 43.6h.4v.4h-.4z"/>
<path d="M203.1 109h.4v.4h-.4z"/>
<path d="M194.1 110.1h.5v.5h-.5z"/>
<path d="M149.2 102.9h.4v.5h-.4z"/>
<path d="M144.4 102.9h.4v.5h-.4z"/>
<path d="M163.6 104.1h.4v.5h-.4z"/>
<path d="M174.9 109h.4v.4h-.4z"/>
<path d="M153.9 88h.4v.4h-.4z"/>
<path d="M144.4 88.6h.4v.4h-.4z"/>
<path d="M182.1 105.3h.4v.5h-.4z"/>
<path d="M185.2 102.9h.4v.5h-.4z"/>
<path d="M167.7 104.1h.4v.5h-.4z"/>
<path d="M188.7 105.3h.4v.5h-.4z"/>
<path d="M167.7 95.2h.4v.4h-.4z"/>
<path d="M158.2 88.6h.4v.4h-.4z"/>
<path d="M173.2 88h.4v.4h-.4z"/>
<path d="M149.8 125.1h.4v.5h-.4z"/>
<path d="M153.9 43.6h.4v.4h-.4z"/>
<path d="M144.4 44.2h.4v.4h-.4z"/>
<path d="M144.4 58.6h.4v.4h-.4z"/>
<path d="M149.2 58.6h.4v.4h-.4z"/>
<path d="M163.6 59.8h.4v.4h-.4z"/>
<path d="M153.3 21.4h.4v.5h-.4z"/>
<path d="M143.8 22h.4v.4h-.4z"/>
<path d="M143.8 36.4h.4v.4h-.4z"/>
<path d="M148.6 36.4h.4v.4h-.4z"/>
<path d="M163 37.6h.4v.4h-.4z"/>
<path d="M174.3 42.4h.4v.5h-.4z"/>
<path d="M188.1 38.8h.4v.4h-.4z"/>
<path d="M167.1 28.6h.4v.5h-.4z"/>
<path d="M167.1 37.6h.4v.4h-.4z"/>
<path d="M184.6 36.4h.4v.4h-.4z"/>
<path d="M181.5 38.8h.4v.4h-.4z"/>
<path d="M157.6 22h.4v.4h-.4z"/>
<path d="M172.6 21.4h.4v.5h-.4z"/>
<path d="M178.6 21.4h.4v.5h-.4z"/>
<path d="M148.6 30.4h.4v.4h-.4z"/>
<path d="M157.6 37.6h.4v.4h-.4z"/>
<path d="M148.6 22h.4v.4h-.4z"/>
<path d="M169.6 37.6h.4v.4h-.4z"/>
<path d="M145 125.1h.4v.5h-.4z"/>
<path d="M181.5 27.3h.4v.5h-.4z"/>
<path d="M153.3 42.4h.4v.5h-.4z"/>
<path d="M177.4 38.8h.4v.4h-.4z"/>
<path d="M169 42.4h.4v.5h-.4z"/>
<path d="M168.3 117.3h.4v.5h-.4z"/>
<path d="M154.6 110.1h.4v.5h-.4z"/>
<path d="M168.3 126.3h.4v.5h-.4z"/>
<path d="M164.2 126.3h.4v.5h-.4z"/>
<path d="M153.9 65.8h.4v.4h-.4z"/>
<path d="M144.4 66.4h.4v.4h-.4z"/>
<path d="M144.4 80.8h.4v.4h-.4z"/>
<path d="M149.2 80.8h.4v.4h-.4z"/>
<path d="M163.6 81.9h.4v.5h-.4z"/>
<path d="M174.9 86.8h.4v.4h-.4z"/>
<path d="M188.7 83.1h.4v.5h-.4z"/>
<path d="M167.7 73h.4v.4h-.4z"/>
<path d="M167.7 81.9h.4v.5h-.4z"/>
<path d="M185.2 80.8h.4v.4h-.4z"/>
<path d="M182.1 83.1h.4v.5h-.4z"/>
<path d="M185.8 125.1h.4v.5h-.4z"/>
<path d="M158.2 66.4h.4v.4h-.4z"/>
<path d="M173.2 65.8h.4v.4h-.4z"/>
<path d="M179.2 65.8h.4v.4h-.4z"/>
<path d="M149.2 74.8h.4v.4h-.4z"/>
<path d="M158.2 81.9h.4v.5h-.4z"/>
<path d="M149.2 66.4h.4v.4h-.4z"/>
<path d="M170.2 81.9h.4v.5h-.4z"/>
<path d="M182.1 71.8h.4v.4h-.4z"/>
<path d="M153.9 86.8h.4v.4h-.4z"/>
<path d="M178 83.1h.4v.5h-.4z"/>
<path d="M169.6 86.8h.4v.4h-.4z"/>
<path d="M174.9 64.6h.4v.4h-.4z"/>
<path d="M188.7 60.9h.4v.5h-.4z"/>
<path d="M167.7 50.8h.4v.4h-.4z"/>
<path d="M167.7 59.8h.4v.4h-.4z"/>
<path d="M185.2 58.6h.4v.4h-.4z"/>
<path d="M182.1 60.9h.4v.5h-.4z"/>
<path d="M158.2 44.2h.4v.4h-.4z"/>
<path d="M173.2 43.6h.4v.4h-.4z"/>
<path d="M179.2 43.6h.4v.4h-.4z"/>
<path d="M149.2 52.6h.4v.4h-.4z"/>
<path d="M158.2 59.8h.4v.4h-.4z"/>
<path d="M149.2 44.2h.4v.4h-.4z"/>
<path d="M170.2 59.8h.4v.4h-.4z"/>
<path d="M182.1 49.6h.4v.4h-.4z"/>
<path d="M153.9 64.6h.4v.4h-.4z"/>
<path d="M178 60.9h.4v.5h-.4z"/>
<path d="M169.6 64.6h.4v.4h-.4z"/>
<path d="M145 110.7h.4v.5h-.4z"/>
<path d="M189.3 127.5h.4v.4h-.4z"/>
<path d="M182.7 127.5h.4v.4h-.4z"/>
<path d="M158.8 110.7h.4v.5h-.4z"/>
<path d="M173.7 110.1h.5v.5h-.5z"/>
<path d="M179.8 110.1h.4v.5h-.4z"/>
<path d="M149.8 119.1h.4v.5h-.4z"/>
<path d="M158.8 126.3h.4v.5h-.4z"/>
<path d="M149.8 110.7h.4v.5h-.4z"/>
<path d="M170.8 126.3h.4v.5h-.4z"/>
<path d="M182.7 116.2h.4v.4h-.4z"/>
<path d="M178.6 127.5h.4v.4h-.4z"/>
<path d="M142 80.8h.4v.4h-.4z"/>
<path d="M124.6 47.7h.4v.5h-.4z"/>
<path d="M124.6 92.1h.4v.5h-.4z"/>
<path d="M127.6 57.4h.4v.4h-.4z"/>
<path d="M138.9 64.6h.5v.4h-.5z"/>
<path d="M140.8 44.2h.4v.4h-.4z"/>
<path d="M141.4 58.6h.4v.4h-.4z"/>
<path d="M125.1 48.9h.5v.5h-.5z"/>
<path d="M124.6 108.4h.4v.4h-.4z"/>
<path d="M127.6 35.2h.4v.5h-.4z"/>
<path d="M125.1 107.8h.5v.4h-.5z"/>
<path d="M134.2 22h.4v.4h-.4z"/>
<path d="M133.6 35.2h.4v.5h-.4z"/>
<path d="M134.2 44.2h.4v.4h-.4z"/>
<path d="M134.2 79.6h.4v.4h-.4z"/>
<path d="M133.6 88.6h.4v.4h-.4z"/>
<path d="M133.6 57.4h.4v.4h-.4z"/>
<path d="M133.6 123.9h.4v.5h-.4z"/>
<path d="M140.2 88.6h.4v.4h-.4z"/>
<path d="M138.4 109h.4v.4h-.4z"/>
<path d="M134.2 110.7h.4v.5h-.4z"/>
<path d="M205 110.1h.4v.5h-.4z"/>
<path d="M203.1 64.6h.4v.4h-.4z"/>
<path d="M193.6 88h.4v.4h-.4z"/>
<path d="M193 21.4h.4v.5h-.4z"/>
<path d="M134.8 66.4h.4v.4h-.4z"/>
<path d="M127.6 123.9h.4v.5h-.4z"/>
<path d="M205 43.6h.4v.4h-.4z"/>
<path d="M140.8 110.7h.4v.5h-.4z"/>
<path d="M205 88h.4v.4h-.4z"/>
<path d="M193.6 86.8h.4v.4h-.4z"/>
<path d="M193.6 64.6h.4v.4h-.4z"/>
<path d="M141.4 66.4h.4v.4h-.4z"/>
<path d="M139.5 86.8h.4v.4h-.4z"/>
<path d="M133 101.8h.4v.4h-.4z"/>
<path d="M125.1 70.5h.5v.5h-.5z"/>
<path d="M124.6 69.3h.4v.5h-.4z"/>
<path d="M193.6 109h.4v.4h-.4z"/>
<path d="M203.1 86.8h.4v.4h-.4z"/>
<path d="M138.9 131.1h.5v.5h-.5z"/>
<path d="M154.6 131.1h.4v.5h-.4z"/>
<path d="M170.2 131.1h.4v.5h-.4z"/>
<path d="M175.5 131.1h.4v.5h-.4z"/>
<path d="M194.1 131.1h.5v.5h-.5z"/>
<path d="M203.1 131.1h.4v.5h-.4z"/>
<path d="M124.6 203.1h.4v.4h-.4z"/>
<path d="M84.4 206.1h.4v.4h-.4z"/>
<path d="M86.2 182.1h.4v.5h-.4z"/>
<path d="M107.8 182.1h.4v.5h-.4z"/>
<path d="M86.8 171.3h.4v.4h-.4z"/>
<path d="M86.2 170.1h.4v.4h-.4z"/>
<path d="M86.2 218.7h.4v.4h-.4z"/>
<path d="M125.1 204.3h.5v.4h-.5z"/>
<path d="M40.6 137.1h.5v.5h-.5z"/>
<path d="M17.2 132.3h.4v.5h-.4z"/>
<path d="M22 136h.4v.4h-.4z"/>
<path d="M35.8 132.3h.4v.5h-.4z"/>
<path d="M41.2 132.3h.4v.5h-.4z"/>
<path d="M25.7 138.3h.4v.5h-.4z"/>
<path d="M32.9 136h.4v.4h-.4z"/>
<path d="M35.8 154.5h.4v.5h-.4z"/>
<path d="M28.6 136h.4v.4h-.4z"/>
<path d="M47.3 137.1h.4v.5h-.4z"/>
<path d="M43 137.1h.4v.5h-.4z"/>
<path d="M61.6 138.3h.5v.5h-.5z"/>
<path d="M56.8 132.3h.4v.5h-.4z"/>
<path d="M52.6 137.1h.4v.5h-.4z"/>
<path d="M61.6 144.3h.5v.5h-.5z"/>
<path d="M43 146.1h.4v.5h-.4z"/>
<path d="M52.6 152.7h.4v.5h-.4z"/>
<path d="M56.8 153.3h.4v.5h-.4z"/>
<path d="M61.6 160.5h.5v.5h-.5z"/>
<path d="M47.3 159.3h.4v.5h-.4z"/>
<path d="M52.6 159.3h.4v.5h-.4z"/>
<path d="M8.8 154.5h.4v.5h-.4z"/>
<path d="M72.4 132.3h.4v.5h-.4z"/>
<path d="M66.4 152.7h.4v.5h-.4z"/>
<path d="M61.6 152.7h.5v.5h-.5z"/>
<path d="M66.4 138.3h.4v.5h-.4z"/>
<path d="M77.8 139.5h.4v.5h-.4z"/>
<path d="M83.8 139.5h.4v.5h-.4z"/>
<path d="M77.2 139.5h.4v.5h-.4z"/>
<path d="M28.6 147.3h.4v.5h-.4z"/>
<path d="M37.6 153.3h.4v.5h-.4z"/>
<path d="M43 159.3h.4v.5h-.4z"/>
<path d="M41.2 154.5h.4v.5h-.4z"/>
<path d="M40.6 159.3h.5v.5h-.5z"/>
<path d="M31.6 153.3h.4v.5h-.4z"/>
<path d="M41.2 176.7h.4v.4h-.4z"/>
<path d="M43 168.3h.4v.5h-.4z"/>
<path d="M35.8 176.7h.4v.4h-.4z"/>
<path d="M40.6 181.5h.5v.5h-.5z"/>
<path d="M47.3 181.5h.4v.5h-.4z"/>
<path d="M43 181.5h.4v.5h-.4z"/>
<path d="M22 180.3h.4v.5h-.4z"/>
<path d="M25.7 182.7h.4v.4h-.4z"/>
<path d="M32.9 180.3h.4v.5h-.4z"/>
<path d="M28.6 180.3h.4v.5h-.4z"/>
<path d="M28.6 191.7h.4v.4h-.4z"/>
<path d="M17.2 198.9h.4v.4h-.4z"/>
<path d="M17.2 175.5h.4v.4h-.4z"/>
<path d="M17.2 153.3h.4v.5h-.4z"/>
<path d="M22 158.1h.4v.5h-.4z"/>
<path d="M17.2 154.5h.4v.5h-.4z"/>
<path d="M25.7 160.5h.4v.5h-.4z"/>
<path d="M28.6 169.5h.4v.4h-.4z"/>
<path d="M28.6 158.1h.4v.5h-.4z"/>
<path d="M32.9 158.1h.4v.5h-.4z"/>
<path d="M31.6 197.7h.4v.4h-.4z"/>
<path d="M41.2 198.9h.4v.4h-.4z"/>
<path d="M35.8 198.9h.4v.4h-.4z"/>
<path d="M43 190.5h.4v.4h-.4z"/>
<path d="M37.6 197.7h.4v.4h-.4z"/>
<path d="M52.6 197.1h.4v.4h-.4z"/>
<path d="M52.6 181.5h.4v.5h-.4z"/>
<path d="M25.7 227.1h.4v.4h-.4z"/>
<path d="M28.6 224.7h.4v.4h-.4z"/>
<path d="M17.2 221.1h.4v.4h-.4z"/>
<path d="M17.2 219.9h.4v.4h-.4z"/>
<path d="M22 224.7h.4v.4h-.4z"/>
<path d="M41.2 221.1h.4v.4h-.4z"/>
<path d="M28.6 213.9h.4v.4h-.4z"/>
<path d="M32.9 224.7h.4v.4h-.4z"/>
<path d="M35.8 221.1h.4v.4h-.4z"/>
<path d="M31.6 219.9h.4v.4h-.4z"/>
<path d="M37.6 219.9h.4v.4h-.4z"/>
<path d="M40.6 203.7h.5v.4h-.5z"/>
<path d="M43 203.7h.4v.4h-.4z"/>
<path d="M37.6 175.5h.4v.4h-.4z"/>
<path d="M52.6 203.7h.4v.4h-.4z"/>
<path d="M47.3 203.7h.4v.4h-.4z"/>
<path d="M8.8 176.7h.4v.4h-.4z"/>
<path d="M17.2 176.7h.4v.4h-.4z"/>
<path d="M31.6 175.5h.4v.4h-.4z"/>
<path d="M28.6 202.5h.4v.5h-.4z"/>
<path d="M22 202.5h.4v.5h-.4z"/>
<path d="M6.4 197.7h.5v.4h-.5z"/>
<path d="M6.4 175.5h.5v.4h-.5z"/>
<path d="M31.6 242.1h.4v.4h-.4z"/>
<path d="M28.6 236h.4v.5h-.4z"/>
<path d="M37.6 242.1h.4v.4h-.4z"/>
<path d="M8.8 198.9h.4v.4h-.4z"/>
<path d="M25.7 204.9h.4v.4h-.4z"/>
<path d="M17.2 197.7h.4v.4h-.4z"/>
<path d="M32.9 202.5h.4v.5h-.4z"/>
<path d="M43 234.9h.4v.4h-.4z"/>
<path d="M47.3 225.9h.4v.4h-.4z"/>
<path d="M43 225.9h.4v.4h-.4z"/>
<path d="M40.6 225.9h.5v.4h-.5z"/>
<path d="M52.6 219.3h.4v.4h-.4z"/>
<path d="M52.6 225.9h.4v.4h-.4z"/>
<path d="M52.6 241.5h.4v.4h-.4z"/>
<path d="M43 212.7h.4v.4h-.4z"/>
<path d="M70.6 197.1h.4v.4h-.4z"/>
<path d="M77.2 197.1h.4v.4h-.4z"/>
<path d="M77.8 206.1h.4v.4h-.4z"/>
<path d="M86.8 193.5h.4v.5h-.4z"/>
<path d="M86.2 192.3h.4v.4h-.4z"/>
<path d="M86.8 215.7h.4v.5h-.4z"/>
<path d="M86.8 219.3h.4v.4h-.4z"/>
<path d="M86.2 214.5h.4v.4h-.4z"/>
<path d="M66.4 227.1h.4v.4h-.4z"/>
<path d="M61.6 241.5h.5v.4h-.5z"/>
<path d="M56.8 242.1h.4v.4h-.4z"/>
<path d="M61.6 227.1h.5v.4h-.5z"/>
<path d="M61.6 233.1h.5v.4h-.5z"/>
<path d="M66.4 219.3h.4v.4h-.4z"/>
<path d="M72.4 221.1h.4v.4h-.4z"/>
<path d="M70.6 219.3h.4v.4h-.4z"/>
<path d="M66.4 241.5h.4v.4h-.4z"/>
<path d="M70.6 241.5h.4v.4h-.4z"/>
<path d="M61.6 204.9h.5v.4h-.5z"/>
<path d="M66.4 204.9h.4v.4h-.4z"/>
<path d="M77.2 219.3h.4v.4h-.4z"/>
<path d="M61.6 219.3h.5v.4h-.5z"/>
<path d="M61.6 210.9h.5v.4h-.5z"/>
<path d="M56.8 221.1h.4v.4h-.4z"/>
<path d="M56.8 219.9h.4v.4h-.4z"/>
<path d="M77.2 241.5h.4v.4h-.4z"/>
<path d="M77.8 228.3h.4v.4h-.4z"/>
<path d="M83.8 228.3h.4v.4h-.4z"/>
<path d="M61.6 197.1h.5v.4h-.5z"/>
<path d="M66.4 197.1h.4v.4h-.4z"/>
<path d="M72.4 198.9h.4v.4h-.4z"/>
<path d="M61.6 188.7h.5v.5h-.5z"/>
<path d="M56.8 198.9h.4v.4h-.4z"/>
<path d="M56.8 197.7h.4v.4h-.4z"/>
<path d="M83.2 161.7h.4v.4h-.4z"/>
<path d="M61.6 174.9h.5v.5h-.5z"/>
<path d="M61.6 166.5h.5v.5h-.5z"/>
<path d="M70 174.9h.4v.5h-.4z"/>
<path d="M72.4 176.7h.4v.4h-.4z"/>
<path d="M69.4 175.5h.4v.4h-.4z"/>
<path d="M66.4 182.7h.4v.4h-.4z"/>
<path d="M61.6 182.7h.5v.4h-.5z"/>
<path d="M66.4 174.9h.4v.5h-.4z"/>
<path d="M56.8 176.7h.4v.4h-.4z"/>
<path d="M52.6 174.9h.4v.5h-.4z"/>
<path d="M56.8 175.5h.4v.4h-.4z"/>
<path d="M76.6 174.9h.4v.5h-.4z"/>
<path d="M77.8 183.9h.4v.4h-.4z"/>
<path d="M83.8 183.9h.4v.4h-.4z"/>
<path d="M70.6 152.7h.4v.5h-.4z"/>
<path d="M77.2 161.7h.4v.4h-.4z"/>
<path d="M77.2 152.7h.4v.5h-.4z"/>
<path d="M71.8 154.5h.4v.5h-.4z"/>
<path d="M69.4 160.5h.4v.5h-.4z"/>
<path d="M66.4 160.5h.4v.5h-.4z"/>
<path d="M56.8 154.5h.4v.5h-.4z"/>
<path d="M178 216.3h.4v.5h-.4z"/>
<path d="M182.1 216.3h.4v.5h-.4z"/>
<path d="M185.2 213.9h.4v.4h-.4z"/>
<path d="M188.7 216.3h.4v.5h-.4z"/>
<path d="M182.1 204.9h.4v.4h-.4z"/>
<path d="M179.2 198.9h.4v.4h-.4z"/>
<path d="M173.2 198.9h.4v.4h-.4z"/>
<path d="M203.1 219.9h.4v.4h-.4z"/>
<path d="M182.7 227.1h.4v.4h-.4z"/>
<path d="M194.1 242.1h.5v.4h-.5z"/>
<path d="M179.8 221.1h.4v.4h-.4z"/>
<path d="M189.3 238.5h.4v.4h-.4z"/>
<path d="M194.1 221.1h.5v.4h-.5z"/>
<path d="M205 221.1h.4v.4h-.4z"/>
<path d="M175.5 242.1h.4v.4h-.4z"/>
<path d="M170.2 242.1h.4v.4h-.4z"/>
<path d="M174.9 219.9h.4v.4h-.4z"/>
<path d="M173.7 221.1h.5v.4h-.5z"/>
<path d="M185.8 236h.4v.5h-.4z"/>
<path d="M170.8 237.3h.4v.5h-.4z"/>
<path d="M182.7 238.5h.4v.4h-.4z"/>
<path d="M178.6 238.5h.4v.4h-.4z"/>
<path d="M205 198.9h.4v.4h-.4z"/>
<path d="M193.6 198.9h.4v.4h-.4z"/>
<path d="M193.6 197.7h.4v.4h-.4z"/>
<path d="M193.6 219.9h.4v.4h-.4z"/>
<path d="M203.1 197.7h.4v.4h-.4z"/>
<path d="M173.2 176.7h.4v.4h-.4z"/>
<path d="M167.7 183.9h.4v.4h-.4z"/>
<path d="M167.7 192.9h.4v.4h-.4z"/>
<path d="M170.2 192.9h.4v.4h-.4z"/>
<path d="M169.6 175.5h.4v.4h-.4z"/>
<path d="M179.2 176.7h.4v.4h-.4z"/>
<path d="M174.9 175.5h.4v.4h-.4z"/>
<path d="M178 171.9h.4v.5h-.4z"/>
<path d="M174.3 153.3h.4v.5h-.4z"/>
<path d="M158.2 155.1h.4v.4h-.4z"/>
<path d="M167.7 161.7h.4v.4h-.4z"/>
<path d="M143.8 147.3h.4v.5h-.4z"/>
<path d="M148.6 147.3h.4v.5h-.4z"/>
<path d="M143.8 132.9h.4v.5h-.4z"/>
<path d="M148.6 141.3h.4v.4h-.4z"/>
<path d="M148.6 132.9h.4v.5h-.4z"/>
<path d="M144.4 169.5h.4v.4h-.4z"/>
<path d="M149.2 169.5h.4v.4h-.4z"/>
<path d="M153.9 175.5h.4v.4h-.4z"/>
<path d="M153.9 176.7h.4v.4h-.4z"/>
<path d="M158.2 177.3h.4v.4h-.4z"/>
<path d="M144.4 177.3h.4v.4h-.4z"/>
<path d="M167.7 170.7h.4v.4h-.4z"/>
<path d="M158.2 170.7h.4v.4h-.4z"/>
<path d="M149.2 185.7h.4v.4h-.4z"/>
<path d="M149.2 177.3h.4v.4h-.4z"/>
<path d="M153.9 154.5h.4v.5h-.4z"/>
<path d="M144.4 155.1h.4v.4h-.4z"/>
<path d="M153.3 153.3h.4v.5h-.4z"/>
<path d="M149.2 155.1h.4v.4h-.4z"/>
<path d="M157.6 148.5h.4v.4h-.4z"/>
<path d="M163.6 170.7h.4v.4h-.4z"/>
<path d="M170.2 170.7h.4v.4h-.4z"/>
<path d="M149.2 163.5h.4v.4h-.4z"/>
<path d="M163 148.5h.4v.4h-.4z"/>
<path d="M167.1 148.5h.4v.4h-.4z"/>
<path d="M153.3 132.3h.4v.5h-.4z"/>
<path d="M157.6 132.9h.4v.5h-.4z"/>
<path d="M167.1 139.5h.4v.5h-.4z"/>
<path d="M172.6 132.3h.4v.5h-.4z"/>
<path d="M178.6 132.3h.4v.5h-.4z"/>
<path d="M163.6 192.9h.4v.4h-.4z"/>
<path d="M158.2 192.9h.4v.4h-.4z"/>
<path d="M144.4 191.7h.4v.4h-.4z"/>
<path d="M153.9 197.7h.4v.4h-.4z"/>
<path d="M149.2 191.7h.4v.4h-.4z"/>
<path d="M153.9 198.9h.4v.4h-.4z"/>
<path d="M158.2 199.5h.4v.4h-.4z"/>
<path d="M170.2 215.1h.4v.5h-.4z"/>
<path d="M167.7 215.1h.4v.5h-.4z"/>
<path d="M167.7 206.1h.4v.4h-.4z"/>
<path d="M145 236h.4v.5h-.4z"/>
<path d="M138.9 242.1h.5v.4h-.5z"/>
<path d="M144.4 213.9h.4v.4h-.4z"/>
<path d="M149.8 236h.4v.5h-.4z"/>
<path d="M133.6 234.9h.4v.4h-.4z"/>
<path d="M154.6 221.1h.4v.4h-.4z"/>
<path d="M163.6 215.1h.4v.5h-.4z"/>
<path d="M158.2 215.1h.4v.5h-.4z"/>
<path d="M149.2 213.9h.4v.4h-.4z"/>
<path d="M149.8 221.6h.4v.5h-.4z"/>
<path d="M169.6 219.9h.4v.4h-.4z"/>
<path d="M158.8 221.6h.4v.5h-.4z"/>
<path d="M168.3 237.3h.4v.5h-.4z"/>
<path d="M164.2 237.3h.4v.5h-.4z"/>
<path d="M149.8 230.1h.4v.5h-.4z"/>
<path d="M154.6 242.1h.4v.4h-.4z"/>
<path d="M168.3 228.3h.4v.4h-.4z"/>
<path d="M158.8 237.3h.4v.5h-.4z"/>
<path d="M134.2 190.5h.4v.4h-.4z"/>
<path d="M128.2 190.5h.4v.4h-.4z"/>
<path d="M142 191.7h.4v.4h-.4z"/>
<path d="M145 221.6h.4v.5h-.4z"/>
<path d="M138.4 219.9h.4v.4h-.4z"/>
<path d="M140.8 221.6h.4v.5h-.4z"/>
<path d="M124.6 219.3h.4v.4h-.4z"/>
<path d="M125.1 218.7h.5v.4h-.5z"/>
<path d="M127.6 234.9h.4v.4h-.4z"/>
<path d="M134.2 221.6h.4v.5h-.4z"/>
<path d="M133.6 199.5h.4v.4h-.4z"/>
<path d="M140.2 199.5h.4v.4h-.4z"/>
<path d="M139.5 197.7h.4v.4h-.4z"/>
<path d="M127 212.7h.4v.4h-.4z"/>
<path d="M133 212.7h.4v.4h-.4z"/>
<path d="M144.4 199.5h.4v.4h-.4z"/>
<path d="M149.2 199.5h.4v.4h-.4z"/>
<path d="M153.9 219.9h.4v.4h-.4z"/>
<path d="M149.2 207.9h.4v.5h-.4z"/>
<path d="M141.4 147.3h.4v.5h-.4z"/>
<path d="M140.8 155.1h.4v.4h-.4z"/>
<path d="M134.2 168.3h.4v.5h-.4z"/>
<path d="M138.9 175.5h.5v.4h-.5z"/>
<path d="M134.8 177.3h.4v.4h-.4z"/>
<path d="M127.6 168.3h.4v.5h-.4z"/>
<path d="M133.6 168.3h.4v.5h-.4z"/>
<path d="M140.8 132.9h.4v.5h-.4z"/>
<path d="M134.2 132.9h.4v.5h-.4z"/>
<path d="M134.2 155.1h.4v.4h-.4z"/>
<path d="M133.6 146.1h.4v.5h-.4z"/>
<path d="M127.6 146.1h.4v.5h-.4z"/>
<path d="M138.9 153.3h.5v.5h-.5z"/>
<path d="M124.6 158.7h.4v.5h-.4z"/>
<path d="M125.1 159.9h.5v.5h-.5z"/>
<path d="M124.6 180.3h.4v.5h-.4z"/>
<path d="M125.1 181.5h.5v.5h-.5z"/>
<path d="M141.4 169.5h.4v.4h-.4z"/>
<path d="M141.4 177.3h.4v.4h-.4z"/>
<path d="M174.9 197.7h.4v.4h-.4z"/>
<path d="M169.6 197.7h.4v.4h-.4z"/>
<path d="M188.7 194.1h.4v.5h-.4z"/>
<path d="M178 194.1h.4v.5h-.4z"/>
<path d="M182.1 194.1h.4v.5h-.4z"/>
<path d="M185.2 191.7h.4v.4h-.4z"/>
<path d="M182.1 182.7h.4v.4h-.4z"/>
<path d="M203.1 175.5h.4v.4h-.4z"/>
<path d="M181.5 138.3h.4v.5h-.4z"/>
<path d="M193 132.3h.4v.5h-.4z"/>
<path d="M193.6 154.5h.4v.5h-.4z"/>
<path d="M188.1 149.7h.4v.4h-.4z"/>
<path d="M179.2 154.5h.4v.5h-.4z"/>
<path d="M169.6 148.5h.4v.4h-.4z"/>
<path d="M177.4 149.7h.4v.4h-.4z"/>
<path d="M169 153.3h.4v.5h-.4z"/>
<path d="M173.2 154.5h.4v.5h-.4z"/>
<path d="M182.1 160.5h.4v.5h-.4z"/>
<path d="M182.1 171.9h.4v.5h-.4z"/>
<path d="M193.6 175.5h.4v.4h-.4z"/>
<path d="M188.7 171.9h.4v.5h-.4z"/>
<path d="M185.2 169.5h.4v.4h-.4z"/>
<path d="M181.5 149.7h.4v.4h-.4z"/>
<path d="M184.6 147.3h.4v.5h-.4z"/>
<path d="M205 154.5h.4v.5h-.4z"/>
<path d="M8.8 132.3h.4v.5h-.4z"/>
<path d="M205 132.3h.4v.5h-.4z"/>
<path d="M6.4 109h.5v.4h-.5z"/>
<path d="M6.4 153.3h.5v.5h-.5z"/>
<path d="M193 153.3h.4v.5h-.4z"/>
<path d="M193 42.4h.4v.5h-.4z"/>
<path d="M203.1 153.3h.4v.5h-.4z"/>
<path d="M107.2 152.7h.4v.5h-.4z"/>
<path d="M101.2 152.7h.4v.5h-.4z"/>
<path d="M98.8 152.7h.4v.5h-.4z"/>
<path d="M117.9 153.9h.5v.5h-.5z"/>
<path d="M110.8 152.7h.4v.5h-.4z"/>
<path d="M117.9 141.3h.5v.4h-.5z"/>
<path d="M103.6 141.9h.4v.4h-.4z"/>
<path d="M95.2 141.9h.4v.4h-.4z"/>
<path d="M106.6 219.3h.4v.4h-.4z"/>
<path d="M77.2 50.8h.4v.4h-.4z"/>
<path d="M77.2 21.4h.4v.5h-.4z"/>
<path d="M141.4 21.4h.4v.5h-.4z"/>
<path d="M43 41.7h.4v.5h-.4z"/>
<path d="M43 64h.4v.4h-.4z"/>
<path d="M7.6 64h.4v.4h-.4z"/>
<path d="M43 86.2h.4v.4h-.4z"/>
<path d="M7.6 86.2h.4v.4h-.4z"/>
<path d="M43 108.4h.4v.4h-.4z"/>
<path d="M7.6 108.4h.4v.4h-.4z"/>
<path d="M43 130.5h.4v.5h-.4z"/>
<path d="M7.6 130.5h.4v.5h-.4z"/>
<path d="M43 152.7h.4v.5h-.4z"/>
<path d="M7.6 152.7h.4v.5h-.4z"/>
<path d="M43 219.3h.4v.4h-.4z"/>
<path d="M43 174.9h.4v.5h-.4z"/>
<path d="M8.8 174.9h.4v.5h-.4z"/>
<path d="M8.8 197.1h.4v.4h-.4z"/>
<path d="M43 197.1h.4v.4h-.4z"/>
<path d="M7.6 219.3h.4v.4h-.4z"/>
<path d="M43 241.5h.4v.4h-.4z"/>
<path d="M83.8 241.5h.4v.4h-.4z"/>
<path d="M92.2 221.6h.4v.5h-.4z"/>
<path d="M127.6 221.6h.4v.5h-.4z"/>
<path d="M168.3 221.6h.4v.5h-.4z"/>
<path d="M167.1 22h.4v.4h-.4z"/>
<path d="M167.7 44.2h.4v.4h-.4z"/>
<path d="M203.7 44.2h.4v.4h-.4z"/>
<path d="M167.7 66.4h.4v.4h-.4z"/>
<path d="M203.7 66.4h.4v.4h-.4z"/>
<path d="M167.7 88.6h.4v.4h-.4z"/>
<path d="M203.7 88.6h.4v.4h-.4z"/>
<path d="M168.3 110.7h.4v.5h-.4z"/>
<path d="M203.7 110.7h.4v.5h-.4z"/>
<path d="M167.1 132.9h.4v.5h-.4z"/>
<path d="M203.7 132.9h.4v.5h-.4z"/>
<path d="M167.7 177.3h.4v.4h-.4z"/>
<path d="M203.7 177.3h.4v.4h-.4z"/>
<path d="M167.7 199.5h.4v.4h-.4z"/>
<path d="M203.7 199.5h.4v.4h-.4z"/>
<path d="M203.1 42.4h.4v.5h-.4z"/>
<path d="M6.4 42.4h.5v.5h-.5z"/>
<path d="M134.2 242.1h.4v.4h-.4z"/>
</g>
<g fill="none" stroke="#006665" stroke-width=".2">
<path d="M10.5 25.3h.2l.1-.2-.3-.1v.6M10.5 25.3l.3 .3M11 25.2l.1-.2v.6M11 25.6h.4M12.3 25.4h.6v.2h-.6zM12.3 24.8h.5l.1 .2-.3 .1-.3-.1zM12.3 24.3l.5-.1 .1 .2-.5 .1zM12.9 26h-.6l.2 .2M12.9 25.9v.3M16 29.7v.6M16.6 29.7v.6l-.3-.6v.6M16.8 30.3l.3-.6 .1 .6"/>
<path d="M16.9 30.1h.2M17 24.8v.6h.3v-.6M17.5 29.9v-.2l.2 .1-.3 .2 .1 .3 .2-.1v-.3M17.6 25l.1-.2v.6M17.6 25.4h.3M18 29.8l.2-.1 .1 .2-.4 .4h.4M18.5 29.7h.4l-.2 .2 .2 .1v.2h-.4M21.9 28.1l.2-.2v.6M21.9 28.5h.3M22 26.9l-.3-.1-.1 .2 .1 .4 .3-.1M22.2 26.9l.4-.1v.3l-.4 .3h.4M22.5 28.1v.3h.2"/>
<path d="M22.7 28.1v.4M23.1 28.2h.1M23.3 27.9h-.2v.6M23.3 24h.3l.1-.3h-.4v.6M23.5 24l.2 .3M23.6 25h.3l-.2 .2 .2 .1v.2h-.3M23.9 23.7h.4l-.4 .6h.4M24.1 31.6h.3v-.2h-.3v.6M24.3 25v.6M24.3 25.4l.1 .2M24.3 31.6l.1 .4M24.4 25.2l-.1 .2"/>
<path d="M24.7 31.5l.1-.1v.6M24.7 32h.3M25.3 31.4a.3 .3 0 0 1 .3 .2 .3 .3 0 0 1-.2 .4zM25.5 33.1v.3h.3v-.3h.3l-.1 .3M25.5 32.8h.6M25.7 32.6l.3 .2M26 33.7h.1M26.1 34.1h-.6l.2 .1M26.1 33.9v.3M26.1 32.6l-.2 .1M27.2 34.2h.3l.1 .2-.5 .4h.5M27.8 34.4v.4h.3"/>
<path d="M28.1 34.4v.4M28.2 32.4h-.4v.4h.4M28.3 34.5h.3M28.7 34.2h-.4v.6M28.7 32.3h-.2l-.1 .5h.3v-.2h-.3M29.1 27h-.4v.4l.4 .1M29.2 28.1l.2-.2v.6M29.2 28.5h.4M29.3 26.9h.4l-.3 .2h.2l.1 .3-.4 .1M29.8 28.1v.3h.3M30.1 28.1v.4M30.2 25h.3l-.1 .2 .1 .1v.2h-.3"/>
<path d="M30.2 24.1h.3v-.3l-.3-.1v.7M30.4 28.2h.1M30.4 24.1l.1 .3M30.6 27.9h-.2v.6M30.7 23.7h.4l-.2 .3 .2 .3-.2 .1-.2-.1M30.8 25v.6M30.9 25.4l.1 .2M31 25.2l-.2 .2M35.9 30.8v.6h.3M36.2 36v.6l.3-.1v-.5M36.4 31h.2M36.7 30.8h-.3v.6"/>
<path d="M36.8 25.9l.1 .6 .2-.2v-.4M36.9 30.8h.3l-.2 .1 .2 .1v.3h-.3M37 36l-.2 .2v.4l.3-.1-.1-.2-.2 .1M37.4 25.9h.3v.2l-.3 .4h.3M37.7 30.8h-.2v.2l.1-.1 .2 .3-.2 .2-.1-.1M38 30.8h.4l-.3 .6M41.4 37.2h.2l.1-.3h-.3v.6M41.5 30.7h.3l.1-.2-.4-.1v.5M41.5 37.2l.2 .3M41.6 30.7l.3 .2M42 37l.1-.1v.6M42 37.5h.3"/>
<path d="M42.2 30.6l-.2-.1 .3-.1 .1 .2-.4 .2 .1 .1h.3l-.1-.3M42.5 37l.3-.1 .1 .1-.4 .5h.4M42.9 38.8l.5-.1 .1 .4h-.5zM42.9 38.2l.4-.1 .2 .1v.3h-.5zM42.9 32.1h.6M42.9 31.8l.3 .3M43.5 39.5h-.6l.2 .2M43.5 32.6h-.6l.2 .1M43.5 32.4v.3M43.5 39.3v.4M43.5 31.8l-.4 .2M44.3 26.2l.2-.2v.6"/>
<path d="M44.3 26.6h.4M44.7 25.3h.3v-.3h-.3v.6M44.8 25.3l.2 .3M44.9 26.1h.3v.5h-.3zM45.4 24.9l-.1 .5h.4M45.5 26v.6M45.6 25.2v.4M45.8 26.3l-.3 .2 .3 .1M49 26.2l.1-.2v.6M49 26.6h.3M49.4 25.2h.3v-.2l-.3-.2v.6M49.5 25.2l.2 .2"/>
<path d="M49.7 26l.2 .2-.1 .4-.2-.1v-.3zM50 31.2l.2 .3v.3h-.3l-.1-.2zM50.2 26v.6M50.2 24.8h-.2l-.1 .4 .3-.1v.3h-.3M50.2 26.5l.2 .1M50.4 26.3l-.2 .2M50.5 31.8h.1M50.7 23.7h.3l-.1 .6-.2-.1zM50.8 31.3l.1-.1 .2 .2-.4 .4h.4M51.2 29.5h-.4v.4h.4M51.3 31.3h.3l-.3 .5h.3M51.3 24.2v.1"/>
<path d="M51.5 23.7h.4v.2l-.4 .4h.4M51.5 22.6h-.3v.5l.3 .1M51.8 29.4h-.4v.3h.4l-.1 .3-.3-.1M51.8 22.7l.1-.1v.6M51.8 23.2h.3M51.9 31.5v.3h.2v-.3M52.1 23.7h.4l-.4 .6h.4M52.5 31.5h.1M52.7 31.2h-.2v.6M52.7 23.8v.5l.3-.1M53 23.8v.5M53.2 23.9h.3"/>
<path d="M53.6 23.7h-.4v.6M57.9 26.9v.6h.3v-.6M58.5 26.9h.3l-.2 .2h.2v.4h-.3M58.5 25.9v.6h.4M59.1 26.1h.1M59.3 25.9h-.2v.6M59.5 25.9h.4l-.3 .1 .3 .3-.2 .2-.2-.1M59.6 34.9l.4-.1-.1-.2h-.3v.6M59.7 34.9l.3 .3M60.2 34.8l.1-.2v.6M60.2 35.2h.3M60.2 30.1h.3l.1-.2-.4-.1v.6"/>
<path d="M60.3 30.1l.3 .3M60.4 25.9h-.2l-.1 .2 .2-.1 .1 .4h-.3M60.7 25.9h.4l-.4 .6M60.7 34.8l.2-.2v.6M60.7 29.8h.5l-.3 .6M60.7 35.2h.4M61.5 35.9h.6M61.6 31.4h.6M61.7 35.6l.2 .3M61.8 31.1l.2 .3 .2-.3M62.1 36.3h-.6l.2 .1M62.1 36.1v.3"/>
<path d="M62.1 35.6l-.3 .2M62.2 31.8h-.6l.2 .2M62.2 31.6v.4M63.4 27.5l.1-.2v.6M63.4 27.9h.3M63.6 26.6h.4l-.1-.3h-.3v.6M63.7 34.3l.3 .1v.5h-.3l-.1-.1zM63.8 26.6l.2 .3M64 27.4h.3v.3l-.2 .2-.1-.2zM64.2 34.9h.1M64.5 26.3l-.3 .2v.4h.4l-.1-.4-.3 .1M64.6 34.4l.2-.1 .1 .2-.4 .4h.4"/>
<path d="M64.6 27.3v.6M64.6 27.6l.2 .3M64.7 32.4l-.2-.1-.1 .2 .1 .4 .2-.1M64.8 27.5l-.2 .2M65 32.3h.3l-.2 .6M65.1 34.4l.3-.1v.3l-.3 .3h.3M65.7 34.6v.3h.2v-.3M66.3 34.7h.1M66.5 34.3h-.2v.6M73.4 28.1v.6h.3v-.6M73.5 25.6v.6h.4M74 25.9h.2"/>
<path d="M74.1 28.1l-.1 .4h.3M74.2 28.3v.4M74.3 25.6h-.3v.6M74.5 25.6h.4l-.3 .2 .3 .2-.2 .2-.2-.1M75.4 25.6h-.3v.3l.2-.1 .2 .2-.2 .2-.2-.1M75.6 25.6h.5l-.3 .6M76.8 36.3v-.6l.2 .4 .2-.4v.6M77.9 35.7h-.3l-.2 .2 .1 .3h.4M78.1 35.9h.3v-.2h-.3v.6M78.8 35.6l-.1 .4h.3M79 27.9l-.4 .1v.3l.2 .2 .2-.1M79 35.9v.4"/>
<path d="M79.2 35.9l.2-.2v.6M79.2 36.3h.3M79.4 27.8l-.2 .4h.3M79.5 28.1v.4M80.1 35.7l-.3 .1v.4h.3v-.3l-.3 .1M80.4 27.2l.2-.1v.5M80.4 35.9l.2-.2v.6M80.4 27.6h.3M80.4 36.3h.3M81 27.2l.1 .4h.2M81 34l.1 .6 .2-.1v-.5M81.3 27.2v.4"/>
<path d="M81.6 27.3h.1M81.8 27.1h-.2v.5M81.9 34h-.3v.2h.3l-.1 .4-.2-.1M82.4 31.3l.4-.1-.2-.3h-.2v.7M82.5 31.3l.3 .3M83.4 31.3h-.5l.2-.4 .3 .2v.3l-.4 .2M83.7 33v.3h.2v-.3l.4 .1-.1 .2M83.7 32.5l.3-.1 .3 .1v.1l-.6 .1zM83.7 32.1h.6M83.9 32l.2 .1M84.3 33.7h-.6l.2 .2M84.3 33.6v.3"/>
<path d="M84.3 32l-.3 .1M127.4 32.9h.2l.1-.3h-.3v.5M127.5 31.4v.2l.2 .1v-.3h.4l-.1 .3M127.5 30.9l.5-.1 .1 .2-.5 .1zM127.5 30.5h.6M127.5 32.9l.2 .2M127.6 30.3l.3 .2M127.9 32.7l.2-.1v.5M127.9 33.1h.4M128.1 32h-.6l.1 .2M128.1 31.9v.3M128.1 30.3l-.3 .1"/>
<path d="M128.7 32.6l-.2 .4h.4M128.8 32.7v.4M129.1 32.7l.1-.1v.5M129.1 33.1h.3M129.9 36.7l.3-.2v.6M129.9 29.5l.1 .7 .3-.2v-.5M129.9 37.1h.4M130.4 29.5h.5l-.3 .7M130.6 36.7v.3h.3M130.9 36.7v.4M131.1 28.5v-.6l.2 .4 .2-.4v.6M131.1 29.6l.2-.1 .1 .3-.4 .4h.4"/>
<path d="M131.1 36.8h.2M131.4 36.5h-.3v.6M132.1 27.9l-.3 .1v.4h.3M132.3 35.7l-.3 .1v.3l.1 .2 .2-.1M132.4 28.2h.3v-.3h-.3v.6M132.6 35.9l-.1-.2h.4l-.1 .2h-.3l.1 .4 .3-.1-.1-.3M133.1 27.8l-.1 .4h.3M133.1 35.9l.2-.2v.6M133.1 36.3h.4M133.2 28.1v.4M133.6 28.1l.1-.2v.6M133.6 28.5h.3"/>
<path d="M134.4 27.9h-.2l-.1 .3v.1l.2 .2v-.4l-.2 .1M134.7 28.1l.1-.2v.6M134.7 28.5h.3M135.8 38v.6h.3M136.3 38.2h.2M136.6 38h-.3v.6M136.8 38h.3l-.2 .1 .2 .1v.3h-.3M137.2 35.4l.1 .6h.2v-.6M137.6 38h-.2v.2l.1-.1 .2 .3-.2 .2-.1-.1M137.8 35.4h.4l-.2 .6M137.9 38h.4l-.3 .6M138.4 35.4h.3l-.1 .3h.1v.3l-.3-.1"/>
<path d="M144.2 29.2l.3 .2-.1 .4h-.3v-.2zM144.7 29.8h.1M145 29.3l.2-.1 .1 .1-.4 .5h.4M145.1 31.3l-.1-.1a.33 .33 0 0 0-.3 .2 .33 .33 0 0 0 .1 .4h.3M145.4 31.5l-.1-.2 .2-.1 .2 .2-.4 .1v.3l.4-.1-.2-.2M145.5 29.3h.3l-.3 .5h.3M145.5 37.5h.3v-.3h-.3v.6M145.6 37.5l.2 .3M145.8 36.4l.2-.1v.6M145.8 36.9h.4M146 31.2l-.2 .4h.5M146.1 29.4l.1 .4h.1v-.4"/>
<path d="M146.1 37.4l.2-.2v.6M146.1 37.8h.3M146.2 31.5v.3M146.4 36.3h.3l-.1 .6h-.2l-.1-.3zM146.6 37.2h.3l-.1 .3h.1v.3h-.3M146.7 29.5h.2M146.9 29.2h-.2v.6M146.9 36.3v.6M147 36.6l.2 .3M147.2 36.4l-.3 .3M147.3 37.5l-.1-.2 .2-.1 .1 .3h-.3v.3h.3l-.1-.3M148.3 32.5h.6"/>
<path d="M148.4 34.1h.1l.2-.3-.3-.1v.6M148.5 28h.6M148.5 34.1l.2 .2M148.5 32.2l.2 .3M148.6 27.7l.3 .3M148.9 32.9h-.6l.2 .2M148.9 33.9l.2-.2v.6M148.9 32.7v.4M148.9 32.2l-.2 .2M148.9 34.3h.3M149 29.3l.3-.1-.2-.3h-.1v.6M149.1 28.4h-.6l.1 .2"/>
<path d="M149.1 28.2v.4M149.1 27.7l-.3 .2M149.1 29.3l.2 .2M149.5 33.7h.3l-.2 .3h.2v.3l-.3-.1M149.5 29.1l.2-.2v.6M149.5 29.5h.4M149.6 37.7v.6h.3M150.1 38h.2M150.2 28.9l-.1 .4h.4M150.4 37.7h-.3v.6M150.4 34l-.3 .1v-.3h.3l-.1 .5h-.1M150.4 29.2v.3"/>
<path d="M150.6 37.7h.3l-.2 .3h.2v.2h-.3M150.7 28.9h.3l-.2 .3 .2 .1v.2h-.3M151.4 37.7h-.2v.3h.2l.1 .2h-.3M151.5 36.6l.1 .6 .2-.1v-.5M151.7 37.7h.4l-.3 .6M152.1 36.6h.3l-.2 .6M152.7 36.8l.2-.2v.6M152.7 37.2h.3M157.1 39.9h.3v.5h-.3zM157.9 39.9h.4l-.4 .5h.4M157.9 32.3l.3 .1-.1 .5h-.2v-.3zM158.5 32.8v.1"/>
<path d="M158.5 39.9l.2-.1 .2 .2-.4 .4h.4M158.6 34.2h-.3v.4l.3 .1M158.8 32.4l.2-.1 .1 .2-.4 .4h.4M159 34.3v-.2l.2 .1-.3 .2v.3l.3-.1-.2-.3M159.3 32.4l.3-.1v.3l-.3 .3h.3M159.4 34.2h.3l-.3 .5h.3M159.7 39h.4v-.3h-.4v.5M159.9 39.8h-.3v.6M159.9 32.5v.3h.2M159.9 39l.2 .2M160.1 37.6l.3-.1v.6M160.1 38.1h.5"/>
<path d="M160.1 32.5v.4M160.3 38.8l.2-.1v.5M160.3 39.2h.4M160.5 32.6h.2M160.7 32.3h-.2v.6M160.8 37.5h.3l-.1 .6h-.2l-.1-.3zM160.9 38.7h.3l-.1 .2 .1 .1v.2h-.3M161.3 37.5v.6M161.4 38.7h.4l-.2 .5M161.4 37.8l.2 .3M161.6 37.6l-.3 .3M164.5 38.8h.2l.1-.1-.3-.1v.6"/>
<path d="M164.5 38.8l.3 .4M164.9 37.6l.2-.1v.6M164.9 38.1h.3M165 38.7l.1-.1v.6M165 39.2h.3M165.5 37.5h.2v.6h-.2zM165.6 38.6h.3l-.2 .1 .2 .1v.3h-.3M166.1 37.5v.6M166.1 37.8l.1 .3M166.2 37.6l-.1 .3M166.4 38.6l-.2 .1v.4h.3l-.1-.4-.2 .2M167 25.3l.2-.2h.3l.1 .3h-.4z"/>
<path d="M167 24.7l.2-.2h.3l.1 .3h-.5zM167 31.8h.6M167 31.5l.3 .3M167.1 33.5l.3-.2-.1-.2h-.2v.6M167.2 27h.3v-.3l-.3-.1v.7M167.2 33.5l.2 .2M167.3 27l.2 .3M167.6 32.2h-.6l.2 .2M167.6 25.9h-.6l.2 .1M167.6 33.3l.2-.2v.6M167.6 25.7v.3M167.6 32v.4"/>
<path d="M167.6 31.5l-.3 .2M167.6 33.7h.3M167.8 26.9l.1-.3v.7M167.8 27.3h.3M168.4 33.1l-.2 .5h.4M168.4 26.6v.5h.3M168.5 33.3v.4M168.6 26.9v.4M168.8 33.2h.3l-.1 .5h-.2zM169 26.6l-.1 .5h.4M169.2 26.9v.4M172.3 32.8v.6h.3"/>
<path d="M172.6 37.7l.1 .6h.2v-.6M172.8 33.1h.1M173 32.8h-.2v.6M173.2 32.8h.4l-.2 .2 .2 .2-.2 .2-.2-.1M173.2 27.5l.1 .6h.2v-.6M173.2 37.7h.4l-.2 .6M173.8 27.5h.4l-.3 .6M173.8 37.8l.3-.1-.1 .6-.2-.1zM174.1 32.8h-.2l-.1 .3 .2-.1 .1 .3h-.3M174.4 32.8h.4l-.3 .6M174.5 27.5l-.1 .4h.4M174.7 27.7v.4"/>
<path d="M179.5 38.6h.4l-.2 .1 .2 .1v.3h-.4M179.5 39.9l.2-.1v.5M180 35.9l.1-.2v.6M180 36.3h.3M180 39.8h.5l-.3 .2 .3 .1v.2h-.5M180.1 38.6v.6M180.2 38.9l.2 .3M180.4 38.7l-.3 .3M180.6 35.9v.3h.2M180.8 35.9v.4M181 39.8h-.3l-.1 .2h.4v.3h-.4M181 36.7l-.3-.1-.1 .2 .1 .4 .3-.1"/>
<path d="M181.1 35.9h.2M181.3 36.9l-.1-.2 .4-.1v.3l-.4 .1 .1 .2h.3l-.1-.3M181.4 35.7h-.3v.6M181.7 31.3h-.4v.4l.4 .1M181.8 36.7h.4l-.1 .5-.3-.1zM182 29.3h.3v.3l-.3 .3h.3M182 31.5v-.3l.2 .2-.3 .1v.3l.3-.1-.1-.2M182.4 31.2h.4l-.2 .3h.2v.3h-.4M182.6 29.5v.3h.2M182.8 29.5v.4M183.1 29.6h.2M183.4 29.3h-.3v.6"/>
<path d="M184.4 30.4v.3l.3 .1v-.4h.3v.4M184.4 32.5h.4v-.3h-.4v.6M184.4 30.2h.6M184.6 29.9l.3 .3M184.6 32.5l.2 .3M185 31h.1M185 31.5h-.6l.2 .1M185 32.4l.2-.2v.6M185 32.8h.4M185 31.3v.3M185 29.9l-.2 .2M185.7 32.1l-.1 .5h.4"/>
<path d="M185.9 32.4v.4M186.1 38.6h.4l-.2 .1 .2 .1v.3h-.4M186.1 32.2h.4v.3l-.4 .3h.4M186.7 38.6v.6M186.8 38.9l.2 .3M186.9 39.8h.3l-.1 .3h.1v.3h-.3M187 38.7l-.3 .3M187.3 35.9l.2-.2v.6M187.3 36.3h.4M187.7 39.8l-.2 .5h.3M187.9 35.9v.3h.3M188.1 36.8h-.4v.5h.4"/>
<path d="M188.2 35.9v.4M188.3 36.7h.4l-.3 .7M188.4 35.9h.3M188.8 35.7h-.4v.6M189.3 37h-.5l.2-.3 .3 .2v.2l-.4 .3M191.7 33.8v.7M192.3 33.8v.7l-.3-.7v.7M192.4 38.7v.5h.3v-.5M192.6 34.5l.1-.7 .2 .7M192.6 34.3h.3M193.3 34.2l-.2-.2 .2-.2 .2 .2-.4 .2 .2 .3 .2-.2-.2-.1M193.3 38.7h-.2l-.1 .1v.4h.3v-.3l-.3 .1"/>
<path d="M193.7 33.9h.3v.3l-.3 .3h.3M193.9 38.9l-.2 .2-.1-.4h.3v.5h-.2M194.3 33.8h.3l-.2 .3 .2 .1v.2h-.3M197.7 39.2l.3-.1 .2 .2-.5 .1zM197.7 38.6l.5 .1a.3 .3 0 0 1-.3 .2 .3 .3 0 0 1-.2-.3zM197.7 38h.5v.1l-.1 .2h-.4zM198.2 38.8h.2l.1-.1-.3-.1v.6M198.2 39.8h-.5l.1 .2M198.2 39.7v.3M198.2 38.8l.3 .4M198.7 38.7l.1-.1v.6M198.7 39.2h.3"/>
<path d="M199.3 38.6h.3l-.2 .1 .2 .1v.3h-.3M199.8 38.6h.4l-.2 .1 .2 .1v.3h-.4M10.5 47.5h.2l.1-.2-.3-.1v.6M10.5 47.5l.3 .3M11 47.4l.1-.2v.6M11 47.8h.4M11.6 47.2h.3l-.2 .2 .2 .1v.2h-.3M12.3 47.6l.5-.1 .1 .3-.3 .1-.3-.1zM12.3 47l.5-.1 .1 .3-.5 .1zM12.3 46.4h.5l.1 .2-.5 .1zM12.9 48.2h-.6l.2 .2M12.9 48v.4"/>
<path d="M16 51.9v.6M16.6 51.9v.6l-.3-.6v.6M16.8 52.5l.3-.6 .1 .6M16.9 52.3h.2M17 47v.6h.3v-.6M17.5 52.1v-.2h.2l-.3 .3 .1 .3 .2-.1v-.3M17.9 47.3l-.2 .2-.1-.4h.3v.4l-.2 .1M18 51.9h.2l.1 .2-.4 .4h.4M18.5 51.9h.4l-.2 .2h.1l.1 .3h-.4M21.9 50.2l.2-.1v.6M21.9 50.7h.3M22 49.1l-.3-.1-.1 .1 .1 .5 .3-.1"/>
<path d="M22.5 50.2v.4h.2M22.6 49.2l-.3 .1-.1-.2 .4-.1v.4l-.3 .2M22.7 50.2v.5M23.1 46.2h.2l.1-.3-.3-.1v.6M23.1 50.3h.1M23.2 46.2l.2 .2M23.3 50.1h-.2v.6M23.6 47.2h.3l-.2 .2 .2 .1v.2h-.3M23.7 46l.1-.2v.6M23.7 46.4h.3M24.1 53.9h.2l.1-.3h-.3v.5M24.3 47.2v.6"/>
<path d="M24.3 47.5l.1 .3M24.3 53.9l.1 .2M24.3 45.8l-.1 .5h.4M24.4 47.4l-.1 .2M24.5 46.1v.3M24.7 53.6h.3v.2l-.3 .3h.3M25.3 53.6h.2l.1 .1-.4 .4h.4M25.5 55.2v.4h.3v-.4l.3 .1-.1 .3M25.5 55h.6M25.7 54.7l.3 .3M26 55.8h.1M26.1 56.3h-.6l.2 .1"/>
<path d="M26.1 56.1v.3M26.1 54.7l-.2 .2M27.2 56.4h.3l.1 .2-.5 .4h.5M27.8 56.6v.4l.3-.1M28.1 56.6v.4M28.2 54.6h-.4v.4l.4 .1M28.3 56.7h.3M28.4 54.7l.2-.2v.6M28.4 55.1h.3M28.7 56.4h-.4v.6M28.8 49.1h-.1l-.3 .2 .2 .4h.2M28.9 54.5h.4l-.2 .2h.2v.3l-.4 .1"/>
<path d="M29 49.2l.2-.1v.6M29 49.7h.3M29.2 50.2l.2-.1v.6M29.2 50.7h.4M29.8 49.1h.1v.6l-.3-.1v-.4zM29.8 50.2v.4h.3M29.9 46.3h.3l.1-.2-.4-.1v.6M30 46.3l.3 .3M30.1 50.2v.5M30.2 47.2h.3l-.1 .2 .1 .1v.2h-.3M30.4 50.3h.1M30.4 46.2l.2-.2v.6"/>
<path d="M30.4 46.6h.4M30.6 50.1h-.2v.6M30.8 47.2v.6M30.9 47.5l.1 .3M31 47.4l-.2 .2M31.4 46h-.4v.3l.3-.1 .1 .3h-.4M35.9 53v.6h.3M35.9 58.2v.6h.3v-.6M36.4 53.2h.2M36.4 48v.5l.2 .1h.2v-.6M36.4 58.4l.2-.2v.6M36.4 58.8h.4"/>
<path d="M36.7 53h-.3v.6M36.9 53h.3l-.2 .1 .2 .1v.3h-.3M37 48.2l.3-.2v.6M37 48.6h.5M37.2 58.2l-.2 .4h.5M37.4 58.4v.4M37.7 53h-.2v.2l.1-.1 .2 .3-.2 .2-.1-.1M37.7 48h.3l-.1 .6-.3-.2zM38 53h.4l-.3 .6M41.4 59.4h.2l.1-.3h-.3v.5M41.5 52.9h.3l.1-.2-.4-.2v.7M41.5 59.4l.2 .2"/>
<path d="M41.6 52.9l.3 .3M42 59.1h.3l-.3 .5h.3M42 52.6h.4v.3l-.4 .3h.4M42.6 59.1l-.1 .4h.4M42.8 52.5l.2 .1v.5l-.2 .1-.2-.2v-.3zM42.8 59.2v.4M42.9 54.3h.6M42.9 54l.3 .3M43.5 54.7h-.6l.2 .2M43.5 54.6v.3M43.5 54l-.4 .2M44.3 48.5l.2-.3v.7"/>
<path d="M44.3 48.9h.4M44.4 47.5h.3v-.3h-.3v.6M44.6 47.5l.1 .3M45 48.2a.35 .35 0 0 1 .3 .4 .35 .35 0 0 1-.3 .3zM45 47.4l.2-.2v.6M45 47.8h.3M45.5 48.2v.7M45.5 48.6l.3 .3M45.8 48.5l-.3 .2M45.8 47.2l-.2 .1v.4l.2 .1 .1-.2-.1-.2-.2 .1M49 48.5l.1-.3v.7M49 48.9h.3"/>
<path d="M49.1 47.4h.3v-.3l-.3-.1v.6M49.2 47.4l.2 .2M49.7 47.2l.1-.2v.6M49.7 47.6h.3M49.7 48.2l.2 .2v.3l-.2 .2-.1-.2v-.3zM50 53.4l.2 .2v.4h-.3l-.1-.2zM50.2 47h.4l-.3 .6M50.2 48.2v.7M50.2 48.6l.2 .3M50.4 48.5l-.2 .2M50.5 54h.1M50.7 45.9h.3v.5h-.3z"/>
<path d="M50.8 53.5l.1-.1 .2 .2-.4 .4h.4M51.2 51.7h-.4v.4l.4 .1M51.3 53.5h.3l-.3 .5h.3M51.3 46.4h.1M51.4 51.8l.2-.2v.6M51.4 52.2h.4M51.5 45.9l.4-.1v.3l-.4 .3h.4M51.5 44.8h-.3v.5h.3M51.9 53.6v.4h.2v-.4M51.9 45l-.1-.2 .1-.1 .2 .2-.3 .2v.2h.2l.1-.1-.2-.2M52 51.7l.3-.1 .1 .2-.5 .4h.5M52.1 45.9h.4l-.4 .5h.4"/>
<path d="M52.5 53.7h.1M52.7 53.4h-.2v.6M52.7 46.1v.3h.3v-.3M53.2 46.2h.3M53.6 45.8h-.4v.6M57.6 49.1v.6l.4-.1v-.5M58.2 49.2l.2-.1v.6M58.2 49.7h.3M58.5 48v.6h.4M58.8 49.2l.2-.1v.6M58.8 49.7h.3M59.1 48.3h.1"/>
<path d="M59.3 48h-.2v.6M59.5 48h.4l-.3 .2 .3 .3-.2 .1h-.2M59.6 57.1l.4-.2-.1-.1h-.3v.6M59.7 57.1l.3 .3M60.2 56.9l.3-.1v.2l-.3 .4h.3M60.2 52.3l.4-.1-.2-.3h-.2v.6M60.3 52.3l.3 .2M60.4 48h-.2l-.1 .3 .2-.1 .1 .4h-.3M60.7 48h.4l-.4 .6M60.7 56.8h.4l-.2 .2h.2v.3h-.4M60.7 52.1l.2-.2v.6M60.7 52.5h.4"/>
<path d="M61.5 58h.6M61.6 53.6h.6M61.7 52.2l-.3 .2-.1-.4h.4v.5h-.3M61.7 57.8l.2 .2M61.8 53.4l.2 .2 .2-.2M62.1 58.5h-.6l.2 .1M62.1 58.3v.3M62.1 57.8l-.3 .2M62.2 54h-.6l.2 .1M62.2 53.8v.3M63.4 49.7l.1-.2v.6M63.4 48.8h.2l.1-.2-.3-.1v.6"/>
<path d="M63.4 50.1h.3M63.5 48.8l.2 .3M63.8 56.5l.2 .1v.5h-.3l-.1-.2zM64 49.6h.3v.3l-.2 .2-.1-.2zM64 48.6l.1-.1v.6M64 49.1h.3M64.2 57.1h.1M64.6 56.6l.1-.1 .2 .2-.4 .4h.4M64.6 49.5v.6M64.6 48.7l-.1-.1 .2-.1 .1 .2-.3 .2 .1 .2h.2l-.1-.4M64.6 49.8l.2 .3M64.7 54.6l-.2-.1-.1 .2v.3l.3 .1"/>
<path d="M64.8 49.7l-.2 .2M65 54.7l.2-.2v.6M65 55.1h.3M65.1 56.6h.3l-.3 .5h.3M65.7 56.8v.3h.2v-.3M65.7 54.5l-.1 .4h.3M65.8 54.7v.4M66.3 56.9h.1M66.5 56.5h-.2v.6M72.4 50.3v.5l.2 .1 .2-.1v-.5M72.9 47.8v.6h.4M73 50.5l.3-.2v.6"/>
<path d="M73 50.9h.4M73.4 48h.2M73.6 50.3h.4v.3l-.4 .3h.4M73.7 47.8h-.3v.6M73.9 47.8h.4l-.3 .2h.2l.1 .3h-.4M74.8 47.8h-.3v.2h.3v.4l-.3-.1M75.1 47.8h.4l-.4 .6M76.2 58.5v-.6l.2 .4 .2-.4v.6M77.3 57.9h-.3a.28 .28 0 0 0-.1 .4 .28 .28 0 0 0 .4 .1M77.5 58.2h.2l.2-.2-.4-.1v.6M78.1 50.1l-.3 .1v.4h.3M78.2 57.8l-.2 .5h.4"/>
<path d="M78.4 50.2l.1-.1v.6M78.4 58v.5M78.4 50.7h.3M78.6 58l.2-.1v.6M78.6 58.5h.4M78.9 50.2l.1-.1v.6M78.9 50.7h.3M79.5 57.9l-.3 .1v.4h.3v-.3l-.3 .1M79.8 58l.2-.1v.6M79.8 49.4l.2-.2v.6M79.8 56.2l.1 .6 .2-.1v-.5M79.8 58.5h.3"/>
<path d="M79.8 49.8h.3M80.4 49.4v.3h.2M80.4 56.3l.2-.1v.6M80.4 56.8h.3M80.6 49.4v.4M81 56.2h.3l-.1 .2h.1v.3h-.3M81 49.5h.2M81.2 49.2h-.2v.6M81.8 53.5h.3l.1-.2-.4-.1v.6M81.9 53.5l.3 .3M82.3 53.2h.4v.3l-.4 .3h.4M82.9 53.4l.2-.2v.6"/>
<path d="M82.9 53.8h.4M83.1 55.2v.3h.3l-.1-.2 .2-.1 .2 .1-.1 .2M83.1 54.7l.3-.1a.22 .22 0 0 1 .3 .2 .22 .22 0 0 1-.3 .2l-.3-.1zM83.1 54.3h.6M83.3 54.1l.2 .2M83.7 55.9h-.6l.2 .2M83.7 55.8v.3M83.7 54.1l-.3 .2M127.4 55.1h.2l.1-.3-.3-.1v.6M127.5 53.6v.2l.2 .1v-.3h.4l-.1 .3M127.5 53h.5l.1 .2-.5 .1zM127.5 52.7h.6"/>
<path d="M127.5 55.1l.2 .2M127.6 52.5l.3 .2M127.9 54.9l.2-.2v.6M127.9 55.3h.4M128.1 54.2h-.6l.1 .2M128.1 54.1v.3M128.1 52.5l-.3 .1M128.8 54.7h-.2l-.1 .3h.3v.3l-.3-.1M129.1 54.7h.3l-.2 .3h.2v.2h-.3M129.9 58.9l.3-.2v.6M129.9 51.8l.1 .6 .3-.2v-.4M129.9 59.3h.4"/>
<path d="M130.4 51.8h.5l-.3 .6M130.6 58.9v.3h.3M130.9 58.9v.4M131.1 50.7v-.6l.2 .4 .2-.4v.6M131.1 59h.2M131.2 52l-.1-.2 .3 .1-.3 .1 .1 .4 .2-.2-.1-.2M131.4 58.7h-.3v.6M132.1 50.1l-.3 .1v.4h.3M132.3 57.9h-.3v.1v.5l.3-.1M132.4 50.3h.3v-.2h-.3v.6M132.6 58.1l-.1-.2h.4v.1l-.4 .2 .1 .3 .3-.1-.1-.3M133.1 50l-.1 .4h.3"/>
<path d="M133.2 58.1l-.1-.2 .4 .1-.1 .1h-.3v.4l.4-.1-.2-.3M133.2 50.2v.5M133.6 50.2l.1-.1v.6M133.6 50.7h.3M134.4 50.1h-.2l-.1 .2v.2l.2 .2v-.5l-.2 .2M134.7 50.2l.1-.1v.6M134.7 50.7h.3M137.2 57.6l.1 .6h.2v-.6M137.8 57.6h.4l-.2 .6M138.7 57.9l-.2 .1-.1-.3 .3-.1v.4l-.2 .2M144.8 51.4l.3 .2-.1 .3h-.3zM145.3 51.9h.1"/>
<path d="M145.6 51.4h.2l.1 .1-.4 .4h.4M145.7 53.5h-.4v.4l.4 .1M146.1 51.4h.3l-.3 .5h.3M146.1 59.7l.3-.1-.1-.2h-.2v.6M146.3 53.6l-.3 .2-.1-.3 .2-.1 .2 .2-.1 .4h-.3M146.3 59.7l.1 .3M146.4 58.6l.2-.1v.6M146.4 53.6l.2-.2v.6M146.4 54h.4M146.4 59.1h.4M146.7 59.6l.2-.2v.6M146.7 60h.3"/>
<path d="M146.8 51.6v.3h.2v-.3M147 58.5h.3l-.1 .6h-.2l-.1-.3zM147.3 51.7h.1M147.5 51.4h-.2v.5M147.5 59.4h-.2l-.1 .3 .3-.1v.4h-.3M147.5 58.5v.6M147.6 58.8l.2 .3M147.8 58.6l-.3 .3M148 59.4l.1 .2v.3l-.2 .1-.1-.4zM148.9 54.7h.7M149 56.3l.3-.1-.1-.3h-.2v.6M149.1 50.2h.5"/>
<path d="M149.1 56.3l.2 .2M149.1 54.4l.3 .3M149.2 49.9l.3 .3M149.5 56.1l.2-.2v.6M149.5 56.5h.4M149.6 55.1h-.7l.2 .1M149.6 51.4h.3l-.1-.3h-.2v.7M149.6 54.9v.3M149.6 54.4l-.3 .2M149.6 50.6h-.5l.1 .2M149.6 50.4v.4M149.6 49.9l-.2 .2"/>
<path d="M149.7 51.4l.2 .4M150.2 59.9v.6h.3M150.2 51.4l.1-.3v.7M150.2 51.8h.3M150.4 55.9h-.2l-.1 .4 .3-.1v.3h-.3M150.7 56.1l.1-.2v.6M150.7 56.5h.3M151 59.9h-.3v.6M151 51.1h-.3v.3h.2l.1 .3h-.3M151.2 59.9h.3l-.2 .3h.2v.2h-.3M151.6 51.1h-.3v.3h.3l-.1 .4-.2-.1M152 59.9h-.2v.3h.2l.1 .2h-.3"/>
<path d="M152.1 58.8v.6h.3v-.6M152.3 59.9h.4l-.3 .6M152.7 58.8h.4l-.3 .6M153.3 58.8h.3l-.2 .6M157.7 40.4h.1M158.5 54.5h.3v.6h-.3v-.2zM158.6 41l-.3-.1-.1 .2 .1 .4 .3-.1M158.8 40.9h.4l-.2 .6M159.1 40.1v.3h.3v-.3M159.1 55.1h.1M159.2 56.3h-.3v.5l.3 .1M159.4 54.6l.2-.1 .1 .2-.4 .4h.4"/>
<path d="M159.5 41.2v-.3l.2 .1-.3 .3 .1 .2 .2-.1-.1-.2M159.6 56.5l-.1-.2h.1l.2 .1-.3 .2v.3l.3-.1-.2-.3M159.6 40.2h.2M159.9 54.6l.3-.1v.2l-.3 .4h.3M160.4 56.5l-.3 .2-.1-.3 .1-.1 .3 .1-.1 .5h-.2M160.5 54.7l.1 .4h.1v-.4M160.8 59.8l.2-.2v.6M161.1 54.8h.1M161.3 54.5h-.2v.6M161.4 59.6l.3 .1-.1 .5h-.2l-.1-.2zM161.9 59.6v.6M162 60l.2 .2"/>
<path d="M162.2 59.8l-.3 .3M165.5 59.8l.2-.2v.6M166.2 59.6h.1l.1 .3-.1 .3h-.2zM166.7 59.6v.6M166.7 60l.1 .2M166.8 59.8l-.1 .3M167.6 47.5l.2-.2h.3l.2 .2-.2 .1h-.3zM167.6 46.9a.37 .37 0 0 1 .4-.2 .37 .37 0 0 1 .3 .2l-.6 .1zM167.6 54h.7M167.6 53.6l.4 .4M167.7 55.7l.3-.2-.1-.2h-.2v.6M167.8 49.1h.3v-.2h-.3v.6"/>
<path d="M167.8 55.7l.2 .2M167.9 49.1l.2 .4M168.2 55.5l.2-.2v.6M168.2 55.9h.4M168.3 54.4h-.7l.3 .3M168.3 48h-.7l.3 .2M168.3 47.9v.3M168.3 54.2v.5M168.3 53.6l-.4 .3M168.4 49.1l.1-.2v.6M168.4 49.5h.3M169.1 55.3h-.2l-.1 .3h.3v.3l-.3-.1"/>
<path d="M169.2 48.9h-.2v.2h.1l.2 .2-.2 .2-.1-.1M169.4 55.4h.3l-.3 .5h.3M169.8 48.9h-.3v.2v.2l.2 .2v-.4l-.2 .1M172.8 55v.6h.4M173.2 59.9l.1 .6h.2v-.6M173.4 55.2h.1M173.6 55h-.2v.6M173.8 55h.4l-.3 .2h.2l.1 .3h-.4M173.8 49.7v.5l.1 .1 .3-.1v-.5M173.8 59.9h.4l-.3 .6M174.5 50v-.3h.1l.2 .1-.3 .2v.3l.3-.1-.2-.2M174.7 55h-.2l-.1 .2h.3l.1 .3h-.4"/>
<path d="M174.7 59.9h-.2l-.1 .3v.2l.3 .1v-.3h-.3M175 55h.4l-.3 .6M175 49.7h.3l-.1 .6-.2-.2zM178.9 40.1l.4-.1-.1-.2h-.3v.5M179.1 40.1l.2 .2M179.5 40.3h.4M180.6 58l.1-.1v.6M180.6 58.5h.3M181.1 58v.4h.3M181.4 58v.5M181.7 58.9l-.4-.1-.1 .2v.3l.5 .1M181.7 58.1h.2"/>
<path d="M182 57.9h-.3v.6M182 59.1l-.2-.2 .4-.1v.3l-.4 .1 .1 .2h.3l-.1-.3M182.2 53.5h-.3v.4l.3 .1M182.4 58.8h.4l-.3 .6M182.6 51.5h.3v.3l-.3 .3h.3M182.8 53.6l-.2 .2-.1-.3 .2-.1 .1 .2v.4h-.3M183.2 51.7v.3h.2M183.2 53.4l.2 .2-.1 .4h-.2l-.1-.2zM183.4 51.7v.4M183.8 51.8h.1M184 51.5h-.2v.6M185 52.6v.3l.3 .1v-.4h.3l-.1 .4"/>
<path d="M185 54.7h.4v-.3h-.4v.6M185 52.4h.6M185.2 52.1l.3 .3M185.2 54.7l.2 .3M185.5 53.2h.1M185.6 53.6h-.6l.2 .2M185.6 54.6l.2-.2v.6M185.6 55h.4M185.6 53.5v.3M185.6 52.1l-.2 .2M185.8 40.2l.3-.1-.1-.3h-.2v.6M185.9 40.2l.2 .2"/>
<path d="M186.4 40l.2-.2v.6M186.4 40.4h.3M186.5 54.4h-.3v.3l.2-.1 .2 .2-.2 .2-.2-.1M186.9 54.3l-.2 .4h.5M187.1 54.6v.4M187.7 40.1v.3M187.9 58l.2-.1v.6M187.9 58.5h.4M188.5 58v.5l.3-.1M188.7 59l-.4 .1v.4h.4M188.8 58v.5M189 59.2l-.1-.2h.4l-.1 .2h-.3l.1 .4 .3-.1-.1-.3"/>
<path d="M189 58.1h.3M189.4 57.9h-.4v.6M189.8 59l-.3 .1v.4l.2 .1 .2-.2-.2-.3-.2 .2M192.3 56.1v.6M192.9 56.1v.6l-.3-.6v.6M193.2 56.7l.1-.6 .3 .6M193.3 56.5h.2M193.8 56.3v-.2h.2l.1 .1-.2 .1h-.1v.4l.3-.2-.2-.2M194.3 56.1h.3v.2l-.3 .4h.3M194.9 56.1h.3l-.2 .2h.2v.3h-.3M10.5 69.7h.1l.2-.2-.3-.1v.6M10.5 69.7l.3 .3"/>
<path d="M11 69.4l.4 .1-.4 .5h.4M11.9 69.4h-.3v.2h.3v.4l-.3-.1M12.3 69.8l.5-.1 .1 .3-.3 .1-.3-.1zM12.3 69.2l.5-.1 .1 .3-.5 .1zM12.3 68.6l.5-.1 .1 .3-.5 .1zM12.9 70.4h-.6l.2 .2M12.9 70.2v.4M16 74v.6M16.6 74v.6l-.3-.6v.6M16.7 69.2v.6l.4-.1v-.5M16.8 74.6l.3-.6 .1 .6M16.9 74.5h.2"/>
<path d="M17.3 69.4l.2-.2v.6M17.3 69.8h.4M17.5 74.3v-.3l.2 .1-.3 .3 .1 .2 .2-.1v-.2M18 74.1l.2-.1 .1 .3-.4 .3h.4M18.2 69.2h-.3l-.1 .4 .4-.1v.2l-.4 .1M18.5 74h.4l-.2 .3h.1l.1 .2h-.4M21.7 71.2h-.3v.5h.3M21.9 72.4l.2-.1v.6M21.9 72.9h.3M22 71.3l.1-.1v.6M22 71.8h.3M22.5 72.4v.5l.2-.1"/>
<path d="M22.7 72.4v.5M22.8 71.2l-.2 .1v.5l.3-.1-.1-.3-.2 .1M23.1 68.4h.2l.1-.3-.3-.1v.6M23.1 72.5h.1M23.2 68.4l.2 .2M23.3 72.3h-.2v.6M23.6 69.4h.3l-.2 .2h.2v.4l-.3-.1M23.7 68.1l.1-.1 .2 .2-.4 .4h.4M24.1 76.1l.3-.1v-.3h-.3v.6M24.3 69.4v.6M24.3 69.7l.1 .3M24.3 76.1l.1 .2"/>
<path d="M24.4 69.6l-.1 .2M24.5 68h-.2l-.1 .3 .1 .3h.2v-.3l-.3 .1M24.7 75.7h.3l-.2 .3h.2v.2h-.3M25.4 75.7l-.1 .5h.3M25.5 77.5v.3h.3l-.1-.2 .3-.2 .1 .2-.1 .2M25.5 77.2h.6M25.5 75.9v.4M25.7 76.9l.3 .3M26 78h.1M26.1 78.4h-.6l.2 .2M26.1 78.3v.3M26.1 76.9l-.2 .2"/>
<path d="M27.2 78.7l.3-.1 .1 .2-.5 .4h.5M27.8 78.8v.4l.3-.1M28.1 78.8v.4M28.2 76.8h-.4v.4l.4 .1M28.3 78.9h.3M28.4 76.8h.3l-.3 .5h.3M28.7 78.6h-.4v.6M28.8 71.3h-.3l-.1 .3 .1 .2h.3M29 71.5l.2-.3v.7M29 71.9h.3M29.1 76.7l.2 .2v.4h-.3zM29.2 72.4l.2-.1v.6"/>
<path d="M29.2 72.9h.4M29.6 71.2h.4l-.3 .7M29.8 72.4v.5l.3-.1M29.9 68.5h.3l.1-.2-.4-.1v.6M30 68.5l.3 .3M30.1 72.4v.5M30.2 69.4h.3l-.1 .2h.1v.4l-.3-.1M30.4 72.5h.1M30.4 68.2h.4v.3l-.4 .3h.4M30.6 72.3h-.2v.6M30.8 69.4v.6M30.9 69.7l.1 .3"/>
<path d="M31 68.2h.5l-.4 .6M31 69.6l-.2 .2M35.9 75.1v.6h.3M36.4 75.4h.2M36.4 70.2v.5l.2 .1 .2-.1v-.5M36.7 75.1h-.3v.6M36.9 75.1h.3l-.2 .3h.2v.2h-.3M37 70.4l.3-.2v.6M37 70.8h.5M37.7 75.1h-.2v.3h.2l.1 .2h-.3M38 75.1h.4l-.3 .6M38 70.2h-.3l-.1 .3 .2 .3 .2-.1-.1-.3-.3 .2"/>
<path d="M41.5 75.1h.3l.1-.2-.4-.1v.6M41.6 75.1l.3 .3M42 74.8h.4l-.2 .2 .2 .1v.2h-.4M42.6 74.8h.4v.3l-.4 .3h.4M42.9 61l.4-.1 .2 .1v.3h-.5zM42.9 60.5l.4-.2 .2 .1v.3h-.4h-.2zM42.9 76.5h.6M42.9 76.2l.3 .3M43.5 76.9h-.6l.2 .2M43.5 61.7h-.6l.2 .1M43.5 61.5v.3M43.5 76.8v.3"/>
<path d="M43.5 76.2l-.4 .2M44.3 70.7l.2-.2v.6M44.3 71.1h.4M44.4 69.7h.3v-.3h-.3v.6M44.6 69.7l.1 .3M44.9 70.5a.3 .3 0 0 1 .4 .2 .3 .3 0 0 1-.3 .4zM45 69.4h.3v.2l-.4 .4h.4M45.5 70.5v.6M45.5 70.8l.3 .3M45.7 69.6l-.1-.2h.2l.1 .2h-.3v.4l.3-.1-.1-.3M45.8 70.7l-.3 .2M49 70.7l.1-.2v.6"/>
<path d="M49 71.1h.3M49.1 69.6h.3v-.3l-.3-.1v.6M49.2 69.6l.2 .2M49.6 70.6h.3v.3l-.2 .2-.1-.2zM49.7 69.3h.3l-.3 .5h.3M50 75.6a.3 .3 0 0 1 .3 .3 .3 .3 0 0 1-.4 .3l-.1-.4zM50.2 70.5v.6M50.2 70.8l.2 .3M50.4 70.7l-.2 .2M50.5 76.2h.1M50.6 69.5l-.3 .1-.1-.3h.4v.4l-.4 .1M50.7 68.2l.1-.2 .2 .1v.5l-.3-.1z"/>
<path d="M50.8 75.6h.1l.2 .2-.4 .4h.4M51.2 73.9h-.4v.4l.4 .1M51.3 75.6h.3v.3l-.3 .3h.3M51.3 68.6h.1M51.3 67h-.4l-.1 .3 .1 .2h.4M51.4 74l.2-.2v.6M51.4 67.2l.2-.3v.7M51.4 74.4h.4M51.4 67.6h.4M51.5 68.1h.4l-.4 .5h.4M51.9 75.8v.4h.2M52.1 68.1h.4l-.4 .5h.4"/>
<path d="M52.1 75.8v.4M52.4 74l-.3 .2-.1-.3 .2-.1 .2 .2-.1 .4h-.3M52.4 66.9h-.4v.4h.4l-.1 .3-.3-.1M52.5 75.9h.1M52.7 75.6h-.2v.6M52.7 68.3v.3h.3v-.3M53.2 68.4h.3M53.6 68h-.4v.6M57.6 71.2l.1 .7 .3-.1v-.6M58.2 71.5l.2-.3v.7M58.2 71.9h.3M58.5 70.2v.6h.4"/>
<path d="M58.7 71.2h.4l-.2 .7M59.1 70.5h.1M59.3 70.2h-.2v.6M59.5 70.2h.4l-.3 .2 .3 .3-.2 .1-.2-.1M59.6 79.3l.4-.1-.1-.2h-.3v.5M59.7 79.3l.3 .2M60.2 79h.3l-.2 .2h.2v.3h-.3M60.2 74.5h.3l.1-.2-.4-.2v.7M60.3 74.5l.3 .3M60.4 70.2h-.2l-.1 .3 .2-.1 .1 .3h-.3M60.7 70.2h.4l-.4 .6M60.7 74.1h.4l-.2 .3 .2 .1v.2h-.4"/>
<path d="M61.1 79h-.4v.3h.4v.2h-.4M61.3 74.4l.2-.3v.7M61.3 74.8h.4M61.6 75.7h.6M61.7 80l.2 .2M61.8 75.6l.2 .1 .2-.1M62.1 80l-.3 .1M62.2 76.2h-.6l.2 .1M62.2 76v.3M63.4 71.8l.1-.1v.6M63.4 71h.2l.1-.3h-.3v.5M63.4 72.3h.3"/>
<path d="M63.5 71l.2 .2M63.8 78.7l.2 .1v.5h-.3l-.1-.2zM63.9 70.7h.4l-.2 .2h.1l.1 .3h-.4M64 71.8h.3v.3l-.2 .2-.1-.2zM64.2 79.3h.1M64.6 78.8l.1-.1 .2 .2-.4 .4h.4M64.6 71.7v.6M64.6 70.7h.2v.5h-.2l-.1-.1zM64.6 72l.2 .3M64.7 76.8l-.1-.1-.2 .1v.4l.3 .1M64.8 71.8l-.2 .3M65 76.8h.3l-.3 .5h.3"/>
<path d="M65.1 78.8h.3l-.3 .5h.3M65.6 76.8l.1-.1v.6M65.6 77.3h.3M65.7 79v.3h.2v-.3M66.3 79h.1M66.5 78.7h-.2v.6M73 72.5v.4l.2 .2 .2-.2v-.4M73.5 70v.6h.4M73.7 72.7l.2-.2v.6M73.7 73.1h.3M74 70.2h.2M74.3 70h-.3v.6"/>
<path d="M74.4 72.8l-.2-.2 .3-.1v.2l-.3 .2 .2 .2 .1-.1v-.2M74.5 70h.4l-.3 .2h.2l.1 .3h-.4M75.4 70h-.3v.2h.3l.1 .3h-.4M75.6 70h.5l-.3 .6M78.7 72.3h-.3v.5h.3M79 72.4l.1-.1v.6M79 72.9h.3M79.6 72.5l-.1-.2h.3l.1 .1-.4 .2v.3l.4-.1-.2-.3M80.4 71.6l.2-.2v.6M80.4 78.4l.1 .6h.2v-.6M80.4 72h.3M81 71.6v.3h.3"/>
<path d="M81 78.5l.2-.1v.6M81 79h.3M81.3 71.6v.4M81.6 71.7h.1M81.8 71.4h-.2v.6M81.9 78.6l-.3 .1v-.3h.3v.4l-.2 .2M82.4 75.6h.3l.1-.1-.4-.1v.6M82.5 75.6l.3 .4M82.9 75.4h.5l-.3 .2 .3 .2-.2 .2-.3-.1M83.5 75.4h.4l-.2 .2h.2v.3h-.4M83.8 77.4v.3h.3l-.1-.3 .3-.1 .1 .4M83.8 76.9l.6-.1v.3l-.4 .1z"/>
<path d="M83.8 76.6h.6M84 76.3l.2 .3M84.4 78.1h-.6l.1 .2M84.4 77.9v.4M84.4 76.3l-.2 .2M128 77.3l.3-.1-.1-.3h-.2v.6M128.1 75.7v.3l.2 .1v-.4h.4l-.1 .4M128.1 75.2l.5-.1 .1 .3-.6 .1zM128.1 74.9h.6M128.1 77.3l.2 .2M128.2 74.6l.3 .3M128.6 77.1l.1-.2v.6"/>
<path d="M128.6 77.5h.3M128.7 76.5h-.6l.1 .2M128.7 76.3v.4M128.7 74.6l-.3 .2M129.4 76.9h-.2l-.1 .3 .1 .3h.2v-.3l-.3 .1M130 76.9h-.3v.3h.3l-.1 .3-.2-.1M130.5 73.4l.1 .6 .3-.1v-.5M131.2 73.6l-.1-.2h.3v.2h-.3l.1 .4 .2-.1v-.3M131.7 72.3v-.6l.2 .4 .2-.4v.6M131.8 73.3l-.1 .4h.3M132 73.5v.5M132.7 71.7l-.3 .1v.4h.3"/>
<path d="M133 71.9h.3v-.2h-.3v.6M133.7 71.6l-.1 .4h.3M133.8 71.8v.5M134.2 71.8l.1-.1v.6M134.2 72.3h.3M135 71.7h-.3v.2v.2l.2 .2v-.5l-.2 .2M135.3 71.8l.1-.1v.6M135.3 72.3h.3M135.8 60.2v.5h.3M136.3 60.4h.2M136.6 60.2h-.3v.5M136.8 60.2h.3l-.2 .1 .2 .1v.3h-.3"/>
<path d="M137.6 60.2h-.2v.2l.1-.1 .2 .3-.2 .1h-.1M137.8 79.8l.1 .6 .3-.1v-.5M137.9 60.2h.4l-.3 .5M139.3 79.8h-.2l-.1 .3h.3v.3l-.3-.1M144.8 73.5l.3 .3-.1 .3h-.3zM145.3 74.1h.1M145.6 73.6l.2-.1 .1 .2-.4 .4h.4M145.7 75.6h-.4v.6h.4M146.1 73.6h.3l-.3 .5h.3M146.3 75.9l-.4 .1 .1-.4 .3 .1v.3l-.2 .2h-.2M146.6 75.9l-.2-.2 .2-.1h.2l-.1 .3-.3 .1 .2 .2h.2l-.1-.3M146.8 73.8v.3h.2v-.3"/>
<path d="M147.3 73.9h.1M147.5 73.5h-.2v.6M148.9 76.8h.7M149 78.4h.2l.1-.1-.3-.2v.6M149.1 72.3h.5M149.1 78.4l.2 .3M149.1 76.6l.3 .2M149.2 72.2l.3 .1M149.5 78.3l.2-.2v.6M149.5 78.7h.4M149.6 77.3h-.7l.2 .1M149.6 73.6h.3v-.2h-.3v.6"/>
<path d="M149.6 77.1v.3M149.6 76.6l-.3 .2M149.6 72.8h-.5l.1 .1M149.6 72.6v.3M149.6 72.2l-.2 .1M149.7 73.6l.2 .4M150.2 73.5l.1-.1v.6M150.2 74h.3M150.4 78.1h-.2l-.1 .3v.2l.3 .1v-.3h-.3M150.7 78.1h.3l-.2 .3h.2v.3h-.3M150.7 60.2h.2M151 73.4h-.3v.2l.1 .4 .2-.1-.1-.4-.2 .2"/>
<path d="M151.3 73.4h.3l-.3 .6M157.8 62l.2 .2-.1 .4h-.2zM158.3 62.6h.1M158.5 62.1h.4l-.4 .5h.4M158.6 76.7l.3 .2-.1 .4h-.3v-.2zM159.1 77.3h.1M159.1 62.1l.2-.1 .2 .2-.5 .4h.5M159.2 78.5h-.3v.5h.3M159.2 63.2l-.2-.1-.2 .3 .2 .3h.2M159.4 76.8l.2-.1 .1 .1-.4 .5h.4M159.6 63.4l-.2-.2 .3-.1v.3l-.3 .1 .1 .2h.2l-.1-.3M159.7 62.3v.3h.3v-.3"/>
<path d="M159.8 78.8l-.3 .1 .1-.5 .2 .2v.3l-.2 .2h-.1M159.9 76.8h.3l-.3 .5h.3M160.2 62.4h.3M160.3 78.4a.35 .35 0 0 0-.3 .3 .35 .35 0 0 0 .2 .4l.2-.2-.2-.2-.2 .2M160.3 63.1h-.3v.4h.3v.2h-.3M160.3 61.2h.4v-.3l-.4-.1v.6M160.5 76.9l.1 .4h.1v-.4M160.5 61.2l.2 .2M160.6 62h-.4v.6M160.8 60.2h.4M160.9 61l.2-.2v.6M160.9 61.4h.3"/>
<path d="M161.1 77h.1M161.3 76.7h-.2v.6M161.7 60.8l-.2 .5h.3M161.8 61.1v.3M162.4 61.1l-.2 .2v-.5l.2 .2v.2l-.1 .2h-.2M165.1 61.1h.1l.2-.3-.3-.1v.6M165.1 61.1l.3 .2M165.5 60.2h.3M165.6 60.9l.1-.2v.6M165.6 61.3h.3M166.3 60.7l-.1 .5h.4M166.5 60.9v.4"/>
<path d="M166.8 61v-.3h.3l-.1 .3-.2 .1v.2h.3l-.1-.3M167.6 69.6l.2-.1h.3l.2 .1-.2 .2h-.3zM167.6 69a.37 .37 0 0 1 .4-.1 .37 .37 0 0 1 .3 .2l-.6 .1zM167.6 76.2h.7M167.6 75.8l.4 .4M167.7 77.9l.3-.1-.1-.3h-.2v.6M167.8 71.3h.3v-.2h-.3v.6M167.8 77.9l.2 .2M167.9 71.3l.2 .4M168.2 77.7l.2-.2v.6M168.2 78.1h.4M168.3 76.7h-.7l.3 .1"/>
<path d="M168.3 70.2h-.7l.3 .2M168.3 70.1v.3M168.3 76.5v.3M168.3 75.8l-.4 .4M168.4 71.2l.1-.1v.6M168.4 71.7h.3M169.1 77.5h-.1l-.2 .3 .1 .3h.2v-.3l-.3 .1M169.2 71.1l-.2 .1v.4l.1 .1 .2-.2-.2-.3-.1 .2M169.5 77.5l-.1 .4h.3M169.6 71.3l-.1-.1 .3-.1-.1 .2-.2 .1 .1 .3 .2-.1-.1-.3M169.6 77.8v.3M172.8 77.2v.6h.4"/>
<path d="M173.4 77.4h.1M173.6 77.2h-.2v.6M173.8 77.2h.4l-.3 .2h.2l.1 .3h-.4M173.8 71.9v.4l.1 .2 .3-.2v-.4M174.5 72.2v-.3l.3 .1-.3 .2v.3l.3-.2-.2-.1M174.7 77.2h-.2l-.1 .2h.3l.1 .3h-.4M175 77.2h.4l-.3 .6M175.3 71.9h-.3v.3l.1 .3 .2-.1-.1-.3-.2 .2M179.5 62.3h.3l.1-.3-.4-.1v.6M179.7 62.3l.2 .2M180.1 60.7h.4l-.2 .3h.2v.3h-.4M180.1 62.1l.2-.2v.6"/>
<path d="M180.1 62.5h.4M180.7 60.7v.6M180.8 61.9l-.1 .5h.4M180.8 61.1l.2 .2M181 60.9l-.3 .3M181 62.1v.4M181.2 61.9h.5l-.3 .6M182.2 75.6h-.3v.6h.3M182.6 73.7h.3v.3l-.3 .3h.3M182.8 75.9l-.3 .1 .1-.4 .2 .1v.3l-.1 .2h-.2M183 75.6h.4l-.2 .6M183.2 73.9v.3h.2"/>
<path d="M183.4 73.9v.4M183.8 74h.1M184 73.7h-.2v.6M185 74.8v.3h.3v-.3h.3l-.1 .3M185 76.9h.3l.1-.3h-.4v.6M185 74.5h.6M185.2 74.3l.3 .2M185.2 76.9l.2 .3M185.5 75.4h.1M185.6 75.8h-.6l.2 .2M185.6 76.8l.2-.2v.6M185.6 77.2h.4"/>
<path d="M185.6 75.6v.4M185.6 74.3l-.2 .2M186.4 62.4h.2l.1-.3-.3-.1v.6M186.5 76.6l-.3 .2v.4l.4-.1-.1-.3-.3 .1M186.6 62.4l.1 .2M186.7 60.7h.4l-.2 .3h.2v.3h-.4M187 62.2l.2-.2v.6M187 62.6h.3M187.1 76.6h-.3l-.1 .2v.3l.4 .1v-.4l-.4 .1M187.3 60.7v.6M187.4 61.1l.2 .2M187.6 60.9l-.3 .3"/>
<path d="M187.7 62l-.2 .4h.4M187.8 62.3v.3M188.3 62l-.2 .2v.4h.3l-.1-.3-.2 .1M192.3 78.3v.6M192.9 78.3v.6l-.3-.6v.6M193 60.8v.6h.3v-.6M193.2 78.9l.1-.6 .3 .6M193.3 78.7h.2M193.6 60.8h.4l-.2 .6M193.8 78.5v-.2h.2l.1 .1-.2 .1h-.1v.4l.3-.2-.2-.2M194.3 78.3h.3v.2l-.3 .4h.3M194.5 60.8h-.3v.4h.3v.2h-.3"/>
<path d="M194.9 78.3h.3l-.2 .1 .2 .1v.3h-.3M198.2 61.3h.4l.2 .2-.6 .1zM198.2 60.7l.6 .1a.3 .3 0 0 1-.3 .3 .3 .3 0 0 1-.3-.4zM198.2 60.2h.5l.1 .1-.1 .2h-.4zM198.8 61.1h.1l.2-.3-.3-.1v.6M198.8 62h-.6l.2 .2M198.8 61.8v.4M198.8 61.1l.3 .2M199.3 60.9l.1-.2v.6M199.3 61.3h.3M200 60.7l-.1 .5h.4M200.2 60.9v.4"/>
<path d="M200.8 60.7h-.4v.3h.4l-.1 .3h-.3M10.5 91.9l.3-.2-.1-.1h-.2v.6M10.5 91.9l.3 .3M11 91.6h.4l-.3 .2h.2l.1 .3h-.4M11.6 91.6h.4l-.3 .6M12.3 92l.5-.1 .1 .3h-.3h-.3zM12.3 91.4l.5-.1 .1 .3-.5 .1zM12.3 90.8l.4-.1 .2 .1v.2l-.5 .1zM12.9 92.7h-.6l.2 .1M12.9 92.4v.4M16 96.2v.6M16.6 96.2v.6l-.3-.6v.6"/>
<path d="M16.7 91.4l.1 .7 .3-.2v-.5M16.8 96.8l.3-.6 .1 .6M16.9 96.6h.2M17.3 91.5l.2-.1 .2 .3-.5 .4h.5M17.5 96.5l-.1-.2 .3-.1v.3h-.2l-.1 .3h.3v-.3M17.8 91.7l.3-.3v.7M17.8 92.1h.4M18 96.3l.2-.1 .1 .3-.4 .3h.4M18.5 96.2h.4l-.2 .3h.1l.1 .2-.4 .1M21.7 93.4h-.3v.5h.3M21.9 94.6l.2-.2v.6M21.9 95h.3"/>
<path d="M22 93.4l.2-.1 .1 .3-.4 .3h.4M22.5 94.6v.4h.2M22.5 93.3h.4l-.3 .3h.2l.1 .3h-.4M22.7 94.6v.4M23.1 90.6l.3-.1-.1-.3h-.2v.6M23.1 94.7h.1M23.2 90.6l.2 .2M23.3 94.4h-.2v.6M23.6 91.6h.3l-.2 .2h.2v.4l-.3-.1M23.6 90.2h.4l-.3 .3h.2l.1 .2-.4 .1M24.1 98.3h.2l.1-.4h-.3v.6M24.3 91.6v.6"/>
<path d="M24.3 91.9l.1 .3M24.3 98.3l.1 .2M24.3 90.5l-.1-.1 .2-.2 .1 .3-.3 .1 .1 .2h.2l-.1-.3M24.4 91.7l-.1 .3M24.8 97.9l-.1 .4h.3M24.9 98.1v.4M25.5 99.7v.2h.3l-.1-.1 .3-.2 .1 .2-.1 .1M25.5 97.9l-.2 .2v.4l.3-.1-.1-.2-.2 .1M25.5 99.4h.6M25.7 99.2l.3 .2M26.1 99.2l-.2 .2M28.2 98.9h-.4v.5h.4"/>
<path d="M28.4 98.9h.3l-.3 .5h.3M28.8 93.5h-.2l-.2 .3 .1 .2h.3M28.9 98.8h.4l-.2 .6M29 93.5h.3v.3l-.3 .3h.3M29.2 94.6l.2-.2v.6M29.2 95h.4M29.8 93.4l-.2 .5h.4M29.8 94.6v.4h.3M29.9 90.6h.3l.1-.1-.4-.1v.6M29.9 93.7v.4M30 90.6l.3 .4M30.1 94.6v.4"/>
<path d="M30.2 91.6h.3l-.1 .2h.1v.4l-.3-.1M30.4 94.7h.1M30.4 90.4h.4l-.2 .2h.2v.3h-.4M30.6 94.4h-.2v.6M30.8 91.6v.6M30.9 91.9l.1 .3M31 91.7l-.2 .3M31.4 90.6l-.3 .1-.1-.3h.4v.4l-.3 .2M35.9 97.3v.6h.3M35.9 80.4v.6h.3v-.6M36.4 97.6h.2M36.4 92.4l.1 .6h.3v-.6"/>
<path d="M36.4 80.5l.4-.1v.2l-.4 .4h.4M36.7 97.3h-.3v.6M36.9 97.3h.3l-.2 .3h.2v.2h-.3M37 92.4l.5 .1-.5 .5h.5M37 80.5h.4v.5l-.4-.1zM37.6 92.4h.4v.3l-.4 .3h.4M37.7 97.3h-.2v.3h.2l.1 .2h-.3M38 97.3h.4l-.3 .6M41.4 81.6h.2l.1-.4h-.3v.6M41.5 97.2h.3l.1-.1-.4-.1v.6M41.5 81.6l.2 .2M41.6 97.2l.3 .4"/>
<path d="M42 81.2h.3l-.2 .3h.2v.2h-.3M42.2 96.9l-.2 .4h.5M42.4 97.2v.4M42.8 96.9l-.2 .4h.5M42.8 81.2l-.3 .2v.4l.4-.1-.1-.2-.3 .1M42.9 83.2l.4-.1 .2 .1v.2h-.5zM42.9 82.7l.6-.1v.2l-.4 .1-.2-.1zM42.9 98.7h.6M42.9 98.3l.3 .4M43 97.2v.4M43.5 99.1h-.6l.2 .2M43.5 83.9h-.6l.2 .1"/>
<path d="M43.5 83.7v.3M43.5 98.9v.4M43.5 98.3l-.4 .3M44.3 92.8l.2-.1v.6M44.3 93.3h.4M44.4 91.9l.3-.1v-.2h-.3v.6M44.6 91.9l.1 .3M44.9 92.7a.3 .3 0 0 1 .4 .2 .3 .3 0 0 1-.3 .4zM45.1 91.6l-.1 .4h.3M45.3 91.7v.5M45.5 92.7v.6M45.5 93l.3 .3"/>
<path d="M45.7 91.6h.1l.1 .2-.1 .4-.2-.1zM45.8 92.8l-.3 .3M49 92.8l.1-.1v.6M49 93.3h.3M49.1 91.7h.3v-.2l-.3-.1v.7M49.2 91.7l.2 .4M49.6 92.8h.3v.3l-.2 .2-.1-.2zM49.8 91.4l-.1 .4h.3M49.9 97.8a.3 .3 0 0 1 .4 .3 .3 .3 0 0 1-.3 .3l-.2-.2zM49.9 91.7v.4M50.2 92.7v.6M50.2 91.7l.2-.3v.7"/>
<path d="M50.2 93l.2 .3M50.2 92.1h.4M50.4 92.8l-.2 .3M50.5 98.3v.1M50.8 97.8h.2l.1 .2-.4 .4h.4M50.8 90.2l.2 .1v.5l-.3-.1v-.3zM51.2 96.1h-.4v.4l.4 .1M51.3 97.8h.3v.3l-.3 .3h.3M51.3 90.8h.1M51.3 89.2h-.3l-.2 .3 .1 .2h.4M51.4 96.1h.4l-.4 .5h.4M51.4 89.2h.4v.3l-.4 .3h.4"/>
<path d="M51.5 90.3h.4l-.4 .5h.4M51.9 98v.3h.2M52 89.2h.4v.3l-.4 .3h.4M52.1 90.3h.4l-.4 .5h.4M52.1 98v.4M52.3 96l-.3 .1v.5l.4-.1-.1-.3-.3 .1M52.5 98.1h.1M52.7 97.8h-.2v.6M52.7 90.5v.3h.3v-.3M53.2 90.6h.3M53.6 90.2h-.4v.6M57.6 93.5l.1 .6 .3-.2v-.4"/>
<path d="M58.2 93.5h.3v.3l-.4 .3h.4M58.5 92.4v.6h.4M58.7 93.5h.4l-.2 .2 .2 .2-.1 .2-.3-.1M59.1 92.7h.1M59.3 92.4h-.2v.6M59.5 92.4h.4l-.3 .3h.2l.1 .2h-.4M60.2 96.6h.3l.1-.1-.4-.1v.6M60.3 96.6l.3 .4M60.4 92.4h-.2l-.1 .3h.3v.3l-.3-.1M60.7 92.4h.4l-.4 .6M60.9 96.3l-.2 .4h.5M61.1 96.6v.4"/>
<path d="M61.3 96.4h.4l-.2 .2h.2v.3h-.4M61.5 80.2h.6M61.6 97.9h.6M61.8 97.7l.2 .2 .2-.2M62.1 80.6h-.6l.2 .2M62.1 80.5v.3M62.2 98.4h-.6l.2 .2M62.2 98.2v.4M63.4 94l.1-.1v.5M63.4 93.2h.3l-.1-.4h-.2v.7M63.4 94.4h.3M63.5 93.2l.2 .3"/>
<path d="M64 93.9h.3l-.1 .5h-.2zM64.1 92.8l-.1 .5h.3M64.2 93.1v.4M64.5 92.9h.3v.3l-.3 .3h.3M64.6 93.9v.5M64.6 94.2l.2 .2M64.7 98.9l-.1-.1-.2 .2v.4h.3M64.8 94l-.2 .3M65 98.9h.3l-.3 .5h.3M65.7 99.1l-.1-.2 .1-.1 .2 .2-.3 .2v.2h.3l-.2-.3M73 94.7v.4l.2 .2 .2-.2v-.4M73.5 92.2v.6h.4"/>
<path d="M73.7 94.7h.3v.2l-.4 .4h.4M74 92.4h.2M74.3 92.2h-.3v.6M74.4 94.6l-.2 .4h.4M74.5 92.2h.4l-.3 .2h.2l.1 .3h-.4M74.5 94.9v.4M75.4 92.2h-.3v.2h.3l.1 .3h-.4M75.6 92.2h.5l-.3 .6M76.8 80.6v-.5l.2 .4 .2-.4v.5M77.9 80.1a.28 .28 0 0 0-.4 .2 .28 .28 0 0 0 .1 .3h.3M78.1 80.4l.3-.1v-.2h-.3v.5M78.7 94.5h-.3v.5h.3"/>
<path d="M78.8 80.1l-.1 .4h.3M79 94.5l.2-.1 .1 .2-.4 .4h.4M79 80.2v.4M79.2 80.2l.2-.1v.5M79.2 80.6h.3M79.8 94.4h-.3v.3h.3l.1 .3h-.4M80.1 80.1l-.3 .1v.4h.3v-.3l-.3 .1M80.4 80.2l.2-.1v.5M80.4 93.8l.2-.2v.6M80.4 80.6h.3M80.4 94.2h.3M81 93.8v.3h.3"/>
<path d="M81.3 93.8v.4M81.6 93.9h.1M81.8 93.6h-.2v.6M83 97.8h.4v-.2h-.4v.6M83.1 97.8l.3 .4M83.7 97.5l-.1 .4h.3M83.9 97.7v.5M84.3 99.6v.3h.2v-.3l.3-.1v.4M84.3 99.1l.5-.1 .1 .3-.4 .1-.2-.1zM84.3 98.8h.6M84.5 97.6h-.3l-.1 .2 .3-.1 .1 .4h-.4M84.5 98.5l.2 .3"/>
<path d="M84.9 98.5l-.3 .2M92.8 89.2h.4M93 89.2v.6M93.3 89.5h.3v-.1h-.3v.3h.3M93.9 89.5h.2v-.1h-.2v.3h.2M94.4 89.5l.2-.1v.4M94.4 89.4v.4M95.1 89.4l-.2 .1 .2 .2h-.2M95.4 89.4l.1 .4M95.6 89.4l-.2 .6M96 89.1l-.2 .4h.4M96.1 89.4v.4"/>
<path d="M96.4 89.7v.1M96.6 89.4l.3-.2v.6M96.6 89.8h.5M98 89.2l.1 .6 .2-.1v-.5M98.6 89.2h.4l-.3 .6M126.8 99.4h.2l.1-.2-.3-.1v.6M126.9 97.9v.4h.2v-.4l.4 .1-.1 .3M126.9 97.4l.5-.1 .1 .3-.5 .1zM126.9 97.1h.6M126.9 99.4l.2 .3M127 96.8l.3 .3M127.3 99.3l.2-.2v.6"/>
<path d="M127.3 99.7h.3M127.5 98.7h-.6l.1 .1M127.5 98.5v.3M127.5 96.8l-.3 .2M127.9 99.1h.4l-.2 .6M128.5 99.1h.3l-.2 .6M129.3 96.1l.1 .6 .3-.1v-.5M130.3 96.4l-.4 .1v-.4l.4 .1-.1 .4-.3 .1M130.5 95v-.6l.2 .5 .2-.5v.6M130.5 96.1a.3 .3 0 0 1 .4 .3 .3 .3 0 0 1-.3 .3l-.2-.2zM130.6 81.1l.2-.2v.6M130.6 81.5h.3"/>
<path d="M131.2 81.1v.4l.2-.1M131.4 81.1v.4M131.5 94.5h-.3v.5h.3M131.7 81.2h.2M131.8 94.8l.3-.1-.1-.3h-.2v.6M132 80.9h-.3v.6M132.5 94.4l-.1 .5h.3M132.6 94.6v.4M132.9 94.6l.2-.2v.6M132.9 80.1h-.3l-.1 .1 .1 .4h.3M132.9 95h.4M133.5 80.3l-.4 .1v-.3h.4v.4l-.3 .1"/>
<path d="M133.8 94.4h-.2l-.1 .3 .1 .3h.2v-.3l-.3 .1M134.1 94.6l.1-.2v.6M134.1 80.1h-.4v.2h.4l-.1 .3h-.3M134.1 95h.3M136.4 82.3v.6h.3M136.9 82.6h.2M137.2 82.3h-.3v.6M137.4 82.3h.3l-.2 .3h.2v.2h-.3M138.3 82.3h-.3v.3h.3l-.1 .3-.2-.1M138.5 82.3h.4l-.3 .6M138.6 80.1l-.1-.3h.2l.1 .2-.3 .1v.3l.3-.1-.2-.2M144.8 95.7a.35 .35 0 0 1 .3 .4 .35 .35 0 0 1-.3 .3z"/>
<path d="M145.1 97.8l-.4 .1v.4h.4M145.3 96.3v.1M145.3 98l.2-.2v.6M145.3 98.4h.4M145.6 95.8l.2-.1 .1 .3-.4 .4h.4M145.9 97.8a.3 .3 0 0 1 .4 .3 .3 .3 0 0 1-.3 .3zM146.1 95.8h.3v.3l-.3 .3h.3M146.1 81.9l.3-.1-.1-.2h-.2v.6M146.3 81.9l.1 .3M146.4 80.8l.2-.2v.6M146.4 81.2h.4M146.7 81.7l.2-.1v.6"/>
<path d="M146.7 82.2h.3M146.8 96v.3h.2M146.8 97.8h-.3l-.1 .3 .3-.1 .1 .3h-.4M147 80.6l.3 .1-.1 .5h-.2l-.1-.2zM147 96v.4M147.3 96.1h.1M147.5 95.7h-.2v.7M147.5 81.6h-.1l-.2 .2v.3l.3 .1v-.4l-.3 .1M147.5 80.6v.6M147.6 81l.2 .2M147.8 81.7h.3l-.3 .5h.3M147.8 80.8l-.3 .3"/>
<path d="M148.9 99h.7M149.1 94.5h.5M149.1 98.8l.3 .2M149.2 94.4l.3 .1M149.6 99.4h-.7l.2 .2M149.6 95.8h.3v-.3h-.3v.6M149.6 99.3v.3M149.6 98.8l-.3 .1M149.6 95h-.5l.1 .1M149.6 94.8v.3M149.6 94.4l-.2 .1M149.7 95.8l.2 .3"/>
<path d="M150.2 82.1v.6h.3M150.2 95.7l.1-.2v.6M150.2 96.1h.3M150.7 95.5h.4l-.3 .6M150.7 82.3h.2M151 82.1h-.3v.6M151.2 82.1h.3l-.2 .2h.2v.3h-.3M151.6 95.8l-.3 .1v-.4h.3v.5l-.3 .1M152 82.1h-.2v.2h.2l.1 .3h-.3M152.1 81v.6h.3v-.6M152.3 82.1h.4l-.3 .6M152.8 81.2l-.1-.1 .3-.1v.2h-.2l-.1 .4h.3v-.4"/>
<path d="M153.3 81h.3l-.1 .2 .1 .1v.3h-.3M157.8 84.2l.2 .2v.3l-.1 .2-.2-.1zM158.3 84.8v.1M158.5 98.9l.2-.1 .2 .3-.1 .3h-.3zM158.5 84.3h.4v.2l-.4 .4h.4M159.1 99.4h.1M159.1 84.3l.2-.1 .2 .3-.5 .4h.5M159.2 85.4l-.2-.1-.2 .3 .2 .3h.2M159.4 98.9l.2-.1 .1 .2-.4 .4h.4M159.7 84.5v.3h.3M159.7 85.6l-.1 .1-.2-.2 .2-.2 .1 .1v.4l-.2 .1M159.9 98.9h.3l-.3 .5h.3"/>
<path d="M160 85.4h.3l-.3 .5h.3M160 84.5v.4M160.2 84.5h.3M160.3 83.4h.4v-.3l-.4-.1v.6M160.5 99.1l.1 .3h.1v-.3M160.5 83.4l.2 .2M160.6 84.2h-.4v.7M160.8 82l.2-.2v.6M160.8 82.4h.4M160.9 83.2l.2-.2v.6M160.9 83.6h.3M161.1 99.2h.1"/>
<path d="M161.3 98.8h-.2v.6M161.4 81.8l.3 .1v.5h-.3l-.1-.1zM161.8 83l-.3 .2v.4h.3v-.3l-.3 .1M161.9 81.8v.6M162 82.3l.2 .1M162.1 83.2l.2-.2v.6M162.1 83.6h.3M162.2 82.1l-.3 .2M165.1 83.3h.1l.2-.3-.3-.1v.6M165.1 83.3l.3 .2M165.5 82l.2-.2v.6M165.5 82.4h.3"/>
<path d="M165.6 83.1l.1-.2v.6M165.6 83.5h.3M166.2 81.8h.1l.1 .3-.1 .3h-.2zM166.5 82.9h-.2l-.1 .3v.2l.3 .1v-.3l-.3 .1M166.7 81.8v.6M166.8 83h.3l-.1 .5-.2-.1zM166.8 82.1l-.1 .2 .1 .1M167.6 91.8l.2-.1h.3l.2 .1-.1 .2h-.5zM167.6 91.2a.37 .37 0 0 1 .4-.2 .37 .37 0 0 1 .3 .3l-.6 .1zM167.6 98.4h.7M167.6 98.1l.4 .3M167.8 93.5h.3v-.2h-.3v.6"/>
<path d="M167.9 93.5l.2 .4M168.2 99.9l.2-.2v.6M168.3 98.8h-.7l.3 .2M168.3 92.4h-.7l.3 .2M168.3 92.2v.4M168.3 98.7v.3M168.3 98.1l-.4 .2M168.4 93.4l.1-.1v.6M168.4 93.9h.3M168.8 99.7h.4l-.2 .6M169 93.5v-.2h.2h.1l-.2 .2h-.1v.4l.3-.2-.2-.2M169.5 93.3h.3l-.1 .6-.2-.3z"/>
<path d="M169.6 99.7l-.2 .2v.4h.3l-.1-.4-.2 .1M172.8 99.4v.5h.4M173.2 82.1l.1 .6h.2v-.6M173.4 99.6h.1M173.6 99.4h-.2v.5M173.8 99.4h.4l-.3 .2h.2l.1 .3h-.4M173.8 94.1v.4l.1 .2 .3-.2v-.4M173.9 82.3l-.1-.1 .3-.1v.2l-.3 .1 .1 .3h.2l.1-.3-.2-.1M174.4 82.2l.3-.1v.2l-.3 .4h.3M174.7 99.4h-.2l-.1 .2h.3l.1 .3h-.4M174.8 94.4h-.3v-.3l.3 .1-.1 .4-.2 .1M175 99.4h.4l-.3 .5"/>
<path d="M175 94.1h.3v.3l-.3 .3h.3M179.5 84.5l.4-.1-.1-.3h-.3v.6M179.7 84.5l.2 .2M180.1 82.9h.4l-.2 .3h.2v.3l-.4-.1M180.1 84.3l.2-.2v.6M180.1 84.7h.4M180.6 80.2l.1-.1v.5M180.6 80.6h.3M180.7 82.9v.6M180.8 83.3l.2 .2M181 84.1h-.3v.3h.3l.1 .2h-.4M181 83.1l-.3 .3"/>
<path d="M181.1 80.2v.4h.3M181.4 80.2v.4M181.6 84.4l-.3 .1-.1-.3 .4-.1v.4l-.3 .2M181.7 97.8l-.4 .1v.4l.2 .1 .2-.1M181.7 81.1l-.2-.1-.3 .2v.3l.5 .1M181.7 80.3h.2M181.9 98l.2-.2v.6M181.9 98.4h.3M182 80.1h-.3v.5M182.2 81.2l-.2 .2-.2-.2 .2-.2 .2 .1v.4l-.3 .1M182.5 97.8a.3 .3 0 0 1 .4 .3 .3 .3 0 0 1-.3 .3zM182.6 96h.3l-.3 .5h.3"/>
<path d="M182.6 81l-.2 .4h.4M182.7 81.2v.4M183.2 96.1v.3h.2M183.2 97.7l-.2 .5h.4M183.3 98v.4M183.4 96.1v.4M183.8 96.1h.1M184 95.9h-.2v.6M185 97v.3h.3v-.3h.2v.3M185 99.1h.3l.1-.3h-.4v.6M185 96.7h.6M185.2 96.5l.3 .2"/>
<path d="M185.2 99.1l.2 .3M185.5 97.6h.1M185.6 98h-.6l.2 .2M185.6 98.9l.2-.1v.6M185.6 99.4h.4M185.6 97.8v.4M185.6 96.5l-.2 .1M186.1 98.8h.5l-.3 .6M186.4 84.5h.3v-.2l-.3-.1v.7M186.6 84.5l.1 .4M186.7 82.9h.4l-.2 .3h.2v.2h-.4M186.9 99l-.2-.2h.4v.2l-.4 .1 .1 .3h.3l-.1-.4"/>
<path d="M187 84.5l.2-.3v.7M187 84.9h.3M187.3 82.9v.6M187.4 83.3l.2 .2M187.6 83.1l-.3 .3M187.8 84.2h-.2l-.1 .3h.2l.1 .3h-.3M187.9 80.2l.2-.1v.5M187.9 80.6h.4M188.2 84.5v-.3l.2 .1-.1 .2h-.2l.1 .4 .2-.1-.1-.3M188.5 80.2v.4h.3M188.7 81.2h-.4v.5h.4M188.8 80.2v.4"/>
<path d="M189 80.3h.3M189.3 81.4l-.4 .1v-.3h.4v.4l-.4 .1M189.4 80.1h-.4v.5M189.4 81.2h.5l-.3 .1 .3 .3-.2 .1h-.3M193 83v.6h.3v-.6M193.8 83.3l-.2-.1 .2-.2 .1 .3-.3 .1 .1 .2h.2l-.1-.3M194.2 83.2l.2-.2v.6M194.2 83.6h.3M198.2 82.9l.6 .1a.3 .3 0 0 1-.3 .3 .3 .3 0 0 1-.3-.4zM198.2 82.4l.5-.1 .1 .2-.1 .2h-.4zM198.8 83.3h.1l.2-.3-.3-.1v.6M198.8 84.2h-.6l.2 .2"/>
<path d="M198.8 84v.4M198.8 83.3l.3 .2M199.3 83.1l.1-.2v.6M199.3 83.5h.3M200.2 82.9h-.3v.3h.3v.3l-.3-.1M200.4 82.9h.4l-.3 .6M10.5 114.1h.1l.2-.3-.3-.1v.6M10.5 114.1l.3 .2M11.1 113.7l-.1 .5h.4M11.3 113.9v.4M11.9 114l-.3 .1v-.3l.3-.1v.5l-.3 .1M12.3 114.2l.5-.1 .1 .2-.5 .1z"/>
<path d="M12.3 113.6l.5-.1 .1 .2-.5 .1zM12.3 113l.4-.1 .2 .1v.2h-.5zM12.9 114.9h-.6l.2 .1M12.9 114.7v.3M16 118.4v.6M16.6 118.4v.6l-.3-.6v.6M16.7 113.7l.1 .6 .3-.2v-.4M16.8 119l.3-.6 .1 .6M16.9 118.8h.2M17.3 113.7h.3l.1 .1-.5 .5h.5M17.5 118.7l-.1-.2 .3-.1v.3h-.2l-.1 .3h.3v-.3M17.8 113.7h.4l-.2 .6"/>
<path d="M18 118.5l.2-.1 .1 .3-.4 .3h.4M18.5 118.4h.4l-.2 .3h.1l.1 .2-.4 .1M21.7 115.6h-.3v.4l.3 .1M21.9 116.8l.2-.2v.6M21.9 115.5h.4l-.2 .3 .2 .1v.2h-.4M21.9 117.2h.3M22.5 116.8v.4l.2-.1M22.6 115.5l.3 .3-.1 .3h-.2zM22.7 116.8v.4M23.1 112.7h.2l.1-.2-.3-.1v.6M23.1 116.9h.1M23.2 112.7l.2 .3"/>
<path d="M23.3 116.6h-.2v.6M23.6 113.7h.3l-.2 .3h.2v.3h-.3M23.9 112.4h-.2v.3l.2-.1 .1 .3-.3 .1M24.3 113.7v.6M24.3 114.1l.1 .2M24.3 112.4l.2 .1v.5h-.2l-.1-.2zM24.4 113.9l-.1 .3M26 100.2h.1M26.1 100.6h-.6l.2 .2M26.1 100.5v.3M27.2 100.9l.3-.1 .1 .2-.5 .4h.5M27.8 101v.4l.3-.1"/>
<path d="M28.1 101v.4M28.3 101h.3M28.7 100.8h-.4v.6M28.8 115.7h-.2l-.2 .3 .1 .2h.3M29 115.7h.3l-.1 .2 .1 .1v.2h-.3M29.2 116.8l.2-.2v.6M29.2 117.2h.4M29.6 115.9l.2-.2v.6M29.6 116.3h.3M29.8 116.8v.4l.3-.1M29.9 112.9h.2l.2-.3h-.4v.6M30 112.9l.3 .3"/>
<path d="M30.1 116.8v.4M30.2 113.7h.3l-.1 .3h.1v.3h-.3M30.4 116.9h.1M30.6 116.6h-.2v.6M30.8 112.6h-.3l-.1 .2h.4v.4l-.4-.1M30.8 113.7v.6M30.9 114.1l.1 .2M31 112.7l.2-.1v.6M31 113.9l-.2 .3M31 113.2h.4M35.9 119.5v.6h.3M35.9 102.6v.6h.3v-.6"/>
<path d="M36.4 119.8h.2M36.4 114.6l.1 .6h.3v-.6M36.4 102.7h.4l-.4 .5h.4M36.7 119.5h-.3v.6M36.9 119.5h.3l-.2 .3h.2v.2h-.3M37 114.7h.5l-.5 .5h.5M37.4 102.6l-.4 .1v.5h.4v-.4l-.4 .1M37.7 119.5h-.2v.3h.2l.1 .2h-.3M37.8 114.9l-.2-.2 .4-.1v.3h-.4l.1 .3h.3l-.1-.3M38 119.5h.4l-.3 .6M41.4 103.8h.3v-.4h-.3v.6M41.5 119.4h.3l.1-.1-.4-.1v.6"/>
<path d="M41.5 103.8l.2 .2M41.6 119.4l.3 .4M42.1 103.4l-.1 .4h.3M42.2 103.7v.3M42.4 119.2h-.3l-.1 .2 .3-.1 .1 .4h-.4M42.6 103.7l-.1-.3h.3l.1 .2-.4 .2v.2l.4-.1-.2-.2M42.9 105.4l.4-.1 .2 .1v.2h-.5zM42.9 104.9l.6-.1v.2l-.4 .1-.2-.1zM43 119.2l-.4 .1v.4l.3 .1 .1-.4-.3-.1-.1 .2M43.5 106h-.6l.2 .2M43.5 105.9v.3M44.3 115l.2-.1v.5"/>
<path d="M44.3 115.4h.4M44.4 114.1h.3v-.3l-.3-.1v.6M44.6 114.1l.1 .2M44.9 114.9a.3 .3 0 0 1 .4 .2 .3 .3 0 0 1-.3 .3zM45.3 113.7h-.3v.3h.3v.3h-.3M45.5 114.9v.5M45.5 115.2l.3 .2M45.6 113.8l.2-.1 .1 .2-.4 .4h.4M45.8 115l-.3 .3M49 115l.1-.1v.5M49 115.4h.3M49.1 113.9h.3v-.2h-.3v.6"/>
<path d="M49.2 113.9l.2 .4M49.6 114.9h.3v.4l-.2 .1-.1-.1zM50 113.7h-.3v.2h.3l-.1 .4-.2-.1M50.2 113.7h.4l-.3 .1 .3 .1v.3h-.4M50.2 114.9v.5M50.2 115.2l.2 .2M50.4 115l-.2 .3M50.8 112.4l.2 .1v.5l-.3-.1v-.3zM51.2 118.2h-.4v.5h.4M51.3 113h.1M51.3 111.4h-.3l-.2 .2 .1 .3h.4M51.4 118.2h.4l-.2 .2 .2 .1v.2h-.4"/>
<path d="M51.4 111.4h.4v.2l-.4 .4h.4M51.5 112.5h.4l-.4 .5h.4M51.9 118.2h.5l-.3 .2 .3 .1v.2h-.5M52.1 112.5h.4l-.4 .5h.4M52.4 111.6l-.3 .1-.1-.3h.4v.4l-.3 .2M52.7 112.6v.4h.3v-.4M53.2 112.7h.3M53.6 112.4h-.4v.6M57.6 115.7l.1 .6 .3-.2v-.4M58.2 115.7h.3v.3l-.4 .3h.4M58.5 114.6v.6h.4M59.1 114.9h.1"/>
<path d="M59.1 116h-.3v-.3l.3 .1v.4l-.3 .1M59.3 114.6h-.2v.6M59.5 114.6h.4l-.3 .3h.2l.1 .2h-.4M59.6 101.5h.3l.1-.2-.4-.2v.6M59.7 101.5l.3 .2M60.2 118.8h.3l.1-.1-.4-.1v.6M60.3 101.1l-.1 .5h.4M60.3 118.8l.3 .4M60.4 114.6h-.2l-.1 .3h.3v.3l-.3-.1M60.5 101.4v.3M60.7 114.6h.4l-.4 .6M60.7 101.1h.4l-.3 .6"/>
<path d="M61.1 118.6h-.3l-.1 .2 .3-.1 .1 .4h-.4M61.5 102.4h.6M61.7 118.6h-.4v.2l.3-.1 .1 .4h-.4M61.7 102.2l.2 .2M61.8 119.9l.2 .3M62.1 102.8h-.6l.2 .2M62.1 102.7v.3M62.1 102.2l-.3 .1M62.2 119.9l-.2 .2M63.4 116.2l.1-.2v.6M63.4 115.4h.3v-.3h-.3v.6M63.4 116.6h.3"/>
<path d="M63.5 115.4l.2 .3M63.8 100.9l.2 .1v.5h-.3l-.1-.2zM64 116.1h.3l-.1 .5-.2-.1zM64.2 101.5h.1M64.2 115.1h-.2v.3l.1-.1 .2 .2-.2 .2-.1-.1M64.6 101l.1-.1 .2 .1-.4 .5h.4M64.6 116v.6M64.6 115l-.1 .4h.4M64.6 116.4l.2 .2M64.8 116.2l-.2 .3M64.8 115.3v.4M65.1 101h.3l-.3 .5h.3"/>
<path d="M65.7 101.1v.4h.2v-.4M66.3 101.2h.1M66.5 100.9h-.2v.6M73 116.9l.1 .6 .3-.1v-.5M73.5 114.3v.6h.4M73.6 116.9h.4l-.2 .2h.2v.3h-.4M74 114.6h.2M74.3 114.3h-.3v.6M74.3 116.9h.2v.6h-.2l-.1-.3zM74.5 114.3h.4l-.3 .3 .3 .1v.2h-.4M75.4 114.3h-.3v.3h.3l.1 .3h-.4M75.6 114.3h.5l-.3 .6"/>
<path d="M76.8 102.8v-.6l.2 .5 .2-.5v.6M77.9 102.3a.28 .28 0 0 0-.4 .2 .28 .28 0 0 0 .1 .3l.3-.1M78.1 102.6h.3v-.3l-.3-.1v.6M78.7 116.7h-.3v.4h.3M78.8 102.2l-.1 .5h.3M78.9 116.6h.4l-.3 .3h.2l.1 .2h-.4M79 102.4v.4M79.2 102.4l.2-.2v.6M79.2 102.8h.3M79.5 116.7h.4l-.4 .5h.4M80.1 102.2h-.2l-.1 .5h.3v-.2l-.3 .1M80.4 116l.2-.2v.6"/>
<path d="M80.4 102.4l.2-.2v.6M80.4 100.5v.6h.3v-.6M80.4 116.4h.3M80.4 102.8h.3M81 116v.3h.3M81 100.6l.3-.1v.3l-.3 .3h.3M81.3 116v.4M81.6 116h.1M81.8 115.8h-.2v.6M81.9 100.5h-.3v.4h.3v.2h-.3M83.3 119.8h-.3l-.1 .2h.4l.1 .3h-.5M83.5 119.8h.4l-.2 .6"/>
<path d="M84.9 100.3h-.6l.2 .2M84.9 100.1v.4M127.5 119.6l.3-.1 .3 .1v.2h-.5zM127.5 119.3h.6M127.6 119l.3 .3M128.1 119l-.3 .2M129.3 103.3l.2-.2v.6M129.3 103.7h.4M129.9 103.3v.3h.4M129.9 118.3v.6l.4-.1v-.5M130.3 103.3v.4M130.5 103.3h.2"/>
<path d="M130.8 103.1h-.3v.6M130.9 118.6l-.4 .1v-.4h.4l-.1 .6h-.3M131.1 117.2v-.6l.2 .5 .2-.5v.6M131.4 118.3l-.3 .2v.4l.3-.1v-.2l-.3 .1M131.4 102.3a.28 .28 0 0 0-.3 .2 .28 .28 0 0 0 .1 .3l.2-.1M131.7 102.4l.2-.2v.6M131.7 102.8h.3M132.1 116.7h-.3v.4h.3M132.3 102.2l.2 .1v.5h-.2l-.1-.2zM132.4 117h.2l.1-.3-.3-.1v.6M132.8 102.3h.3l-.3 .5h.3M133.1 116.6l-.1 .5h.3"/>
<path d="M133.2 116.8v.4M133.6 116.8l.1-.2v.6M133.6 117.2h.3M134.4 116.6h-.2l-.1 .3v.2l.3 .1v-.3l-.3 .1M134.7 116.8l.1-.2v.6M134.7 117.2h.3M135.2 104.5v.6h.3M135.7 104.8h.2M136 104.5h-.3v.6M136.2 104.5h.3l-.1 .3h.1v.2h-.3M136.6 102l.1 .6h.2v-.6M137 104.5h-.2v.3h.2l.1 .2h-.3"/>
<path d="M137.3 104.5h.4l-.2 .6M137.5 102.2l-.1 .2-.2-.3 .3-.1v.5l-.2 .1M137.8 102.2l.2-.2v.6M137.8 102.6h.3M145.3 118a.3 .3 0 0 1 .4 .2 .3 .3 0 0 1-.3 .4zM145.9 118.5v.1M146.1 104.1l.3-.1-.1-.2h-.2v.6M146.2 118h.2l.1 .2-.4 .4h.4M146.3 104.1l.1 .3M146.4 103l.2-.2v.6M146.4 103.4h.4M146.7 103.9l.2-.1v.6"/>
<path d="M146.7 104.4h.3M146.8 118h.2l.1 .2-.4 .4h.4M147 102.8l.3 .1-.1 .5h-.2l-.1-.2zM147.2 103.8h.4l-.2 .6M147.4 118.2v.3h.2M147.5 102.8v.6M147.6 103.2l.2 .2M147.6 118.2v.4M147.8 103l-.3 .3M147.9 118.2h.1M148 103.8l-.2 .4h.3M148 104v.4"/>
<path d="M148.1 118h-.2v.6M149 100.6h.2l.1-.1-.3-.2v.6M149.1 100.6l.2 .3M149.5 100.5l.2-.2v.6M149.5 100.9h.4M149.6 116.7h.6M149.8 116.5l.3 .2M150.1 100.3h.4l-.3 .6M150.2 104.3v.6h.3M150.2 118h.3v-.3h-.3v.6M150.2 117.1h-.6l.2 .3M150.2 117v.4"/>
<path d="M150.2 116.5l-.2 .2M150.3 118l.2 .3M150.7 104.5h.2M150.7 117.9l.2-.2v.6M150.7 118.3h.4M151 104.3h-.3v.6M151 100.3h-.3v.3h.3v.3h-.3M151.2 104.3h.3l-.2 .2h.2v.3h-.3M151.6 118l-.3 .1v-.3l.3-.1v.5l-.3 .1M151.8 117.9l.2-.2v.6M151.8 118.3h.4M152 104.3h-.2v.2h.2l.1 .3h-.3"/>
<path d="M152.1 103.2v.6h.3v-.6M152.3 104.3h.4l-.3 .6M152.8 103.4l-.1-.1 .3-.1v.2h-.2l-.1 .4h.3v-.4M153.6 103.4l-.2 .2-.1-.3h.3v.4l-.2 .1M157.7 106.5l.3 .1v.3l-.1 .2-.2-.1zM158.3 107v.1M158.5 106.5h.4v.2l-.4 .4h.4M158.6 100.7l-.3 .1v.3l.2 .2 .1-.1M158.9 100.9l.1-.2v.6M158.9 101.3h.3M159.1 106.5h.3l.1 .1-.5 .5h.5M159.2 107.6l-.2-.1-.2 .2 .2 .4h.2"/>
<path d="M159.5 100.7a.3 .3 0 0 1 .3 .3 .3 .3 0 0 1-.2 .3zM159.7 106.6v.4h.3M159.7 107.7l-.1 .2-.2-.2 .2-.2 .1 .1v.4l-.2 .1M160 100.7h.4l-.3 .2 .3 .2-.2 .2-.2-.1M160 106.6v.5M160.2 106.7h.3M160.3 107.7l-.2 .2-.1-.3h.3v.4l-.2 .1M160.3 105.5h.4v-.2l-.4-.1v.6M160.5 105.5l.2 .3M160.6 106.5h-.4v.6M160.8 104.2l.2-.2v.6M160.8 104.6h.4"/>
<path d="M160.9 105.4l.2-.2v.6M160.9 105.8h.3M161.5 104l.2 .1v.5h-.3l-.1-.2zM161.5 105.2h.3l-.2 .6M161.9 104v.6M162 105.2h.4l-.2 .3h.2v.2l-.4 .1M162 104.4l.2 .2M162.2 104.3l-.3 .1M165.1 105.5h.1l.2-.3-.3-.1v.6M165.1 105.5l.3 .2M165.5 104.2l.2-.2v.6M165.5 104.6h.3"/>
<path d="M165.6 105.3l.1-.2v.6M165.6 105.7h.3M166.2 104l.2 .3-.1 .3h-.2zM166.2 105.1h.4l-.3 .6M166.7 104v.6M166.8 105.2h.3l-.3 .5h.3M166.8 104.3l-.1 .1 .1 .2M167.7 100h.2l.1-.1-.3-.2v.6M167.8 100l.2 .3M168.2 100.3h.4M168.3 113.9l.3-.1 .3 .3-.6 .1zM168.3 113.3l.3-.1 .3 .2a.3 .3 0 0 1-.4 .3 .3 .3 0 0 1-.2-.4z"/>
<path d="M168.4 115.8h.2l.1-.4h-.3v.6M168.5 115.8l.2 .2M168.9 114.6h-.6l.1 .2M168.9 114.4v.4M169 115.6l.1-.2v.6M169 116h.3M169.9 115.7l-.4 .1v-.4l.4 .1-.1 .5h-.3M170.1 115.4l.4 .1-.4 .5h.4M173.2 104.3l.1 .6h.2v-.6M173.9 104.5l-.1-.1 .3-.1v.2l-.3 .1 .1 .3h.2l.1-.3-.2-.1M174.5 116.3v.6l.3-.2v-.4M174.5 104.5l-.1-.1 .3-.1v.2l-.3 .1 .1 .3h.2l-.1-.4"/>
<path d="M175.4 116.5l-.4 .1v-.3l.4 .1-.1 .4-.3 .1M175.7 116.5l-.1-.1 .3-.1v.2l-.3 .1 .1 .3 .2-.1-.1-.3M179.5 106.6h.3l.1-.2-.4-.1v.6M179.7 106.6l.2 .3M180.1 105.1h.4l-.2 .3h.2v.3l-.4-.1M180.1 106.5l.2-.2v.6M180.1 106.9h.4M180.6 102.4l.1-.2v.6M180.6 102.8h.3M180.6 106.3h.5l-.3 .6M180.7 105.1v.6M180.8 105.5l.2 .2"/>
<path d="M181 105.3l-.3 .2M181.1 102.4v.3h.3M181.2 106.5l.2-.2v.6M181.2 106.9h.4M181.3 103.3h-.3v.4l.3 .1M181.4 102.4v.4M181.6 103.3l.1-.1v.6M181.6 103.8h.3M181.7 102.5h.2M182 102.2h-.3v.6M182.2 103.3h.2v.5h-.2zM182.7 103.3l.1-.1v.6"/>
<path d="M182.7 103.8h.3M183.2 118.2l.3-.1v.2l-.3 .4h.3M183.8 118.2v.4h.2M184 118.2v.5M184.4 118.3h.1M184.6 118.1h-.2v.6M185.6 119.2v.3h.3v-.3l.3 .1-.1 .2M185.6 118.9h.6M185.8 118.7l.3 .2M186.1 119.8h.1M186.2 118.7l-.2 .1M186.4 106.7h.3v-.2h-.3v.6"/>
<path d="M186.6 106.7l.1 .4M186.7 105.1h.4l-.2 .3h.2v.2h-.4M187 106.6l.2-.1v.6M187 107.1h.3M187.3 105.1v.6M187.4 105.5l.2 .2M187.5 106.5h.4l-.2 .6M187.6 105.3l-.3 .2M187.9 102.4l.2-.2v.6M187.9 102.8h.4M188.1 106.6h.3v.3l-.1 .2-.2-.2zM188.4 103.3h-.2l-.2 .3 .1 .2h.3"/>
<path d="M188.5 102.4v.4l.3-.1M188.6 103.5l.2-.2v.6M188.6 103.9h.3M188.8 102.4v.4M189 102.5h.3M189.3 103.3h.2l-.1 .6-.2-.2zM189.4 102.2h-.4v.6M189.8 103.4h.3v.4l-.2 .1-.1-.1zM192.3 100.5v.5M192.9 100.5v.5l-.3-.5v.5M193 105.2v.6h.3v-.6M193.2 101l.1-.5 .3 .5"/>
<path d="M193.3 100.9h.2M193.8 105.5l-.2-.1 .2-.2 .1 .3-.3 .1 .1 .2h.2l-.1-.3M193.8 100.7v-.2h.2h.1l-.2 .2h-.1v.3l.3-.1-.2-.2M194.2 105.2h.3l-.2 .6M194.3 100.5h.3v.2l-.3 .3h.3M194.9 100.5h.3l-.2 .1 .2 .1v.3h-.3M198.2 105.7l.6 .1a.3 .3 0 0 1-.3 .2 .3 .3 0 0 1-.3-.3zM198.2 105.1h.6v.2l-.1 .2h-.4zM198.2 104.6l.5-.1 .1 .2-.1 .2h-.4zM198.8 105.5h.1l.2-.3-.3-.1v.6M198.8 106.4h-.6l.2 .2M198.8 106.2v.4"/>
<path d="M198.8 105.5l.3 .2M199.3 105.3l.1-.2v.6M199.3 105.7h.3M200.2 105.1l-.3 .2v.3l.3 .1v-.3l-.3 .1M200.8 105.4l-.4 .1v-.3h.4l-.1 .5h-.2M10.5 136.3l.3-.2-.1-.2h-.2v.6M10.5 136.3l.3 .2M11.3 135.9h-.2l-.1 .3v.3h.3v-.3l-.3 .1M11.6 136.1l.1-.2v.6M11.6 136.5h.3M12.3 135.2l.4-.1 .2 .1v.1l-.5 .1zM12.4 136.3h.4l.1 .2-.5 .1z"/>
<path d="M12.4 135.7h.4l.1 .2-.5 .1zM12.9 137h-.6l.2 .2M12.9 136.9v.3M17 135.8l.1 .6h.2v-.6M17.7 136.1l-.1-.3h.3l-.1 .3h-.2l.1 .3h.2l-.1-.3M21.7 137.8h-.3v.4l.3 .1M21.9 139l.2-.2v.6M21.9 137.7h.4l-.2 .3h.2v.3h-.4M21.9 139.4h.3M22.5 139v.4l.2-.1M22.5 137.7h.4l-.3 .6M22.7 139v.4"/>
<path d="M23.1 134.9h.3v-.2l-.3-.1v.7M23.1 139.1h.1M23.2 134.9l.2 .4M23.3 138.8h-.2v.6M23.6 135.9h.3l-.2 .3h.2v.3l-.3-.1M23.9 134.6l-.2 .1v.5l.1 .1 .2-.2-.2-.3-.1 .2M24.1 120.4h.3v-.3h-.3v.6M24.2 134.7h.3v.2l-.3 .4h.3M24.3 135.9v.6M24.3 136.3l.1 .2M24.3 120.4l.1 .3M24.4 136.1l-.1 .3"/>
<path d="M25 120.1h-.3v.3h.3l-.1 .3-.2-.1M25.4 120.4l-.1-.3h.2l.1 .2-.3 .1v.3l.3-.1-.2-.2M25.5 121.9v.2h.3l-.1-.1 .3-.2 .1 .2-.1 .1M25.5 121.5h.6M25.7 121.4l.3 .1M26 122.4h.1M26.1 122.9h-.6l.2 .2M26.1 122.6v.5M26.1 121.4l-.2 .1M27.2 123.1l.3-.1 .1 .1-.5 .5h.5M27.8 123.1v.5l.3-.1M28.1 123.1v.5"/>
<path d="M28.2 121.1h-.4v.4l.4 .1M28.3 123.2h.3M28.4 121h.3l-.1 .3 .1 .1v.2h-.3M28.7 123h-.4v.6M28.8 137.9h-.2l-.2 .2 .1 .3h.3M29 137.9h.3l-.1 .1 .1 .1v.3h-.3M29.1 121l-.1 .5h.3M29.2 139l.2-.2v.6M29.2 139.4h.4M29.3 121.3v.3M29.7 138.1l-.1-.2h.3l-.1 .2h-.2l.1 .4 .2-.1-.1-.3M29.8 139v.4l.3-.1"/>
<path d="M29.9 135.1h.2l.2-.3-.4-.1v.6M30 135.1l.3 .2M30.1 139v.4M30.2 135.9h.3l-.1 .3h.1v.3l-.3-.1M30.4 139.1h.1M30.6 138.8h-.2v.6M30.8 134.7h-.2l-.2 .3v.3h.4v-.3l-.4 .1M30.8 135.9v.6M30.9 136.3l.1 .2M31 134.7h.4l-.2 .3h.2v.3h-.4M31 136.1l-.2 .3M35.9 124.8v.5h.3v-.5"/>
<path d="M36.4 124.8h.4l-.2 .2h.2v.3h-.4M36.4 136.8l.1 .6h.3v-.6M37 124.8h.4l-.4 .5h.4M37 136.8h.5l-.3 .2h.2l.1 .3h-.5M37.6 136.8h.4l-.2 .2h.2v.4l-.4-.1M41.4 125.9h.3v-.2l-.3-.1v.6M41.5 125.9l.2 .3M42.2 125.6l-.2 .2v.4h.3l-.1-.3h-.2M42.6 125.6l.3 .3-.1 .3h-.3zM42.9 127.6l.4-.1 .2 .1v.2h-.6zM42.9 127h.6v.2l-.4 .1-.2-.1zM42.9 120.9h.6"/>
<path d="M42.9 120.5l.3 .4M43.5 128.2h-.6l.2 .2M43.5 121.3h-.6l.2 .2M43.5 121.1v.4M43.5 128.1v.3M43.5 120.5l-.4 .3M44.3 137.2l.2-.2v.6M44.3 137.6h.4M44.4 136.3l.3-.1v-.3h-.3v.6M44.6 136.3l.1 .2M44.9 137h.3v.6l-.3-.1zM45.3 135.9l-.3 .2v.4l.3-.1v-.2l-.3 .1"/>
<path d="M45.5 137v.6M45.5 137.4l.3 .2M45.8 137.2l-.3 .3M45.8 135.9h-.2v.3h.2l.1 .2h-.3M49 137.2l.1-.2v.6M49 137.6h.3M49.1 136.1h.3v-.3h-.3v.6M49.2 136.1l.2 .3M49.6 137.1h.3l-.1 .5-.2-.1zM49.9 120a.3 .3 0 0 1 .4 .3 .3 .3 0 0 1-.3 .3l-.2-.2zM49.9 135.8l-.2 .1v.5h.3l-.1-.4-.2 .2M50.2 137v.6"/>
<path d="M50.2 137.4l.2 .2M50.4 137.2l-.2 .3M50.5 120.5v.1M50.5 135.8l-.3 .1v.5h.4l-.1-.4-.3 .2M50.8 120h.2l.1 .2-.4 .4h.4M50.8 134.6l.2 .1v.5l-.2 .1-.1-.2v-.4zM51.3 120h.3v.3l-.3 .3h.3M51.3 135.2v.1M51.3 133.6h-.3l-.2 .2 .1 .3h.4M51.4 133.6h.4l-.2 .1 .2 .1v.3h-.4M51.5 134.7h.4v.2l-.4 .4h.4M51.9 120.2v.3h.2"/>
<path d="M52.1 134.7h.4v.2l-.4 .4h.4M52.1 120.2v.4M52.3 133.6h-.3v.5h.4l-.1-.4-.3 .2M52.5 120.3h.1M52.7 120h-.2v.6M52.7 134.8v.4h.3M53 134.8v.5M53.2 134.9h.3M53.6 134.6h-.4v.7M57.6 137.9l.1 .6 .3-.2v-.4M58.1 137.9h.4l-.1 .1 .1 .1v.3h-.4M58.5 136.8v.6h.4"/>
<path d="M59.1 137.9h-.3v.2l.2-.1 .1 .3-.1 .2-.2-.1M59.1 137h.1M59.3 136.8h-.2v.6M59.5 136.8h.4l-.3 .2h.2l.1 .3h-.4M59.6 123.7h.3l.1-.2-.4-.2v.6M59.7 123.7l.3 .2M60.4 136.8h-.2l-.1 .2h.3v.4l-.3-.1M60.5 123.3h-.3v.4l.3-.1v.3h-.3M60.7 136.8h.4l-.4 .6M61.1 123.6l-.3 .1-.1-.3h.4v.4l-.3 .1M61.5 124.6h.6M61.6 120.2h.6"/>
<path d="M61.7 124.3l.2 .3M62.1 125h-.6l.2 .2M62.1 124.8v.4M62.1 124.3l-.3 .2M62.2 120.6h-.6l.2 .2M62.2 120.4v.4M63.4 138.4l.1-.2v.6M63.4 137.5h.3v-.2h-.3v.6M63.4 138.8h.3M63.5 137.5l.2 .4M63.8 123.1h.2l-.1 .6a.37 .37 0 0 1-.3-.3 .37 .37 0 0 1 .2-.3zM64 138.3h.3l-.1 .5-.2-.1z"/>
<path d="M64.2 123.7h.1M64.2 137.3l-.2 .1v.4l.1 .1 .2-.2-.2-.2-.1 .1M64.5 137.3h.4l-.3 .6M64.6 123.1h.1l.2 .2-.4 .4h.4M64.6 138.2v.6M64.6 138.6l.2 .2M64.7 121.1l-.1-.1-.2 .2v.3l.3 .1M64.8 138.4l-.2 .2M65 121h.3l-.1 .3 .1 .1v.2h-.3M65.1 123.1h.3v.3l-.3 .3h.3M65.7 123.3v.4h.2M65.8 121h-.2v.4l.2-.1 .1 .2-.3 .1"/>
<path d="M65.9 123.3v.4M66.3 123.4h.1M66.5 123.1h-.2v.6M73 139.1l.1 .6 .3-.1v-.5M73.5 136.5v.6h.4M73.6 139.1h.4l-.2 .2h.2v.3h-.4M74 136.9h.2M74.2 139.1h.4l-.2 .6M74.3 136.5h-.3v.6M74.5 136.5h.4l-.3 .3h.2l.1 .2-.4 .1M75.4 136.5h-.3v.4l.3-.1 .1 .2-.4 .1M75.6 136.5h.5l-.3 .6"/>
<path d="M76.8 125v-.6l.2 .4 .2-.4v.6M77.9 124.5a.28 .28 0 0 0-.4 .1 .28 .28 0 0 0 .1 .4l.3-.1M78.1 124.8h.3v-.3l-.3-.1v.6M78.7 138.9h-.3v.4h.3M78.8 124.4l-.1 .4h.3M78.9 138.8h.4l-.3 .3h.3v.2h-.4M79 124.6v.4M79.2 124.6l.2-.2v.6M79.2 125h.3M79.9 139.1h-.4v-.3l.4 .1-.1 .4-.3 .1M80.1 124.4h-.2l-.1 .5h.3v-.2l-.3 .1M80.4 124.6l.2-.2v.6"/>
<path d="M80.4 138.1l.2-.1v.6M80.4 122.7v.6h.3v-.6M80.4 125h.3M80.4 138.6h.3M81 138.2l.1 .4h.2v-.4M81 122.7h.3l-.1 .3h.1v.3h-.3M81.6 122.9l.1-.2v.6M81.6 138.3h.1M81.6 123.3h.3M81.8 138h-.2v.6M82.4 120.1l.4-.2-.1-.1h-.3v.6M82.5 120.1l.3 .3"/>
<path d="M83.7 121.8v.2l.2 .1v-.3l.3-.1v.4M83.7 121.2h.5l.1 .3h-.6zM83.7 120.9h.6M83.9 120.7l.2 .2M84.3 122.5h-.6l.2 .1M84.3 122.3v.3M84.3 120.7l-.3 .2M127.4 121.6h.2l.1-.1-.3-.2v.6M127.5 120.1v.3h.2v-.3l.4 .1-.1 .2M127.5 121.6l.2 .3M127.9 121.5l.2-.2v.6M127.9 121.9h.4"/>
<path d="M128.1 120.9h-.6l.1 .1M128.1 120.7v.3M128.7 121.5h-.2l.2-.2 .1 .2-.3 .2 .1 .2h.2l-.1-.4M129.4 121.5l-.2 .2-.1-.3h.3v.4l-.2 .1M129.9 125.4l.3-.1v.6M129.9 125.9h.4M130.6 125.4v.5l.3-.1M130.9 125.4v.5M131.1 139.4v-.6l.2 .4 .2-.4v.6M131.1 125.5h.2M131.4 125.3h-.3v.6M132 124.5h-.3v.4h.3"/>
<path d="M132.1 138.9h-.3v.4h.3M132.3 124.6l.2-.2v.6M132.3 125h.3M132.4 139.1h.2l.1-.2-.3-.1v.6M132.9 124.4l.2 .1v.5h-.2l-.1-.2zM133.1 138.8l-.1 .4h.3M133.2 139v.4M133.6 139l.1-.2v.6M133.6 139.4h.3M133.7 124.7l-.3 .1v-.3h.3l-.1 .5h-.1M134.4 138.8h-.2l-.1 .3v.2l.3 .1v-.3h-.3M134.7 139l.1-.2v.6"/>
<path d="M134.7 139.4h.3M135.8 126.7v.6h.3M136.3 127h.2M136.6 126.7h-.3v.6M136.8 126.7h.3l-.2 .3h.2v.2h-.3M137.2 124.2l.1 .6h.2v-.6M137.6 126.7h-.2v.3h.2l.1 .2h-.3M137.9 126.7h.4l-.3 .6M138.2 124.4l-.2 .2-.2-.3 .2-.1 .2 .1-.1 .5h-.2M138.4 124.2h.4l-.2 .6M145.7 120l-.4 .1v.3l.2 .2 .2-.1M145.9 120.2l.2-.2v.6"/>
<path d="M145.9 120.6h.4M146.5 120.2l.2-.2v.6M146.5 120.6h.4M146.7 126.3h.3v-.3l-.3-.1v.7M146.9 126.3l.1 .3M147 125.2l.2-.2v.6M147 120l.4 .1-.4 .5h.4M147 125.6h.4M147.3 126.2l.1-.3v.7M147.3 126.6h.3M147.6 125l.3 .1v.5h-.3l-.1-.2zM148 126.3l-.2-.2 .2-.2 .1 .1v.2l-.3 .2 .2 .2 .1-.1-.1-.2"/>
<path d="M148.1 125v.6M148.2 125.4l.2 .2M148.4 125.3l-.3 .1M148.5 139h.6M148.6 138.7l.3 .3M148.7 125.9a.35 .35 0 0 0-.3 .3 .35 .35 0 0 0 .2 .4v-.4l-.2 .2M149.1 139.4h-.6l.1 .2M149.1 139.2v.4M149.1 138.7l-.3 .2M149.6 122.8l.3-.1-.1-.2h-.2v.6M149.6 121.2h.6M149.7 120.9l.3 .3"/>
<path d="M149.7 122.8l.2 .3M150.2 121.6h-.6l.1 .2M150.2 122.6l.1-.1v.6M150.2 121.5v.3M150.2 120.9l-.3 .2M150.2 123.1h.3M150.4 139.9h-.2l-.1 .3v.2l.3 .1v-.3l-.3 .1M150.8 126.4v.6h.3M150.8 122.7l-.1-.1 .2-.1 .1 .2-.3 .2v.2h.3l-.1-.4M151.3 122.5h.3l-.3 .6M151.3 126.8h.2M151.6 126.4h-.3v.6"/>
<path d="M151.8 126.4h.3l-.2 .3 .2 .1v.2h-.3M152.7 126.4h-.3v.4h.3v.2h-.3M152.7 125.3v.6h.3v-.6M152.9 126.4h.4l-.3 .6M153.6 125.6l-.1 .2-.2-.3 .2-.2 .1 .1v.5h-.2M154.2 125.3h-.3v.4h.3v.2h-.3M158.3 128.7h.3v.4l-.1 .1-.2-.1zM158.9 129.2h.1M159.1 128.7h.4v.2l-.4 .3h.4M159.2 121l.3 .3-.1 .3h-.3zM159.2 122.9l-.3 .1v.3l.1 .2 .2-.1M159.5 129.8l-.2-.1-.2 .1v.4l.4 .1"/>
<path d="M159.5 123.1l.1-.2v.6M159.5 123.5h.3M159.7 128.7h.3l.1 .1-.5 .4h.5M159.7 121.6h.1M159.7 129.8l.2-.1v.6M159.7 130.3h.4M160 121.1l.1-.1 .2 .2-.4 .4h.4M160.1 123.1l.1-.2v.6M160.1 123.5h.3M160.3 128.8v.4h.3M160.4 129.7l.3 .2-.1 .4h-.3zM160.5 121.1h.3l-.3 .5h.3"/>
<path d="M160.6 128.8v.4M160.7 122.9a.3 .3 0 0 1 .3 .2 .3 .3 0 0 1-.3 .4zM160.8 128.9h.3M161 127.7l.3-.1-.1-.2h-.2v.7M161.1 127.7l.2 .4M161.2 128.7h-.4v.5M161.2 121.3v.3h.2v-.3M161.2 129.7l-.3 .1v.5l.3-.1v-.3l-.3 .1M161.4 126.4l.2-.2v.6M161.4 126.8h.4M161.5 127.6l.2-.2v.7M161.5 128.1h.3"/>
<path d="M161.7 121.4h.1M161.9 121h-.2v.6M162.1 126.2l.2 .1v.5h-.3l-.1-.2zM162.2 127.7v-.3l.2 .1-.1 .2h-.2l.1 .4 .2-.1-.1-.3M162.5 126.2v.6M162.6 126.6l.2 .2M162.8 126.4l-.3 .2M162.9 127.4h-.2v.3l.2-.1 .1 .3-.1 .2-.2-.1M165.7 127.6l.3-.1-.1-.2h-.2v.6M165.7 127.6l.3 .3M166.1 126.4l.1-.2v.6M166.1 126.8h.3"/>
<path d="M166.2 127.5l.2-.2v.6M166.2 127.9h.4M166.8 126.2l.2 .2-.1 .4h-.2zM166.9 127.6l-.1-.2 .3-.1v.3h-.3v.3h.3l-.1-.3M167.1 136.1h.5v.3h-.5zM167.1 135.5h.5v.3h-.3l-.3-.1zM167.3 126.2v.6M167.4 126.4l-.1 .2 .1 .2M167.5 127.3l-.2 .4h.4M167.6 136.8h-.6l.2 .1M167.6 127.5v.4M167.6 136.6v.3"/>
<path d="M167.8 138h.2l.1-.3-.3-.1v.6M167.9 138l.2 .2M168.3 122.2h.2l.1-.2-.3-.1v.6M168.3 120.6h.6M168.3 120.3l.3 .3M168.4 122.2l.2 .3M168.6 137.6l-.2 .2v.4l.3-.1-.1-.2-.2 .1M168.9 121h-.6l.1 .2M168.9 122l.1-.1v.6M168.9 120.9v.3M168.9 120.3l-.4 .2M168.9 122.5h.3"/>
<path d="M169 137.6l-.1 .4h.4M169.2 137.8v.4M169.5 122.1l-.1-.1 .2-.1 .1 .2-.3 .2 .1 .2h.2l-.1-.4M170.1 122.1v-.2l.2 .1v.1l-.3 .1v.3h.3l-.1-.4M173.2 138.5l.1 .6h.2v-.6M173.4 121.5v.6h.4M173.8 126.4l.1 .6h.3v-.6M173.8 138.5h.4l-.3 .2h.2l.1 .3h-.4M173.9 121.8h.2M174.2 121.5h-.3v.6M174.4 121.5h.4l-.3 .3h.3v.2h-.4M174.7 138.5h-.2l-.1 .2v.3l.3 .1v-.4l-.3 .1"/>
<path d="M174.8 126.7l-.3 .2v-.5l.3 .1-.1 .5h-.2M175.1 126.4l-.1 .5h.4M175.3 121.5h-.3v.3h.3l.1 .2h-.4M175.3 126.7v.3M175.6 121.5h.4l-.3 .6M180.1 128.8h.4v-.2l-.4-.1v.6M180.3 128.8l.2 .3M180.7 127.3h.4l-.2 .3h.2v.3l-.4-.1M180.7 128.7l.2-.2v.6M180.7 129.1h.4M181.1 124.6l.2-.2v.6M181.1 125h.4"/>
<path d="M181.3 127.3v.6M181.4 128.7l-.1-.1 .2-.1 .2 .2-.4 .1v.3l.4-.1-.2-.3M181.4 127.6l.2 .3M181.6 127.5l-.3 .2M181.7 124.6l.1 .4 .3-.1M181.8 128.5h.4l-.2 .2h.2v.4h-.4M181.9 125.4l-.2-.1-.1 .2v.4h.3M182.1 124.6v.4M182.2 125.5l.1-.2v.6M182.2 125.9h.3M182.2 120l-.3 .1v.3l.2 .2 .1-.1M182.3 124.7h.2"/>
<path d="M182.5 120.2l.2-.2v.6M182.5 120.6h.3M182.6 124.4h-.3v.6M182.8 125.3l.3 .3-.1 .3h-.2zM183.1 120.2l.2-.2v.6M183.1 120.6h.3M183.4 125.6l-.1-.1 .2-.2 .1 .3-.3 .2v.1h.3l-.1-.3M183.7 120.2l.2-.2v.6M183.7 120.6h.3M185.6 121.3h.3l.1-.4h-.4v.6M185.8 121.3l.2 .2M186.2 120.2h-.6l.2 .2"/>
<path d="M186.2 121.1l.2-.2v.6M186.2 121.5h.4M186.2 120v.4M187 128.9h.3v-.2h-.3v.5M187.2 121.2l-.4 .1v-.4l.4 .1-.1 .5h-.3M187.2 128.9l.1 .3M187.3 127.3h.4l-.2 .3h.2v.3l-.4-.1M187.4 120.9h.3v.6h-.3zM187.6 128.8l.1-.1v.5M187.6 129.2h.3M187.9 127.3v.6M188 127.6l.2 .3"/>
<path d="M188.2 127.5l-.3 .2M188.3 128.9l-.2-.2h.3v.1l-.3 .2 .2 .2h.1l-.1-.3M188.5 124.6l.2-.2v.6M188.5 125h.3M188.7 128.7h.3v.2l-.3 .3h.3M189 125.5h-.2a.28 .28 0 0 0-.2 .4 .28 .28 0 0 0 .4 .1M189.1 124.6v.4l.3-.1M189.3 125.7l.1-.2v.6M189.3 126.1h.3M189.4 124.6v.4M189.6 124.7h.3M189.9 125.5h.2l-.1 .6h-.1l-.1-.2z"/>
<path d="M189.9 124.4h-.3v.6M190.4 125.5h.3l-.2 .6M192.9 122.6v.6M193.6 122.6v.6l-.3-.6v.6M193.6 127.4v.5l.2 .2 .1-.1v-.6M193.8 123.2l.1-.6 .3 .6M193.8 123.1h.3M194.4 122.9v-.3h.2l.1 .2-.3 .1v.3l.3-.1-.2-.2M194.5 127.7h-.3l.2-.3 .1 .1v.4l-.2 .2M194.8 127.4h.3l-.2 .2 .2 .1v.3h-.3M194.9 122.6h.3v.3l-.3 .3h.3M195.5 122.6h.3l-.2 .3h.2v.3l-.3-.1"/>
<path d="M198.8 127.9h.5l.1 .2h-.6zM198.8 127.4l.5-.1 .1 .3h-.5zM198.8 126.8l.5-.1 .1 .3h-.6zM199.3 127.6h.2l.2-.2-.4-.1v.6M199.4 128.6h-.6l.2 .1M199.4 128.4v.3M199.4 127.6l.3 .3M199.9 127.5l.2-.2v.6M199.9 127.9h.4M200.6 127.6l-.2-.2 .4-.1v.3h-.4l.1 .3h.3l-.1-.3M201 127.5l.2-.2v.6M201 127.9h.4"/>
<path d="M10.5 158.5h.2l.1-.3-.3-.1v.6M10.5 158.5l.3 .2M11.1 158.4l-.1-.1v-.2l.4 .1-.4 .3v.2l.4-.1-.2-.2M11.9 158.1h-.3v.4l.3-.1v.3h-.3M12.3 158.5h.5l.1 .2-.5 .1zM12.3 157.9h.4h.2v.2l-.5 .1zM12.9 159.2h-.6l.2 .2M12.9 159v.4M16 140.6v.6M16.6 140.6v.6l-.3-.6v.6M16.7 158l.1 .6 .3-.1v-.5M16.8 141.2l.3-.6 .1 .6"/>
<path d="M16.9 141h.2M17.4 157.9l-.1 .5h.4M17.5 140.8l-.1-.1 .3-.1v.2h-.2l-.1 .4h.3v-.4M17.6 158.2v.4M18 140.7l.2-.1 .1 .2-.4 .4h.4M18 157.9l-.2 .5h.4M18.2 158.2v.4M18.5 140.6h.4l-.2 .2h.1l.1 .3-.4 .1M21.7 160h-.3v.4l.3 .1M22.3 159.9h-.3v.3h.3v.3h-.3M23.1 157.1h.3v-.3h-.3v.6M23.2 157.1l.2 .3"/>
<path d="M23.6 158.1h.3l-.2 .3h.2v.3h-.3M23.7 157.1v-.3l.3 .1-.3 .2v.3l.3-.1-.2-.2M24.1 142.6h.3v-.3h-.3v.6M24.3 158.1v.6M24.3 142.6l.1 .3M24.4 158.4l-.1 .1 .1 .2M24.5 156.8h-.2l-.1 .3 .1 .3h.2l-.1-.4-.2 .2M24.7 142.3h.3l-.2 .6M25.5 144.1v.2h.3l-.1-.2 .3-.1 .1 .1-.1 .2M25.5 142.3l-.2 .2v.4l.3-.1-.1-.3-.2 .1M25.5 143.7h.6M25.7 143.6l.3 .1"/>
<path d="M26 144.7h.1M26.1 145.1h-.6l.2 .1M26.1 144.9v.3M26.1 143.6l-.2 .1M27.2 145.2h.3l.1 .1-.5 .5h.5M27.8 145.4v.4h.3v-.4M28.2 143.3h-.4v.5h.4M28.3 145.5h.3M28.6 143.2l-.2 .4h.3M28.7 145.2h-.4v.6M28.7 143.5v.4M28.9 143.2h.4l-.2 .3 .2 .2-.1 .2-.3-.1"/>
<path d="M29.9 157.3l.4-.2-.1-.2h-.3v.6M30 157.3l.3 .2M30.2 158.1h.3l-.1 .3h.1v.3h-.3M30.6 157.2l-.2-.2 .4-.1v.3l-.4 .1 .1 .2h.3l-.1-.3M30.8 158.1v.6M30.9 158.5l.1 .2M31 156.9h.5l-.4 .6M31 158.4l-.2 .1M35.9 141.7v.6h.3M35.9 146.9v.6h.3v-.6M36.4 141.9h.2M36.4 146.9h.4l-.2 .3h.2v.3h-.4"/>
<path d="M36.4 159l.1 .6h.3v-.6M36.7 141.7h-.3v.6M36.9 141.7h.3l-.2 .2h.2v.3h-.3M37.2 159l-.2 .4h.5M37.4 147.2l-.3 .2-.1-.4h.4v.4l-.3 .1M37.4 159.1v.5M37.7 141.7h-.2v.2h.2l.1 .3h-.3M38 141.7h.4l-.3 .6M38 159h-.3l-.1 .2h.4v.4l-.4-.1M41.4 148.1h.3v-.2l-.3-.1v.6M41.5 141.7l.4-.2-.1-.1h-.3v.5M41.5 148.1l.2 .3"/>
<path d="M41.6 141.7l.3 .2M42 141.4h.5l-.3 .5M42 148v-.2l.3 .1v.1l-.3 .1v.3h.3l-.1-.4M42.5 148l.2-.2v.6M42.5 148.4h.4M42.6 141.4h.4l-.2 .2h.2v.3h-.4M42.9 149.8l.6-.1v.3l-.4 .1-.2-.1zM42.9 149.2l.6-.1v.3l-.5 .1zM42.9 143h.6M42.9 142.7l.3 .3M43.5 143.5h-.6l.2 .1M43.5 150.4h-.6l.2 .2"/>
<path d="M43.5 143.3v.3M43.5 150.2v.4M43.5 142.7l-.4 .3M44.3 159.4l.2-.2v.6M44.3 159.8h.4M44.4 158.5h.3v-.3l-.3-.1v.6M44.6 158.5l.1 .2M45 159.2h.2l.1 .3-.1 .3-.3-.1zM45.1 158.4l-.1-.3 .3 .1v.2l-.3 .1v.2h.3v-.3M45.5 159.2v.6M45.5 159.6l.3 .2M45.8 159.4l-.3 .2"/>
<path d="M45.9 158.4l-.2 .1-.1-.4 .3 .1-.1 .5h-.2M49 159.4l.1-.2v.6M49 159.8h.3M49.1 158.3h.3v-.3h-.3v.6M49.2 158.3l.2 .3M49.6 159.3h.3l-.1 .5-.2-.1zM49.9 142.2a.3 .3 0 0 1 .4 .2 .3 .3 0 0 1-.3 .4l-.2-.3zM50 158.3l-.3 .1v-.4h.3v.5l-.3 .1M50.2 159.2v.6M50.2 158l.4 .1v.4l-.2 .1-.2-.1zM50.2 159.6l.2 .2M50.4 159.4l-.2 .2"/>
<path d="M50.5 142.7v.1M50.7 156.9l.3-.1v.6h-.2l-.1-.1zM50.8 142.2h.2l.1 .2-.4 .4h.4M51.2 140.4h-.4v.5h.4M51.3 142.2h.3v.3l-.3 .3h.3M51.3 157.4h.1M51.3 155.7h-.3a.28 .28 0 0 0-.1 .4 .28 .28 0 0 0 .4 .2M51.5 156.8h.4v.3l-.4 .3h.4M51.6 140.3l-.2 .5h.4M51.7 140.6v.4M51.8 155.7h-.3l-.1 .3h.4v.3h-.4M51.9 142.4v.3h.2"/>
<path d="M52 155.8h.4l-.1 .5h-.3zM52.1 156.8h.4v.3l-.4 .3h.4M52.1 140.3a.35 .35 0 0 1 .3 .4 .35 .35 0 0 1-.3 .3zM52.1 142.4v.4M52.5 142.5h.1M52.7 142.2h-.2v.6M52.7 157v.4h.3M53 157v.4M53.2 157.1h.3M53.6 156.8h-.4v.6M58.4 160l-.2 .5h.3M58.5 159v.6h.4"/>
<path d="M59.1 159.2h.1M59.3 159h-.2v.6M59.5 159h.4l-.3 .2 .3 .1v.2h-.4M59.6 145.8h.3l.1-.1-.4-.2v.6M59.7 145.8l.3 .3M60.2 145.5h.4l-.3 .6M60.2 141h.3l.1-.2h-.4v.6M60.3 141l.3 .4M60.4 159h-.2l-.1 .2h.3v.4l-.3-.1M60.7 159h.4l-.4 .6M60.7 140.8h.5l-.3 .6M60.7 145.5h.4l-.3 .6"/>
<path d="M61.3 140.9l.2-.1v.6M61.3 141.4h.4M61.5 146.8h.6M61.6 142.4h.6M61.7 146.5l.2 .3M61.8 142.1l.2 .3M62.1 147.2h-.6l.2 .2M62.1 147v.4M62.1 146.5l-.3 .2M62.2 142.8h-.6l.2 .2M62.2 142.6v.4M62.2 142.1l-.2 .2"/>
<path d="M63.4 159.7h.3v-.2h-.3v.6M63.5 159.7l.2 .4M63.7 145.3h.3l-.1 .6-.3-.2zM64.2 145.8v.1M64.3 159.7l-.3 .1v-.3l.3 .1-.1 .4-.2 .1M64.5 159.6l.1-.1v.6M64.6 145.3h.2l.1 .2-.4 .4h.4M64.7 143.3l-.1-.1-.2 .2v.3l.2 .2 .1-.1M65.1 145.3h.3v.3l-.3 .3h.3M65.2 143.2l-.2 .4h.3M65.2 143.5v.4M65.7 145.5v.3h.2"/>
<path d="M65.7 143.2l-.1 .4h.3M65.8 143.5v.4M65.9 145.5v.4M66.3 145.6h.1M66.5 145.3h-.2v.6M72.9 158.7v.6h.4M73.4 159h.2M73.7 158.7h-.3v.6M73.9 158.7h.4l-.3 .3h.2l.1 .2-.4 .1M74.8 158.7h-.3v.3h.3v.3h-.3M75.1 158.7h.4l-.4 .6M76.8 147.2v-.6l.2 .4 .2-.4v.6"/>
<path d="M77.9 146.7l-.3-.1-.2 .3 .2 .3h.3M78.1 146.9h.3v-.3h-.3v.6M78.8 146.6l-.1 .4h.3M79 146.9v.3M79.2 146.8l.2-.2v.6M79.2 147.2h.3M80.1 146.6l-.3 .2v.4h.3v-.3h-.3M80.4 146.8l.2-.2v.6M80.4 144.9v.6h.3v-.6M80.4 147.2h.3M81.2 144.9l-.2 .4h.4M81.3 145.2v.3"/>
<path d="M81.6 145.1l.1-.2v.6M81.6 145.5h.3M82.4 142.3h.2l.2-.3-.4-.1v.6M82.5 142.3l.3 .2M82.9 141.9h.5l-.3 .6M83.7 144v.2l.2 .1v-.3h.4l-.1 .3M83.7 143.4h.5l.1 .2-.5 .1zM83.7 143.1h.6M83.9 141.9h-.3l-.1 .3h.4v.3h-.4M83.9 142.9l.2 .2M84.3 144.7h-.6l.2 .1M84.3 144.5v.3"/>
<path d="M84.3 142.9l-.3 .1M119.3 147.2h.6l-.6 .3h.6M119.3 146.6h.6l-.6 .3h.6M119.3 146v.3h.6v-.3M119.3 150.2h.6M119.3 144.9v.3M119.3 145.1h.6M119.4 151v.3h.5v-.3l-.2 .1M119.4 149.5h.4l.1 .3h-.5zM119.4 148.5l-.1 .1 .2 .2h.3l.1-.3M119.4 147.8h.4l.1 .3-.5 .1zM119.4 145.4l-.1 .2 .2 .2h.3l.1-.4"/>
<path d="M119.4 144.3h.4l.1 .4h-.5zM119.7 150.7v-.3h-.3l-.1 .3h.6M119.7 144.1v-.3l-.3-.1-.1 .4h.6M119.7 146.1v.2M119.9 143.7l-.2 .2M120 148.9v.5M120.4 147.7h.5l.1 .3M121 147.1v.4l-.4-.4-.2 .2 .1 .1M121.1 154.1v.2l.4 .1-.1-.3h.3v.3M121.1 153.5l.6 .1-.6 .3M121.1 142.2v-.3l.3 .1 .1-.1h.2v.3M121.1 141.4v-.4l.3 .2 .1-.2h.2v.4"/>
<path d="M121.1 140.4l.6 .3-.6 .1M121.3 154.9h.4M121.3 142.7h.4M121.5 142.5v.5M121.5 154.6v.5M121.7 141.6h.1M127.5 142.3v.3h.2v-.3l.4 .1-.1 .2M127.5 141.8l.3-.1 .3 .1v.1l-.5 .1zM127.5 141.4h.6M127.6 141.3l.3 .1M127.9 143.8h.3l.1-.2-.4-.1v.6M128.1 143h-.6l.1 .2"/>
<path d="M128.1 142.9v.3M128.1 141.3l-.3 .1M128.1 143.8l.2 .3M128.5 143.5h.4l-.2 .6M129.2 143.5l.2 .1v.4l-.2 .1-.1-.5zM129.9 147.6l.3-.2v.6M129.9 140.5v.6l.4-.1v-.5M129.9 148h.4M130.4 140.5h.5l-.3 .3h.3v.2h-.5M130.6 147.6v.4h.3M130.9 147.6v.4M131.1 147.7h.2"/>
<path d="M131.2 140.5l-.1 .4h.3M131.4 147.4h-.3v.6M131.4 140.7v.4M132.3 146.7l-.3-.1v.2v.3l.3 .1M132.7 146.6l-.2 .4h.4M132.8 146.9v.3M133.4 146.6l-.3 .2v.4l.4-.1-.1-.2h-.3M135.8 148.9v.6h.3M136.3 149.1h.2M136.6 148.9h-.3v.6M136.8 148.9h.3l-.2 .2h.2v.3h-.3M137.2 146.3l.1 .6h.2v-.6"/>
<path d="M137.6 148.9h-.2v.2h.2l.1 .3h-.3M137.8 146.3h.4l-.2 .3h.1l.1 .3h-.4M137.9 148.9h.4l-.3 .6M138.6 146.6l-.2-.1 .2-.2 .1 .3-.3 .2 .1 .1h.2l-.1-.3M144.1 140.2a.3 .3 0 0 1 .4 .2 .3 .3 0 0 1-.3 .4l-.1-.3zM144.7 140.7v.1M145 140.2h.2l.1 .1-.4 .5h.4M145.1 142.2h-.3a.33 .33 0 0 0-.1 .4 .33 .33 0 0 0 .3 .2l.1-.1M145.4 142.1l-.1 .4h.4M145.5 140.2h.3v.2l-.3 .4h.3M145.6 142.4v.4M145.8 147.4l.2-.2v.6"/>
<path d="M145.8 148.5h.3v-.3h-.3v.6M145.8 147.8h.4M145.8 142.4l.2-.2v.6M145.8 142.8h.4M145.9 148.5l.2 .3M146.1 140.3v.4h.2M146.3 148.2h.4l-.3 .6M146.3 140.3v.5M146.5 147.2l.2 .1v.5h-.3l-.1-.2zM146.7 140.4h.2M146.9 140.2h-.2v.6M146.9 147.2v.6"/>
<path d="M147 148.5l-.1-.3h.3l.1 .1-.4 .2 .1 .3 .3-.2-.2-.1M147 147.6l.2 .2M147.2 147.4l-.3 .2M148.3 143.4h.6M148.5 143.1l.2 .3M148.9 143.8h-.6l.2 .2M148.9 145h.3v-.3h-.3v.6M148.9 143.6v.4M148.9 143.1l-.2 .2M149.1 145l.1 .3M149.5 140.3h.2l.2-.3-.4-.1v.6M149.5 144.7h.4l-.3 .6"/>
<path d="M149.6 148.6v.6h.3M149.6 140.3l.3 .2M150.1 149h.2M150.2 144.7l-.1 .4h.3M150.3 144.9v.4M150.4 148.6h-.3v.6M150.6 148.6h.3l-.2 .3 .2 .1v.2h-.3M150.7 140.2v-.3h.3v.2l-.3 .2v.2l.3-.1-.1-.2M151.4 148.6h-.2v.4l.2-.1 .1 .2-.3 .1M151.5 147.5l.1 .7 .2-.1v-.6M151.7 148.6h.4l-.3 .6M152.3 147.5l-.2 .5h.3"/>
<path d="M152.4 147.8v.4M152.8 147.5l.2 .2v.3l-.1 .2-.2-.1zM157.1 150.8a.3 .3 0 0 1 .4 .3 .3 .3 0 0 1-.3 .3zM157.7 151.3v.1M157.9 150.8h.4v.3l-.4 .3h.4M158 143.2l.2 .1-.1 .6a.37 .37 0 0 1-.3-.3 .37 .37 0 0 1 .2-.4zM158.5 143.8v.1M158.5 150.8h.3l.1 .2-.4 .4h.4M158.6 151.9l-.1-.1-.3 .2v.4l.3 .1 .1-.1M158.6 145.1l-.3 .1v.4h.3M158.8 143.3l.2-.1 .1 .3-.4 .4h.4M159 151.8l-.2 .5h.4"/>
<path d="M159 145l-.1 .4h.3M159.1 151v.3h.3M159.1 145.2v.5M159.1 152.1v.4M159.3 143.3h.3v.3l-.3 .3h.3M159.4 151v.4M159.6 151.1h.2M159.7 152.2h-.3l.1-.4 .2 .1v.5l-.2 .1M159.7 145.1h-.2l-.1 .2 .2-.1 .1 .4h-.3M159.9 150.8h-.3v.6M159.9 143.5v.3h.2M160.1 149.9h.2l.1-.2-.3-.1v.6"/>
<path d="M160.1 148.5l.3-.1v.6M160.1 143.5v.4M160.1 149h.5M160.1 149.9l.3 .3M160.5 143.6h.2M160.6 149.6h.4l-.3 .6M160.7 143.2h-.2v.7M160.9 148.4l.2 .1v.5h-.3l-.1-.2zM161.3 148.4v.6M161.4 148.8l.2 .2M161.5 149.9l-.3 .1v-.3l.3-.1v.5l-.3 .1M161.6 148.6l-.3 .2"/>
<path d="M164.7 149.8l.4-.1-.1-.2h-.3v.6M164.9 148.5l.2-.1v.6M164.9 149h.3M164.9 149.8l.2 .3M165.4 149.7l-.1-.2h.3l.1 .1-.4 .2v.3l.4-.1-.2-.3M165.6 148.4l.2 .2-.1 .4h-.2l-.1-.2zM165.9 149.5h.3v.6h-.3l-.1-.2zM166.1 148.4v.6M166.2 148.6l-.1 .2 .1 .2M167 142.8h.6M167 142.5l.3 .3M167.6 158.4a.37 .37 0 0 1 .4-.2 .37 .37 0 0 1 .3 .3h-.6z"/>
<path d="M167.6 157.8h.7a.35 .35 0 0 1-.4 .2 .35 .35 0 0 1-.3-.2zM167.6 143.2h-.6l.2 .2M167.6 144.4h.3v-.3h-.3v.6M167.6 143v.4M167.6 142.5l-.3 .2M167.8 144.4l.1 .3M168.2 144.1h.4l-.2 .6M168.3 159h-.7l.3 .1M168.3 158.8v.3M168.8 144.1h.3l-.3 .6h.3M172.3 143.7v.6h.3M172.6 148.6l.1 .6h.2v-.6"/>
<path d="M172.8 144.1h.1M173 143.7h-.2v.6M173.2 143.7h.4l-.2 .3h.1l.1 .2-.4 .1M173.4 148.6l-.2 .5h.4M173.5 148.9v.3M173.8 148.7h.3l-.3 .5h.3M174.1 143.7h-.2l-.1 .4 .3-.1v.3h-.3M174.4 143.7h.4l-.3 .6M179.2 151h.3v-.3h-.3v.6M179.4 151l.1 .3M179.5 149.5h.4l-.2 .2 .2 .1v.3h-.4M179.9 150.9l-.1-.2h.2l.1 .2-.3 .1v.3h.3l-.1-.4"/>
<path d="M180 146.8l.1-.2v.6M180 147.2h.3M180.1 149.5v.6M180.2 149.9l.2 .2M180.4 150.7h.3l-.3 .6h.3M180.4 149.7l-.3 .2M180.6 146.9v.3h.2v-.3M181 147.6l-.2-.1-.2 .2v.3l.2 .2 .2-.1M181.1 146.9h.2M181.4 146.6h-.3v.6M181.4 147.5l-.2 .5h.5M181.6 147.8v.4"/>
<path d="M181.7 142.2l-.4 .1v.4h.4M181.8 147.5h.4l-.3 .7M182 140.3h.3l-.3 .5h.3M182 142.1l-.1 .4h.3M182.2 142.4v.4M182.4 142.2h.4v.3l-.4 .3h.4M182.6 140.4v.4h.2M182.8 140.4v.4M183.1 140.5h.2M183.4 140.3h-.3v.5M184.4 141.4v.3h.3v-.3h.3v.3M184.4 141.1h.6"/>
<path d="M184.6 140.8l.3 .3M185 141.9h.1M185 142.4h-.6l.2 .1M185 143.5l.4-.1-.1-.3h-.3v.6M185 142.2v.3M185 140.8l-.2 .2M185.2 143.5l.2 .2M185.9 143.1l-.3 .2v.4l.4-.1-.1-.2-.3 .1M186.1 151.1h.3v-.3h-.3v.6M186.1 149.5h.4l-.2 .2 .2 .1v.3h-.4M186.2 151.1l.2 .3M186.5 143.4l-.3 .1-.1-.3 .4-.1v.5l-.3 .1"/>
<path d="M186.7 151.1l-.1-.3h.4l-.1 .3h-.3l.1 .3 .3-.1-.1-.2M186.7 149.5v.6M186.8 149.9l.2 .2M187 149.7l-.3 .2M187.2 150.8h.4l-.3 .2 .3 .3-.2 .1-.2-.1M187.3 146.8l.2-.2v.6M187.3 147.2h.4M187.9 146.9v.3h.3v-.3M188.1 147.8h-.4v.4h.4M188.4 147.7l-.1 .4h.4M188.4 146.9h.3M188.6 147.9v.4"/>
<path d="M188.8 146.6h-.4v.6M189 148l-.2-.2 .4-.1 .1 .2-.5 .1 .1 .3 .4-.1-.2-.2M191.7 144.8v.6M192.3 144.8v.6l-.3-.6v.6M192.4 149.6l.1 .6h.2v-.6M192.6 145.4l.1-.6 .2 .6M192.6 145.2h.3M193.2 149.6l-.2 .4h.4M193.3 145.1l-.2-.2 .3-.1 .1 .2-.4 .2 .1 .2 .3-.1-.2-.2M193.3 149.8v.4M193.6 149.6h.3l-.1 .2 .1 .1v.3h-.3M193.7 144.9l.3-.1v.3l-.3 .3h.3"/>
<path d="M194.3 144.8h.3l-.2 .3h.2v.2h-.3M197.7 150.1l.5 .1a.3 .3 0 0 1-.3 .2 .3 .3 0 0 1-.2-.3zM197.7 149l.3-.1 .2 .2-.5 .1zM197.7 149.5h.4l.1 .1-.1 .2h-.4zM198.2 150.7h-.5l.1 .3M198.2 150.6v.4M198.7 149.8h.3v-.3h-.3v.6M198.8 149.8l.2 .3M199.3 149.7v-.1l.2-.1 .1 .2h-.3v.4h.3l-.1-.4M200 149.5l-.1 .4h.3M200.1 149.7v.4M12.3 179.6l.5-.1 .1 .3-.3 .1-.3-.1z"/>
<path d="M16 162.8v.6M16.6 162.8v.6l-.3-.6v.6M16.8 163.4l.3-.6 .1 .6M16.9 163.2h.2M17.5 163l-.1-.1 .3-.1v.2l-.3 .1v.3h.3v-.4M18 162.9l.2-.1 .1 .2-.4 .4h.4M18.5 162.8h.4l-.2 .2 .2 .1v.2l-.4 .1M21.9 161.2l.2-.2v.6M21.9 161.6h.3M22.5 161.2v.4h.2v-.4M22.6 160.1l.1-.2v.6M22.6 160.5h.3"/>
<path d="M22.8 179.3h.3l.1-.2-.4-.1v.6M22.9 179.3l.3 .3M23.1 161.3h.1M23.3 161h-.2v.6M23.3 179.2l.2-.2v.6M23.3 179.6h.4M23.9 179.2l.2-.2v.6M23.9 179.6h.4M24.1 164.8h.3v-.3h-.3v.6M24.3 164.8l.1 .3M24.5 179a.3 .3 0 0 1 .4 .3 .3 .3 0 0 1-.3 .3zM24.7 164.6l.1-.1v.6"/>
<path d="M24.7 165.1h.3M25.3 164.5h.2v.6h-.2zM25.5 166.2v.3l.3 .1-.1-.3 .3-.1v.4M25.5 165.9h.6M25.7 165.7l.3 .2M26 164.5l.2 .2-.1 .4h-.2l-.1-.2zM26 166.8h.1M26.1 167.3h-.6l.2 .1M26.1 167.1v.3M26.1 165.7l-.2 .2M27.2 167.4l.2-.1 .2 .2-.5 .4h.5M27.8 167.6v.3h.3v-.3"/>
<path d="M28.2 165.5l-.4 .1v.4h.4M28.3 167.7h.3M28.7 167.3h-.4v.6M28.7 165.5h-.3v.2h.3v.4l-.3-.1M28.8 160.1h-.2a.28 .28 0 0 0-.2 .4 .28 .28 0 0 0 .4 .1M28.9 165.5h.4l-.2 .6M29.2 161.2l.2-.2v.6M29.2 161.6h.4M29.3 160.1h-.2l-.1 .2h.3v.4l-.3-.1M29.6 179.5l.3-.1v-.3h-.3v.6M29.6 160.1h.3v.2l-.3 .4h.3M29.8 179.5l.1 .2"/>
<path d="M29.8 161.2v.4h.3v-.4M30.2 179.3l.2-.2v.6M30.2 179.7h.3M30.4 161.3h.1M30.6 161h-.2v.6M30.8 179.3l.1-.2v.6M30.8 179.7h.3M31.4 179.3l.1-.2v.6M31.4 179.7h.3M35.9 163.9v.6h.3M35.9 169.1v.5l.1 .2 .2-.1v-.6M36.4 164.2h.2"/>
<path d="M36.7 163.9h-.3v.6M36.8 169.1h-.3l-.1 .4 .3-.1 .1 .3h-.4M36.9 163.9h.3l-.2 .2 .2 .1v.3h-.3M37 169.4l.2-.3v.7M37 169.8h.4M37.7 163.9h-.2v.3l.2-.1 .1 .3-.3 .1M38 163.9h.4l-.3 .6M41.4 170.3h.3l-.1-.3h-.2v.6M41.5 163.9h.2l.2-.3-.4-.1v.6M41.5 170.3l.2 .3M41.6 163.9l.3 .2M42 170.1l.1-.1v.6"/>
<path d="M42 170.6h.3M42.4 163.8l-.3 .1-.1-.3 .4-.1v.5l-.3 .1M42.6 170l.3 .2-.1 .4h-.3zM42.6 163.5h.5l-.4 .6M42.9 172l.6-.1v.3l-.4 .1-.2-.1zM42.9 171.4l.5-.1 .1 .3-.5 .1zM42.9 165.2h.6M42.9 164.9l.3 .3M43.4 170h-.3v.3l.3-.1 .1 .3-.4 .1M43.5 172.6h-.6l.2 .2M43.5 165.7h-.6l.2 .1M43.5 165.5v.3"/>
<path d="M43.5 172.4v.4M43.5 164.9l-.4 .2M49.9 164.4h.3v.6h-.3zM50.5 164.9v.1M50.7 179.1l.3-.1v.5l-.2 .1-.1-.1zM50.8 164.4h.2l.1 .1-.4 .5h.4M51.2 162.6l-.4 .1v.4h.4M51.3 179.5v.1M51.3 164.4h.3v.2l-.3 .4h.3M51.3 178a.28 .28 0 0 0-.4 .1 .28 .28 0 0 0 .1 .4l.3-.1M51.5 179h.4v.3l-.4 .3h.4M51.8 177.9h-.2l-.2 .3v.2l.4 .1v-.3l-.4 .1"/>
<path d="M51.8 162.6h-.4v.3h.4l-.1 .3-.3-.1M51.9 164.5v.4h.2M52.1 179h.4v.3l-.4 .3h.4M52.1 162.5l-.1 .4h.4M52.1 164.5v.5M52.2 177.9l-.2 .5h.4M52.3 162.8v.4M52.3 178.1v.4M52.5 164.6h.1M52.7 179.2v.3h.3M52.7 164.4h-.2v.6M53 179.2v.4"/>
<path d="M53.2 179.3h.3M53.6 179h-.4v.6M57.6 160.1v.6l.4-.1v-.5M58.5 160.2v.5M58.7 160.1h.4l-.2 .6M59.6 168h.3l.1-.1-.4-.2v.7M59.7 168l.3 .4M60.2 167.9l.1-.2v.7M60.2 168.4h.3M60.2 163.3l.4-.2-.1-.2h-.3v.6M60.3 163.3l.3 .2M60.9 167.7l.2 .2v.3l-.2 .2-.2-.2v-.3z"/>
<path d="M61.1 163.2l-.3 .1-.1-.3 .4-.1v.5l-.3 .1M61.3 167.9l.2-.2v.7M61.3 168.4h.4M61.5 169h.6M61.6 164.5h.6M61.7 162.9h-.4v.3h.4v.3l-.4-.1M61.7 168.7l.2 .3M61.8 164.3l.2 .2M62.1 169.4h-.6l.2 .1M62.1 169.2v.3M62.1 168.7l-.3 .2M62.2 165h-.6l.2 .1"/>
<path d="M62.2 164.8v.3M62.2 164.3l-.2 .2M63.4 160.6l.1-.2v.6M63.4 161h.3M63.7 167.5h.3l-.1 .6-.3-.2zM64 160.5h.3l-.1 .5-.2-.1zM64.2 168v.1M64.5 160.1h.3M64.6 167.5h.2l.1 .2-.4 .4h.4M64.6 160.4v.6M64.6 160.7l.2 .3M64.7 165.5l-.3 .1v.3l.2 .2 .1-.1"/>
<path d="M64.8 160.6l-.2 .2M65.1 167.5h.3v.3l-.3 .3h.3M65.3 165.5h-.3v.2h.3l-.1 .4-.2-.1M65.7 167.7v.3h.2M65.7 165.7l-.1-.2h.2l.1 .1-.3 .1 .1 .4 .2-.2-.2-.2M65.9 167.7v.4M66.3 167.8h.1M66.5 167.5h-.2v.6M72.4 161.2l.1 .6h.3v-.6M73.2 161.2l-.2 .5h.4M73.4 161.4v.4M74 161.5l-.3 .1-.1-.3 .4-.1v.5l-.3 .1"/>
<path d="M76.2 169.4v-.6l.2 .4 .2-.4v.6M77.3 168.9l-.2-.1-.3 .2 .2 .4h.3M77.5 169.1h.3l.1-.1-.4-.2v.6M78.1 161.1h-.3v.4l.3 .1M78.2 168.8l-.2 .4h.4M78.4 169v.4M78.6 169l.2-.2v.6M78.6 161h-.2v.3l.2-.1 .1 .3-.3 .1M78.6 169.4h.4M78.9 161h.3l-.2 .2h.2v.4h-.3M79.5 168.8l-.3 .2v.4h.3v-.4l-.3 .1M79.8 169l.2-.2v.6"/>
<path d="M79.8 160.3l.2-.2v.6M79.8 167.1v.6h.3v-.6M79.8 169.4h.3M79.8 160.7h.3M80.4 160.4l.1 .3h.1v-.3M80.7 167.1h-.3v.3l.3-.1v.4h-.3M81 167.1h.3l-.1 .2 .1 .1v.3h-.3M81 160.5h.2M81.2 160.1h-.2v.6M81.8 164.5h.2l.2-.3-.4-.1v.6M81.9 164.5l.3 .2M82.7 164.4l-.3 .1-.1-.3 .4-.1v.4l-.3 .2"/>
<path d="M83.1 166.2v.2l.3 .1-.1-.3h.3v.3M83.1 165.7l.4-.1 .2 .1-.2 .2h-.3zM83.1 165.3h.6M83.3 164.4l-.4 .1v-.3l.4-.1v.4l-.3 .2M83.3 165.1l.2 .2M83.7 166.8h-.6l.2 .2M83.7 166.7v.3M83.7 165.1l-.3 .1M127.5 164.5v.3h.2v-.3h.4l-.1 .3M127.5 164l.3-.1 .3 .1v.1l-.5 .1zM127.5 163.6h.6M127.6 163.4l.3 .2"/>
<path d="M127.9 166h.3l.1-.2-.4-.1v.5M128.1 165.2h-.6l.1 .2M128.1 165.1v.3M128.1 163.4l-.3 .2M128.1 166l.2 .2M128.8 165.9l-.1 .2-.2-.3 .2-.1h.1v.5h-.2M129.2 165.7l-.1 .4h.3M129.3 165.9v.3M129.9 169.8l.3-.2v.6M129.9 162.7v.6l.4-.1v-.5M129.9 170.2h.4M130.6 169.9v.3h.3v-.3"/>
<path d="M130.6 162.7l-.1 .4h.4M130.8 162.9v.4M131.1 161.6v-.6l.2 .4 .2-.4v.6M131.1 170h.2M131.4 169.6h-.3v.6M131.4 162.7l-.3 .2v.4l.3-.1v-.3l-.3 .1M132.1 161.1h-.3v.4l.3 .1M132.3 168.9l-.2-.1-.1 .2v.3l.3 .1M132.4 161.3h.2l.1-.2-.3-.1v.6M132.8 168.8l-.3 .2v.4h.4l-.1-.4-.3 .1M133.1 161l-.1 .4h.3M133.1 168.9h.3v.5h-.3z"/>
<path d="M133.2 161.2v.4M133.6 161.2l.1-.2v.6M133.6 161.6h.3M134.4 161h-.2l-.1 .2v.3l.3 .1v-.4l-.3 .1M134.7 161.2l.1-.2v.6M134.7 161.6h.3M135.8 171.1v.6h.3M136.3 171.4h.2M136.6 171.1h-.3v.6M136.8 171.1h.3l-.2 .2 .2 .1v.3h-.3M137.2 168.5l.1 .6h.2v-.6M137.6 171.1h-.2v.3l.2-.1 .1 .3-.3 .1"/>
<path d="M137.9 171.1h.4l-.3 .6M138.1 168.5h-.2l-.1 .4 .3-.1 .1 .2-.4 .1M138.6 168.5l.1 .1v.5h-.2l-.1-.1zM144.7 162.3a.3 .3 0 0 1 .4 .3 .3 .3 0 0 1-.3 .3zM145.3 162.9h.1M145.6 162.3h.2l.1 .2-.4 .4h.4M145.7 164.4l-.4 .1v.4h.4M146.1 162.3h.3v.3l-.3 .3h.3M146.1 170.6h.3v-.2h-.3v.6M146.2 164.4h-.3v.2h.3l.1 .3h-.4M146.3 170.6l.1 .4M146.4 169.5l.2-.1v.6"/>
<path d="M146.4 170h.4M146.7 170.6l.2-.2v.6M146.7 171h.3M146.8 162.5v.4h.2M146.8 164.4h-.3l-.1 .2h.4v.4l-.4-.1M147 162.5v.4M147.1 169.4l.2 .1v.5h-.3l-.1-.2zM147.3 170.4h.2l-.1 .6-.2-.3zM147.3 162.6h.1M147.5 162.3h-.2v.6M147.5 169.4v.6M147.6 169.8l.2 .2"/>
<path d="M147.8 170.4h.3v.2l-.3 .4h.3M147.8 169.6l-.3 .2M148.9 165.6h.7M149.1 161.2h.5M149.1 165.3l.3 .3M149.2 160.9l.3 .3M149.5 167.2h.3l.1-.2-.4-.1v.6M149.6 166h-.7l.2 .2M149.6 165.8v.4M149.6 165.3l-.3 .2M149.6 161.6h-.5l.1 .2M149.6 161.4v.4"/>
<path d="M149.6 160.9l-.2 .2M149.6 167.2l.3 .3M150.2 170.8v.6h.3M150.2 162.4h.1l.2-.2-.3-.1v.6M150.2 162.4l.3 .3M150.4 167.2l-.2 .1-.1-.3 .3-.1v.4l-.2 .2M150.7 171.2h.2M150.7 167.2v-.3h.3l-.1 .3h-.2v.3l.3-.1-.1-.2M151 170.8h-.3v.6M151 162.3l-.3 .1v-.2l.3-.1v.4l-.3 .2M151.2 170.8h.3l-.2 .3 .2 .1v.2h-.3M151.3 162.2h.3l-.3 .5h.3"/>
<path d="M152 170.8h-.2v.4l.2-.1 .1 .2-.3 .1M152.1 169.8l.1 .6 .2-.1v-.5M152.3 170.8h.4l-.3 .6M153 169.8h-.3v.3l.3-.1v.3h-.3M153.3 169.8h.3v.3l-.3 .3h.3M157.7 173l.3 .1-.1 .5-.2-.1zM158.3 173.5v.1M158.5 173h.4v.3l-.4 .3h.4M158.5 165.5a.3 .3 0 0 1 .4 .2 .3 .3 0 0 1-.3 .4l-.1-.3zM159.1 173h.3l.1 .2-.5 .4h.5M159.1 166v.1M159.2 174.1h-.2l-.2 .3 .1 .2h.3"/>
<path d="M159.2 167.3h-.3v.5h.3M159.4 165.5h.2l.1 .2-.4 .4h.4M159.7 173.2v.4l.3-.1M159.7 174.1h-.2l-.1 .3 .2 .3 .1-.1-.1-.3-.2 .2M159.7 167.3h-.2v.2h.2l.1 .3h-.3M159.9 165.5h.3v.2l-.3 .4h.3M160 174.1h.3l-.2 .2 .2 .1v.2h-.3M160 173.2v.4M160.2 173.3h.3M160.3 172.1h.4v-.3h-.4v.6M160.4 167.5l-.3 .1-.1-.3h.4l-.1 .5-.2 .1M160.5 165.7v.3h.2"/>
<path d="M160.5 172.1l.2 .3M160.6 173h-.4v.6M160.7 165.7v.4M160.8 170.8l.2-.2v.6M160.8 171.2h.4M160.9 172l.2-.2v.6M160.9 172.4h.3M161.1 165.7h.1M161.3 165.5h-.2v.6M161.5 170.6h.2l-.1 .6a.37 .37 0 0 1-.3-.3 .37 .37 0 0 1 .2-.3zM161.5 171.9h.3v.4l-.1 .1-.2-.1zM161.9 170.6v.6"/>
<path d="M162 171.8h.4l-.2 .2 .2 .3-.1 .1-.3-.1M162 171l.2 .2M162.2 170.8l-.3 .3M165.1 172h.2l.1-.2-.3-.1v.6M165.1 172l.3 .3M165.5 170.8l.2-.2v.6M165.5 171.2h.3M165.6 171.8l.1-.1v.6M165.6 172.3h.3M166.2 170.6a.35 .35 0 0 1 .2 .3 .35 .35 0 0 1-.2 .3zM166.3 171.7h.2v.6h-.3v-.2zM166.7 170.6v.6"/>
<path d="M166.7 171l.1 .2M166.8 170.8l-.1 .3M166.9 171.7l-.1 .4h.3M167 171.9v.4M167.6 180h.7a.35 .35 0 0 1-.4 .2 .35 .35 0 0 1-.3-.2zM167.6 165h.7M167.6 164.6l.4 .4M168.2 166.6h.3l.1-.2-.4-.2v.7M168.3 165.4h-.7l.3 .2M168.3 165.2v.4M168.3 164.6l-.4 .3M168.4 160.1h.3l-.1-.3h-.2v.6"/>
<path d="M168.4 166.6l.2 .3M168.5 160.1l.2 .3M169 160.1v-.3h.2l.1 .2-.3 .1v.3l.3-.1-.2-.2M169.1 166.6h-.3l.2-.4 .1 .1v.5l-.2 .1M169.6 166.2l-.2 .2v.4h.3l-.1-.3-.2 .2M169.6 160.1l-.1-.2 .3-.1v.3h-.3v.3h.3l-.1-.3M172.8 165.9v.6h.4M173.2 170.8l.1 .6h.2v-.6M173.4 166.2h.1M173.6 165.9h-.2v.6M173.8 165.9h.4l-.3 .3h.2l.1 .2-.4 .1M173.8 160.7l.1 .5h.3v-.5"/>
<path d="M174.1 170.8h-.2l-.1 .4 .3-.1 .1 .2-.4 .1M174.5 170.8l-.1 .4h.4M174.5 160.7v.4h.3M174.7 165.9h-.2l-.1 .3h.3l.1 .2-.4 .1M174.7 160.8v.4M174.7 171.1v.3M175 165.9h.4l-.3 .6M175.1 160.9l-.1-.2h.3v.2l-.3 .1v.2h.3l-.1-.3M179.5 173.2h.3l.1-.3-.4-.1v.6M179.7 173.2l.2 .2M180.1 171.7h.4l-.2 .2h.2v.4h-.4M180.1 173l.2-.2v.6"/>
<path d="M180.1 173.4h.4M180.6 169l.1-.2v.6M180.6 169.4h.3M180.7 171.7v.6M180.8 172.8l.3 .3-.1 .3h-.3zM180.8 172.1l.2 .2M181 171.9l-.3 .2M181.1 169l.1 .4h.2v-.4M181.6 172.8h-.2l-.2 .3v.3h.4v-.3l-.4 .1M181.7 169.8l-.5 .1v.3l.3 .2 .2-.1M181.7 169.1h.2M182 168.8h-.3v.6"/>
<path d="M182.2 169.8h-.3l-.1 .3v.1l.3 .2v-.4l-.3 .1M182.2 164.4l-.3 .1v.4h.3M182.4 170l.2-.2v.6M182.4 170.4h.4M182.6 162.5h.3l-.3 .5h.3M182.8 164.4h-.3v.2h.3v.3h-.3M183.2 162.7l.1 .3h.1v-.3M183.3 164.4h-.2l-.1 .2 .1 .4h.2v-.4l-.3 .1M183.8 162.8h.1M184 162.4h-.2v.6M185 163.5v.4h.3v-.4h.2v.4M185 163.3h.6"/>
<path d="M185.2 163l.3 .3M185.5 164.1h.1M185.6 164.5h-.6l.2 .2M185.6 165.7l.4-.1-.1-.3h-.3v.6M185.6 164.4v.3M185.6 163l-.2 .2M185.8 165.7l.2 .2M186.4 173.4h.2l.1-.4h-.3v.6M186.6 165.6l-.3 .1-.1-.4 .4 .1-.1 .5h-.3M186.6 173.4l.1 .2M186.7 171.7h.4l-.2 .2 .2 .1v.3h-.4M186.7 165.3h.4l-.2 .3h.2v.3h-.4"/>
<path d="M187 173.2l.2-.2v.6M187 173.6h.3M187.3 171.7v.6M187.4 172.1l.2 .2M187.6 173h.2l-.1 .6h-.1l-.1-.2zM187.6 171.9l-.3 .2M187.9 169l.2-.2v.6M187.9 169.4h.4M188.1 173h.3l-.2 .6M188.5 169v.4h.3v-.4M188.7 170h-.4v.4h.4M189 169.1h.3"/>
<path d="M189.2 169.9l-.3 .2v.4l.4-.1v-.3l-.4 .1M189.4 168.8h-.4v.6M189.5 170l.3-.1 .1 .2-.5 .4h.5M192.3 167v.6M192.9 167v.6l-.3-.6v.6M193 171.8l.1 .6 .2-.1v-.5M193.2 167.6l.1-.6 .3 .6M193.3 167.4h.2M193.8 167.3v-.3h.2l.1 .2-.3 .1v.3l.3-.1-.2-.2M193.9 171.8h-.2l-.1 .3 .2-.1 .1 .3h-.3M194.3 167.1l.3-.1v.3l-.3 .3h.3M194.5 171.8h-.3v.3h.3l-.1 .3-.2-.1"/>
<path d="M194.9 167h.3l-.2 .3h.2v.2h-.3M198.2 172.3h.6v.1l-.1 .2h-.4zM198.2 171.7h.5l.1 .1-.1 .2h-.4zM198.2 171.2l.4-.1 .2 .2-.6 .1zM198.8 172h.2l.1-.2-.3-.1v.6M198.8 173h-.6l.2 .2M198.8 172.8v.4M198.8 172l.3 .3M199.3 171.8l.1-.1v.6M199.3 172.3h.3M200 171.7h.2v.6l-.3-.1v-.4zM200.5 171.9l-.1-.2h.3l.1 .2-.4 .1v.3h.4l-.1-.4"/>
<path d="M10.5 180.6h.3l-.2-.3h-.1v.6M10.5 180.6l.3 .3M11 180.5l.1-.2v.6M11 180.9h.4M11.7 180.3l.2 .1v.5h-.3v-.2zM12.3 180.7l.5-.1 .1 .3-.5 .1zM12.3 180.1l.4-.1 .2 .1v.2l-.5 .1zM12.5 180.6l-.3 .1-.1-.3h.4v.4l-.3 .1M12.9 181.4h-.6l.2 .2M12.9 181.2v.4M16 185v.6M16.6 185v.6l-.3-.6v.6"/>
<path d="M16.7 180.2v.6l.4-.1v-.5M16.8 185.6l.3-.6 .1 .6M16.9 185.5h.2M17.5 185.3v-.3h.2v.3h-.3l.1 .3 .2-.1v-.2M17.6 180.2h-.3v.3h.3l.1 .2h-.4M18 185h.2l.1 .3-.4 .3h.4M18.2 180.2h-.3l-.1 .3 .1 .3h.3v-.3l-.4 .1M18.5 185h.4l-.2 .2 .2 .3-.1 .1-.3-.1M21.7 182.2h-.3v.5h.3M21.9 183.3l.2-.1v.6M21.9 183.8h.3M22.2 182.1l-.2 .1v.5h.3l-.1-.4-.2 .2"/>
<path d="M22.5 183.4v.4h.2v-.4M22.8 182.1h-.2v.3l.1-.1 .2 .3-.2 .2-.1-.1M23.1 183.5h.1M23.3 183.2h-.2v.6M23.6 180.3h.3l-.2 .3h.2v.3h-.3M24.1 187h.3l-.1-.4h-.2v.6M24.3 180.3v.6M24.3 187l.1 .2M24.4 180.6l-.1 .1 .1 .2M24.7 186.8l.1-.2v.6M24.7 187.2h.3M25.3 186.7l.1-.1 .2 .2-.4 .4h.4"/>
<path d="M25.5 188.4v.3l.3 .1-.1-.3 .3-.1v.4M25.5 188.2h.6M25.7 187.9l.3 .3M26 186.6l-.2 .5h.4M26 189h.1M26.1 189.4h-.6l.2 .2M26.1 186.9v.3M26.1 189.3v.3M26.1 187.9l-.2 .2M27.2 189.6l.2-.1 .2 .2-.5 .4h.5M27.8 189.8v.3h.3v-.3M28.2 187.7h-.4v.5h.4"/>
<path d="M28.3 189.9h.3M28.4 187.7h.3l-.2 .6M28.7 189.5h-.4v.6M28.8 182.3a.28 .28 0 0 0-.3 .2 .28 .28 0 0 0 .1 .3h.2M29 187.8l.2-.1v.6M29 188.3h.3M29.2 183.3l.2-.1v.6M29.2 183.8h.4M29.3 182.2h-.1l-.2 .3v.3h.3v-.3l-.3 .1M29.8 183.4v.4h.3v-.4M29.9 182.2h-.2l-.1 .2v.4h.3v-.3l-.3 .1M30.2 180.3h.3l-.1 .3h.1v.3h-.3"/>
<path d="M30.4 183.5h.1M30.6 183.2h-.2v.6M30.8 180.3v.6M30.9 180.7l.1 .2M31 180.6l-.2 .1M35.9 186.1v.5h.3M35.9 191.4v.4l.1 .2 .2-.1v-.5M36.4 186.4h.2M36.4 181.1l.1 .6h.3v-.6M36.7 186.1h-.3v.5M36.8 191.4h-.3l-.1 .2 .2 .4 .2-.1-.1-.3-.3 .1M36.9 186.1h.3l-.2 .2 .2 .1v.2h-.3"/>
<path d="M37 191.4h.4l-.2 .2h.2v.3h-.4M37.4 181.1h-.3l-.1 .4 .4-.1 .1 .3h-.5M37.6 181.1h.5l-.3 .6M37.7 186.1h-.2v.3l.2-.1 .1 .3h-.3M38 186.1h.4l-.3 .5M41.4 192.5h.3l-.1-.3h-.2v.6M41.5 186.1h.2l.2-.3-.4-.1v.6M41.5 192.5l.2 .3M41.6 186.1l.3 .2M42 192.4l.1-.2v.6M42 192.8h.3M42 185.9l.2-.2v.6"/>
<path d="M42 186.3h.4M42.5 192.2h.2l.2 .2-.4 .4h.4M42.6 185.8l.4-.1v.3l-.4 .3h.4M42.9 193.6l.5-.1 .1 .3h-.5zM42.9 187.4h.6M42.9 187.1l.3 .3M43 194.1h.5v.3h-.6zM43.2 185.9l.2-.2v.6M43.2 186.3h.4M43.5 194.9h-.6l.2 .1M43.5 187.8h-.6l.2 .2M43.5 192.5h-.4l.1-.3 .3 .1v.3l-.4 .2"/>
<path d="M43.5 187.7v.3M43.5 194.6v.4M43.5 187.1l-.4 .2M44.2 180.6h.3l-.2-.3h-.1v.6M44.2 180.6l.3 .3M44.3 181.6l.2-.2v.6M44.3 182h.4M44.7 180.5l.1-.2v.6M44.7 180.9h.3M45 181.4h.2l.1 .3-.1 .3-.3-.1zM45.3 180.5l.1-.2v.6M45.3 180.9h.3"/>
<path d="M45.5 181.4v.6M45.5 181.7l.3 .3M45.8 181.6l-.3 .2M45.8 180.3h.4l-.2 .3h.2v.3h-.4M48.8 180.6l.3-.1v-.3h-.3v.6M49 181.6l.1-.2v.6M49 182h.3M49 180.6l.1 .2M49.4 180.4l.2-.2v.6M49.4 180.8h.3M49.6 181.5h.3l-.1 .5-.2-.1zM49.9 186.6h.3v.6h-.3z"/>
<path d="M49.9 180.4l.2-.2v.6M49.9 180.8h.3M50.2 181.4v.6M50.2 181.7l.2 .3M50.4 181.6l-.2 .2M50.5 187.1v.1M50.7 180.1l-.2 .5h.4M50.8 186.6h.2l.1 .1-.4 .5h.4M50.8 180.4v.4M51.2 184.8l-.4 .1v.4h.4M51.3 186.6h.3v.2l-.3 .4h.3M51.7 184.8l-.3 .1v.4h.4l-.1-.3-.3 .1"/>
<path d="M51.9 186.7v.4h.2M52.1 185l-.1-.2 .4 .1-.4 .1 .1 .4 .3-.2-.2-.2M52.1 186.7v.5M52.5 186.8h.1M52.7 186.6h-.2v.6M57.6 182.2v.6h.4v-.6M58.5 181.1v.6h.4M58.5 182.2h-.3v.3h.3v.3h-.3M59.1 181.5h.1M59.1 182.5l-.3 .1v-.4l.3 .1v.5h-.3M59.3 181.1h-.2v.6M59.5 181.1h.4l-.3 .3h.2l.1 .3h-.4"/>
<path d="M59.6 190.2h.3l.1-.2-.4-.1v.6M59.7 190.2l.3 .3M60.2 190.1l.1-.2v.6M60.2 190.5h.3M60.2 185.5h.2l.2-.3-.4-.1v.6M60.3 185.5l.3 .2M60.4 181.1h-.2l-.1 .4 .3-.1v.3h-.3M60.7 181.1h.4l-.4 .6M60.7 185.3l.2-.2v.6M60.7 189.9h.4v.3l-.4 .3h.4M60.7 185.7h.4M61.3 185.3l.2-.2v.6"/>
<path d="M61.3 185.7h.4M61.5 191.1h.6M61.6 186.7h.6M61.7 189.9h-.4v.3h.4v.3h-.4M61.7 190.9l.2 .2M61.8 186.5l.2 .2M62.1 191.6h-.6l.2 .1M62.1 191.4v.3M62.1 190.9l-.3 .2M62.2 187.2h-.6l.2 .1M62.2 187v.3M62.2 186.5l-.2 .1"/>
<path d="M62.3 185.4l-.4 .1v-.3h.4v.3l-.3 .2M63.1 182l.4-.2-.1-.1h-.3v.5M63.2 182l.3 .2M63.4 182.8l.1-.2v.6M63.4 183.2h.3M63.6 181.8l.2-.1v.5M63.6 182.2h.4M63.7 189.7h.3l-.1 .6-.3-.3zM64 182.7h.3l-.1 .5-.2-.1zM64.2 190.2v.1M64.2 181.8l.2-.1v.5M64.2 182.2h.4"/>
<path d="M64.6 189.7h.2l.1 .2-.4 .4h.4M64.6 182.6v.6M64.6 183l.2 .2M64.7 187.7h-.3v.4l.2 .2 .1-.1M64.8 182.8l-.2 .2M65 187.7h.3l-.2 .6M65.1 189.7h.3v.2l-.3 .4h.3M65.1 181.7h-.3v.2h.3l.1 .3h-.4M65.6 187.7h.2l.1 .1-.4 .5h.4M65.7 189.9v.3h.2M65.9 189.9v.4M66.3 189.9h.1"/>
<path d="M66.5 189.7h-.2v.6M73 183.4l.1 .6 .3-.1v-.5M73.5 180.9v.6h.4M74 183.4l-.3 .2v.4l.3-.1v-.2l-.3 .1M74 181.2h.2M74.2 183.6l.2-.2v.6M74.2 184h.3M74.3 180.9h-.3v.6M74.5 180.9h.4l-.3 .2 .3 .1v.2l-.4 .1M75.4 180.9h-.3v.3l.3-.1 .1 .3-.4 .1M75.6 180.9h.5l-.3 .6M76.8 191.6v-.6l.2 .4 .2-.4v.6"/>
<path d="M77.9 191.1l-.2-.1-.3 .2 .2 .4h.3M78.1 191.3h.3v-.2l-.3-.1v.6M78.7 183.3h-.3v.4l.3 .1M78.8 191l-.1 .4h.3M79 191.2v.4M79.2 191.1l.2-.1v.6M79.2 183.2l-.2 .1v.5l.3-.1-.1-.3-.2 .1M79.2 191.6h.3M79.5 183.2h.4l-.3 .6M80.1 191l-.3 .1v.5h.3v-.4l-.3 .1M80.4 191.1l.2-.1v.6M80.4 182.5l.2-.2v.6"/>
<path d="M80.4 189.3v.6h.2h.1v-.6M80.4 191.6h.3M80.4 182.9h.3M81 182.6l.1 .3h.2v-.3M81.3 189.3a.35 .35 0 0 0-.3 .3 .35 .35 0 0 0 .2 .3l.1-.3-.1-.1-.2 .2M81.6 182.7h.1M81.8 182.3h-.2v.6M81.9 189.3h-.3v.3h.3l-.1 .3h-.2M82.4 186.6l.4-.1-.1-.2h-.3v.6M82.5 186.6l.3 .3M82.9 186.5l.2-.2v.6M82.9 186.9h.5"/>
<path d="M83.5 186.4l.4-.1v.3l-.4 .3h.4M83.8 188.3v.3l.3 .1-.1-.4h.4v.4M83.8 187.9l.1-.2h.4l.1 .3-.5 .1zM83.8 187.5h.6M84 187.2l.2 .3M84.1 186.3h.4l-.2 .3h.2v.2h-.4M84.4 189.1h-.6l.1 .2M84.4 188.8v.5M84.4 187.2l-.2 .2M128 188.2h.3v-.3l-.3-.1v.7M128.1 186.7v.3h.2v-.3l.3-.1v.4M128.1 186.1h.3h.3v.2l-.4 .2-.2-.2z"/>
<path d="M128.1 185.8h.6M128.1 188.2l.2 .3M128.2 185.6l.3 .2M128.6 188.1l.1-.3v.7M128.6 188.5h.3M128.7 187.4h-.6l.1 .2M128.7 187.2v.4M128.7 185.6l-.3 .2M129.1 188.1l.1-.3v.7M129.1 188.5h.3M129.8 188.2v-.4l.2 .1-.1 .3h-.2l.1 .3 .2-.1-.1-.2M130.5 184.3v.6l.4-.1v-.5"/>
<path d="M130.6 192l.2-.2v.6M130.6 192.4h.3M131.2 192.1v.3h.2v-.3M131.4 184.3h-.3v.2h.3v.4l-.3-.1M131.7 183.2v-.6l.2 .4 .2-.4v.6M131.7 192.2h.2M131.8 184.5l-.1-.2 .3 .1v.1h-.3v.4l.3-.1-.1-.3M132 191.8h-.3v.6M132.7 182.7h-.3v.4l.3 .1M132.9 191.1l-.2-.1-.2 .1v.4l.4 .1M133 182.9h.3v-.3h-.3v.6M133.1 191h.4l-.3 .6"/>
<path d="M133.7 182.6l-.1 .4h.3M133.8 191l-.1 .4h.4M133.8 182.8v.4M134 191.2v.4M134.2 182.8l.1-.2v.6M134.2 183.2h.3M135 182.6h-.2l-.1 .2v.3l.3 .1v-.4l-.3 .1M135.3 182.8l.1-.2v.6M135.3 183.2h.3M136.4 193.3v.5h.3M136.9 193.6h.2M137.2 193.3h-.3v.5"/>
<path d="M137.4 193.3h.3l-.2 .2 .2 .1v.2h-.3M137.8 190.7v.5l.2 .2 .2-.2v-.5M138.3 193.3h-.3v.3h.3v.2h-.3M138.5 193.3h.4l-.3 .5M138.7 190.7l-.2 .2v.4l.1 .1 .2-.2-.2-.2-.1 .1M139 190.8h.3v.3l-.3 .3h.3M144.7 184.5h.3v.6l-.3-.1zM145.3 185v.1M145.6 184.5h.2l.1 .2-.4 .4h.4M145.7 186.6h-.4v.5h.4M146.1 184.5h.3v.3l-.3 .3h.3M146.1 192.8h.3v-.2h-.3v.6"/>
<path d="M146.2 186.6l-.3 .1v.5l.4-.1-.1-.3-.3 .1M146.3 192.8l.1 .4M146.4 191.7l.2-.1v.6M146.4 192.2h.4M146.7 192.7l.2-.1v.6M146.7 193.2h.3M146.8 184.7v.4l.2-.1M146.8 186.8l-.3 .1-.1-.3h.4v.4l-.3 .2M147 184.7v.4M147.1 191.6h.2v.6h-.3l-.1-.2zM147.2 192.6h.3v.2l-.3 .4h.3M147.3 184.8h.1"/>
<path d="M147.5 184.5h-.2v.6M147.5 191.6v.6M147.6 192l.2 .2M147.8 191.8l-.3 .2M148 192.6l-.2 .1v.4h.3l-.1-.4-.2 .2M148.9 187.7h.7M149 189.4h.2l.1-.2-.3-.1v.6M149.1 183.3h.5M149.1 189.4l.2 .3M149.1 187.5l.3 .2M149.2 183.1l.3 .2M149.5 189.3l.2-.2v.6"/>
<path d="M149.5 189.7h.4M149.6 188.2h-.7l.2 .1M149.6 184.6h.2l.1-.2-.3-.1v.6M149.6 188v.3M149.6 187.5l-.3 .2M149.6 183.8h-.5l.1 .1M149.6 183.6v.3M149.6 183.1l-.2 .2M149.7 184.6l.2 .3M150.1 189.1h.3v.3l-.3 .3h.3M150.2 193v.6h.3M150.2 184.4l.1-.1v.6"/>
<path d="M150.2 184.9h.3M150.7 184.4l.1-.1v.6M150.7 189.1h.3v.3l-.3 .3h.3M150.7 193.3h.2M150.7 184.9h.3M151 193h-.3v.6M151.2 193h.3l-.2 .3h.2v.3h-.3M151.5 184.3h-.2v.5h.3v-.3l-.3 .1M152 193h-.2v.3h.2l.1 .2-.3 .1M152.1 192l.1 .6 .2-.1v-.5M152.3 193h.4l-.3 .6M153 192l-.3 .1v.4h.3v-.3l-.3 .1"/>
<path d="M153.5 191.9l-.2 .4h.3M153.5 192.2v.4M157.8 195.2l.2 .1-.1 .5-.2-.1zM158.3 195.7v.1M158.5 187.7a.3 .3 0 0 1 .4 .2 .3 .3 0 0 1-.3 .4l-.1-.3zM158.5 195.3h.4l-.4 .5h.4M159.1 188.2v.1M159.1 195.3l.3-.1 .1 .2-.5 .4h.5M159.2 189.5h-.3v.4h.3M159.2 196.3h-.2l-.2 .3 .1 .2h.3M159.4 187.7h.2l.1 .1-.4 .5h.4M159.4 189.4h.4l-.2 .6"/>
<path d="M159.4 196.3h.4l-.2 .6M159.7 195.4v.4l.3-.1M159.9 187.7h.3v.2l-.3 .4h.3M160 189.4h.4l-.3 .3h.2l.1 .2h-.4M160 196.3h.3l-.2 .6M160 195.4v.4M160.2 195.5h.3M160.3 194.3h.4v-.3h-.4v.6M160.5 187.8v.4h.2M160.5 194.3l.2 .3M160.6 195.2h-.4v.6M160.7 187.8v.5"/>
<path d="M160.8 193l.2-.2v.6M160.8 193.4h.4M160.9 194.2l.2-.2v.6M160.9 194.6h.3M161.1 187.9h.1M161.3 187.7h-.2v.6M161.4 192.8h.3l-.1 .6-.3-.2zM161.5 194h.3v.3l-.3 .3h.3M161.9 192.8v.6M162 194h.4l-.2 .6M162 193.2l.2 .2M162.2 193l-.3 .3"/>
<path d="M165.1 194.2h.2l.1-.2-.3-.2v.6M165.1 194.2l.3 .2M165.5 193l.2-.2v.6M165.5 193.4h.3M165.6 194l.1-.2v.6M165.6 194.4h.3M166.1 192.8a.3 .3 0 0 1 .3 .3 .3 .3 0 0 1-.2 .3zM166.2 193.9h.3l-.3 .5h.3M166.7 192.8v.6M166.7 193.2l.1 .2M166.8 194.1v-.2l.2-.1 .1 .3-.3 .1v.2h.3l-.1-.3M166.8 193l-.1 .3"/>
<path d="M167.6 180.6a.31 .31 0 0 1 .4-.2 .31 .31 0 0 1 .2 .3l-.3 .1zM167.6 187.2h.7M167.6 186.8l.4 .4M167.7 188.8h.2l.1-.2-.3-.1v.6M167.8 182.3l.3-.1v-.2h-.3v.6M167.8 188.8l.2 .3M167.9 182.3l.2 .3M168.2 188.7l.2-.2v.6M168.2 189.1h.4M168.3 181.1h-.7l.3 .2M168.3 187.6h-.7l.3 .1M168.3 181v.3"/>
<path d="M168.3 187.4v.3M168.3 186.8l-.4 .3M168.4 182.2l.1-.2v.6M168.4 182.6h.3M168.8 188.5h.3v.3l-.3 .3h.3M169 182.2l.1-.2v.6M169 182.6h.3M169.5 182.1l.3-.1v.2l-.3 .4h.3M169.5 188.5l.2 .1v.3l-.2 .2-.1-.2zM172.8 188.1v.6h.4M173.2 193l.1 .6h.2v-.6M173.4 188.4h.1"/>
<path d="M173.6 188.1h-.2v.6M173.8 188.1h.4l-.3 .2h.2l.1 .3-.4 .1M173.8 182.8l.1 .6 .3-.1v-.5M174.1 193l-.3 .3v.2l.3 .1v-.3h-.3M174.7 188.1h-.2l-.1 .3 .3-.1 .1 .3-.4 .1M174.7 193h-.2l-.1 .3v.2l.3 .1v-.3h-.3M174.7 182.8l-.2 .2v.4l.3-.1-.1-.2-.2 .1M175 188.1h.4l-.3 .6M175 182.8l.3 .1-.1 .5h-.2v-.2zM179.5 195.4h.4v-.3l-.4-.1v.7M179.7 195.4l.2 .3M180.1 193.8h.4l-.2 .3h.2v.3h-.4"/>
<path d="M180.1 195.3l.2-.3v.7M180.1 195.7h.4M180.6 191.1l.1-.1v.6M180.6 191.6h.3M180.6 195h.5l-.3 .3 .3 .2-.2 .2-.3-.1M180.7 193.8v.6M180.8 194.3l.2 .1M181 194.1l-.3 .2M181.1 191.2l.1 .4h.2v-.4M181.4 195l.2 .1-.1 .6a.37 .37 0 0 1-.3-.3 .37 .37 0 0 1 .2-.4zM181.7 192l-.5 .1v.3l.3 .2 .2-.1M181.7 191.3h.2"/>
<path d="M181.8 192h.4l-.2 .6M182 191h-.3v.6M182.2 186.6h-.3v.5h.3M182.4 186.6h.4l-.2 .6M182.6 184.7h.3l-.3 .5h.3M182.8 192h-.4v.2h.4l-.1 .4-.3-.1M183.1 186.6h.2v.6h-.2zM183.2 184.9l.1 .3h.1v-.3M183.8 185h.1M184 184.6h-.2v.6M185 185.8v.3h.3v-.3l.2-.1v.4M185 187.8h.4v-.2l-.4-.1v.6"/>
<path d="M185 185.5h.6M185.2 185.2l.3 .3M185.2 187.8l.2 .3M185.5 186.3h.1M185.6 186.7h-.6l.2 .2M185.6 187.7l.2-.2v.6M185.6 186.6v.3M185.6 185.2l-.2 .2M185.6 188.1h.4M186.2 187.7l.2-.2v.6M186.2 188.1h.4M186.4 195.5h.2l.1-.2-.3-.1v.6"/>
<path d="M186.6 195.5l.1 .3M186.7 193.8h.4l-.2 .3 .2 .1v.2h-.4M186.7 187.5h.5l-.3 .6M187 195.4l.2-.2v.6M187 195.8h.3M187.3 193.8v.6M187.4 194.3l.2 .1M187.5 195.2h.3l-.1 .3h.1v.3l-.3-.1M187.6 194.1l-.3 .2M187.9 191.1l.2-.1v.6M187.9 191.6h.4M188.1 195.4l.2-.2v.6"/>
<path d="M188.1 195.8h.3M188.5 191.2v.4h.3v-.4M188.7 192.2h-.4v.4h.4M188.8 192.1h.5l-.3 .6M189 191.3h.3M189.4 191h-.4v.6M189.8 192.1l-.3 .1v.5l.4-.1-.1-.3-.3 .1M192.3 189.2v.6M192.9 189.2v.6l-.3-.6v.6M193 194l.1 .6 .2-.1v-.5M193.2 189.8l.1-.6 .3 .6M193.3 189.6h.2"/>
<path d="M193.8 189.4v-.2h.2l.1 .2h-.3v.4l.3-.1-.2-.3M193.9 194h-.2l-.1 .3v.1l.2 .2 .1-.3-.1-.1-.2 .2M194.2 194h.3l-.2 .6M194.3 189.3l.3-.1v.2l-.3 .4h.3M194.9 189.2h.3l-.2 .2h.2v.3h-.3M198.2 194.5l.5-.1 .1 .2-.1 .2h-.4zM198.2 193.9l.5-.1 .1 .2v.2h-.6zM198.2 193.3h.4l.2 .2-.6 .1zM198.8 194.2h.2l.1-.2-.3-.2v.6M198.8 195.2h-.6l.2 .2M198.8 195v.4M198.8 194.2l.3 .2"/>
<path d="M199.3 194l.1-.2v.6M199.3 194.4h.3M199.9 193.8h.3l-.2 .3h.2v.3h-.3M200.4 193.9h.4l-.4 .5h.4M10.5 202.8h.2l.1-.2-.3-.1v.6M10.5 202.8l.3 .3M11 202.6l.1-.1v.6M11 203.1h.4M11.9 202.7l-.2 .2-.1-.3 .1-.1 .2 .1v.4l-.3 .1M12.1 202.5h.4l-.2 .2 .2 .1v.3h-.4M12.3 202.3l.4-.1 .2 .1v.2l-.5 .1zM12.4 202.8h.4l.1 .3-.5 .1z"/>
<path d="M12.4 201.7h.4l.1 .3h-.6zM12.9 203.6h-.6l.2 .2M12.9 203.4v.4M16 207.2v.6M16.6 207.2v.6l-.3-.6v.6M16.7 202.4v.6l.4-.1v-.5M16.8 207.8l.3-.6 .1 .6M16.9 207.6h.2M17.5 207.5l-.1-.3h.3v.3h-.3l.1 .3 .2-.1v-.2M17.7 202.6l-.4 .1v-.3l.4 .1-.1 .4-.3 .1M18 207.2h.3v.3l-.4 .3h.4M18.2 202.6l-.3 .1-.1-.2h.4v.4l-.3 .1"/>
<path d="M18.5 207.2h.4l-.2 .2 .2 .2-.1 .2-.3-.1M21.5 204.3h-.3l-.2 .3 .1 .3h.4M21.6 204.5l.2-.2v.6M21.6 204.9h.4M21.9 205.5l.2-.1v.6M21.9 206h.3M22.2 204.5l.2-.2v.6M22.2 204.9h.4M22.5 205.6v.4h.2v-.4M22.8 201.5h.3l.1-.2-.4-.1v.6M22.9 201.5l.3 .3M23 204.3l-.2 .4h.4"/>
<path d="M23.1 205.7h.1M23.1 204.5v.4M23.3 205.4h-.2v.6M23.3 201.4l.2-.2v.6M23.3 201.8h.4M23.6 202.5h.3l-.2 .2h.2v.4h-.3M24.1 209.2h.3l-.1-.4h-.2v.6M24.3 201.5h-.3l-.1-.3h.4v.4l-.3 .2M24.3 202.5v.6M24.3 209.2l.1 .2M24.4 202.7l-.1 .2 .1 .2M24.6 201.1l-.1 .4h.3"/>
<path d="M24.7 208.9h.3l-.3 .5h.3M24.8 201.4v.4M25.4 208.8l.2 .3-.1 .3h-.2zM25.5 210.6v.3h.3l-.1-.2 .3-.1v.3M25.5 210.4h.6M25.7 210.1l.3 .3M26 209.1l-.2-.1 .2-.2 .2 .2-.4 .3 .1 .1 .3-.1-.2-.2M26 211.2h.1M26.1 211.6h-.6l.2 .2M26.1 211.5v.3M26.1 210.1l-.2 .2M27.2 211.8l.2-.1 .2 .2-.5 .4h.5"/>
<path d="M27.8 212v.3h.3v-.3M28.2 209.8l-.4 .1v.5h.4M28.3 212h.3M28.4 210l.2-.2v.6M28.4 210.4h.3M28.5 204.5l-.3-.1v.2v.4l.3-.1M28.7 211.7h-.4v.6M28.7 204.6l.2-.2v.6M28.7 205h.4M29 209.8h.3v.2l-.4 .4h.4M29.2 205.5l.2-.1v.6M29.2 206h.4"/>
<path d="M29.3 204.6l.2-.2v.6M29.3 205h.4M29.6 209.8h.2v.6l-.3-.2zM29.6 201.6h.3v-.3h-.3v.6M29.8 201.6l.1 .3M29.8 205.6v.4h.3v-.4M30.2 202.5h.3l-.1 .2h.1v.4h-.3M30.2 201.5l.2-.2v.6M30.2 204.4h-.3v.3h.3l.1 .2h-.4M30.2 201.9h.3M30.4 205.7h.1M30.6 205.4h-.2v.6"/>
<path d="M30.8 202.5v.6M30.9 202.9l.1 .2M31 202.7l-.2 .2M31.1 201.5l-.2 .2-.1-.4 .3 .1-.1 .5h-.2M31.6 201.3h-.2v.3l.2-.1 .1 .3-.3 .1M35.6 213.6l.1 .6 .2-.1v-.5M35.9 208.2v.6h.3M36.2 213.7l.2-.1v.6M36.2 203.3v.6h.3v-.6M36.2 214.2h.3M36.4 208.6h.2M36.7 208.2h-.3v.6"/>
<path d="M36.8 213.6a.3 .3 0 0 1 .4 .2 .3 .3 0 0 1-.3 .4zM36.8 203.5l.2-.2v.6M36.8 203.9h.3M36.9 208.2h.3l-.2 .3 .2 .1v.2h-.3M37.5 203.3l.2 .2-.1 .4-.2-.1v-.3zM37.6 213.6l-.2 .1v.4l.1 .1 .2-.2-.2-.3-.1 .2M37.7 208.2h-.2v.4l.2-.1 .1 .2-.3 .1M38 208.2h.4l-.3 .6M38.1 203.3l.2 .3-.1 .3h-.2zM41.4 214.7h.3v-.3h-.3v.6M41.5 208.2l.4-.1-.1-.2h-.3v.6M41.5 214.7l.2 .3"/>
<path d="M41.6 208.2l.3 .3M42 214.4h.3v.3l-.3 .3h.3M42 208l.4-.1v.3l-.4 .3h.4M42.5 214.6l.2-.2v.6M42.5 215h.4M42.6 208h.4l-.1 .5-.3-.1zM42.9 216.4l.6-.1v.2l-.5 .1zM42.9 215.8l.5-.1 .1 .2-.5 .1zM42.9 209.6h.6M42.9 209.3l.3 .3M43.1 214.4h.4l-.3 .2 .3 .2-.2 .2-.2-.1M43.5 217h-.6l.2 .2"/>
<path d="M43.5 210h-.6l.2 .2M43.5 209.8v.4M43.5 216.9v.3M43.5 209.3l-.4 .2M43.6 207.9h-.4v.3h.4l-.1 .3-.3-.1M44.2 202.8h.2l.1-.2-.3-.1v.6M44.2 202.8l.3 .3M44.3 203.8l.2-.2v.6M44.3 204.2h.4M44.7 202.6l.1-.1v.6M44.7 203.1h.3M45 203.6h.2l.1 .2-.1 .4-.3-.1z"/>
<path d="M45.5 203.6v.6M45.5 203.9l.3 .3M45.6 202.7l-.2 .2-.1-.3 .1-.1 .2 .1v.4l-.3 .1M45.8 203.8l-.3 .2M45.8 202.5h.4l-.3 .6M48.8 202.7h.3v-.2l-.3-.1v.6M49 203.8l.1-.2v.6M49 204.2h.3M49 202.7l.1 .3M49.4 202.6l.2-.2v.6M49.4 203h.3M49.6 203.7h.3l-.1 .5-.2-.1z"/>
<path d="M49.9 208.7h.3v.6h-.3zM50.2 203.6v.6M50.2 202.6l-.2 .1-.1-.2 .3-.1v.4l-.2 .2M50.2 203.9l.2 .3M50.4 203.8l-.2 .2M50.5 209.3h.1M50.7 201.3l.3-.1v.5l-.2 .1-.1-.2zM50.7 202.6l-.2-.1 .3-.1v.2l-.3 .1 .1 .3h.2v-.4M50.8 208.8l.2-.1 .1 .2-.4 .4h.4M50.9 200.2l-.2-.1-.1 .2 .1 .4 .2-.1M51.2 207l-.4 .1v.4h.4M51.2 200.3l.2-.2v.6"/>
<path d="M51.2 200.7h.3M51.3 208.8l.3-.1v.3l-.3 .3h.3M51.3 201.7v.1M51.4 207.1l.2-.1v.6M51.4 207.6h.4M51.5 201.2h.4v.3l-.4 .3h.4M51.8 200.3l.1-.2v.6M51.8 200.7h.3M51.9 208.9v.4h.2M52 207.1l.2-.1v.6M52 207.6h.4M52.1 201.2h.4v.3l-.4 .3h.4"/>
<path d="M52.1 208.9v.4M52.3 200.1h.3l-.1 .3h.1v.3l-.3-.1M52.5 209h.1M52.5 207h.5l-.3 .6M52.7 208.7h-.2v.6M52.7 201.4v.3h.3M53 201.4v.4M53.2 201.5h.3M53.6 201.2h-.4v.6M57.3 204.4l.1 .6h.2v-.6M57.9 204.6l.1-.2v.6M57.9 205h.3"/>
<path d="M58.5 203.3v.6h.4M58.5 204.4l.3 .1-.1 .5h-.2v-.2zM59.1 204.5h.3l-.3 .5h.3M59.1 203.7h.1M59.3 203.3h-.2v.6M59.5 203.3h.4l-.3 .3h.2l.1 .2-.4 .1M59.6 212.4h.3l.1-.2-.4-.1v.6M59.7 212.4l.3 .3M60.2 212.1h.3v.3l-.3 .3h.3M60.2 207.6h.2l.2-.2-.4-.1v.6M60.3 207.6l.3 .3M60.4 203.3h-.2l-.1 .4 .3-.1v.3h-.3"/>
<path d="M60.7 203.3h.4l-.4 .6M60.7 207.4l.4-.1v.3l-.4 .3h.4M60.7 212.2h.4v.4l-.2 .1-.2-.1zM61.3 207.4h.4l-.1 .5-.3-.1zM61.5 213.3h.6M61.6 208.9h.6M61.7 212.4l-.4 .1v-.4h.4v.5l-.4 .1M61.7 213.1l.2 .2M61.8 208.7l.2 .2M61.9 207.3h.4l-.2 .3h.2v.2h-.4M62.1 213.7h-.6l.2 .2M62.1 213.6v.3"/>
<path d="M62.1 213.1l-.3 .2M62.2 209.3h-.6l.2 .2M62.2 209.2v.3M62.2 208.7l-.2 .1M63.1 204.2h.2l.2-.3-.4-.1v.6M63.2 204.2l.3 .2M63.4 204.9l.1-.1v.6M63.4 205.4h.3M63.6 204l.2-.2v.6M63.6 204.4h.4M63.7 211.9h.3l-.1 .6h-.2l-.1-.3zM64.1 204.8l.2 .1-.1 .5-.2-.1v-.4z"/>
<path d="M64.2 212.4v.1M64.6 211.9h.2l.1 .1-.4 .5h.4M64.6 204.1l-.4 .1v-.3h.4v.4l-.3 .1M64.6 204.8v.6M64.6 205.2l.2 .2M64.7 209.8l-.3 .1v.4l.2 .1h.1M64.8 205l-.2 .2M65 210l.2-.2v.6M65 210.4h.3M65.1 211.9h.3v.2l-.3 .4h.3M65.2 204.1l-.4 .1v-.4l.4 .1-.1 .4-.3 .1M65.6 209.8h.2l.1 .2-.4 .4h.4"/>
<path d="M65.7 212v.4h.2M65.9 212v.5M66.1 210l.2-.2v.6M66.1 210.4h.4M66.3 212.1h.1M66.5 211.9h-.2v.6M72.8 205.6v.6h.3v-.6M73.4 205.8l.1-.2v.6M73.4 206.2h.3M73.5 203.1v.6h.4M74 205.7h.3l-.1 .5-.2-.1zM74 203.4h.2"/>
<path d="M74.3 203.1h-.3v.6M74.5 203.1h.4l-.3 .2h.2l.1 .3-.4 .1M74.6 205.6l-.1 .4h.4M74.8 205.9v.3M75.4 203.1h-.3v.3l.3-.1 .1 .3-.4 .1M75.6 203.1h.5l-.3 .6M76.8 213.7v-.6l.2 .5 .2-.5v.6M77.9 213.2l-.2-.1-.3 .3 .2 .3h.3M78.1 213.5l.3-.1v-.3h-.3v.6M78.4 205.4h-.1l-.3 .2 .2 .4h.2M78.6 205.5l.2-.1v.6M78.6 206h.4"/>
<path d="M78.8 213.1l-.1 .5h.3M79 213.4v.3M79.2 213.3l.2-.2v.6M79.2 205.5l.2-.1v.6M79.2 206h.3M79.2 213.7h.3M79.8 211.5v.5l.2 .1 .1-.1v-.5M80.1 213.1l-.3 .2v.4h.3v-.3l-.3 .1M80.1 205.4l-.3 .1v.5h.3v-.4l-.3 .1M80.4 204.7l.2-.2v.6M80.4 213.3l.2-.2v.6M80.4 211.7l.2-.2v.6"/>
<path d="M80.4 205.1h.3M80.4 213.7h.3M80.4 212.1h.4M81 204.8l.1 .3h.2v-.3M81.1 211.5h.2l-.1 .6-.2-.2zM81.6 204.9h.1M81.7 211.8l-.1-.3h.3l-.1 .3h-.2l.1 .3 .2-.1-.1-.2M81.8 204.5h-.2v.6M83 208.8l.4-.1-.1-.2h-.3v.6M83.1 208.8l.3 .3M83.6 208.6l.3-.1v.2l-.4 .4h.4M84.2 208.5l.3 .1v.5h-.3l-.1-.2z"/>
<path d="M84.3 210.5v.4h.2v-.4h.4l-.1 .4M84.3 210l.5-.1 .1 .3-.5 .1zM84.3 209.7h.6M84.5 209.4l.2 .3M84.7 208.5h.3l-.2 .6M84.9 211.3h-.6l.2 .2M84.9 211.1v.4M84.9 209.4l-.3 .2M92.8 200.1h.4M93 200.1v.6M93.3 200.5l.3-.1-.1-.1-.2 .1v.3h.3M93.9 200.5l.2-.1-.1-.1-.1 .1v.3h.2"/>
<path d="M94.4 200.4h.2v.3M94.4 200.3v.4M95.1 200.4h-.2l.2 .1v.2h-.2M95.4 200.3l.1 .4M95.6 200.3l-.2 .6M96 200.1l-.2 .4h.4M96.1 200.3v.4M96.4 200.6v.1M96.6 200.3l.3-.2v.6M96.6 200.7h.5M97.4 200.1l.1 .6h.2v-.6M98.3 200.1h-.1l-.2 .3 .1 .3h.2v-.3h-.3"/>
<path d="M98.7 200.4v-.3h.2v.3h-.3l.1 .3h.2l-.1-.3M126.8 210.4h.2l.1-.2-.3-.1v.6M126.9 208.9v.3h.2v-.3l.3-.1v.4M126.9 208.3h.5l.1 .3h-.6zM126.9 208.1h.6M126.9 210.4l.2 .3M127 207.8l.3 .3M127.3 210.1h.3v.3l-.3 .3h.3M127.5 209.6h-.6l.1 .2M127.5 209.4v.4M127.5 207.8l-.3 .2M128 210.1h.2l-.1 .6-.2-.2z"/>
<path d="M128.5 210.1h.3v.3l-.3 .3h.3M129.3 214.2l.2-.2v.6M129.3 207.1v.5h.4v-.5M129.3 214.6h.4M129.9 214.2l.1 .4h.3v-.4M129.9 207.2l.2-.1v.5M129.9 207.6h.4M130.5 206v-.6l.2 .4 .2-.4v.6M130.5 207.1h.3v.5h-.3l-.1-.1zM130.5 214.3h.2M130.8 214h-.3v.6M131 207.2l.2-.1v.5"/>
<path d="M131 207.6h.4M131.4 213.2l-.1-.1-.3 .3 .2 .3h.2M131.5 205.4h-.3v.5l.3 .1M131.7 213.3l.2-.2v.6M131.7 213.7h.3M131.8 205.7l.3-.1-.1-.2h-.2v.6M132.2 213.2h.3l-.3 .5h.3M132.5 205.4l-.1 .4h.3M132.6 205.6v.4M132.8 213.1h.3l-.1 .3 .1 .1v.2h-.3M132.9 205.5l.2-.1v.6M132.9 206h.4"/>
<path d="M133.8 205.4h-.2l-.1 .2 .1 .4h.2v-.4l-.3 .1M134.1 205.5l.1-.1v.6M134.1 206h.3M135.2 215.4v.6h.3M135.7 215.8h.2M136 215.4h-.3v.6M136.2 215.4h.3l-.1 .3 .1 .1v.2h-.3M136.4 213v.6l.3-.1v-.5M136.9 213.1l.2-.1v.6M136.9 213.6h.4M137 215.4h-.2v.4l.2-.1 .1 .2-.3 .1M137.3 215.4h.4l-.2 .6"/>
<path d="M137.5 213a.3 .3 0 0 1 .4 .2 .3 .3 0 0 1-.3 .4zM138.4 213h-.3v.2l.2-.1 .2 .3-.2 .2-.2-.1M144.8 206.7h.2l.1 .3-.1 .3-.3-.1zM145.1 208.8h-.4v.5h.4M145.3 207.2v.1M145.3 208.9l.2-.2v.6M145.3 209.3h.4M145.6 206.8l.2-.1 .1 .2-.4 .4h.4M145.9 208.9l.2-.2v.6M145.9 209.3h.4M146.1 206.8l.3-.1v.3l-.3 .3h.3M146.1 215.1h.2l.1-.3h-.3v.5"/>
<path d="M146.3 215.1l.1 .2M146.4 214l.2-.3v.7M146.4 214.4h.4M146.6 209l-.2-.2 .4-.1v.3l-.4 .1 .1 .2h.3l-.1-.3M146.7 214.8h.2l.1 .1-.4 .4h.4M146.8 206.9v.4l.2-.1M147 206.9v.4M147.1 213.7l.2 .1-.1 .6a.37 .37 0 0 1-.3-.3 .37 .37 0 0 1 .2-.4zM147.2 214.9l.2-.1v.5M147.2 215.3h.3M147.3 207h.1M147.5 206.7h-.2v.6"/>
<path d="M147.5 213.7v.7M147.6 214.2l.2 .2M147.8 214.8h.3l-.1 .5h-.2zM147.8 214l-.3 .2M148.9 209.9h.7M149 211.5h.2l.1-.1-.3-.1v.6M149.1 205.5h.5M149.1 211.5l.2 .4M149.1 209.7l.3 .2M149.2 205.3l.3 .2M149.5 211.3l.4 .1-.4 .5h.4M149.6 210.4h-.7l.2 .1"/>
<path d="M149.6 206.8l.3-.1-.1-.2h-.2v.6M149.6 210.2v.3M149.6 209.7l-.3 .1M149.6 206h-.5l.1 .1M149.6 205.8v.3M149.6 205.3l-.2 .1M149.7 206.8l.2 .3M150.2 215.2v.7h.3M150.2 211.3h.2l-.1 .6-.2-.3zM150.2 206.5h.2l.1 .1-.4 .5h.4M150.7 215.5h.2M150.7 206.5h.3l-.1 .6h-.2v-.3z"/>
<path d="M150.9 211.3l-.2 .1v.4h.3l-.1-.3-.2 .1M151 215.2h-.3v.7M151.2 215.2h.3l-.2 .2 .2 .1v.3h-.3M151.3 206.5h.3l-.1 .6-.2-.1zM151.8 214.2l.1 .6 .3-.2v-.4M152 215.2h-.2v.3l.1-.1 .2 .3-.2 .2-.1-.1M152.3 215.2h.4l-.3 .7M152.4 214.3l.2-.1v.6M152.4 214.8h.4M153 214.2a.3 .3 0 0 1 .4 .2 .3 .3 0 0 1-.3 .4zM153.5 214.2h.5l-.3 .6M157.8 217.4l.2 .1-.1 .5-.2-.1z"/>
<path d="M158.3 217.9v.1M158.5 217.5h.4l-.4 .5h.4M158.5 209.8a.3 .3 0 0 1 .4 .3 .3 .3 0 0 1-.3 .3l-.1-.2zM158.6 211.7l-.2-.1-.1 .2 .1 .4 .2-.1M158.9 218.5l-.4 .1v.3l.2 .2 .2-.1M158.9 211.8l.1-.2v.6M158.9 212.2h.3M159.1 217.5l.3-.1 .1 .2-.5 .4h.5M159.1 210.4h.1M159.1 218.7l.2-.2v.6M159.1 219.1h.4M159.4 209.8h.2l.1 .2-.4 .4h.4"/>
<path d="M159.5 211.7l.2-.1 .1 .2-.4 .4h.4M159.7 217.6v.4l.3-.1M159.7 218.5h.3l.1 .2-.5 .4h.5M159.9 209.8h.3v.3l-.3 .3h.3M160 211.7h.4l-.4 .5h.4M160 217.6v.4M160.2 217.6h.3M160.3 216.5h.3l.1-.3h-.4v.6M160.5 210v.4h.2M160.5 216.5l.2 .3M160.6 217.4h-.4v.6M160.6 218.5h-.3l-.1 .2v.2l.3 .2v-.4l-.3 .1"/>
<path d="M160.7 210v.4M160.8 215.2l.2-.2v.6M160.8 215.6h.4M160.9 216.2h.3v.3l-.3 .3h.3M161.1 210.1h.1M161.3 209.8h-.2v.6M161.4 215h.3l-.1 .6-.3-.3zM161.5 216.4l.2-.2v.6M161.5 216.8h.3M161.9 215v.6M162 215.3l.2 .3M162.1 216.4l.2-.2v.6"/>
<path d="M162.1 216.8h.3M162.2 215.2l-.3 .2M165.1 216.4l.3-.1-.2-.3h-.1v.6M165.1 216.4l.3 .2M165.5 215.2l.2-.2v.6M165.5 215.6h.3M165.6 216.1h.3l-.3 .5h.3M166.1 215a.3 .3 0 0 1 .3 .3 .3 .3 0 0 1-.2 .3zM166.2 216.2l.1-.2v.6M166.2 216.6h.3M166.7 215v.6M166.7 215.3l.1 .3"/>
<path d="M166.8 216.1h.3l-.3 .5h.3M166.8 215.2l-.1 .2M167.6 202.7h.7a.35 .35 0 0 1-.4 .3 .35 .35 0 0 1-.3-.3zM167.6 202.1h.6l.1 .1-.2 .2h-.3zM167.6 209.3h.7M167.6 209l.4 .3M167.7 210.9h.2l.1-.1-.3-.1v.6M167.8 204.5h.3v-.3h-.3v.6M167.8 210.9l.2 .4M167.9 204.5l.2 .3M168.2 210.7l.4 .1-.4 .5h.4M168.3 209.8h-.7l.3 .1"/>
<path d="M168.3 203.3h-.7l.3 .2M168.3 203.2v.3M168.3 209.6v.3M168.3 209l-.4 .3M168.4 204.3l.1-.1v.6M168.4 204.8h.3M168.9 210.7h.2l-.1 .6-.2-.3zM169.3 204.4l-.3 .2v-.4l.3 .1-.1 .5h-.2M169.5 210.6l-.1 .4h.3M169.6 210.9v.4M169.8 204.2h-.2l-.1 .2v.3l.3 .1v-.4l-.3 .1M172.8 210.3v.6h.4"/>
<path d="M172.9 215.2l.1 .7 .3-.1v-.6M173.4 210.6h.1M173.5 215.4l.2-.2v.7M173.5 205l.1 .6 .3-.1v-.5M173.5 215.9h.4M173.6 210.3h-.2v.6M173.8 210.3h.4l-.3 .2h.2l.1 .3-.4 .1M174.1 205.2l.2-.2v.6M174.1 205.6h.4M174.3 215.2l.2 .1v.4l-.2 .2-.2-.2v-.4zM174.7 210.3h-.2l-.1 .3 .3-.1 .1 .3-.4 .1M174.7 205.1h.3v.5l-.3-.1z"/>
<path d="M175 210.3h.4l-.3 .6M175 215.5l-.3 .1 .1-.4 .2 .1v.3l-.1 .3h-.2M175.2 205h.4l-.2 .3h.2v.2h-.4M179.5 217.6h.4v-.3h-.4v.6M179.7 217.6l.2 .3M180.1 216h.4l-.2 .3h.2v.3h-.4M180.1 217.3h.4v.3l-.4 .3h.4M180.6 213.3l.1-.2v.6M180.6 213.7h.3M180.7 217.5l.2-.2v.6M180.7 216v.6M180.7 217.9h.4"/>
<path d="M180.8 216.5l.2 .1M181 216.3l-.3 .2M181.1 213.4l.1 .3h.2v-.3M181.3 214.2h-.3v.5h.3M181.4 217.2l-.2 .4h.5M181.6 214.3l.1-.1v.6M181.6 214.8h.3M181.6 217.5v.4M181.7 208.8l-.3-.1-.1 .2 .1 .4h.3M181.7 213.5h.2M181.9 208.9l.2-.2v.6M181.9 209.3h.3"/>
<path d="M182 213.1h-.3v.6M182.2 214.2h.2l.1 .1-.4 .5h.4M182.5 208.9l.2-.2v.6M182.5 209.3h.3M182.6 206.9h.3l-.3 .5h.3M182.8 214.1l-.1 .4h.4M183 214.3v.5M183.2 207.1l.1 .3h.1v-.3M183.4 209l-.3 .1-.1-.3h.4l-.1 .5h-.2M183.8 207.1h.1M184 206.8h-.2v.6M185 208v.2h.3v-.2l.2-.1v.3"/>
<path d="M185 210h.4l-.1-.3h-.3v.6M185 207.6h.6M185.2 207.5l.3 .1M185.2 210l.2 .3M185.5 208.5h.1M185.6 208.9h-.6l.2 .2M185.6 209.8h.4l-.4 .5h.4M185.6 208.7v.4M185.6 207.5l-.2 .1M186.3 209.7l.3 .2-.1 .4h-.3zM186.4 217.7h.2l.1-.2-.3-.1v.6M186.6 217.7l.1 .3"/>
<path d="M186.7 216h.4l-.2 .3 .2 .1v.2h-.4M186.7 209.8l.2-.1v.6M186.7 210.3h.4M187 217.5l.2-.1 .1 .2-.4 .4h.4M187.3 216v.6M187.4 216.5l.2 .1M187.5 217.6l.2-.2v.6M187.5 218h.3M187.6 216.3l-.3 .2M187.9 213.3l.2-.2v.6M187.9 213.7h.4M188.4 217.4h-.3v.2h.3l-.1 .4-.2-.1"/>
<path d="M188.4 214.3l-.2-.1-.2 .3 .2 .3h.2M188.5 213.4v.3h.3v-.3M188.6 214.4l.2-.2v.6M188.6 214.8h.3M189 213.5h.3M189.2 214.3l.3-.1v.3l-.3 .3h.3M189.4 213.1h-.4v.6M190.1 214.2h-.3v.4h.3v.2h-.3M192.3 211.4v.6M192.7 216.2v.6l.4-.1v-.5M192.9 211.4v.6l-.3-.6v.6M193.2 212l.1-.6 .3 .6"/>
<path d="M193.3 211.8h.2M193.3 216.4l.2-.2v.6M193.3 216.8h.4M193.8 211.6v-.2h.2l.1 .1-.3 .2v.3l.3-.1-.2-.3M193.9 216.4l.2-.2v.6M193.9 216.8h.4M194.3 211.5l.3-.1v.2l-.3 .4h.3M194.5 216.2h.3l-.1 .6h-.2l-.1-.3zM194.9 211.4h.3l-.2 .2 .2 .1v.3h-.3M198.2 216.7l.5-.1 .1 .2-.1 .2h-.4zM198.2 216.1l.4-.1 .2 .3-.6 .1zM198.2 215.5l.4-.1 .2 .2a.3 .3 0 0 1-.3 .3 .3 .3 0 0 1-.3-.4z"/>
<path d="M198.8 216.4l.3-.1-.2-.3h-.1v.6M198.8 217.4h-.6l.2 .2M198.8 217.2v.4M198.8 216.4l.3 .2M199.3 216.1h.3l-.3 .5h.3M199.9 216.2l.1-.2v.6M199.9 216.6h.3M200.7 216l-.3 .2v.4h.4l-.1-.3-.3 .1M10.5 225h.2l.1-.2-.3-.1v.6M10.5 225l.3 .3M11 224.7h.2l.2 .1-.4 .5h.4M11.6 224.8l.1-.1v.6"/>
<path d="M11.6 225.3h.3M12.1 224.7h.4l-.3 .6M12.3 225.1l.4-.1 .2 .1v.2h-.5zM12.4 223.9h.4l.1 .3h-.6zM12.9 225.8h-.6l.2 .1M12.9 225.6v.3M16 229.4v.6M16.4 224.6l.1 .6h.2v-.6M16.6 229.4v.6l-.3-.6v.6M16.8 230l.3-.6 .1 .6M16.9 229.8h.2M17 224.7l.1-.1v.6"/>
<path d="M17 225.2h.3M17.5 229.7l-.1-.3h.3v.3h-.3l.1 .3 .2-.1v-.2M17.6 224.7l.1-.1v.6M17.6 225.2h.3M18 229.4h.3v.3l-.4 .3h.4M18.2 224.7l.1-.1v.6M18.2 225.2h.3M18.5 229.4h.4l-.2 .2 .2 .2-.1 .2-.3-.1M21.5 226.5h-.3l-.2 .3 .1 .2h.4M21.6 226.7l.2-.2v.6M21.6 227.1h.4M21.9 227.7l.2-.2v.6"/>
<path d="M21.9 228.1h.3M22.2 226.5h.4v.3l-.4 .3h.4M22.5 227.8v.3h.2v-.3M22.8 223.7h.2l.2-.2-.4-.1v.6M22.9 226.8l-.1-.3h.4l-.1 .3h-.3l.1 .3 .3-.1-.1-.2M22.9 223.7l.3 .3M23.1 227.9h.1M23.3 227.5h-.2v.6M23.3 223.4h.4v.2l-.4 .4h.4M23.6 224.7h.3l-.2 .2h.2v.4h-.3M23.9 223.6l.2-.2v.6M23.9 224h.4"/>
<path d="M24.1 231.4h.3v-.3l-.3-.1v.7M24.3 224.7v.6M24.3 231.4l.1 .3M24.4 224.9l-.1 .2 .1 .2M24.6 223.6l-.1-.2 .3 .1v.1h-.3v.4h.3v-.3l-.1-.1M24.7 231.1h.3v.3l-.3 .3h.3M25.2 231h.4l-.2 .3 .2 .2-.2 .2-.2-.1M25.5 232.8v.2l.3 .1-.1-.2 .3-.1v.3M25.5 232.5h.6M25.7 232.3l.3 .2M25.8 231.1l.2-.1 .2 .2-.4 .5h.4M26 233.4h.1"/>
<path d="M26.1 233.8h-.6l.2 .2M26.1 233.6v.4M26.1 232.3l-.2 .2M27.2 234l.2-.1 .2 .2-.5 .5h.5M27.8 234.1v.4h.3M28.1 234.1v.5M28.2 232l-.4 .1v.4h.4M28.3 234.2h.3M28.4 232.2l.2-.2v.6M28.4 232.6h.3M28.5 226.7l-.3-.1v.2v.4l.3-.1M28.7 233.9h-.4v.7"/>
<path d="M28.7 226.8l.2-.2v.6M28.7 227.2h.4M28.9 232h.4l-.2 .3 .2 .1v.1h-.4M29.2 227.7l.2-.2v.6M29.2 228.1h.4M29.3 226.7l.3-.1 .1 .2-.4 .4h.4M29.6 223.8h.3l-.1-.3h-.2v.6M29.7 231.9l-.2 .6h.4M29.8 223.8l.1 .3M29.8 227.8v.3h.3v-.3M29.8 232.2v.4M30.2 224.7h.3l-.1 .2h.1v.4h-.3"/>
<path d="M30.2 223.6h.3l-.3 .5h.3M30.3 226.9h-.4v-.3l.4 .1-.1 .4-.3 .1M30.4 227.9h.1M30.6 227.5h-.2v.6M30.8 223.6l.1-.1v.6M30.8 224.7v.6M30.8 224.1h.3M30.9 225.1l.1 .2M31 224.9l-.2 .2M31.7 223.7l-.2 .2-.1-.1 .1-.3 .2 .1v.2l-.1 .3h-.2M35.6 235.8l.1 .5h.2v-.5M35.9 230.4v.6h.3"/>
<path d="M36.2 225.5v.6h.3v-.6M36.2 235.9l.2-.1v.5M36.2 236.3h.3M36.4 230.8h.2M36.7 230.4h-.3v.6M36.8 225.7l.2-.2v.6M36.8 235.9l.2-.1v.5M36.8 226.1h.3M36.8 236.3h.3M36.9 230.4h.3l-.2 .3 .2 .1v.2h-.3M37.4 225.7l.1-.2v.6M37.4 226.1h.3"/>
<path d="M37.5 236l-.1-.2h.3l-.3 .2 .1 .3 .2-.1-.2-.2M37.7 230.4h-.2v.4l.2-.1 .1 .2-.3 .1M38 230.4h.4l-.3 .6M38 225.6l.1-.1 .2 .2-.4 .4h.4M41.4 236.9h.3v-.3h-.3v.6M41.5 230.4l.4-.1-.1-.2h-.3v.6M41.5 236.9l.2 .3M41.6 230.4l.3 .3M42 236.6h.3v.3l-.3 .3h.3M42 230.2l.4-.1v.2l-.4 .4h.4M42.5 236.6h.4l-.3 .2 .3 .2-.2 .2-.2-.1M42.6 230.2l.4-.1v.2l-.4 .4h.4"/>
<path d="M42.9 238.5h.5l.1 .2-.5 .1zM42.9 238l.5-.1 .1 .3h-.5zM42.9 231.8h.6M42.9 231.4l.3 .4M43.1 236.6h.4l-.3 .6M43.5 232.3h-.6l.2 .2M43.5 239.2h-.6l.2 .2M43.5 232v.5M43.5 239.1v.3M43.5 231.4l-.4 .3M43.6 230.3l-.3 .2-.1-.3h.4v.4l-.3 .1M44.2 225h.2l.1-.2-.3-.1v.6"/>
<path d="M44.2 225l.3 .3M44.3 225.9l.2-.1v.6M44.3 226.4h.4M44.7 224.7h.3l-.3 .6h.3M44.9 225.8h.3v.6h-.3zM45.3 224.7h.3l-.3 .6h.3M45.5 225.8v.6M45.8 226l-.3 .2 .3 .2M45.8 224.8l.2-.1v.6M45.8 225.3h.4M48.8 224.9l.3-.1v-.2h-.3v.6M49 225.9l.1-.1v.6"/>
<path d="M49 226.4h.3M49 224.9l.1 .3M49.4 224.7l.3-.1v.1l-.4 .5h.4M49.6 225.8h.3l-.1 .6-.2-.1zM49.9 230.9h.3v.6h-.3zM49.9 224.7l.3-.1v.2l-.3 .4h.3M50.2 225.8v.6M50.2 226.2l.2 .2M50.4 226l-.2 .2M50.5 231.4v.1M50.5 224.7l.3-.1v.2l-.3 .4h.3M50.7 223.5l.3-.1-.1 .6-.2-.1z"/>
<path d="M50.8 231l.2-.1 .1 .2-.4 .4h.4M50.9 222.4l-.2-.1-.1 .2 .1 .4 .2-.1M51.2 222.5l.2-.2v.6M51.2 229.2h-.4v.5h.4M51.2 222.9h.3M51.3 223.9v.1M51.3 231l.3-.1v.3l-.3 .3h.3M51.4 229.3l.2-.1v.5M51.4 229.7h.4M51.5 223.4h.4v.2l-.4 .4h.4M51.8 222.4l.2-.1 .1 .2-.4 .4h.4M51.9 231.1v.3h.2"/>
<path d="M51.9 229.2h.5l-.3 .2 .3 .1v.2h-.5M52.1 223.4h.4v.2l-.4 .4h.4M52.1 231.1v.4M52.3 222.3h.4l-.2 .6M52.5 231.2h.1M52.5 229.3l.2-.1v.5M52.5 229.7h.4M52.7 223.6v.4l.3-.1M52.7 230.9h-.2v.6M53 223.6v.4M53.2 223.6h.3M53.6 223.4h-.4v.6"/>
<path d="M57.3 226.6l.1 .6h.2v-.6M57.9 226.8l.1-.2v.6M57.9 227.2h.3M58.5 226.8l.1-.2v.6M58.5 227.2h.3M58.5 225.5v.6h.4M59.1 225.8h.1M59.2 226.6l-.1 .4h.3M59.3 225.5h-.2v.6M59.3 226.8v.4M59.5 225.5h.4l-.3 .3h.3v.2l-.4 .1M59.6 234.6h.3l.1-.2-.4-.1v.6"/>
<path d="M59.7 234.6l.3 .3M60.2 234.3h.3v.3l-.3 .3h.3M60.2 229.8l.4-.1-.1-.2h-.3v.6M60.3 229.8l.3 .3M60.4 225.5h-.2l-.1 .3h.3v.3h-.3M60.7 225.5h.4l-.4 .6M60.7 229.6l.4-.1v.2l-.4 .4h.4M60.7 234.3h.4l-.2 .2 .2 .1v.2h-.4M61.3 234.3h.4l-.3 .2 .3 .1v.2h-.4M61.3 229.6l.4-.1v.2l-.4 .4h.4M61.5 235.5h.6M61.6 231.1h.6"/>
<path d="M61.7 235.3l.2 .2M61.8 230.8l.2 .3M61.9 229.5h.4l-.3 .6M62.1 235.9h-.6l.2 .2M62.1 235.8v.3M62.1 235.3l-.3 .2M62.2 231.5h-.6l.2 .2M62.2 231.4v.3M62.2 230.8l-.2 .2M63.1 226.4l.4-.2-.1-.2h-.3v.6M63.2 226.4l.3 .2M63.4 227.1l.1-.2v.6"/>
<path d="M63.4 227.5h.3M63.6 226.1l.4-.1v.3l-.4 .3h.4M63.7 234.1h.3l-.1 .6h-.2l-.1-.3zM64.1 226.9l.2 .2-.1 .4h-.2v-.4zM64.2 234.6v.1M64.2 226.1h.4l-.4 .5h.4M64.6 234.1h.2l.1 .1-.4 .5h.4M64.6 226.9v.6M64.6 227.4l.2 .1M64.7 232h-.2l-.1 .2 .1 .4 .2-.1M64.7 226h.5l-.3 .3h.2l.1 .2h-.5M64.8 227.2l-.2 .2"/>
<path d="M65 232.2l.2-.2v.6M65 232.6h.3M65.1 234.1h.3v.2l-.3 .4h.3M65.5 232h.4l-.2 .3 .2 .1v.1h-.4M65.7 234.2v.4h.2M65.9 234.2v.5M66.3 234.3h.1M66.4 232h-.2l-.1 .3h.3l.1 .2h-.4M66.5 234.1h-.2v.6M72.8 227.8v.6h.3v-.6M73.4 228l.1-.2v.6M73.4 228.4h.3"/>
<path d="M73.5 225.3v.6h.4M74 228l.1-.2v.6M74 228.4h.3M74 225.6h.2M74.3 225.3h-.3v.6M74.5 225.3h.4l-.3 .2 .3 .3-.2 .1-.2-.1M74.8 227.8l-.3 .2v.4l.4-.1-.1-.3-.3 .1M75.4 225.3h-.3v.3l.2-.1 .2 .3-.2 .1-.2-.1M75.6 225.3h.5l-.3 .6M76.8 236v-.7l.2 .5 .2-.5v.7M77.9 235.4h-.4l-.1 .3 .1 .2h.4M78.1 235.7h.3v-.4h-.3v.7"/>
<path d="M78.4 227.6l-.1-.1-.3 .3 .2 .3h.2M78.6 227.7l.2-.2v.6M78.6 228.1h.4M78.8 235.3l-.1 .5h.3M79 235.6v.4M79.2 235.6l.2-.3v.7M79.2 227.5h.3l-.1 .3 .1 .1v.2h-.3M79.2 236h.3M79.8 233.7v.4l.2 .2 .1-.1v-.5M80 227.5l.1 .2v.4l-.3-.1v-.3zM80.1 235.3l-.3 .2v.4h.3v-.3l-.3 .2M80.4 235.6l.2-.3v.7"/>
<path d="M80.4 226.9l.2-.2v.7M80.4 233.9l.2-.2v.6M80.4 234.3h.4M80.4 236h.3M80.4 227.4h.3M81 226.9l.1 .5 .2-.1M81 233.7h.3v.3l-.3 .3h.3M81.3 226.9v.5M81.6 233.8h.3v.3l-.2 .2-.1-.2zM81.6 227h.1M81.8 226.7h-.2v.7M82.4 231h.3l.1-.2-.4-.1v.6"/>
<path d="M82.5 231l.3 .3M82.9 230.8l.3-.1 .2 .1-.5 .5h.5M83.5 230.7h.4l-.2 .2h.2v.4h-.4M83.7 232.7v.3h.2v-.3l.4 .1-.1 .2M83.7 232.2l.5-.1 .1 .3-.6 .1zM83.7 231.9h.6M83.9 231.6l.2 .3M84.1 230.8l.2-.1v.6M84.1 231.3h.4M84.3 233.5h-.6l.2 .1M84.3 233.3v.3M84.3 231.6l-.3 .2"/>
<path d="M127.4 232.5h.2l.1-.1-.3-.1v.6M127.5 231.1v.3h.2v-.3l.3-.1v.4M127.5 230.6l.5-.1 .1 .3h-.4h-.2zM127.5 230.3h.6M127.5 232.5l.2 .4M127.6 230l.3 .3M127.9 232.3l.4 .1-.4 .5h.4M128.1 231.8h-.6l.1 .1M128.1 231.6v.3M128.1 230l-.3 .2M128.5 232.3h.3v.2l-.3 .4h.3M129.3 232.3l-.2 .1v.4h.3l-.1-.3-.2 .1"/>
<path d="M129.9 236.3l.3-.1v.6M129.9 229.2v.6l.4-.1v-.5M129.9 236.8h.4M130.5 229.4l.2-.2v.6M130.5 229.8h.4M130.6 236.4v.4h.3v-.4M131.1 228.1v-.6l.2 .5 .2-.5v.6M131.1 229.4l.2-.2v.6M131.1 229.8h.3M131.1 236.5h.2M131.4 236.2h-.3v.6M131.6 229.2h.4l-.2 .3h.2v.3h-.4"/>
<path d="M132 235.4h-.3v.5h.3M132.1 227.6h-.3v.4l.3 .1M132.3 235.6l.2-.3v.7M132.3 236h.3M132.4 227.9h.2l.1-.3-.3-.1v.6M132.8 235.3h.3l-.1 .3 .1 .1v.2h-.3M133.1 227.5l-.1 .5h.3M133.2 227.8v.3M133.4 235.3h.3l-.2 .7M133.6 227.7l.1-.2v.6M133.6 228.1h.3M134.4 227.5h-.2l-.1 .3v.2l.3 .1v-.3l-.3 .1"/>
<path d="M134.7 227.7l.1-.2v.6M134.7 228.1h.3M135.8 237.6v.6h.3M136.3 238h.2M136.6 237.6h-.3v.6M136.8 237.6h.3l-.2 .3 .2 .1v.2h-.3M136.9 235.2l.1 .6 .3-.1v-.5M137.5 235.3l.2-.1v.6M137.5 235.8h.4M137.6 237.6h-.2v.4l.2-.1 .1 .2-.3 .1M137.9 237.6h.4l-.3 .6M138.1 235.3l.2-.1v.6"/>
<path d="M138.1 235.8h.4M138.6 235.2h.5l-.3 .6M145.3 229l.3-.1v.6l-.3-.1zM145.7 231l-.3-.1-.1 .2 .1 .4 .3-.1M145.9 229.4v.1M145.9 231.1l.2-.2v.6M145.9 231.5h.4M146.2 229l.2-.1 .1 .2-.4 .4h.4M146.4 230.9h.5l-.3 .3 .3 .1v.1h-.5M146.7 237.3h.2l.1-.3-.3-.1v.6M146.8 229l.2-.1 .1 .2-.4 .4h.4M146.9 237.3l.1 .2"/>
<path d="M147 236.2l.2-.2v.6M147 231h.4l-.4 .5h.4M147 236.6h.4M147.3 237l.2-.1 .1 .2-.4 .4h.4M147.4 229.1v.4l.2-.1M147.6 236h.3l-.1 .6-.3-.3zM147.6 229.1v.4M147.8 236.9h.3l-.1 .3h.1v.3l-.3-.1M147.9 229.2h.1M148.1 228.9h-.2v.6M148.1 236v.6M148.2 236.3l.2 .3"/>
<path d="M148.4 236.2l-.3 .2M148.5 236.9l-.1 .5h.4M148.7 237.1v.4M149.6 233.8h.2l.1-.3h-.3v.6M149.6 232.1h.6M149.6 227.7h.6M149.7 231.9l.3 .2M149.7 233.8l.2 .3M149.8 227.5l.3 .2M150.2 232.5h-.6l.1 .2M150.2 233.5h.2l.1 .1-.4 .5h.4M150.2 229h.2l.1-.3-.3-.1v.6"/>
<path d="M150.2 232.4v.3M150.2 231.9l-.3 .2M150.2 228.1h-.6l.2 .2M150.2 228v.3M150.2 227.5l-.2 .1M150.3 229l.2 .2M150.7 233.5h.3l-.2 .2h.2v.4l-.3-.1M150.7 228.7l.3-.1 .1 .2-.4 .4h.4M150.8 237.4v.6h.3M151.3 233.6h.3l-.1 .5-.2-.1zM151.3 228.7l.3-.1v.3l-.3 .3h.3M151.3 237.7h.2"/>
<path d="M151.6 237.4h-.3v.6M151.8 237.4h.3l-.2 .2 .2 .1v.3h-.3M152 228.6l-.2 .5h.5M152.2 228.9v.3M152.4 236.3v.6h.4v-.6M152.7 237.4h-.3v.3h.3v.3h-.3M152.9 237.4h.4l-.3 .6M153 236.5l.2-.2v.6M153 236.9h.4M153.6 236.5l.2-.2v.6M153.6 236.9h.4M154.5 236.6l-.3 .1-.1-.3 .4-.1v.5l-.3 .1"/>
<path d="M158.3 239.6h.3l-.1 .6-.2-.1zM159.1 239.6h.4l-.4 .6h.4M159.1 232h.3v.6l-.3-.1zM159.2 233.9l-.2-.1-.1 .2 .1 .4 .2-.1M159.5 234l.1-.2v.6M159.5 234.4h.3M159.7 239.6h.3l.1 .1-.5 .5h.5M159.7 232.5v.1M160 232h.2l.1 .2-.4 .4h.4M160 233.8h.4l-.2 .3h.2v.2h-.4M160.3 239.7v.5l.3-.1M160.5 232h.3v.3l-.3 .3h.3"/>
<path d="M160.6 239.7v.5M160.8 239.8h.3M160.9 233.8l-.2 .2v.4l.3-.1-.1-.2h-.2M161 238.7h.2l.1-.2-.3-.1v.6M161.1 238.7l.2 .3M161.2 239.6h-.4v.6M161.2 232.2v.4l.2-.1M161.4 237.4l.2-.2v.6M161.4 232.2v.4M161.4 237.8h.4M161.5 238.5l.3-.1v.2l-.3 .4h.3M161.7 232.3h.1"/>
<path d="M161.9 232h-.2v.6M162 237.2h.3l-.1 .6-.3-.3zM162.1 238.4h.3l-.1 .2h.1v.3h-.3M162.5 237.2v.6M162.6 237.5l.2 .3M162.8 237.4l-.3 .2M162.9 238.4h-.2v.2h.2l.1 .3h-.3M165.7 238.5h.2l.1-.1-.3-.2v.7M165.7 238.5l.3 .4M166.1 237.4l.1-.2v.6M166.1 237.8h.3M166.2 238.3l.2-.1 .2 .3-.4 .4h.4"/>
<path d="M166.7 237.2a.3 .3 0 0 1 .3 .2 .3 .3 0 0 1-.2 .4zM166.8 238.2h.3l-.2 .3h.2v.3h-.3M167.3 237.2v.6M167.3 237.5l.1 .3M167.4 237.4l-.1 .2M167.6 238.2l-.3 .2v.4h.4l-.1-.3-.3 .1M168.3 224.8l.6 .1a.3 .3 0 0 1-.4 .3 .3 .3 0 0 1-.2-.4zM168.3 224.3l.4-.1 .2 .2-.2 .2h-.3zM168.3 233.1h.3v-.2h-.3v.6M168.3 231.5h.6M168.3 231.2l.3 .3M168.4 226.7h.3v-.3h-.3v.5"/>
<path d="M168.4 233.1l.2 .4M168.5 226.7l.2 .2M168.9 231.9h-.6l.1 .2M168.9 225.5h-.6l.1 .2M168.9 232.9h.2l.1 .1-.4 .5h.4M168.9 225.3v.4M168.9 231.8v.3M168.9 231.2l-.4 .2M169 226.4h.3l-.3 .5h.3M169.4 232.9h.3v.2l-.3 .4h.3M169.5 226.4h.2l.2 .1-.4 .4h.4M170.1 233.1l-.1-.2h.3l-.1 .2h-.2l.1 .4 .2-.1-.1-.3"/>
<path d="M170.1 226.4h.2l.2 .2-.1 .3h-.3zM173.4 232.5v.6h.4M173.5 237.4l.1 .6h.3v-.6M173.9 232.8h.2M174.1 227.2l.1 .6h.3v-.6M174.1 237.6l.2-.2v.6M174.1 238h.4M174.2 232.5h-.3v.6M174.4 232.5h.4l-.3 .2 .3 .1v.2h-.4M174.7 227.4l.2-.2v.6M174.7 237.4h.3v.3l-.3 .3h.3M174.7 227.8h.3"/>
<path d="M175.3 232.5h-.3v.3l.2-.1 .2 .3-.2 .1-.2-.1M175.3 227.4l.2-.2v.6M175.3 237.6l.2-.2v.6M175.3 227.8h.3M175.3 238h.3M175.6 232.5h.4l-.3 .6M176.1 227.2h-.2v.3h.2l.1 .2-.3 .1M180.1 239.7h.4v-.2h-.4v.6M180.3 239.7l.2 .4M180.7 238.2h.4l-.2 .3h.2v.3h-.4M180.7 239.5h.4v.2l-.4 .4h.4M181.1 235.6l.2-.3v.7"/>
<path d="M181.1 236h.4M181.2 239.5h.5l-.3 .1 .3 .3-.2 .2-.3-.1M181.3 238.2v.7M181.4 238.6l.2 .3M181.6 238.5l-.3 .2M181.7 235.6v.3h.4M181.9 236.3h-.2l-.1 .2 .1 .4h.2M182 239.7l-.2-.1 .4-.1-.1 .2-.3 .1 .2 .3 .2-.1-.1-.3M182.1 235.6v.4M182.2 236.5l.1-.2v.6M182.2 236.9h.3M182.2 231l-.2-.1-.1 .2 .1 .4 .2-.1"/>
<path d="M182.3 235.7h.2M182.5 231.1l.2-.2v.6M182.5 231.5h.3M182.6 235.3h-.3v.7M182.7 236.3h.4l-.3 .3h.2l.1 .3h-.4M183 230.9h.4l-.1 .3h.1v.2h-.4M183.2 229.1h.3l-.3 .5h.3M183.4 236.6l-.1-.2 .3-.1v.3l-.3 .1v.2h.3l-.1-.3M183.6 230.9h.4l-.2 .3 .2 .1v.1h-.4M183.8 229.2l.1 .4h.1v-.4M184.4 229.3h.1M184.6 229h-.2v.6"/>
<path d="M185.6 230.2v.2h.3v-.2l.2-.1v.3M185.6 232.2h.4l-.1-.3h-.3v.6M185.6 229.8h.6M185.8 229.7l.3 .1M185.8 232.2l.2 .3M186.1 230.7h.1M186.2 231.2h-.6l.2 .2M186.2 231.9h.4l-.4 .6h.4M186.2 230.9v.5M186.2 229.7l-.2 .1M186.8 231.9h.2l.2 .1-.5 .5h.5M187 239.9h.2l.1-.3h-.3v.6"/>
<path d="M187.2 239.9l.1 .3M187.3 238.2h.4l-.2 .3h.2v.3h-.4M187.6 239.6h.2l.1 .1-.4 .5h.4M187.7 231.9h-.3l-.1 .3 .4-.1v.3l-.4 .1M187.9 238.2v.7M188 238.6l.2 .3M188.1 239.6h.3l-.1 .2h.1v.4l-.3-.1M188.2 238.5l-.3 .2M188.5 235.6l.2-.3v.7M188.5 236h.3M189 239.8l-.2 .1-.1-.3h.3v.4l-.2 .2M189 236.5l-.2-.1-.2 .3 .2 .3h.2"/>
<path d="M189.1 235.6v.3h.3M189.3 236.6l.1-.2v.6M189.3 237h.3M189.4 235.6v.4M189.6 235.7h.3M189.8 236.4h.3l-.2 .3h.2v.3h-.3M189.9 235.3h-.3v.7M190.7 236.7l-.2 .2-.1-.4h.3v.4l-.2 .1M192.9 233.6v.5M193.3 238.4l.1 .6 .3-.1v-.5M193.6 233.6v.5l-.3-.5v.5M193.8 234.1l.1-.5 .3 .5"/>
<path d="M193.8 234h.3M193.9 238.5l.2-.1v.6M193.9 239h.4M194.4 233.8v-.2h.1l.2 .1-.3 .2v.2h.3l-.2-.3M194.5 238.5l.3-.1 .1 .1-.5 .5h.5M194.9 233.6h.3l-.3 .5h.3M195 238.5l.4-.1v.2l-.4 .4h.4M195.5 233.6h.3l-.2 .2h.2v.3h-.3M198.8 238.9l.5-.1 .1 .3h-.5zM198.8 238.3l.4-.1 .2 .1v.2h-.6zM198.8 237.7h.5l.1 .3h-.6zM199.3 238.5h.3l.1-.1-.4-.2v.7"/>
<path d="M199.4 239.6h-.6l.2 .1M199.4 239.4v.3M199.4 238.5l.3 .4M199.9 238.3l.2-.1 .2 .2-.4 .5h.4M200.6 238.2l-.2 .4h.5M200.8 238.5v.4M201.2 238.2l.2 .2v.3l-.2 .2-.2-.2v-.3zM108.4 242.4h.4M108.4 243.5h.4M108.6 242.1v.4M109.1 241.9h.3l-.1 .3h.1v.3h-.3M109.1 243.2h.3l-.1 .2 .1 .1v.2h-.3"/>
<path d="M109.7 242.5h.1M109.7 243.7v.1M109.9 241.9h.4l-.2 .3h.2v.3h-.4M109.9 243.2h.4l-.2 .2 .2 .1v.2h-.4M110.4 241.9l.3 .6 .2-.6M110.4 243.2l.3 .6 .2-.6M158.9 240.1v.1M159.5 240.7h-.3l-.1 .1 .1 .5 .3-.1M159.7 240.8l.2-.1v.6M159.7 241.3h.4M160.4 240.6l-.1 .5h.4M160.6 240.8v.5"/>
<path d="M160.9 240.7h.3v.6l-.3-.1z"/>
<circle cx="198.5" cy="83.7" r=".26"/>
<circle cx="12.6" cy="157.5" r=".26"/>
<circle cx="12.6" cy="224.7" r=".26"/>
</g>
<path d="M115.1 213.3h.2l.1 .2-.1 .2h-.2l-.1-.2zM116.3 213.3h.2l.1 .2-.1 .2h-.2l-.1-.2z" fill="none" stroke="#b54549" stroke-width=".2"/>
</svg>
